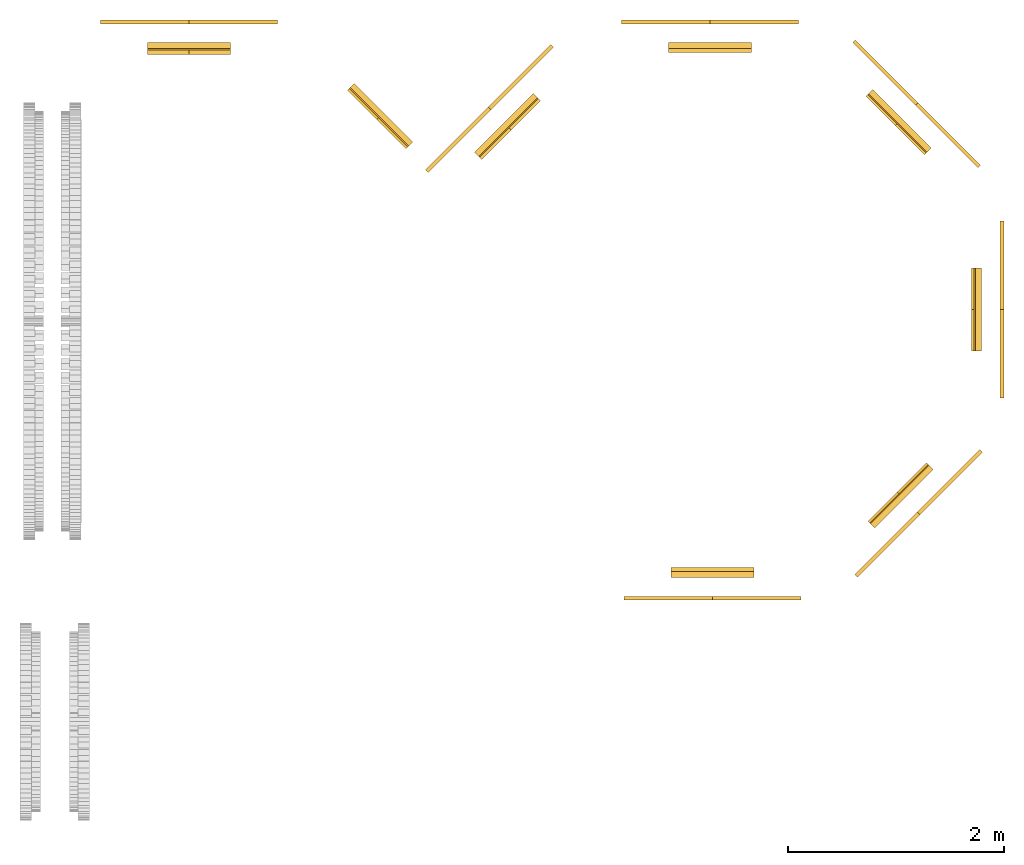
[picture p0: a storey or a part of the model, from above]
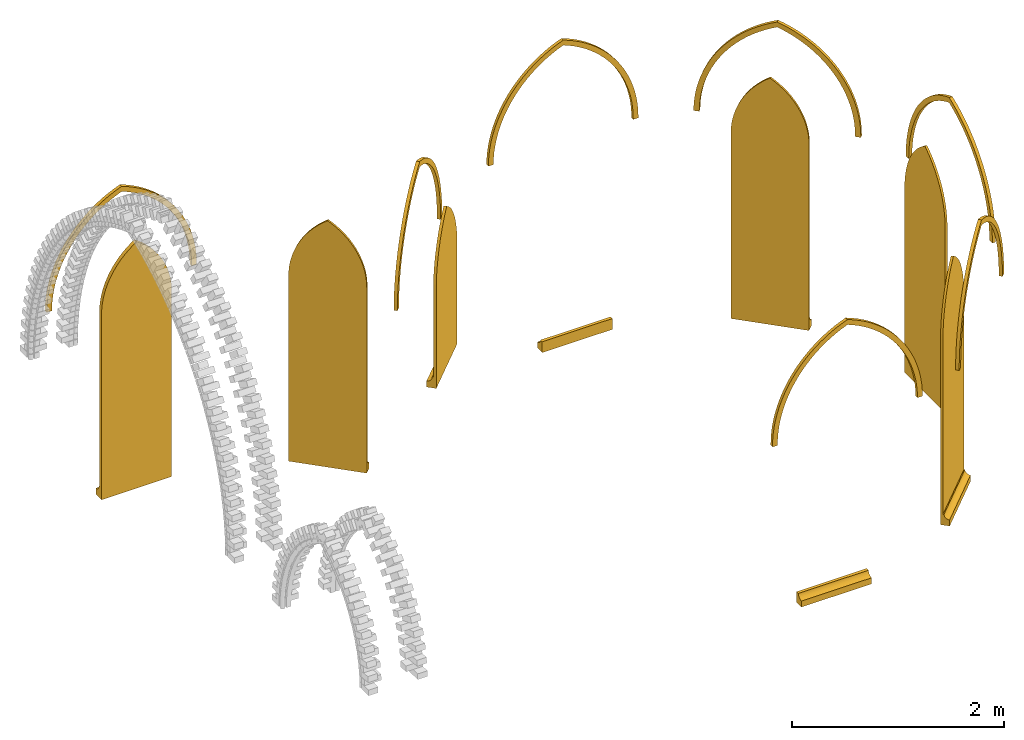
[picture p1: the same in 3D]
Properties of the parts of a building model (IFC2X3), part 1 of 7

# File
Description: ViewDefinition [CoordinationView_V2.0], ExchangeRequirement [Architecture]
File name: Church15_test3_reduced.ifc
Time: 2025-03-05T11:51:33+01:00
Written by: IfcOpenShell 0.8.0
Made in: Bonsai 0.8.0

# IfcProject, 2023_01
LongName: Church 14; Phase: Projekt Status; Document: EBENE 0 NAVE FFL PHASE 1 1864 PLAN; NORTH ELEVATION; PERSPECTIVE; EBENE -1 BASEMENT PHASE 6 PLAN; EBENE 2 GALLERY STAGE 1 PLAN; REFLECTED_PLAN_VIEW; NORTH SECTION; SOUTH SECTION; EAST SECTION; WEST SECTION; PLAN_VIEW

# IfcSite, Default
RefLatitude: 50, 4, 48, 569641; RefLongitude: 8, 14, 45, 631942; RefElevation: 0 m
ID-Daten - Gebäudebezeichnung: Englische Kirche
Sonstige - Auftraggeber: Church of St. Augustine, Wiesbaden; Kategorie: Projektinformationen; Projektadresse: Projektadresse; Projektausgabedatum: Projekt Datum; Projektname: Church 14; Projektnummer: 2023_01; Projektstatus: Projekt Status
Text - Bauherr: Church of St. Augustine; Baustellenort: Wiesbaden; Baustellenstraße: Frankfurter Straße 3; Kundenadresse: Frankfurter Straße 3; Kundenort: Wiesbaden

# IfcSite: Person_Man02_3D:Person_Man02_3D (3)
Material: <Unnamed>; Group: Modellgruppe:BasementChimney:6973904; Built Phase 1 1864
Abhängigkeiten - Ebene: Ebene 0 Nave FFL Phase 1 1864; Verschieben mit umliegenden Elementen: no; Basisbauteil: Ebene : Ebene 0 Nave FFL Phase 1 1864
Phasen - Phase erstellt: Phase 1 1864
Sonstige - Familie: Person_Man02_3D; Familie und Typ: Person_Man02_3D: Person_Man02_3D; Kategorie: Grundstück; Typ: Person_Man02_3D; Typ-ID: 7418376
Daten(Type) - Änderungsdatum: 20131219; Version: 1
ID-Daten(Type) - Typname: Person_Man02_3D
Sonstige(Type) - Kategorie: Grundstück; Familienname: Person_Man02_3D
Name (Person_Man02_3D:Person_Man02_3D:...) | Versatz von Host (m)
7418448 | 0
7684817 | 0
7684845 | 0.6

# IfcBuilding, Englische Kirche
LongName: Englische Kirche
Pset_BuildingCommon - NumberOfStoreys: 7; IsLandmarked: no
ID-Daten - Gebäudebezeichnung: Englische Kirche
Sonstige - Kategorie: Projektinformationen; Auftraggeber: Church of St. Augustine, Wiesbaden; Projektadresse: Projektadresse; Projektausgabedatum: Projekt Datum; Projektname: Church 14; Projektnummer: 2023_01; Projektstatus: Projekt Status
Text - Bauherr: Church of St. Augustine; Baustellenort: Wiesbaden; Baustellenstraße: Frankfurter Straße 3; Kundenadresse: Frankfurter Straße 3; Kundenort: Wiesbaden

# IfcBuildingStorey: Ebene:Ebene (6)
In: Englische Kirche
Pset_AirSideSystemInformation - sets with these values: 2
Pset_BuildingStoreyCommon - AboveGround: no
Sonstige - Familie: Ebene; Familie und Typ: Ebene: Ebene; Kategorie: Ebenen; Typ: Ebene; Typ-ID: 1266143
Abhängigkeiten(Type) - Basishöhe: Projekt-Basispunkt
Grafiken(Type) - Farbe: 16728128; Linienmuster: (Ebene); Linienstärke: 1; Symbol: Beschriftung Ebene Oberkante : Allgemein; Symbol bei Ende 1 Standard: no; Symbol bei Ende 2 Standard: yes
ID-Daten(Type) - Typname: Ebene
Sonstige(Type) - Kategorie: Ebenen; Familienname: Ebene
Name | LongName | Elevation (m) | Pset_AirSideSystemInformation, Name = ID-Daten, Name | Ansicht (m) | Höhe für Berechnung (m) | Tragwerk | Gebäudegeschoss
Ebene -1 Basement Phase 6 | Ebene -1 Basement Phase 6 | -3.075 | Ebene -2 Assumed Foundation | -4 | 0 | no | no
Ebene 0 Nave FFL Phase 1 1864 | Ebene 0 Nave FFL Phase 1 1864 | 0 | Ebene 0 Nave FFL Phase 1 1864 | 0 | 1 | no | yes | Daten - FM Geschoss: EG
Ebene 1 FFL Sacristy | Ebene 1 FFL Sacristy | 0.15 | Ebene 1 FFL Sacristy | 0.15 | 0 | no | yes
Ebene New Gallery Stage 6 | Ebene New Gallery Stage 6 | 3.61 | Ebene New Gallery Stage 6 | 3.61 | 0 | no | yes
Ebene 3 Belfry FFL Stage 2 1888 | Ebene 3 Belfry FFL Stage 2 1888 | 5.11 | Ebene 3 Belfry FFL Stage 2 1888 | 5.11 | 0 | no | yes
Ebene 2 Gallery Stage 1 | Ebene 2 Gallery Stage 1 | 6.75 | Ebene 2 Gallery Stage 1 | 6.75 | 1 | yes | yes | Daten - FM Geschoss: OG 2

# IfcAnnotation: DRAWING (11)
EPset_Drawing - Scale: 1/100; HumanScale: 1:100; HasLinework: yes; HasAnnotation: yes; GlobalReferencing: yes; Stylesheet: drawings/assets/default.css; Markers: drawings/assets/markers.svg; Symbols: drawings/assets/symbols.svg; Patterns: drawings/assets/patterns.svg; ShadingStyles: drawings/assets/shading_styles.json; CurrentShadingStyle: Blender Default
Name | Document | TargetView | HasUnderlay | Group
EBENE 0 NAVE FFL PHASE 1 1864 PLAN | X drawings/EBENE 0 NAVE FFL PHASE 1 1864 PLAN.svg | PLAN_VIEW | yes | EBENE 0 NAVE FFL PHASE 1 1864 PLAN
WEST ELEVATION.001 | X drawings/NORTH ELEVATION.svg | ELEVATION_VIEW | no | NORTH ELEVATION
PERSPECTIVE | X drawings/PERSPECTIVE.svg | MODEL_VIEW | no | PERSPECTIVE
EBENE -1 BASEMENT PHASE 6 PLAN | X drawings/EBENE -1 BASEMENT PHASE 6 PLAN.svg | PLAN_VIEW | yes | EBENE -1 BASEMENT PHASE 6 PLAN
EBENE 2 GALLERY STAGE 1 PLAN | X drawings/EBENE 2 GALLERY STAGE 1 PLAN.svg | PLAN_VIEW | no | EBENE 2 GALLERY STAGE 1 PLAN
REFLECTED_PLAN_VIEW | X drawings/REFLECTED_PLAN_VIEW.svg | REFLECTED_PLAN_VIEW | no | REFLECTED_PLAN_VIEW
NORTH SECTION | X drawings/NORTH SECTION.svg | SECTION_VIEW | no | NORTH SECTION
SOUTH SECTION | X drawings/SOUTH SECTION.svg | SECTION_VIEW | no | SOUTH SECTION
EAST SECTION | X drawings/EAST SECTION.svg | SECTION_VIEW | no | EAST SECTION
WEST SECTION | X drawings/WEST SECTION.svg | SECTION_VIEW | no | WEST SECTION
PLAN_VIEW | X drawings/PLAN_VIEW.svg | PLAN_VIEW | no | PLAN_VIEW

# IfcBuildingElementProxy: BasementLightwell:BasementLightwell (3)
In: Ebene -1 Basement Phase 6
Type - Material: <Unnamed>, Ortbeton - bewehrt (4)
Type - Abhängigkeiten - Vorgabe-Ansicht: 0 m
Type - Bemaßungen - CoverThickness: 0.05 m; SlabThickness: 0.15 m; WallThickness: 0.155 m; WellDepth: 0.85 m; WellLength: 1.89 m
Type - ID-Daten - Typname: BasementLightwell
Type - Materialien und Oberflächen - WellMaterial: Ortbeton - bewehrt
Type - Sonstige - Kategorie: Allgemeines Modell; Familienname: BasementLightwell
Pset_BuildingElementProxyCommon - Reference: BasementLightwell; sets with these values: 2
Pset_ProvisionForVoid - Width: 2.2 m; Height: 0.955 m; Depth: 0.15 m
Abhängigkeiten - Ebene: Foundation Wall Cap; Verschieben mit umliegenden Elementen: no
Bemaßungen - Breite: 1 m; Fläche: 8.435 m2; Länge: 2.08 m; Volumen: 0.8914 m3
Phasen - Phase erstellt: Phase 6 1966
Sonstige - Familie: BasementLightwell; Familie und Typ: BasementLightwell: BasementLightwell; Host-ID: 2621152; Typ: BasementLightwell; Typ-ID: 7719407
Name (BasementLightwell:BasementLightwell:...) | Material
7719432
7725785 | <Unnamed>, Ortbeton - bewehrt
7726030 | <Unnamed>, Ortbeton - bewehrt

# IfcBuildingElementProxy: LinedSquareOpening:945x1980, LinedSquareOpening:945x1980:5573793
In: Ebene -1 Basement Phase 6
Type - Material: <Unnamed> (3)
Type - Abhängigkeiten(Type) - Vorgabe-Ansicht: 0 m
Type - Bemaßungen(Type) - FrontEdgeSetback: 0.03 m; OpeningWidth: 0.945 m; RearEdgeSetback: 0.03 m; SideLiningThickness: 0.06 m; SpringingHeight: 1.98 m; TopLiningThickness: 0.08 m
Type - ID-Daten(Type) - Typname: 945x1980
Type - Sonstige(Type) - Kategorie: Allgemeines Modell; Familienname: LinedSquareOpening
Pset_BuildingElementProxyCommon - Reference: 945x1980; sets with these values: 2
Pset_ProvisionForVoid - Shape: Rectangle; Width: 1.98 m; Height: 1.065 m; Depth: 1.9 m
Abhängigkeiten - Ebene: Ebene -1 Basement Phase 6; Höhe von Ebene: 0 m
Bemaßungen - Fläche: 0.5158 m2; Volumen: 0.012528 m3
Phasen - Phase erstellt: Phase 7 2019
Sonstige - Kategorie: Allgemeines Modell; Familie: LinedSquareOpening; Familie und Typ: LinedSquareOpening: 945x1980; Host-ID: 2555536; Typ: 945x1980; Typ-ID: 5573766

# IfcBuildingElementProxy: PierCorbel:PierCorbel 780 (5)
In: Ebene New Gallery Stage 6
Type - Material: Mauerwerk - Sandstein Rot
Type - Abhängigkeiten - Vorgabe-Ansicht: 0 m
Type - Bemaßungen - CorbelBreite: 0.78 m
Type - ID-Daten - Typname: PierCorbel 780
Type - Materialien und Oberflächen - CorbelMaterial: Mauerwerk - Sandstein Rot
Type - Sonstige - Kategorie: Allgemeines Modell; Familienname: PierCorbel
Pset_BuildingElementProxyCommon - Reference: PierCorbel 780; sets with these values: 2
Pset_ProvisionForVoid - Depth: 0.78 m
Abhängigkeiten - Höhe von Ebene: 0 m; Verschieben mit umliegenden Elementen: no; Versatz von Host: 0 m; Basisbauteil: Ebene : East Buttress Pier Cap Underside; Ebene: East Buttress Pier Cap Underside
Bemaßungen - Fläche: 0.657237 m2; Volumen: 0.0666393 m3
Sonstige - Familie: PierCorbel; Familie und Typ: PierCorbel: PierCorbel 780; Typ: PierCorbel 780; Typ-ID: 5213824
Name (PierCorbel:PierCorbel 780:...) | Phase erstellt | Group
5410019 | Phase 2 1888 | Built Phase 2 1888
6971017 | Phase 7 2019
6971034 | Phase 7 2019
7248189 | Phase 2 1888 | Built Phase 2 1888
7606754 | Phase 2 1888 | Built Phase 2 1888

# IfcBuildingElementProxy: Profilierte Wand:moulding1-Dado (13)
In: Ebene -1 Basement Phase 6
Type - Abhängigkeiten - Entlang eingefügter Elemente schneiden: no; Schneidet Wand: yes; Standardrücksprung: 0 m
Type - ID-Daten - Typname: moulding1-Dado
Type - Konstruktion - Profil: Mouldings : Moulding1
Type - Materialien und Oberflächen - Material: Mauerwerk - Sandstein Rot
Type - Sonstige - Kategorie: Wände: Profilierte Wände; Familienname: Profilierte Wand
Pset_BuildingElementProxyCommon - Reference: moulding1-Dado; sets with these values: 2
Sonstige - Familie: Profilierte Wand; Familie und Typ: Profilierte Wand: moulding1-Dado; Typ: moulding1-Dado; Typ-ID: 2478616
Name (Profilierte Wand:moulding1-Dado:...) | Shape | Depth (m) | Ebene | Versatz von Wand (m) | Versatz von Ebene (m) | Länge (m) | Phase erstellt | Group
3293627 | Undefined | 0.679767 | Foundation Wall Cap | 0 | 1.85 | 0.679767 | Phase 1 1864 | Modellgruppe:BasementChimney:6973904; Built Phase 1 1864
3350023 | Undefined | 0.820746 | Foundation Wall Cap | 0 | 1.85 | 0.820746 | Phase 2 1888 | Built Phase 2 1888
3350297 |  |  | Foundation Wall Cap | 0 | 1.85 | 0.802678 | Phase 2 1888 | Built Phase 2 1888
3842606 | Undefined | 2.4785 | Ebene -2 Assumed Foundation | 0.329921 | 12.7142 | 2.4785 | Phase 2 1888 | Built Phase 2 1888
3843715 | Undefined | 3.285 | Ebene -2 Assumed Foundation | 0 | 12.714 | 3.285 | Phase 2 1888 | Built Phase 2 1888
5171951 | Undefined | 0.652471 | Foundation Wall Cap | 0 | 1.85 | 0.652471 | Phase 1 1864 | Modellgruppe:BasementChimney:6973904; Built Phase 1 1864
5440317 | Undefined | 0.683273 | Foundation Wall Cap | 0 | 1.85 | 0.683273 | Phase 2 1888 | Built Phase 2 1888
5468029 |  |  | Foundation Wall Cap | 0 | 1.85 | 0.37 | Phase 2 1888 | Built Phase 2 1888
5469648 | Undefined | 0.78 | Foundation Wall Cap | 0 | 1.83126 | 0.78 | Phase 2 1888 | Built Phase 2 1888
6261976 | Rectangle | 0.78 | Foundation Wall Cap | 0 | 1.85 | 0.78 | Phase 2 1888 | Built Phase 2 1888
6326100 | Rectangle | 0.964989 | Foundation Wall Cap | 0 | 1.85 | 0.964989 | Phase 2 1888 | Built Phase 2 1888
6379899 | Rectangle | 0.522744 | Foundation Wall Cap | 0 | 9.314 | 0.522744 | Phase 2 1888 | Built Phase 2 1888
6441138 | Rectangle | 0.522744 | Foundation Wall Cap | 0 | 9.314 | 0.522744 | Phase 6 1966

# IfcBuildingElementProxy: Profilierte Wand:moulding1-Dado 2, Profilierte Wand:moulding1-Dado 2:5211551
In: Ebene -1 Basement Phase 6
Type - Abhängigkeiten - Entlang eingefügter Elemente schneiden: no; Schneidet Wand: yes; Standardrücksprung: 0 m
Type - ID-Daten - Typname: moulding1-Dado 2
Type - Konstruktion - Profil: Testmouldingdeep : Testmouldingdeep
Type - Materialien und Oberflächen - Material: Mauerwerk - Sandstein Rot
Type - Sonstige - Kategorie: Wände: Profilierte Wände; Familienname: Profilierte Wand
Pset_BuildingElementProxyCommon - Reference: moulding1-Dado 2; sets with these values: 2
Pset_ProvisionForVoid - Shape: Undefined; Depth: 0.5185 m
Abhängigkeiten - Ebene: Foundation Wall Cap; Versatz von Wand: 0 m; Versatz von Ebene: 9.40503 m
Bemaßungen - Länge: 0.5185 m
Phasen - Phase erstellt: Phase 1 1864
Sonstige - Familie: Profilierte Wand; Familie und Typ: Profilierte Wand: moulding1-Dado 2; Typ: moulding1-Dado 2; Typ-ID: 3154429
Group: Modellgruppe:BasementChimney:6973904; Built Phase 1 1864

# IfcBuildingElementProxy: Profilierte Wand:moulding1-Dado brick Stage 2 (3)
In: Ebene -1 Basement Phase 6
Type - Abhängigkeiten - Entlang eingefügter Elemente schneiden: no; Schneidet Wand: yes; Standardrücksprung: 0 m
Type - ID-Daten - Typname: moulding1-Dado brick Stage 2
Type - Konstruktion - Profil: Mouldings : Moulding1
Type - Materialien und Oberflächen - Material: Mauerwerk - Sichtmauerwerk_72x265 header Stage2
Type - Sonstige - Kategorie: Wände: Profilierte Wände; Familienname: Profilierte Wand
Pset_BuildingElementProxyCommon - Reference: moulding1-Dado brick Stage 2; sets with these values: 2
Abhängigkeiten - Ebene: Foundation Wall Cap; Versatz von Wand: 0 m; Versatz von Ebene: 1.85 m
Phasen - Phase erstellt: Phase 2 1888
Sonstige - Familie: Profilierte Wand; Familie und Typ: Profilierte Wand: moulding1-Dado brick Stage 2; Typ: moulding1-Dado brick Stage 2; Typ-ID: 3503855
Group: Built Phase 2 1888
Name (Profilierte Wand:moulding1-Dado brick Stage 2:...) | Länge (m)
3491269 | 2.18352
3504058 | 1.68025 | Pset_ProvisionForVoid - Shape: Undefined; Depth: 1.68025 m
6983100 | 2.44361

# IfcBuildingElementProxy: Profilierte Wand:plinth (39)
In: Ebene -1 Basement Phase 6
Type - Abhängigkeiten - Entlang eingefügter Elemente schneiden: no; Schneidet Wand: yes; Standardrücksprung: 0 m
Type - ID-Daten - Typname: plinth
Type - Konstruktion - Profil: Plinth profile : plinth
Type - Materialien und Oberflächen - Material: Mauerwerk - Sandstein Rot
Type - Sonstige - Kategorie: Wände: Profilierte Wände; Familienname: Profilierte Wand
Pset_BuildingElementProxyCommon - Reference: plinth; sets with these values: 2
Abhängigkeiten - Versatz von Wand: 0 m
Sonstige - Familie: Profilierte Wand; Familie und Typ: Profilierte Wand: plinth; Typ: plinth; Typ-ID: 2475856
Name (Profilierte Wand:plinth:...) | Ebene | Versatz von Ebene (m) | Länge (m) | Phase erstellt | Group
2477548 | Foundation Wall Cap | 0.505 | 3.38424 | Phase 1 1864 | Modellgruppe:BasementChimney:6973904; Built Phase 1 1864
2720928 | Plinth moulding Underside | 0 | 0.445057 | Phase 2 1888 | Built Phase 2 1888
2890806 | Foundation Wall Cap | 0.505 | 1.82 | Phase 2 1888 | Built Phase 2 1888
3022505 | Foundation Wall Cap | 0.505 | 1.81 | Phase 1 1864 | Modellgruppe:BasementChimney:6973904; Built Phase 1 1864
3022587 | Foundation Wall Cap | 0.505 | 0.78 | Phase 1 1864 | Modellgruppe:BasementChimney:6973904; Built Phase 1 1864
3038055 | Foundation Wall Cap | 0.505 | 0.456454 | Phase 1 1864 | Modellgruppe:BasementChimney:6973904; Built Phase 1 1864
3154773 | Foundation Wall Cap | 0.505 | 0.693949 | Phase 1 1864 | Modellgruppe:BasementChimney:6973904; Built Phase 1 1864
3256990 | Foundation Wall Cap | 0.505 | 1.03 | Phase 1 1864 | Modellgruppe:BasementChimney:6973904; Built Phase 1 1864
3257177 | Foundation Wall Cap | 0.505 | 0.78 | Phase 1 1864 | Modellgruppe:BasementChimney:6973904; Built Phase 1 1864
3257415 | Foundation Wall Cap | 0.505 | 1.42 | Phase 1 1864 | Modellgruppe:BasementChimney:6973904; Built Phase 1 1864
3257546 | Foundation Wall Cap | 0.505 | 0.425 | Phase 1 1864 | Modellgruppe:BasementChimney:6973904; Built Phase 1 1864
3257552 | Foundation Wall Cap | 0.505 | 0.424 | Phase 1 1864 | Modellgruppe:BasementChimney:6973904; Built Phase 1 1864
3257558 | Foundation Wall Cap | 0.505 | 0.36 | Phase 1 1864 | Modellgruppe:BasementChimney:6973904; Built Phase 1 1864
3261107 | Foundation Wall Cap | 0.505 | 1.00087 | Phase 1 1864 | Modellgruppe:BasementChimney:6973904; Built Phase 1 1864
3265432 | Foundation Wall Cap | 0.505 | 1.69682 | Phase 1 1864 | Modellgruppe:BasementChimney:6973904; Built Phase 1 1864
3266623 | Foundation Wall Cap | 0.505 | 0.699648 | Phase 1 1864 | Modellgruppe:BasementChimney:6973904; Built Phase 1 1864
3266629 | Foundation Wall Cap | 0.505 | 0.76 | Phase 1 1864 | Modellgruppe:BasementChimney:6973904; Built Phase 1 1864
3288775 | Foundation Wall Cap | 0.505 | 0.707719 | Phase 1 1864 | Modellgruppe:BasementChimney:6973904; Built Phase 1 1864
3288781 | Foundation Wall Cap | 0.505 | 1.68262 | Phase 1 1864 | Modellgruppe:BasementChimney:6973904; Built Phase 1 1864
3289366 | Foundation Wall Cap | 0.505 | 0.76 | Phase 1 1864 | Modellgruppe:BasementChimney:6973904; Built Phase 1 1864
3292115 | Foundation Wall Cap | 0.505 | 0.687711 | Phase 1 1864 | Modellgruppe:BasementChimney:6973904; Built Phase 1 1864
3292251 | Plinth moulding Underside | 0 | 1.68739 | Phase 1 1864 | Modellgruppe:BasementChimney:6973904; Built Phase 1 1864
3292386 | Plinth moulding Underside | 0 | 0.708381 | Phase 1 1864 | Modellgruppe:BasementChimney:6973904; Built Phase 1 1864
3292464 | Plinth moulding Underside | 0 | 0.76 | Phase 1 1864 | Modellgruppe:BasementChimney:6973904; Built Phase 1 1864
3292675 | Plinth moulding Underside | 0 | 0.670403 | Phase 1 1864 | Modellgruppe:BasementChimney:6973904; Built Phase 1 1864
3292976 | Plinth moulding Underside | 0 | 1.4298 | Phase 1 1864 | Modellgruppe:BasementChimney:6973904; Built Phase 1 1864
3293215 | Foundation Wall Cap | 0.505 | 0.780178 | Phase 1 1864 | Modellgruppe:BasementChimney:6973904; Built Phase 1 1864
3293221 | Plinth moulding Underside | 0 | 1.03 | Phase 1 1864 | Modellgruppe:BasementChimney:6973904; Built Phase 1 1864
3293227 | Plinth moulding Underside | 0 | 0.97983 | Phase 1 1864 | Modellgruppe:BasementChimney:6973904; Built Phase 1 1864
3493945 | Foundation Wall Cap | 0.505 | 3.935 | Phase 2 1888 | Built Phase 2 1888
3493989 | Foundation Wall Cap | 0.505 | 0.78 | Phase 2 1888 | Built Phase 2 1888
3493995 | Foundation Wall Cap | 0.505 | 1.03 | Phase 2 1888 | Built Phase 2 1888
4251157 | Foundation Wall Cap | 0.505 | 0.755 | Phase 1 1864 | Modellgruppe:BasementChimney:6973904; Built Phase 1 1864
4251164 | Foundation Wall Cap | 0.505 | 0.456454 | Phase 1 1864 | Modellgruppe:BasementChimney:6973904; Built Phase 1 1864
5144821 | Foundation Wall Cap | 0.505 | 1.43 | Phase 1 1864 | Modellgruppe:BasementChimney:6973904; Built Phase 1 1864
5416097 | Foundation Wall Cap | 0.505 | 1.02731 | Phase 2 1888 | Built Phase 2 1888
5416720 | Foundation Wall Cap | 0.505 | 0.817988 | Phase 2 1888 | Built Phase 2 1888
5437947 | Foundation Wall Cap | 0.505 | 0.726012 | Phase 2 1888 | Built Phase 2 1888
7228845 | Plinth moulding Underside | 0 | 1.00925 | Phase 1 1864 | Modellgruppe:BasementChimney:6973904; Built Phase 1 1864

# IfcBuildingElementProxy: Profilierte Wand:plinth brick header (29)
In: Ebene -1 Basement Phase 6
Type - Abhängigkeiten - Entlang eingefügter Elemente schneiden: no; Schneidet Wand: yes; Standardrücksprung: 0 m
Type - ID-Daten - Typname: plinth brick header
Type - Konstruktion - Profil: Plinth profile : plinth
Type - Materialien und Oberflächen - Material: Mauerwerk - Sichtmauerwerk_72x265 header Stage2
Type - Sonstige - Kategorie: Wände: Profilierte Wände; Familienname: Profilierte Wand
Pset_BuildingElementProxyCommon - Reference: plinth brick header; sets with these values: 2
Phasen - Phase erstellt: Phase 2 1888
Sonstige - Familie: Profilierte Wand; Familie und Typ: Profilierte Wand: plinth brick header; Typ: plinth brick header; Typ-ID: 5467336
Group: Built Phase 2 1888
Name (Profilierte Wand:plinth brick header:...) | Versatz von Wand (m) | Ebene | Versatz von Ebene (m) | Länge (m)
2580270 | 0 | Plinth moulding Underside | 0 | 0.713
2580488 | 0 | Foundation Wall Cap | 0.505 | 0.651
2609190 | 0 | Plinth moulding Underside | 0 | 0.6065
2717564 | 0 | Plinth moulding Underside | 0 | 1.5659
3470122 | 0 | Plinth moulding Underside | 0 | 1.53925
3489360 | 0 | Plinth moulding Underside | 0 | 1.63956
3489601 | 0.0025 | Foundation Wall Cap | 0.505 | 0.668766
3489795 | 0.00249463 | Plinth moulding Underside | 0 | 0.668766
3489802 | 0 | Foundation Wall Cap | 0.505 | 0.651
3489808 | 0.00250457 | Foundation Wall Cap | 0.505 | 0.677564
3489814 | 0 | Foundation Wall Cap | 0.505 | 1.54413
3490135 | -0.00161688 | Foundation Wall Cap | 0.505 | 0.667564
3490291 | 0 | Foundation Wall Cap | 0.505 | 0.662564
3490297 | 0 | Foundation Wall Cap | 0.505 | 1.60782
3490319 | 0 | Foundation Wall Cap | 0.505 | 0.715817
3490465 | 0 | Foundation Wall Cap | 0.505 | 0.651
3490515 | 0.0025 | Foundation Wall Cap | 0.505 | 0.755603
4197462 | 0.00249183 | Foundation Wall Cap | 0.505 | 0.677564
5486545 | 0 | Foundation Wall Cap | 0.505 | 0.650966
7054224 | 0 | Plinth moulding Underside | 0 | 0.438
7055686 | 0 | Plinth moulding Underside | 0 | 0.642
7055712 | 0 | Plinth moulding Underside | 0 | 0.651
7055718 | 0 | Plinth moulding Underside | 0 | 0.714488
7061094 | 0 | Plinth moulding Underside | 0 | 0.651
7061100 | 0 | Plinth moulding Underside | 0 | 0.708
7061186 | 0 | Plinth moulding Underside | 0 | 0.64
7074078 | 0 | Foundation Wall Cap | 0.505 | 1.61191
7074116 | 0 | Plinth moulding Underside | 0 | 1.55821
7229687 | 0 | Plinth moulding Underside | 0 | 0.651

# IfcBuildingElementProxy: SimpleVault:SimpleVault Tower, SimpleVault:SimpleVault Tower:5528813
In: Ebene -1 Basement Phase 6
Type - Material: Mauerwerk - Sichtmauerwerk_72x265 english bond Stage2
Type - Abhängigkeiten - Vorgabe-Ansicht: 0 m
Type - Bemaßungen - OverallHeight: 0.5 m; SideWidth: 1.68 m; SideWidth2: 1.68 m; VaultLength: 2.35 m; VaultRadius: 2.39 m; VaultWidth: 2.365 m
Type - ID-Daten - Typname: SimpleVault Tower
Type - Materialien und Oberflächen - VaultMaterial: Mauerwerk - Sichtmauerwerk_72x265 english bond Stage2
Type - Sonstige - Kategorie: Allgemeines Modell; Familienname: SimpleVault
Pset_BuildingElementProxyCommon - Reference: SimpleVault Tower; sets with these values: 2
Abhängigkeiten - Ebene: Ebene -1 Basement Phase 6; Verschieben mit umliegenden Elementen: no; Basisbauteil: Geschossdecke : STB 200 Basement Kitchen Floor; Höhe von Ebene: 2.42823 m; Versatz von Host: 2.42823 m
Bemaßungen - Fläche: 7.0779 m2; Volumen: 1.50176 m3
Phasen - Phase erstellt: Phase 2 1888
Sonstige - Familie: SimpleVault; Familie und Typ: SimpleVault: SimpleVault Tower; Typ: SimpleVault Tower; Typ-ID: 5528982
Group: Built Phase 2 1888

# IfcBuildingElementProxy: SpiralSteps:SpiralSteps, SpiralSteps:SpiralSteps:4031563
In: Ebene 0 Nave FFL Phase 1 1864
Type - Material: <Unnamed> (108)
Type - Abhängigkeiten - Vorgabe-Ansicht: 0 m
Type - Bemaßungen - RiserHeight: 0.25 m
Type - ID-Daten - Typname: SpiralSteps
Type - Sonstige - Kategorie: Allgemeines Modell; Familienname: SpiralSteps
Pset_BuildingElementProxyCommon - Reference: SpiralSteps; sets with these values: 2
Pset_ProvisionForVoid - Depth: 0.25 m
Abhängigkeiten - Ebene: Ebene 0 Nave FFL Phase 1 1864; Höhe von Ebene: 0 m; Verschieben mit umliegenden Elementen: no; Versatz von Host: 0 m; Basisbauteil: Ebene : Ebene 0 Nave FFL Phase 1 1864
Bemaßungen - Fläche: 20.1719 m2; Volumen: 0.501697 m3
Phasen - Phase erstellt: Phase 1 1864; Phase abgebrochen: Phase 6 1966
Sonstige - Familie: SpiralSteps; Familie und Typ: SpiralSteps: SpiralSteps; Typ: SpiralSteps; Typ-ID: 4031511
Group: Modellgruppe:BasementChimney:6973904; Built Phase 1 1864

# IfcBuildingElementProxy: Tower_finial:Tower_finial (4)
In: Ebene 0 Nave FFL Phase 1 1864
Type - Material: Mauerwerk - Sandstein Rot, Mauerwerk - Sichtmauerwerk_72x265 english bond Stage2
Type - Abhängigkeiten - Vorgabe-Ansicht: 0 m
Type - Bemaßungen - Depth: 0.5 m; HeightBrickwork: 1.295 m; Width: 0.5 m
Type - ID-Daten - Typname: Tower_finial
Type - Materialien und Oberflächen - BrickworkMaterial: Mauerwerk - Sichtmauerwerk_72x265 english bond Stage2; StoneworkMaterial: Mauerwerk - Sandstein Rot
Type - Sonstige - Kategorie: Allgemeines Modell; Familienname: Tower_finial
Type - Pset_ProvisionForVoid - Width: 0.5 m; Depth: 0.5 m
Pset_BuildingElementProxyCommon - Reference: Tower_finial; sets with these values: 2
Pset_ProvisionForVoid - Width: 0.1524 m; Height: 0.5 m
Abhängigkeiten - Ebene: Ebene 0 Nave FFL Phase 1 1864; Verschieben mit umliegenden Elementen: no; Basisbauteil: Ebene : Ebene 0 Nave FFL Phase 1 1864; Höhe von Ebene: 15.594 m; Versatz von Host: 15.594 m
Bemaßungen - Fläche: 2.76293 m2; Volumen: 0.565732 m3
Phasen - Phase erstellt: Phase 2 1888
Sonstige - Familie: Tower_finial; Familie und Typ: Tower_finial: Tower_finial; Typ: Tower_finial; Typ-ID: 7803290
Group: Built Phase 2 1888
Name (Tower_finial:Tower_finial:...)
7804210
7804757
7804760
7804762

# IfcBuildingElementProxy: Vault_1:Vault_1, Vault_1:Vault_1:7986884
In: Ebene 0 Nave FFL Phase 1 1864
Type - Material: <Unnamed> (14)
Type - Abhängigkeiten - Vorgabe-Ansicht: 0 m
Type - ID-Daten - Typname: Vault_1
Type - Sonstige - Kategorie: Allgemeines Modell; Familienname: Vault_1
Pset_BuildingElementProxyCommon - Reference: Vault_1; sets with these values: 2
Abhängigkeiten - Ebene: Ebene 0 Nave FFL Phase 1 1864; Verschieben mit umliegenden Elementen: no; Basisbauteil: Ebene : Ebene 0 Nave FFL Phase 1 1864; Höhe von Ebene: 2.56 m; Versatz von Host: 2.56 m
Bemaßungen - Fläche: 25.9017 m2; SpringingHeight: 2.7 m; VaultWidth: 2.5 m; Volumen: 2.04915 m3
Phasen - Phase erstellt: Phase 1 1864
Sonstige - Familie: Vault_1; Familie und Typ: Vault_1: Vault_1; Typ: Vault_1; Typ-ID: 7986406
Group: Modellgruppe:BasementChimney:6973904; Built Phase 1 1864

# IfcBuildingElementProxy: VergeCopingEnd:VergeCopingEnd (3)
In: Ebene 2 Gallery Stage 1
Type - Material: Mauerwerk - Sandstein Rot
Type - Abhängigkeiten - Vorgabe-Ansicht: 0 m
Type - Bemaßungen - CopingHeight: 0.3 m; CopingWidth: 1.36 m
Type - ID-Daten - Typname: VergeCopingEnd
Type - Materialien und Oberflächen - VergeCoping: Mauerwerk - Sandstein Rot
Type - Sonstige - Kategorie: Allgemeines Modell; Familienname: VergeCopingEnd
Pset_BuildingElementProxyCommon - Reference: VergeCopingEnd; sets with these values: 2
Abhängigkeiten - Verschieben mit umliegenden Elementen: no; Ebene: Eaves corner pier top; Basisbauteil: Ebene : Eaves corner pier top
Bemaßungen - Fläche: 1.77369 m2; Volumen: 0.277278 m3
Phasen - Phase erstellt: Phase 1 1864
Sonstige - Familie: VergeCopingEnd; Familie und Typ: VergeCopingEnd: VergeCopingEnd; Typ: VergeCopingEnd; Typ-ID: 5252002
Group: Modellgruppe:BasementChimney:6973904; Built Phase 1 1864
Name (VergeCopingEnd:VergeCopingEnd:...) | Höhe von Ebene (m) = Versatz von Host (m)
6982375 | -0.00160627
6983242 | 0
6983282 | 0

# IfcBuildingElementProxy: WallCorbelStage2:WallCorbelStage2 (3)
In: Ebene 0 Nave FFL Phase 1 1864
Type - Material: Quoin Brick (9)
Type - Abhängigkeiten - Vorgabe-Ansicht: 0 m
Type - Bemaßungen - BreitePilaster: 0.52 m; HoeheUKCorbel: 3.534 m
Type - ID-Daten - Typname: WallCorbelStage2
Type - Materialien und Oberflächen - CorbelMaterial: Quoin Brick
Type - Sonstige - Kategorie: Allgemeines Modell; Familienname: WallCorbelStage2
Pset_BuildingElementProxyCommon - Reference: WallCorbelStage2; sets with these values: 2
Pset_ProvisionForVoid - Width: 0.56 m; Height: 0.08 m; Depth: 0.072 m
Abhängigkeiten - Ebene: Ebene 0 Nave FFL Phase 1 1864; Verschieben mit umliegenden Elementen: no; Höhe von Ebene: 0.228 m; Versatz von Host: 0.228 m
Bemaßungen - Fläche: 1.60413 m2; Volumen: 0.0672083 m3
Phasen - Phase erstellt: Phase 2 1888
Sonstige - Familie: WallCorbelStage2; Familie und Typ: WallCorbelStage2: WallCorbelStage2; Typ: WallCorbelStage2; Typ-ID: 4388655
Group: Built Phase 2 1888
Name (WallCorbelStage2:WallCorbelStage2:...) | Basisbauteil | Material
4389294 | Ebene : Ebene 0 Nave FFL Phase 1 1864
4389487 | Geschossdecke : Tiled Marble onto screed 203x203 black and white diagonal | Quoin Brick
5518495 | Ebene : Ebene 0 Nave FFL Phase 1 1864 | Quoin Brick

# IfcBuildingElementProxy: basementWindow1:1810x1200, basementWindow1:1810x1200:5571185
In: Ebene -1 Basement Phase 6
Type - Material: <Unnamed> (3)
Type - Abhängigkeiten(Type) - Vorgabe-Ansicht: 0 m
Type - Bemaßungen(Type) - ArchitraveWidth: 0.02 m; CillHeight: 1 m; LintelHeight: 2 m; OpeningWidth: 1.81 m; RenderCoat: 0.005 m; RevealOffset: 0.03 m
Type - ID-Daten(Type) - Typname: 1810x1200
Type - Sonstige(Type) - Kategorie: Allgemeines Modell; Familienname: basementWindow1
Pset_BuildingElementProxyCommon - Reference: 1810x1200; sets with these values: 2
Pset_ProvisionForVoid - Shape: Rectangle; Width: 1 m; Height: 1.81 m
Abhängigkeiten - Ebene: Ebene -1 Basement Phase 6; Höhe von Ebene: 1.54 m
Bemaßungen - ClearWidth: 1.8 m; Fläche: 2.7723 m2; Volumen: 0.031932 m3
Phasen - Phase erstellt: Phase 6 1966
Sonstige - Kategorie: Allgemeines Modell; Familie: basementWindow1; Familie und Typ: basementWindow1: 1810x1200; Host-ID: 6989205; Typ: 1810x1200; Typ-ID: 5618222

# IfcBuildingElementProxy: basementWindow1:1810x1310, basementWindow1:1810x1310:5571416
In: Ebene -1 Basement Phase 6
Type - Material: <Unnamed> (3)
Type - Abhängigkeiten(Type) - Vorgabe-Ansicht: 0 m
Type - Bemaßungen(Type) - ArchitraveWidth: 0.02 m; CillHeight: 1 m; LintelHeight: 2.22 m; OpeningWidth: 1.81 m; RenderCoat: 0.002 m; RevealOffset: 0.03 m
Type - ID-Daten(Type) - Typname: 1810x1310
Type - Sonstige(Type) - Kategorie: Allgemeines Modell; Familienname: basementWindow1
Pset_BuildingElementProxyCommon - Reference: 1810x1310; sets with these values: 2
Pset_ProvisionForVoid - Shape: Rectangle; Width: 1.22 m; Height: 1.814 m
Abhängigkeiten - Ebene: Ebene -1 Basement Phase 6; Höhe von Ebene: 1.5 m
Bemaßungen - ClearWidth: 1.81 m; Fläche: 3.25956 m2; Volumen: 0.0286552 m3
Phasen - Phase erstellt: Phase 6 1966
Sonstige - Kategorie: Allgemeines Modell; Familie: basementWindow1; Host-ID: 6989205; Familie und Typ: basementWindow1: 1810x1310; Typ: 1810x1310; Typ-ID: 5571433

# IfcBuildingElementProxy: basementWindow1:1930x1310, basementWindow1:1930x1310:5575437
In: Ebene -1 Basement Phase 6
Type - Material: <Unnamed> (3)
Type - Abhängigkeiten(Type) - Vorgabe-Ansicht: 0 m
Type - Bemaßungen(Type) - ArchitraveWidth: 0.02 m; CillHeight: 1 m; LintelHeight: 2.218 m; OpeningWidth: 1.95 m; RenderCoat: 0.005 m; RevealOffset: 0.03 m
Type - ID-Daten(Type) - Typname: 1930x1310
Type - Sonstige(Type) - Kategorie: Allgemeines Modell; Familienname: basementWindow1
Pset_BuildingElementProxyCommon - Reference: 1930x1310; sets with these values: 2
Pset_ProvisionForVoid - Shape: Rectangle; Width: 1.218 m; Height: 1.81 m
Abhängigkeiten - Ebene: Ebene -1 Basement Phase 6; Höhe von Ebene: 1.525 m
Bemaßungen - ClearWidth: 1.8 m; Fläche: 3.26716 m2; Volumen: 0.0358342 m3
Phasen - Phase erstellt: Phase 6 1966
Sonstige - Kategorie: Allgemeines Modell; Familie: basementWindow1; Host-ID: 6989205; Familie und Typ: basementWindow1: 1930x1310; Typ: 1930x1310; Typ-ID: 5580078

# IfcColumn: AisleColumn:AisleColumn, AisleColumn:AisleColumn:4320104
In: Ebene 0 Nave FFL Phase 1 1864
Type - PredefinedType: COLUMN; Material: Mauerwerk - Sandstein Rot (5), Quoin Brick
Type - Bemaßungen - Breite: 0.65 m; HoeheCapital: 0.625 m; HoeheLowerBase: 0.22 m; HoeheUKCapital: 3.64 m; HoeheUpperBase: 0.16 m; RadiusColumn: 0.26 m; Tiefe: 0.65 m
Type - Grafiken - Farbfüllung für groben Maßstab: 0
Type - ID-Daten - OmniClass-Nummer: 23.25.30.11.14.11; OmniClass-Titel: Columns; Typname: AisleColumn
Type - Materialien und Oberflächen - ColumnCapMaterial: Quoin Brick; ColumnMaterial: Mauerwerk - Sandstein Rot
Type - Sonstige - Kategorie: Stützen; Familienname: AisleColumn
Type - Pset_ColumnCommon - IsExternal: no
Pset_ColumnCommon - Reference: AisleColumn
Pset_QuantityTakeOff - Reference: AisleColumn; sets with these values: 2
Abhängigkeiten - Versatz unten: 0 m; Raumbegrenzung: no; Versatz oben: 0 m; Ebene: Ebene 0 Nave FFL Phase 1 1864; Basisebene: Ebene 0 Nave FFL Phase 1 1864; Oberste Ebene: Ebene 0 Nave FFL Phase 1 1864; Verschieben mit Raster: yes
Bemaßungen - OverallHeight: 4.265 m; Volumen: 0.135745 m3
Phasen - Phase erstellt: Phase 2 1888
Sonstige - Familie: AisleColumn; Familie und Typ: AisleColumn: AisleColumn; Typ: AisleColumn; Typ-ID: 4318990
Group: Built Phase 2 1888

# IfcColumn: AisleColumn:AisleColumn, AisleColumn:AisleColumn:4320242
In: Ebene 0 Nave FFL Phase 1 1864
Type - PredefinedType: COLUMN; Material: Mauerwerk - Sandstein Rot (6), Quoin Brick
Type - Bemaßungen - Breite: 0.65 m; HoeheCapital: 0.625 m; HoeheLowerBase: 0.22 m; HoeheUKCapital: 3.64 m; HoeheUpperBase: 0.16 m; RadiusColumn: 0.26 m; Tiefe: 0.65 m
Type - Grafiken - Farbfüllung für groben Maßstab: 0
Type - ID-Daten - OmniClass-Nummer: 23.25.30.11.14.11; OmniClass-Titel: Columns; Typname: AisleColumn
Type - Materialien und Oberflächen - ColumnCapMaterial: Quoin Brick; ColumnMaterial: Mauerwerk - Sandstein Rot
Type - Sonstige - Kategorie: Stützen; Familienname: AisleColumn
Type - Pset_ColumnCommon - IsExternal: no
Pset_ColumnCommon - Reference: AisleColumn
Pset_QuantityTakeOff - Reference: AisleColumn; sets with these values: 2
Abhängigkeiten - Raumbegrenzung: yes; Versatz unten: 0 m; Versatz oben: 0 m; Ebene: Ebene 0 Nave FFL Phase 1 1864; Basisebene: Ebene 0 Nave FFL Phase 1 1864; Oberste Ebene: Ebene 0 Nave FFL Phase 1 1864; Verschieben mit Raster: yes
Bemaßungen - OverallHeight: 4.265 m; Volumen: 0.143336 m3
Phasen - Phase erstellt: Phase 2 1888
Sonstige - Familie: AisleColumn; Familie und Typ: AisleColumn: AisleColumn; Typ: AisleColumn; Typ-ID: 4318990
Group: Built Phase 2 1888

# IfcColumn: STB Stütze - rund:STB ø200 (2)
In: Ebene 0 Nave FFL Phase 1 1864
Type - PredefinedType: COLUMN; Material: Ortbeton - bewehrt Verputzt
Type - Bemaßungen - D: 0.2 m
Type - Geometrie von Tragwerksschnitt - Durchmesser: 0.2 m
Type - ID-Daten - Typenkommentare: D=20cm; Typname: STB ø200
Type - Materialien und Oberflächen - Tragendes Material: Ortbeton - bewehrt Verputzt
Type - Sonstige - Kategorie: Tragwerksstützen; Familienname: STB Stütze - rund; R: 0.1 m
Type - Statische Berechnung - Querschnittsfläche: 0.0314159 m2; Trägheitsmoment schwache Achse: 0.0000785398 m4; Trägheitsmoment starke Achse: 0.0000785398 m4; Umfang: 0.628319 m
Type - Tragwerk - Querschnittsform: 35
Type - Pset_ColumnCommon - LoadBearing: yes; IsExternal: no
Pset_ColumnCommon - Slope: 0 deg; Reference: STB ø200
Pset_QuantityTakeOff - Reference: STB ø200; sets with these values: 2
Abhängigkeiten - Raumbegrenzung: yes; Versatz oben: 0 m; Ebene: Ebene 0 Nave FFL Phase 1 1864; Basisebene: Ebene 0 Nave FFL Phase 1 1864; Oberste Ebene: Ebene New Gallery Underside Stage 6; Versatz unten: -0.5 m
Bemaßungen - Länge: 3.925 m; Volumen: 0.123302 m3
ID-Daten - Hat Verknüpfung: no
Phasen - Phase erstellt: Phase 6 1966
Sonstige - Familie: STB Stütze - rund; Familie und Typ: STB Stütze - rund: STB ø200; Typ: STB ø200; Typ-ID: 2077966
Tragwerk - Betonüberdeckung - Andere Flächen: c=2.0cm <2,0 cm>; Betonüberdeckung - Untere Fläche: c=2.0cm <2,0 cm>
Name (STB Stütze - rund:STB ø200:...) | Stützenpositionsmarkierung | Verschieben mit Raster
6440328 | 2-2E | no
6440534 | 2-2F | yes

# IfcCovering: Basisdecke:GK 10, Basisdecke:GK 10:5623671
In: Ebene -1 Basement Phase 6
Type - PredefinedType: CEILING
Type - Analytische Eigenschaften - Rauigkeit: 1; Absorptionsgrad: 0.1
Type - ID-Daten - Typname: GK 10
Type - Materialien und Oberflächen - Material: Trockenbau - Gipsplatte
Type - Sonstige - Kategorie: Decken; Familienname: Basisdecke
Type - Pset_CoveringCommon - Material: Trockenbau - Gipsplatte
Pset_CoveringCommon - Reference: GK 10; sets with these values: 2
Abhängigkeiten - Raumbegrenzung: yes; Ebene: Basement Ceiling Underside Stage 6; Höhenversatz von Ebene: 0.305 m
Bemaßungen - Fläche: 36.12 m2; Umfang: 31.4 m
Phasen - Phase erstellt: Phase 6 1966
Sonstige - Familie: Basisdecke; Familie und Typ: Basisdecke: GK 10; Typ: GK 10; Typ-ID: 5623740

# IfcCovering: Basisdecke:Standard, Basisdecke:Standard:2808059
In: Ebene -1 Basement Phase 6
Type - PredefinedType: CEILING
Type - Analytische Eigenschaften - Rauigkeit: 1; Absorptionsgrad: 0.1
Type - ID-Daten - Typname: Standard
Type - Materialien und Oberflächen - Material: Trockenbau - Gipsplatte
Type - Sonstige - Kategorie: Decken; Familienname: Basisdecke
Type - Pset_CoveringCommon - Material: Trockenbau - Gipsplatte
Pset_CoveringCommon - Reference: Standard; sets with these values: 2
Abhängigkeiten - Raumbegrenzung: no; Ebene: Ebene -1 Basement Phase 6; Höhenversatz von Ebene: 2.6 m
Bemaßungen - Fläche: 12.7454 m2; Umfang: 15.4741 m
Phasen - Phase erstellt: Phase 7 2019
Sonstige - Familie: Basisdecke; Familie und Typ: Basisdecke: Standard; Typ: Standard; Typ-ID: 3142

# IfcCurtainWall: Basiswand:Glass15 Clear (9)
In: Ebene 0 Nave FFL Phase 1 1864
Type - Material: Glass 0.015 m
Type - Analytische Eigenschaften - Rauigkeit: 1; Absorptionsgrad: 0.1
Type - Grafiken - Füllmuster für groben Maßstab: <Flächenfüllung>; Farbfüllung für groben Maßstab: 255
Type - ID-Daten - Beschreibung: Kalksandstein_115; Typname: Glass15 Clear
Type - Konstruktion - Abschluss an Wänden: Keine; Abschluss an Öffnungen: Keine; Funktion: Innen; Breite: 0.015 m
Type - Sonstige - Kategorie: Wände; Familienname: Basiswand
Type - Tragwerk - Filter Tragend / Nichttragend: no
Type - Pset_CurtainWallCommon - IsExternal: no
Abhängigkeiten - Abhängigkeit unten: Ebene 0 Nave FFL Phase 1 1864; Basislinie: Wandachse; Für Körper: no; Verlängerungsabstand oben: 0 m; Verlängerungsabstand unten: 0 m; Positionslinienversatz: 0 m
ID-Daten - Kategorisieren als:: Element
Phasen - Phase erstellt: Phase 7 2019
Querschnittsdefinition - Querschnitt: Vertikal
Sonstige - Familie: Basiswand; Familie und Typ: Basiswand: Glass15 Clear; Kategorie: Fassadenelemente; Typ: Glass15 Clear; Typ-ID: 6445724
Tragwerk - Tragwerk: no; Tragwerksverwendung: Nichttragend
Pset_CurtainWallCommon - Reference: Glass15 Clear
Pset_QuantityTakeOff - Reference: Glass15 Clear
Name (Basiswand:Glass15 Clear:...) | Versatz unten (m) | Nicht verknüpfte Höhe (m) = Höhe (m) | Breite (m) = Länge (m) | Fläche (m2) | Volumen (m3)
4311168 | 0 | 3.425 | 1.1305 | 3.87196 | 0.0580794
6442389 | 0 | 3.425 | 1.145 | 3.92163 | 0.0588244
4311167 | 0 | 3.425 | 1.45 | 4.96625 | 0.0744937
6442835 | 0 | 2.625 | 0.9645 | 2.53181 | 0.0379772
6446359 | 0 | 2.625 | 1.0055 | 2.63944 | 0.0395916
6443153 | 0 | 3.425 | 1.375 | 4.70937 | 0.0706406
4311166 | 0 | 3.425 | 1.16 | 3.973 | 0.059595
6442070 | 0 | 3.425 | 1.1595 | 3.97129 | 0.0595693
6446277 | 2.625 | 0.8 | 1.97 | 1.576 | 0.02364

# IfcCurtainWall: Fassade:LobbyScreen, Fassade:LobbyScreen:4308659
In: Ebene 0 Nave FFL Phase 1 1864
Type - Horizontales Raster - Anpassen auf Pfostengröße: no; Layout: Keine
Type - ID-Daten - Typname: LobbyScreen
Type - Konstruktion - Funktion: Außen; Automatisch umschließen: yes; Fassadenelemente: Basiswand : Glass15 Clear; Verbindungsbedingung: Nicht definiert
Type - Sonstige - Kategorie: Wände; Familienname: Fassade
Type - Tragwerk - Filter Tragend / Nichttragend: no
Type - Vertikales Raster - Anpassen auf Pfostengröße: no; Layout: Keine
Type - Pset_CurtainWallCommon - IsExternal: yes
Pset_CurtainWallCommon - Reference: LobbyScreen
Pset_QuantityTakeOff - Reference: LobbyScreen
Abhängigkeiten - Abhängigkeit unten: Ebene 0 Nave FFL Phase 1 1864; Für Körper: no; Oberkante ist fixiert.: no; Raumbegrenzung: yes; Unterkante ist fixiert: no; Versatz unten: 0 m; Versatz oben: 0 m; Abhängigkeit oben: Bis Ebene: Ebene New Gallery Underside Stage 6; Nicht verknüpfte Höhe: 3.425 m
Bemaßungen - Fläche: 33.1198 m2; Länge: 9.67 m
Horizontales Raster - Winkel: 0 deg; Versatz: 0 m; Anzahl: 4; Ausrichtung: Anfang; sets with these values: 2
Phasen - Phase erstellt: Phase 7 2019
Querschnittsdefinition - Querschnitt: Vertikal
Sonstige - Familie: Fassade; Familie und Typ: Fassade: LobbyScreen; Typ: LobbyScreen; Typ-ID: 4311134
Tragwerk - Tragwerk: no; Tragwerksverwendung: Nichttragend

# IfcDistributionPort (2)
Description: Flow; FlowDirection: SOURCEANDSINK; Group: Heizung Vorlauf 1

# IfcDoor: Arched_Doorway:Arched_Door_Store, Arched_Doorway:Arched_Door_Store:7676724
In: Ebene 0 Nave FFL Phase 1 1864
Type - ParameterTakesPrecedence: no; Sizeable: no; Material: Holz - generisch 140-100-70 (3)
Type - Analytische Eigenschaften - Thermische Eigenschaften definieren durch: Schemaplantypen; Analytische Konstruktion: <Keine Auswahl>
Type - Bemaßungen - Breite: 1 m; Dicke: 0.0454 m; Höhe: 2 m; Moulding springing height: 3.8 m; Moulding width: 2.555 m; Radius L: 2.14725 m; Radius R: 2.14725 m; Rohbaubreite: 0 m; Rohbauhöhe: 0 m; SpringingHoehe: 2 m; Threshold: 0.06 m
Type - ID-Daten - Hersteller: Jeffrey P. Fazzone; Typenmarkierung: 243; Typname: Arched_Door_Store; URL: www.DPlusP.com
Type - Konstruktion - Wandabschluss: Nach Basisbauteil
Type - Materialien und Oberflächen - Door: Holz - generisch 140-100-70; FrameMaterial: Holz - generisch 140-100-70; Treshold: Holz - generisch 140-100-70
Type - Sonstige - Kategorie: Türen; Default Sill Height: 0.9144 m; Familienname: Arched_Doorway; HalfGlassThickness: 0.009525 m
Type - Pset_DoorCommon - IsExternal: no
Type - Pset_ManufacturerTypeInformation - Manufacturer: Jeffrey P. Fazzone
OverallHeight: 2.96821 m; OverallWidth: 1 m
Pset_DoorCommon - IsExternal: yes; Reference: Arched_Door_Store
Pset_QuantityTakeOff - Reference: Arched_Door_Store
Abhängigkeiten - Ebene: Ebene 0 Nave FFL Phase 1 1864; Schwelle/Brüstung: 0 m
Bemaßungen - Fläche: 3.97294 m2; Half width: 2.555 m; Volumen: 0.166746 m3
ID-Daten - Kennzeichen: TU 65; Kommentare: Assumed date of opening
Phasen - Phase erstellt: Phase 6 1966
Sonstige - Familie: Arched_Doorway; Familie und Typ: Arched_Doorway: Arched_Door_Store; Host-ID: 3044337; Sturzhöhe: 2 m; Typ: Arched_Door_Store; Typ-ID: 3215779

# IfcDoor: Main_entrance_portal_door:Main_entrance_portal_door, Main_entrance_portal_door:Main_entrance_portal_door:4269682
In: Ebene 0 Nave FFL Phase 1 1864
Type - ParameterTakesPrecedence: no; Sizeable: no; Material: Holz - Eiche (4), <Unnamed> (14)
Type - Analytische Eigenschaften - Thermische Eigenschaften definieren durch: Schemaplantypen; Analytische Konstruktion: <Keine Auswahl>
Type - Bemaßungen - Breite: 2.34 m; BreiteInnen: 2.41 m; Höhe: 5.46 m; InnenRecess: 0.11 m; SpringingHeight: 3.53 m
Type - ID-Daten - OmniClass-Nummer: 23.30.10.00; OmniClass-Titel: Doors; Typenmarkierung: 247; Typname: Main_entrance_portal_door
Type - Konstruktion - Funktion: Innen; Wandabschluss: Nach Basisbauteil
Type - Materialien und Oberflächen - FrameMaterial: Holz - Eiche
Type - Sonstige - Kategorie: Türen; Familienname: Main_entrance_portal_door; Rahmenbreite: 0.075 m; Rahmenprojektion außen: 0.025 m; Rahmenprojektion innen: 0.025 m
Type - Pset_DoorCommon - IsExternal: no
OverallHeight: 5.46 m; OverallWidth: 2.41 m; Group: Modellgruppe:BasementChimney:6973904; Built Phase 1 1864
Pset_DoorCommon - Reference: Main_entrance_portal_door
Pset_QuantityTakeOff - Reference: Main_entrance_portal_door
Abhängigkeiten - Ebene: Ebene 0 Nave FFL Phase 1 1864; Schwelle/Brüstung: 0 m
Bemaßungen - Fläche: 16.3895 m2; Volumen: 1.12705 m3
ID-Daten - Kennzeichen: TU 23
Phasen - Phase erstellt: Phase 1 1864
Sonstige - Familie: Main_entrance_portal_door; Familie und Typ: Main_entrance_portal_door: Main_entrance_portal_door; Host-ID: 4262984; Sturzhöhe: 5.46 m; Typ: Main_entrance_portal_door; Typ-ID: 4269663

# IfcDoor: TU DF 1 - Pfostenstock flächenbündig:Belfry Door, TU DF 1 - Pfostenstock flächenbündig:Belfry Door:7426829
In: Ebene 3 Belfry FFL Stage 2 1888
Type - OperationType: SINGLE_SWING_RIGHT; ParameterTakesPrecedence: no; Sizeable: no; Material: Holz - generisch 140-100-70, Metall - Edelstahl gebürstet (8), Lack - grau 80-80-80
Type - TU DF 1 - Pfostenstock flächenbündig:Belfry Door:7426829:1 - PanelOperation: SWINGING
Type - Analytische Eigenschaften - Thermische Eigenschaften definieren durch: Schemaplantypen; Analytische Konstruktion: <Keine Auswahl>
Type - Bemaßungen - Größenberechnung über Lichten Durchgang: yes; Größenberechnung über Maueröffnungsmaß: no; Höhe ab FBOK berechnen: yes; Randabstand Öffnungssymbol: 0 m; Angabe Lichter Durchgang Breite: 0.87 m; Angabe Lichter Durchgang Höhe: 2 m; Angabe Maueröffnungsmaß Breite: 0.885 m; Angabe Maueröffnungsmaß Höhe: 2.135 m; Breite: 0.98 m; Dicke: 0.045 m; Durchgangsbreite: 0.87 m; Durchgangshöhe: 2 m; Höhe ab FBOK: 2.055 m; Rohbaubreite: 0.98 m
Type - Daten - Anschlag- / Bewegungsart Tür: Drehflügeltür; Anzahl Flügel: einflügelig; Anzahl Oberlichter: 0; Anzahl Seitenteile: 0; Ausführung Zarge: Blockzarge; Form Tür: rechteckig
Type - ID-Daten - Beschreibung: 1-teilig; OmniClass-Nummer: 23.30.10.00; OmniClass-Titel: Doors; Typenkommentare: Pfostenstock flächenbündig; Typenmarkierung: 264; Typname: Belfry Door; URL: http://www.autodesk.de/BIM
Type - Konstruktion - Funktion: Innen; Wandabschluss: Nach Basisbauteil; Drückerhöhe: 1.05 m; Rahmendicke: 0.055 m; Rahmentiefe: 0.075 m
Type - Sonstige - Kategorie: Türen; Familienname: TU DF 1 - Pfostenstock flächenbündig
Type - Pset_DoorCommon - IsExternal: no
OverallHeight: 2.235 m; OverallWidth: 0.98 m; Group: Built Phase 2 1888
Pset_DoorCommon - Reference: Belfry Door
Pset_QuantityTakeOff - Reference: Belfry Door
Abhängigkeiten - Wandaufbau Gegenbandseite: 0 m; Winkel Öffnungsbogen: 90 deg; Pfostenstock Wandmittig eingebaut: no; Schwelle/Brüstung: 0 m; Einbautiefe: 0 m; Ebene: Ebene 3 Belfry FFL Stage 2 1888; Fußbodenaufbau: 0.18 m; Wandaufbau Bandseite: 0.04 m
Bemaßungen - Fläche: 5.03771 m2; Höhe: 2.055 m; Rohbauhöhe: 2.235 m; Volumen: 0.000185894 m3
Grafiken - Kollisionskörper einschalten: no; Tür mit Anschlag: no; Grundrissdarstellung Türsturz: yes
ID-Daten - Kennzeichen: TU 64
Phasen - Phase erstellt: Phase 2 1888
Schichten - Drücker Bandseite: yes; Drücker Gegenbandseite: yes; Zylinderrosette: yes
Sonstige - Familie: TU DF 1 - Pfostenstock flächenbündig; Familie und Typ: TU DF 1 - Pfostenstock flächenbündig: Belfry Door; Host-ID: 7426531; Sturzhöhe: 2.055 m; Typ: Belfry Door; Typ-ID: 7752259
Vollständige Legende - Knauf Außenseite: no; Knauf Innenseite: no; B_Einbautiefe: 0 m; Wandstärke: 0.16 m; Wandstärke Gesamt: 0.2 m

# IfcDoor: TU DF 1 - Pfostenstock flächenbündig:ML - 920 x 2051, TU DF 1 - Pfostenstock flächenbündig:ML - 920 x 2051:5562621
In: Ebene -1 Basement Phase 6
Type - OperationType: SINGLE_SWING_RIGHT; ParameterTakesPrecedence: no; Sizeable: no; Material: Holz - generisch 140-100-70, Metall - Edelstahl gebürstet (8), Lack - grau 80-80-80
Type - TU DF 1 - Pfostenstock flächenbündig:ML - 920 x 2051:5562621:1 - PanelOperation: SWINGING
Type - Analytische Eigenschaften - Thermische Eigenschaften definieren durch: Schemaplantypen; Analytische Konstruktion: <Keine Auswahl>
Type - Bemaßungen - Höhe ab FBOK berechnen: yes; Randabstand Öffnungssymbol: 0 m; Größenberechnung über Lichten Durchgang: no; Größenberechnung über Maueröffnungsmaß: yes; Angabe Lichter Durchgang Breite: 0.8 m; Angabe Lichter Durchgang Höhe: 2 m; Angabe Maueröffnungsmaß Breite: 0.92 m; Angabe Maueröffnungsmaß Höhe: 2.05 m; Breite: 0.92 m; Dicke: 0.045 m; Durchgangsbreite: 0.81 m; Durchgangshöhe: 1.995 m; Höhe ab FBOK: 2.05 m; Rohbaubreite: 0.92 m
Type - Daten - Anschlag- / Bewegungsart Tür: Drehflügeltür; Anzahl Flügel: einflügelig; Anzahl Oberlichter: 0; Anzahl Seitenteile: 0; Ausführung Zarge: Blockzarge; Form Tür: rechteckig
Type - ID-Daten - Beschreibung: 1-teilig; OmniClass-Nummer: 23.30.10.00; OmniClass-Titel: Doors; Typenkommentare: Pfostenstock flächenbündig; Typenmarkierung: 259; Typname: ML - 920 x 2051; URL: http://www.autodesk.de/BIM
Type - Konstruktion - Funktion: Innen; Wandabschluss: Beide; Drückerhöhe: 1.05 m; Rahmendicke: 0.055 m; Rahmentiefe: 0.075 m
Type - Sonstige - Kategorie: Türen; Familienname: TU DF 1 - Pfostenstock flächenbündig
Type - Pset_DoorCommon - IsExternal: no
OverallHeight: 2.23 m; OverallWidth: 0.92 m
Pset_DoorCommon - Reference: ML - 920 x 2051
Pset_QuantityTakeOff - Reference: ML - 920 x 2051
Abhängigkeiten - Ebene: Ebene -1 Basement Phase 6; Wandaufbau Bandseite: 0 m; Wandaufbau Gegenbandseite: 0 m; Winkel Öffnungsbogen: 90 deg; Pfostenstock Wandmittig eingebaut: no; Schwelle/Brüstung: 0 m; Einbautiefe: 0.08 m; Fußbodenaufbau: 0.18 m
Bemaßungen - Fläche: 4.65769 m2; Höhe: 2.05 m; Rohbauhöhe: 2.23 m; Volumen: 0.000170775 m3
Grafiken - Grundrissdarstellung Türsturz: no; Kollisionskörper einschalten: no; Tür mit Anschlag: no
ID-Daten - Kennzeichen: TU 55
Phasen - Phase erstellt: Phase 7 2019
Schichten - Drücker Bandseite: yes; Drücker Gegenbandseite: yes; Zylinderrosette: yes
Sonstige - Familie: TU DF 1 - Pfostenstock flächenbündig; Familie und Typ: TU DF 1 - Pfostenstock flächenbündig: ML - 920 x 2051; Host-ID: 5561810; Sturzhöhe: 2.05 m; Typ: ML - 920 x 2051; Typ-ID: 5562616
Vollständige Legende - Knauf Außenseite: no; Knauf Innenseite: no; B_Einbautiefe: 0.08 m; Wandstärke: 0.28 m; Wandstärke Gesamt: 0.28 m

# IfcDoor: TU DF 1 - Pfostenstock flächenbündig:ML - 935 x 2051, TU DF 1 - Pfostenstock flächenbündig:ML - 935 x 2051:6248665
In: Ebene 0 Nave FFL Phase 1 1864
Type - OperationType: SINGLE_SWING_RIGHT; ParameterTakesPrecedence: no; Sizeable: no; Material: Holz - generisch 140-100-70, Metall - Edelstahl gebürstet (8), Lack - grau 80-80-80
Type - Analytische Eigenschaften(Type) - Thermische Eigenschaften definieren durch: Schemaplantypen; Analytische Konstruktion: <Keine Auswahl>
Type - Bemaßungen(Type) - Höhe ab FBOK berechnen: yes; Randabstand Öffnungssymbol: 0 m; Angabe Lichter Durchgang Breite: 0.8 m; Angabe Lichter Durchgang Höhe: 2 m; Angabe Maueröffnungsmaß Breite: 0.935 m; Angabe Maueröffnungsmaß Höhe: 2.05 m; Breite: 0.935 m; Dicke: 0.045 m; Durchgangsbreite: 0.825 m; Durchgangshöhe: 1.995 m; Größenberechnung über Lichten Durchgang: no; Größenberechnung über Maueröffnungsmaß: yes; Höhe ab FBOK: 2.05 m; Rohbaubreite: 0.935 m
Type - Daten(Type) - Anschlag- / Bewegungsart Tür: Drehflügeltür; Anzahl Flügel: einflügelig; Anzahl Oberlichter: 0; Anzahl Seitenteile: 0; Ausführung Zarge: Blockzarge; Form Tür: rechteckig
Type - ID-Daten(Type) - Beschreibung: 1-teilig; OmniClass-Nummer: 23.30.10.00; OmniClass-Titel: Doors; Typenkommentare: Pfostenstock flächenbündig; Typenmarkierung: 262; Typname: ML - 935 x 2051; URL: http://www.autodesk.de/BIM
Type - Konstruktion(Type) - Funktion: Innen; Drückerhöhe: 1.05 m; Rahmendicke: 0.055 m; Rahmentiefe: 0.075 m; Wandabschluss: Beide
Type - Sonstige(Type) - Kategorie: Türen; Familienname: TU DF 1 - Pfostenstock flächenbündig
Type - TU DF 1 - Pfostenstock flächenbündig:ML - 935 x 2051:6248665:1 - PanelOperation: SWINGING
Type - Pset_DoorCommon - IsExternal: no
OverallHeight: 2.05 m; OverallWidth: 0.935 m; Group: Built Phase 2 1888
Pset_DoorCommon - Reference: ML - 935 x 2051
Pset_QuantityTakeOff - Reference: ML - 935 x 2051
Abhängigkeiten - Ebene: Ebene 0 Nave FFL Phase 1 1864; Wandaufbau Bandseite: 0 m; Wandaufbau Gegenbandseite: 0 m; Winkel Öffnungsbogen: 90 deg; Fußbodenaufbau: 0 m; Pfostenstock Wandmittig eingebaut: no; Schwelle/Brüstung: 0 m; Einbautiefe: 0.18 m
Bemaßungen - Fläche: 4.74948 m2; Höhe: 2.05 m; Rohbauhöhe: 2.05 m; Volumen: 0.000174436 m3
Grafiken - Kollisionskörper einschalten: no; Tür mit Anschlag: no; Grundrissdarstellung Türsturz: yes
ID-Daten - Kennzeichen: TU 58
Phasen - Phase erstellt: Phase 2 1888
Schichten - Drücker Bandseite: yes; Drücker Gegenbandseite: yes; Zylinderrosette: yes
Sonstige - Kategorie: Türen; Familie: TU DF 1 - Pfostenstock flächenbündig; Familie und Typ: TU DF 1 - Pfostenstock flächenbündig: ML - 935 x 2051; Host-ID: 6243229; Typ: ML - 935 x 2051; Typ-ID: 6248924; Sturzhöhe: 2.05 m
Vollständige Legende - Knauf Außenseite: no; Knauf Innenseite: no; B_Einbautiefe: 0.18 m; Wandstärke: 0.266 m; Wandstärke Gesamt: 0.266 m

# IfcDoor: TU DF 1 - Pfostenstock flächenbündig:ML - 940 x 2050, TU DF 1 - Pfostenstock flächenbündig:ML - 940 x 2050:5664437
In: Ebene 0 Nave FFL Phase 1 1864
Type - OperationType: SINGLE_SWING_LEFT; ParameterTakesPrecedence: no; Sizeable: no; Material: Holz - generisch 140-100-70, Metall - Edelstahl gebürstet (8), Lack - grau 80-80-80
Type - Analytische Eigenschaften - Thermische Eigenschaften definieren durch: Schemaplantypen; Analytische Konstruktion: <Keine Auswahl>
Type - Bemaßungen - Höhe ab FBOK berechnen: yes; Randabstand Öffnungssymbol: 0 m; Größenberechnung über Lichten Durchgang: no; Größenberechnung über Maueröffnungsmaß: yes; Angabe Lichter Durchgang Breite: 0.8 m; Angabe Lichter Durchgang Höhe: 2 m; Angabe Maueröffnungsmaß Breite: 0.94 m; Angabe Maueröffnungsmaß Höhe: 2.05 m; Breite: 0.94 m; Dicke: 0.045 m; Durchgangsbreite: 0.83 m; Durchgangshöhe: 1.995 m; Höhe ab FBOK: 2.05 m; Rohbaubreite: 0.94 m
Type - Daten - Anschlag- / Bewegungsart Tür: Drehflügeltür; Anzahl Flügel: einflügelig; Anzahl Oberlichter: 0; Anzahl Seitenteile: 0; Ausführung Zarge: Blockzarge; Form Tür: rechteckig
Type - ID-Daten - Beschreibung: 1-teilig; OmniClass-Nummer: 23.30.10.00; OmniClass-Titel: Doors; Typenkommentare: Pfostenstock flächenbündig; Typenmarkierung: 254; Typname: ML - 940 x 2050; URL: http://www.autodesk.de/BIM
Type - Konstruktion - Funktion: Innen; Wandabschluss: Beide; Drückerhöhe: 1.05 m; Rahmendicke: 0.055 m; Rahmentiefe: 0.075 m
Type - Sonstige - Kategorie: Türen; Familienname: TU DF 1 - Pfostenstock flächenbündig
Type - TU DF 1 - Pfostenstock flächenbündig:ML - 940 x 2050:5664437:1 - PanelOperation: SWINGING
Type - Pset_DoorCommon - IsExternal: no
OverallHeight: 2.2 m; OverallWidth: 0.94 m
Pset_DoorCommon - Reference: ML - 940 x 2050
Pset_QuantityTakeOff - Reference: ML - 940 x 2050
Abhängigkeiten - Ebene: Ebene 0 Nave FFL Phase 1 1864; Wandaufbau Bandseite: 0 m; Wandaufbau Gegenbandseite: 0 m; Winkel Öffnungsbogen: 90 deg; Pfostenstock Wandmittig eingebaut: no; Einbautiefe: 0 m; Fußbodenaufbau: 0.15 m; Schwelle/Brüstung: 0.3 m
Bemaßungen - Fläche: 4.78019 m2; Höhe: 2.05 m; Rohbauhöhe: 2.2 m; Volumen: 0.000175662 m3
Grafiken - Kollisionskörper einschalten: no; Tür mit Anschlag: no; Grundrissdarstellung Türsturz: yes
ID-Daten - Kennzeichen: TU 57
Phasen - Phase erstellt: Phase 6 1966
Schichten - Drücker Bandseite: yes; Drücker Gegenbandseite: yes; Zylinderrosette: yes
Sonstige - Familie: TU DF 1 - Pfostenstock flächenbündig; Familie und Typ: TU DF 1 - Pfostenstock flächenbündig: ML - 940 x 2050; Typ: ML - 940 x 2050; Typ-ID: 5331526; Host-ID: 5664150; Sturzhöhe: 2.35 m
Vollständige Legende - Knauf Außenseite: no; Knauf Innenseite: no; B_Einbautiefe: 0 m; Wandstärke: 0.16 m; Wandstärke Gesamt: 0.16 m

# IfcDoor: TU DF 1 - Pfostenstock flächenbündig:ML - 940 x 2050, TU DF 1 - Pfostenstock flächenbündig:ML - 940 x 2050:5331551
In: Ebene 0 Nave FFL Phase 1 1864
Type - OperationType: SINGLE_SWING_RIGHT; ParameterTakesPrecedence: no; Sizeable: no; Material: Holz - generisch 140-100-70, Metall - Edelstahl gebürstet (8), Lack - grau 80-80-80
Type - TU DF 1 - Pfostenstock flächenbündig:ML - 940 x 2050:5331551:1 - PanelOperation: SWINGING
Type - Analytische Eigenschaften - Thermische Eigenschaften definieren durch: Schemaplantypen; Analytische Konstruktion: <Keine Auswahl>
Type - Bemaßungen - Höhe ab FBOK berechnen: yes; Randabstand Öffnungssymbol: 0 m; Größenberechnung über Lichten Durchgang: no; Größenberechnung über Maueröffnungsmaß: yes; Angabe Lichter Durchgang Breite: 0.8 m; Angabe Lichter Durchgang Höhe: 2 m; Angabe Maueröffnungsmaß Breite: 0.94 m; Angabe Maueröffnungsmaß Höhe: 2.05 m; Breite: 0.94 m; Dicke: 0.045 m; Durchgangsbreite: 0.83 m; Durchgangshöhe: 1.995 m; Höhe ab FBOK: 2.05 m; Rohbaubreite: 0.94 m
Type - Daten - Anschlag- / Bewegungsart Tür: Drehflügeltür; Anzahl Flügel: einflügelig; Anzahl Oberlichter: 0; Anzahl Seitenteile: 0; Ausführung Zarge: Blockzarge; Form Tür: rechteckig
Type - ID-Daten - Beschreibung: 1-teilig; OmniClass-Nummer: 23.30.10.00; OmniClass-Titel: Doors; Typenkommentare: Pfostenstock flächenbündig; Typenmarkierung: 254; Typname: ML - 940 x 2050; URL: http://www.autodesk.de/BIM
Type - Konstruktion - Funktion: Innen; Wandabschluss: Beide; Drückerhöhe: 1.05 m; Rahmendicke: 0.055 m; Rahmentiefe: 0.075 m
Type - Sonstige - Kategorie: Türen; Familienname: TU DF 1 - Pfostenstock flächenbündig
Type - Pset_DoorCommon - IsExternal: no
OverallHeight: 2.2 m; OverallWidth: 0.94 m; Group: Modellgruppe:BasementChimney:6973904; Built Phase 1 1864
Pset_DoorCommon - Reference: ML - 940 x 2050
Pset_QuantityTakeOff - Reference: ML - 940 x 2050
Abhängigkeiten - Ebene: Ebene 0 Nave FFL Phase 1 1864; Wandaufbau Bandseite: 0 m; Wandaufbau Gegenbandseite: 0 m; Winkel Öffnungsbogen: 90 deg; Pfostenstock Wandmittig eingebaut: no; Einbautiefe: 0 m; Fußbodenaufbau: 0.15 m; Schwelle/Brüstung: 0.45 m
Bemaßungen - Fläche: 4.78019 m2; Höhe: 2.05 m; Rohbauhöhe: 2.2 m; Volumen: 0.000175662 m3
Grafiken - Kollisionskörper einschalten: no; Tür mit Anschlag: no; Grundrissdarstellung Türsturz: yes
ID-Daten - Kennzeichen: TU 50
Phasen - Phase erstellt: Phase 1 1864
Schichten - Drücker Bandseite: yes; Drücker Gegenbandseite: yes; Zylinderrosette: yes
Sonstige - Familie: TU DF 1 - Pfostenstock flächenbündig; Host-ID: 5302643; Familie und Typ: TU DF 1 - Pfostenstock flächenbündig: ML - 940 x 2050; Sturzhöhe: 2.5 m; Typ: ML - 940 x 2050; Typ-ID: 5331526
Vollständige Legende - Knauf Außenseite: no; Knauf Innenseite: no; B_Einbautiefe: 0 m; Wandstärke: 0.44 m; Wandstärke Gesamt: 0.44 m

# IfcDoor: TU DF 1 - Pfostenstock flächenbündig:Tower basement fire door - 800 x 2001, TU DF 1 - Pfostenstock flächenbündig:Tower basement fire door - 800 x 2001:2720463
In: Ebene -1 Basement Phase 6
Type - OperationType: SINGLE_SWING_RIGHT; ParameterTakesPrecedence: no; Sizeable: no; Material: Holz - generisch 140-100-70, Metall - Edelstahl gebürstet (8), Lack - grau 80-80-80
Type - TU DF 1 - Pfostenstock flächenbündig:Tower basement fire door - 800 x 2001:2720463:1 - PanelOperation: SWINGING
Type - Analytische Eigenschaften - Thermische Eigenschaften definieren durch: Schemaplantypen; Analytische Konstruktion: <Keine Auswahl>
Type - Bemaßungen - Größenberechnung über Lichten Durchgang: yes; Größenberechnung über Maueröffnungsmaß: no; Höhe ab FBOK berechnen: yes; Randabstand Öffnungssymbol: 0 m; Angabe Lichter Durchgang Breite: 0.6 m; Angabe Lichter Durchgang Höhe: 2 m; Angabe Maueröffnungsmaß Breite: 0.885 m; Angabe Maueröffnungsmaß Höhe: 2.135 m; Breite: 0.69 m; Dicke: 0.045 m; Durchgangsbreite: 0.6 m; Durchgangshöhe: 2 m; Höhe ab FBOK: 2.045 m; Rohbaubreite: 0.69 m
Type - Daten - Anschlag- / Bewegungsart Tür: Drehflügeltür; Anzahl Flügel: einflügelig; Anzahl Oberlichter: 0; Anzahl Seitenteile: 0; Ausführung Zarge: Blockzarge; Form Tür: rechteckig
Type - ID-Daten - Beschreibung: 1-teilig; OmniClass-Nummer: 23.30.10.00; OmniClass-Titel: Doors; Typenkommentare: Pfostenstock flächenbündig; Typenmarkierung: 261; Typname: Tower basement fire door - 800 x 2001; URL: http://www.autodesk.de/BIM
Type - Konstruktion - Funktion: Innen; Wandabschluss: Beide; Drückerhöhe: 1.05 m; Rahmendicke: 0.045 m; Rahmentiefe: 0.075 m
Type - Sonstige - Kategorie: Türen; Familienname: TU DF 1 - Pfostenstock flächenbündig
Type - Pset_DoorCommon - IsExternal: no
OverallHeight: 2.245 m; OverallWidth: 0.69 m; Group: Built Phase 2 1888
Pset_DoorCommon - Reference: Tower basement fire door - 800 x 2001
Pset_QuantityTakeOff - Reference: Tower basement fire door - 800 x 2001
Abhängigkeiten - Ebene: Ebene -1 Basement Phase 6; Wandaufbau Bandseite: 0 m; Wandaufbau Gegenbandseite: 0 m; Winkel Öffnungsbogen: 90 deg; Pfostenstock Wandmittig eingebaut: no; Schwelle/Brüstung: 0 m; Einbautiefe: 0.21 m; Fußbodenaufbau: 0.2 m
Bemaßungen - Fläche: 3.4251 m2; Höhe: 2.045 m; Rohbauhöhe: 2.245 m; Volumen: 0.000117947 m3
Grafiken - Kollisionskörper einschalten: no; Tür mit Anschlag: no; Grundrissdarstellung Türsturz: yes
ID-Daten - Kennzeichen: TU 7
Phasen - Phase erstellt: Phase 2 1888
Schichten - Drücker Bandseite: yes; Drücker Gegenbandseite: yes; Zylinderrosette: yes
Sonstige - Familie: TU DF 1 - Pfostenstock flächenbündig; Familie und Typ: TU DF 1 - Pfostenstock flächenbündig: Tower basement fire door - 800 x 2001; Host-ID: 2720276; Sturzhöhe: 2.045 m; Typ: Tower basement fire door - 800 x 2001; Typ-ID: 5647701
Vollständige Legende - Knauf Außenseite: no; Knauf Innenseite: no; B_Einbautiefe: 0.21 m; Wandstärke: 0.33 m; Wandstärke Gesamt: 0.33 m

# IfcDoor: TU DF 1 - Rahmenstock flächenbündig:DL - 800 x 2000 blue, TU DF 1 - Rahmenstock flächenbündig:DL - 800 x 2000 blue:2677961
In: Ebene 0 Nave FFL Phase 1 1864
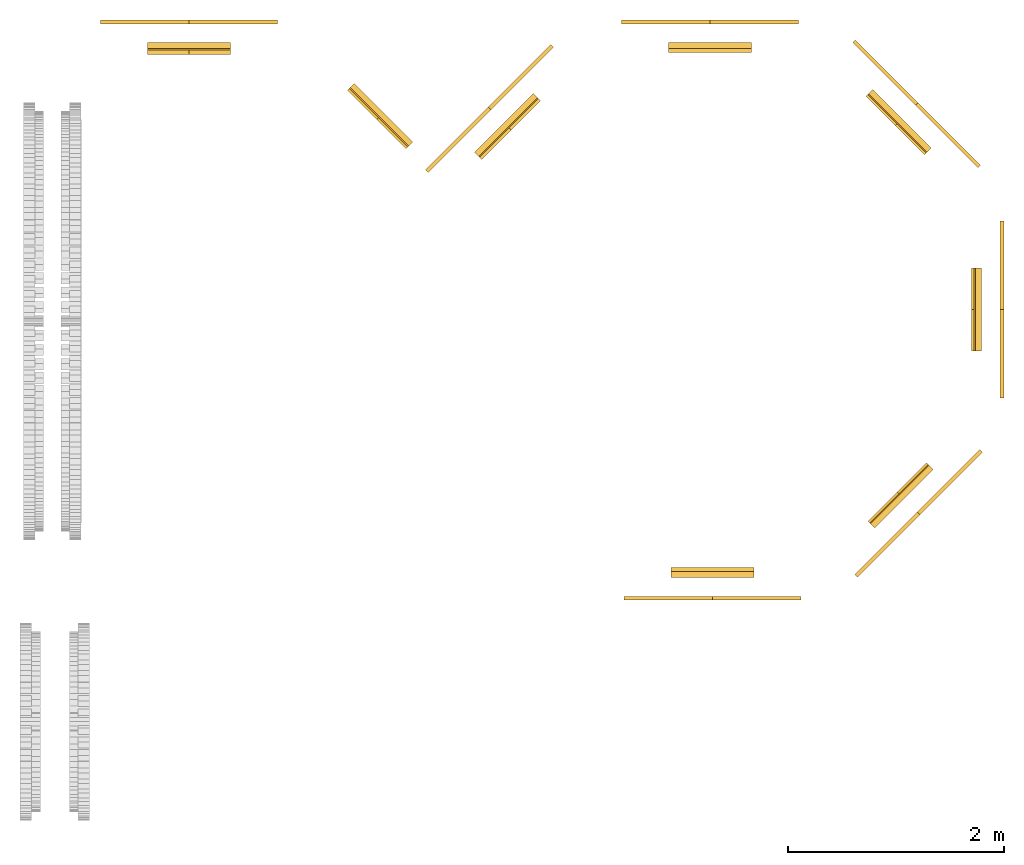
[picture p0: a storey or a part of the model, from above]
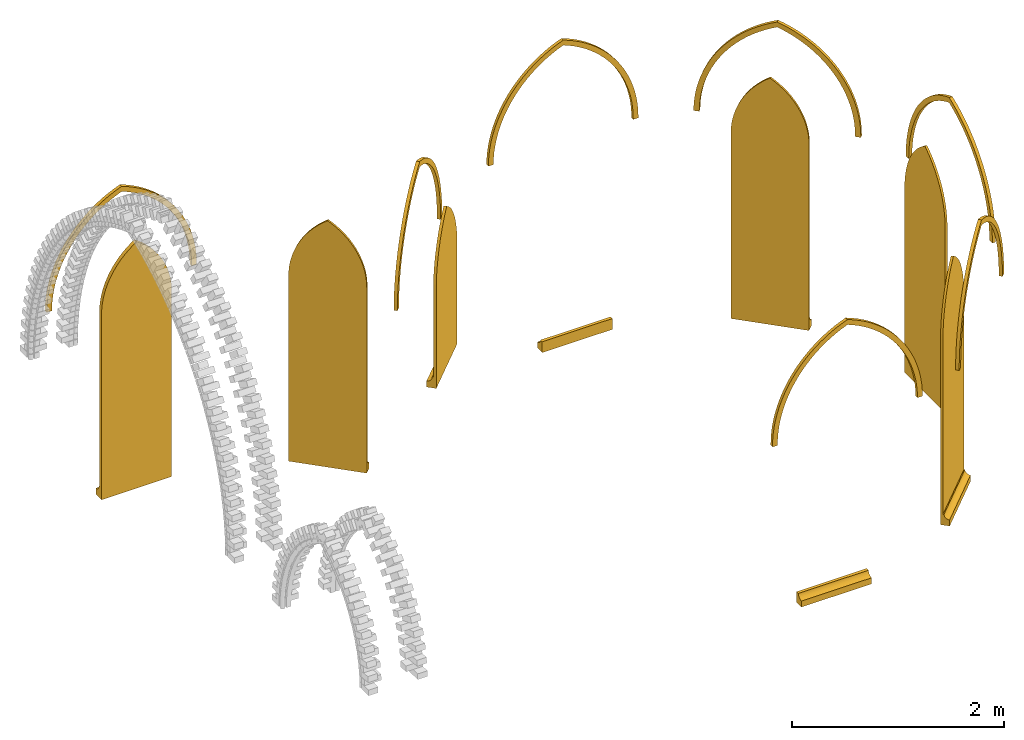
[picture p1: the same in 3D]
Properties of the parts of a building model (IFC2X3), part 2 of 7

# IfcDoor: TU DF 1 - Rahmenstock flächenbündig:DL - 800 x 2000 blue, TU DF 1 - Rahmenstock flächenbündig:DL - 800 x 2000 blue:2677961
Type - OperationType: SINGLE_SWING_LEFT; ParameterTakesPrecedence: no; Sizeable: no; Material: Holz - generisch 140-100-70, Metall - Edelstahl gebürstet (8), Lack - grau 80-80-80
Type - TU DF 1 - Rahmenstock flächenbündig:DL - 800 x 2000 blue:2677961:1 - PanelOperation: SWINGING
Type - Analytische Eigenschaften - Thermische Eigenschaften definieren durch: Schemaplantypen; Analytische Konstruktion: <Keine Auswahl>
Type - Bemaßungen - Angabe Lichter Durchgang Breite: 0.8 m; Angabe Lichter Durchgang Höhe: 2 m; Angabe Maueröffnungsmaß Breite: 0.76 m; Angabe Maueröffnungsmaß Höhe: 2.005 m; Breite: 0.89 m; Dicke: 0.045 m; Durchgangsbreite: 0.8 m; Durchgangshöhe: 2 m; Größenberechnung über Lichten Durchgang: yes; Größenberechnung über Maueröffnungsmaß: no; Höhe ab FBOK: 2.045 m; Höhe ab FBOK berechnen: yes; Randabstand Öffnungssymbol: 0 m; Rohbaubreite: 0.89 m
Type - Daten - Anschlag- / Bewegungsart Tür: Drehflügeltür; Anzahl Flügel: einflügelig; Anzahl Oberlichter: 0; Anzahl Seitenteile: 0; Ausführung Zarge: Umfassungszarge; Form Tür: rechteckig
Type - ID-Daten - Beschreibung: 1-teilig; OmniClass-Nummer: 23.30.10.00; OmniClass-Titel: Doors; Typenkommentare: Rahmenstock flächenbündig; Typenmarkierung: 231; Typname: DL - 800 x 2000 blue; URL: http://www.autodesk.de/BIM
Type - Konstruktion - Funktion: Innen; Wandabschluss: Nach Basisbauteil; Drückerhöhe: 1.05 m; Rahmendicke: 0.045 m
Type - Sonstige - Kategorie: Türen; Familienname: TU DF 1 - Rahmenstock flächenbündig
Type - Pset_DoorCommon - IsExternal: no
OverallHeight: 2.225 m; OverallWidth: 0.89 m; Group: Built Phase 2 1888
Pset_DoorCommon - Reference: DL - 800 x 2000 blue
Pset_QuantityTakeOff - Reference: DL - 800 x 2000 blue
Abhängigkeiten - Ebene: Ebene 0 Nave FFL Phase 1 1864; Fußbodenaufbau: 0.18 m; Schwelle/Brüstung: 0.15 m; Wandaufbau Bandseite: 0 m; Wandaufbau Gegenbandseite: 0 m; Winkel Öffnungsbogen: 90 deg
Bemaßungen - Fläche: 4.60059 m2; Höhe: 2.045 m; Rohbauhöhe: 2.225 m; Volumen: 0.000163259 m3
Grafiken - Grundrissdarstellung Türsturz: no; Kollisionskörper einschalten: no; Tür mit Anschlag: no
ID-Daten - Kennzeichen: TU 5
Phasen - Phase erstellt: Phase 2 1888
Schichten - Drücker Bandseite: yes; Drücker Gegenbandseite: yes; Zylinderrosette: yes
Sonstige - Familie: TU DF 1 - Rahmenstock flächenbündig; Familie und Typ: TU DF 1 - Rahmenstock flächenbündig: DL - 800 x 2000 blue; Host-ID: 2572272; Sturzhöhe: 2.195 m; Typ: DL - 800 x 2000 blue; Typ-ID: 2678292
Vollständige Legende - Knauf Außenseite: no; Knauf Innenseite: no; Wandstärke: 0.528 m; Wandstärke Gesamt: 0.528 m

# IfcDoor: TU DF 1 - Rahmenstock mit Glasseitenteil:DL - 1460 x 2080, TU DF 1 - Rahmenstock mit Glasseitenteil:DL - 1460 x 2080:2807700
In: Ebene -1 Basement Phase 6
Type - OperationType: SINGLE_SWING_RIGHT; ParameterTakesPrecedence: no; Sizeable: no; Material: Holz - generisch 140-100-70, Metall - Edelstahl gebürstet (8), Lack - grau 80-80-80 (2), Glas - Isolierverglasung Bronze
Type - TU DF 1 - Rahmenstock mit Glasseitenteil:DL - 1460 x 2080:2807700:1 - PanelOperation: SWINGING
Type - Analytische Eigenschaften - Thermische Eigenschaften definieren durch: Schemaplantypen; Analytische Konstruktion: <Keine Auswahl>
Type - Bemaßungen - Größenberechnung über Lichten Durchgang: yes; Größenberechnung über Maueröffnungsmaß: no; Höhe ab FBOK berechnen: yes; Randabstand Öffnungssymbol: 0 m; Angabe Lichter Durchgang Breite: 0.8 m; Angabe Lichter Durchgang Höhe: 2 m; Angabe Maueröffnungsmaß Breite: 1.55 m; Angabe Maueröffnungsmaß Höhe: 2.285 m; Breite: 1.55 m; Dicke: 0.045 m; Durchgangsbreite: 0.8 m; Durchgangshöhe: 2 m; Glasbreite Seitenteil: 0.61 m; Höhe ab FBOK: 2.045 m; Rohbaubreite: 1.55 m
Type - Daten - Anschlag- / Bewegungsart Tür: Drehflügeltür; Anzahl Flügel: einflügelig; Anzahl Oberlichter: 0; Anzahl Seitenteile: 1; Ausführung Zarge: Umfassungszarge; Form Tür: rechteckig
Type - ID-Daten - Beschreibung: Türen mit Seitenteilen; OmniClass-Nummer: 23.30.10.00; OmniClass-Titel: Doors; Typenkommentare: Rahmenstock mit Seitenteil; Typenmarkierung: 260; Typname: DL - 1460 x 2080; URL: http://www.autodesk.de/BIM
Type - Konstruktion - Funktion: Innen; Wandabschluss: Nach Basisbauteil; Drückerhöhe: 1.05 m; Glasdicke: 0.024 m; Glasflaeche: 1.20475 m2; Kämpferbreite: 0.05 m; Kämpfertiefe: 0.06 m; Rahmendicke: 0.045 m; Rahmendicke Unten: 0.025 m
Type - Sonstige - Kategorie: Türen; Familienname: TU DF 1 - Rahmenstock mit Glasseitenteil
Type - Vollständige Legende - GH: 1.975 m
Type - Pset_DoorCommon - IsExternal: no
OverallHeight: 2.045 m; OverallWidth: 1.55 m
Pset_DoorCommon - Reference: DL - 1460 x 2080
Pset_QuantityTakeOff - Reference: DL - 1460 x 2080
Abhängigkeiten - Ebene: Ebene -1 Basement Phase 6; Wandaufbau Bandseite: 0 m; Wandaufbau Gegenbandseite: 0 m; Winkel Öffnungsbogen: 90 deg; Fußbodenaufbau: 0 m; Schwelle/Brüstung: 0 m; Anschlagseite gespiegelt: no
Bemaßungen - Fläche: 9.22246 m2; Höhe: 2.045 m; Rohbauhöhe: 2.045 m; Volumen: 0.000224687 m3
Grafiken - Grundrissdarstellung Türsturz: no; Kollisionskörper einschalten: no; Tür mit Anschlag: no
ID-Daten - Kennzeichen: TU 8
Phasen - Phase erstellt: Phase 7 2019
Schichten - Drücker Bandseite: yes; Drücker Gegenbandseite: yes; Zylinderrosette: yes
Sonstige - Anschlagseite nicht gespiegelt: yes; Familie: TU DF 1 - Rahmenstock mit Glasseitenteil; Familie und Typ: TU DF 1 - Rahmenstock mit Glasseitenteil: DL - 1460 x 2080; Host-ID: 2806128; Sturzhöhe: 2.045 m; Typ: DL - 1460 x 2080; Typ-ID: 5626066
Vollständige Legende - Knauf Außenseite: no; Knauf Innenseite: no; Wandstärke: 0.28 m; Wandstärke Gesamt: 0.28 m

# IfcDoor: Tower_entrance_door:Tower_entrance_door, Tower_entrance_door:Tower_entrance_door:6252203
In: Ebene 0 Nave FFL Phase 1 1864
Type - ParameterTakesPrecedence: no; Sizeable: no; Material: Holz - Eiche (2), Quoin Brick
Type - Analytische Eigenschaften - Thermische Eigenschaften definieren durch: Schemaplantypen; Analytische Konstruktion: <Keine Auswahl>
Type - Bemaßungen - Breite: 2.015 m; BreiteInnen: 1.995 m; DoorFaceOffset: 0.32 m; DoorThickness: 0.065 m; FrameFaceOffset: 0.32 m; FrameThickness: 0.0578455 m; FrameWidth: 0.01 m; Höhe: 5 m; InnenRecess: 0.11 m; PanelDepth: 0.00919439 m; SpringingHeight: 2.222 m
Type - ID-Daten - OmniClass-Nummer: 23.30.10.00; OmniClass-Titel: Doors; Typenmarkierung: 263; Typname: Tower_entrance_door
Type - Konstruktion - Funktion: Innen; Wandabschluss: Nach Basisbauteil
Type - Materialien und Oberflächen - FrameMaterial: Holz - Eiche; LintelMaterial: Quoin Brick
Type - Sonstige - Kategorie: Türen; Familienname: Tower_entrance_door; Rahmenbreite: 0.075 m; Rahmenprojektion außen: 0.025 m; Rahmenprojektion innen: 0.025 m
Type - Pset_DoorCommon - IsExternal: no
Type - IfcDoorPanelProperties - PanelDepth: 0.00919439 m
Type - IfcPermeableCoveringProperties - FrameThickness: 0.0578455 m
OverallHeight: 3.93 m; OverallWidth: 2.015 m; Group: Built Phase 2 1888
Pset_DoorCommon - Reference: Tower_entrance_door
Pset_QuantityTakeOff - Reference: Tower_entrance_door
Abhängigkeiten - Ebene: Ebene 0 Nave FFL Phase 1 1864; Schwelle/Brüstung: 0 m
Bemaßungen - Fläche: 7.13197 m2; Volumen: 0.547877 m3
ID-Daten - Kennzeichen: TU 59
Phasen - Phase erstellt: Phase 2 1888
Sonstige - Familie: Tower_entrance_door; Familie und Typ: Tower_entrance_door: Tower_entrance_door; Host-ID: 6249498; Sturzhöhe: 5 m; Typ: Tower_entrance_door; Typ-ID: 6252184

# IfcFlowSegment: Rinne:Dachrinne 150 x 100:4041 (3)
In: Ebene 2 Gallery Stage 1
Type - ElementType: Rinne:Dachrinne 150 x 100:4041; PredefinedType: GUTTER
Pset_DistributionFlowElementCommon - Reference: Dachrinne 150 x 100; sets with these values: 2
Pset_PipeSegmentTypeGutter - Slope: 0 deg
Phasen - Phase erstellt: Phase 1 1864
Profil - Winkel: 0 deg
Sonstige - Familie: Rinne; Familie und Typ: Rinne: Dachrinne 150 x 100; Kategorie: Dächer: Rinnen; Typ: Dachrinne 150 x 100; Typ-ID: 4041
ID-Daten(Type) - Typname: Dachrinne 150 x 100
Konstruktion(Type) - Profil: Dachrinne - rechteckig : 150 x 100
Materialien und Oberflächen(Type) - Material: Kunststoff - grau 70-70-70
Sonstige(Type) - Kategorie: Dächer: Rinnen; Familienname: Rinne
Group: Modellgruppe:BasementChimney:6973904; Built Phase 1 1864
Name (Rinne:Dachrinne 150 x 100:...) | Length (m) | sets with these values | Horizontaler Profilversatz (m) | Vertikaler Profilversatz (m) | Länge (m)
2543941 | 19.2062 | 2 | -0.05 | 0.1 | 19.2062
5244943 |  |  | 0 | 0 | 10.448
7682850 | 4.63757 | 2 | -0.05 | 0.1 | 4.63757

# IfcFlowSegment: Rohrtypen:Standard, Rohrtypen:Standard:6955627
In: Ebene -1 Basement Phase 6
Type - ID-Daten - Typname: Standard
Type - Sonstige - Kategorie: Rohre; Familienname: Rohrtypen
Pset_DistributionFlowElementCommon - Reference: Standard; sets with these values: 2
Pset_FlowSegmentDuctSegment - Length: 0.38 m; sets with these values: 2
Abhängigkeiten - Horizontale Ausrichtung: Mitte; Mittlere Endhöhe: 2.7432 m; Mittlere Höhe: 2.7432 m; Mittlere Starthöhe: 2.7432 m; Neigung: 0; Oberes Ende - Höhe Rohrinnenseite: 2.66522 m; Oberes Ende - Mittellinienhöhe: 2.7432 m; Oberes Ende - Oberkante: 2.83083 m; Oberes Ende - Scheitelhöhe: 2.82118 m; Oberes Ende - Unterkante: 2.65557 m; Referenzebene: Ebene -1 Basement Phase 6; Unteres Ende - Höhe Rohrinnenseite: 2.66522 m; Unteres Ende - Mittellinienhöhe: 2.7432 m; Unteres Ende - Oberkante: 2.83083 m; Unteres Ende - Scheitelhöhe: 2.82118 m; Unteres Ende - Unterkante: 2.65557 m; Vertikale Ausrichtung: Mitte
Bemaßungen - Außendurchmesser: 0.17526 m; Größe: 150 mmø; Innendurchmesser: 0.155956 m; Länge: 0.38 m
HLS - Bauteilliste/Typ: 22; Durchmesser: 0.15 m; Fläche: 0.179071 m2; Höhe Rohrinnenseite: -0.409778 m; Rauigkeit: 0.00025908 m; Rohrsegment: Duktiles Gusseisen - 22; Schnitt: 1; Systemklassifizierung: Vorlauf; Systemname: Heizung Vorlauf 1; Systemtyp: Heizung Vorlauf; Verbindungstyp: Generisch
HLS - Volumenstrom - Druckverlust: 0 Pa; Geschwindigkeit: 0 m/s; Reibung: 0; Reibungsfaktor: 0; Relative Rauigkeit: 0.00166124; Reynoldszahl: 0; Volumenstrom: 0 m3/s; Volumenstromzustand: Laminar; Zusätzlicher Volumenstrom: 0 m3/s
Isolierung - Dämmungsstärke außen: 0 m; Gesamtmaß: 150 mmø; Oberes Ende - Oberkante der Dämmungshöhe: 2.83083 m; Oberes Ende - Unterkante der Dämmungshöhe: 2.65557 m; Unteres Ende - Oberkante der Dämmungshöhe: 2.83083 m; Unteres Ende - Unterkante der Dämmungshöhe: 2.65557 m
Phasen - Phase erstellt: Phase 6 1966
Sonstige - Typ: Standard; Familie: Rohrtypen; Familie und Typ: Rohrtypen: Standard; Typ-ID: 824904
Group: Heizung Vorlauf 1

# IfcGroup (6)
Name | Description
Built Phase 1 1864 | {"type": "BBIM_Search", "query": "IfcTypeProduct, IfcProduct, \"Phasen\".\"Phase erstellt\" = \"Phase 1 1864\""}
Built Phase 2 1888 | {"type": "BBIM_Search", "query": "IfcTypeProduct, IfcProduct, \"Phasen\".\"Phase erstellt\" = \"Phase 2 1888\""}
Built Phase 4 1950 | {"type": "BBIM_Search", "query": "IfcTypeProduct, IfcProduct, \"Phasen\".\"Phase erstellt\" = \"Phase 4 1950\""}
Demolished Phase 2 1888 | {"type": "BBIM_Search", "query": "IfcTypeProduct, IfcProduct, \"Phasen\".\"Phase abgebrochen\" = \"Phase 2 1888\""}
Completion Phase 2 1888 | {"type": "BBIM_Search", "query": "IfcTypeProduct, IfcProduct, \"Phasen\".\"Phase erstellt\" = \"Phase 1 1864\", \"Phasen\".\"Phase erstellt\" = \"Phase 2 1888\", \"Phasen\".\"Phase abgebrochen\" != \"Phase 2 1888\""}
Foundation

# IfcGroup: Modellgruppe:BasementChimney, Modellgruppe:BasementChimney:6973904
Abhängigkeiten - Versatz der Ursprungsebene: 0 m; Referenzebene: Ebene -1 Basement Phase 6
Sonstige - Familie: Modellgruppe; Kategorie: Modellgruppen; Familie und Typ: Modellgruppe: BasementChimney; Typ: BasementChimney; Typ-ID: 6973905
ID-Daten(Type) - Typname: BasementChimney
Sonstige(Type) - Kategorie: Modellgruppen; Familienname: Modellgruppe

# IfcGroup: Modellgruppe:BasementSteps 3, Modellgruppe:BasementSteps 3 (Mitglieder ausgeschlossen):5636261
Abhängigkeiten - Versatz der Ursprungsebene: 0 m; Referenzebene: Ebene -1 Basement Phase 6
Sonstige - Familie: Modellgruppe; Kategorie: Modellgruppen; Familie und Typ: Modellgruppe: BasementSteps 3; Typ: BasementSteps 3; Typ-ID: 7046939
ID-Daten(Type) - Typname: BasementSteps 3
Sonstige(Type) - Kategorie: Modellgruppen; Familienname: Modellgruppe

# IfcGroup: Modellgruppe:TowerFloor, Modellgruppe:TowerFloor (Mitglieder ausgeschlossen):6235494
Abhängigkeiten - Versatz der Ursprungsebene: 0 m; Referenzebene: Ebene 0 Nave FFL Phase 1 1864
Sonstige - Familie: Modellgruppe; Kategorie: Modellgruppen; Familie und Typ: Modellgruppe: TowerFloor; Typ: TowerFloor; Typ-ID: 6235495
ID-Daten(Type) - Typname: TowerFloor
Sonstige(Type) - Kategorie: Modellgruppen; Familienname: Modellgruppe

# IfcGroup: Modellgruppe:Tracery Centre West Stage1 (2)
Abhängigkeiten - Referenzebene: Ebene Windows; Versatz der Ursprungsebene: 0 m
Sonstige - Familie: Modellgruppe; Familie und Typ: Modellgruppe: Tracery Centre West Stage1; Kategorie: Modellgruppen; Typ: Tracery Centre West Stage1; Typ-ID: 2967060
ID-Daten(Type) - Typname: Tracery Centre West Stage1
Sonstige(Type) - Kategorie: Modellgruppen; Familienname: Modellgruppe
Name (Modellgruppe:Tracery Centre West Stage1:...)
2490062
5400091

# IfcGroup: Modellgruppe:Window1a-Stage2, Modellgruppe:Window1a-Stage2:2490749
Abhängigkeiten - Referenzebene: Ebene Windows; Versatz der Ursprungsebene: 0 m
Sonstige - Familie: Modellgruppe; Kategorie: Modellgruppen; Familie und Typ: Modellgruppe: Window1a-Stage2; Typ: Window1a-Stage2; Typ-ID: 2885270
ID-Daten(Type) - Typname: Window1a-Stage2
Sonstige(Type) - Kategorie: Modellgruppen; Familienname: Modellgruppe

# IfcGroup: Modellgruppe:Window1b-Stage1 (3)
Abhängigkeiten - Referenzebene: Ebene Windows; Versatz der Ursprungsebene: 0 m
Sonstige - Familie: Modellgruppe; Kategorie: Modellgruppen; Familie und Typ: Modellgruppe: Window1b-Stage1; Typ: Window1b-Stage1; Typ-ID: 2885625
ID-Daten(Type) - Typname: Window1b-Stage1
Sonstige(Type) - Kategorie: Modellgruppen; Familienname: Modellgruppe
Name (Modellgruppe:Window1b-Stage1:...)
2490593
2490817
3020746

# IfcOpeningElement: Opening (13)
Name | In | Classification | Pset_QuantityTakeOff, Reference | Pset_QuantityTakeOff, sets with these values | Länge (m) | Kategorie
TU DF 1 - Pfostenstock flächenbündig:Belfry Door:7426829:1 | Ebene 3 Belfry FFL Stage 2 1888
5 x Basiswand:Ziegel 780 72x265 English bond Stage 1 Main pier test:5054610 | Ebene 0 Nave FFL Phase 1 1864 | B2010150 Ext. Wall - Brick (Single Wythe) (Uniformat) | Ziegel 780 72x265 English bond Stage 1 Main pier test | 2 | 0.121 | Linien: <Skizze>
4 x Basiswand:Ziegel 780 72x265 English bond Stage 1 Main pier test:5054610 | Ebene 0 Nave FFL Phase 1 1864 | B2010150 Ext. Wall - Brick (Single Wythe) (Uniformat) |  |  | 0.129512 | Linien: <Skizze> | Pset_OpeningElementCommon - Reference: Ziegel 780 72x265 English bond Stage 1 Main pier test; sets with these values: 2
Basiswand:Ziegel 780 72x265 English bond Stage 1 Main pier test:5054610 | Ebene 0 Nave FFL Phase 1 1864 | B2010150 Ext. Wall - Brick (Single Wythe) (Uniformat) |  |  | 0.121 | Linien: <Skizze> | Pset_OpeningElementCommon - Reference: Ziegel 780 72x265 English bond Stage 1 Main pier test; sets with these values: 2
2 x Basiswand:Ziegel 780 72x265 English bond Stage 1 Main pier test:5054610 | Ebene 0 Nave FFL Phase 1 1864 | B2010150 Ext. Wall - Brick (Single Wythe) (Uniformat) | Ziegel 780 72x265 English bond Stage 1 Main pier test | 2 | 0.129512 | Linien: <Skizze>

# IfcRoof: Basisdach:Schieferdach 250, Basisdach:Schieferdach 250:2586895
Material: Dachdeckung - Ziegeldach 0.04 m, Dachdeckung - Holz 0.02 m, Dämmung - weich 0.15 m, Luftschicht 0.02 m, Dachdeckung - Holz 0.02 m; Group: Built Phase 2 1888
Pset_QuantityTakeOff - Reference: Schieferdach 250
Pset_RoofCommon - IsExternal: yes; Reference: Schieferdach 250; ProjectedArea: 56.9703 m2; TotalArea: 97.9802 m2
Abhängigkeiten - Für Körper: no; Raumbegrenzung: no; Zuschnittsversatz oben: 0 m; Basisebene: Office roof eaves Stage 2; Basisversatz von Ebene: -0.302833 m
Bemaßungen - Dicke: 0.25 m; Fläche: 97.9802 m2; Neigung: 54.5; Volumen: 23.465 m3
Konstruktion - Dachabschluss Traufe: Lotrecht zur Dachhaut mit Zuschnitt unten; Firsthöhe von Ebene: 10.1128 m; Zuschnittsversatz unten: 0.15 m
Phasen - Phase erstellt: Phase 2 1888
Sonstige - Familie: Basisdach; Kategorie: Dächer; Familie und Typ: Basisdach: Schieferdach 250; Typ: Schieferdach 250; Typ-ID: 7666320
Analytische Eigenschaften(Type) - Rauigkeit: 1; Absorptionsgrad: 0.1; Thermischer Widerstand (R): 5.25938; Thermisch wirksame Masse: 82.1241; Wärmedurchgangskoeffizient (U): 0.190136 kg/K/s3
Grafiken(Type) - Farbfüllung für groben Maßstab: 12632256
ID-Daten(Type) - Typenkommentare: Ziegeldach; Typname: Schieferdach 250
Konstruktion(Type) - Standarddicke: 0.25 m
Sonstige(Type) - Kategorie: Dächer; Familienname: Basisdach

# IfcSlab: Geschossdecke:STB 185, Geschossdecke:STB 185:3863575
In: Ebene New Gallery Stage 6
Type - PredefinedType: FLOOR; Material: Ortbeton - bewehrt 0.185 m
Type - Analytische Eigenschaften - Rauigkeit: 1; Absorptionsgrad: 0.1; Thermischer Widerstand (R): 0.176864; Thermisch wirksame Masse: 279.553; Wärmedurchgangskoeffizient (U): 5.65405 kg/K/s3
Type - Grafiken - Füllmuster für groben Maßstab: <Flächenfüllung>; Farbfüllung für groben Maßstab: 32768
Type - ID-Daten - Beschreibung: STB_250; Typname: STB 185
Type - Konstruktion - Funktion: Innen; Standarddicke: 0.185 m
Type - Materialien und Oberflächen - Tragendes Material: Ortbeton - bewehrt
Type - Sonstige - Kategorie: Geschossdecken; Familienname: Geschossdecke
Type - Tragwerk - Filter Tragend / Nichttragend: yes
Type - Pset_SlabCommon - IsExternal: no; ThermalTransmittance: 5.65405 kg/K/s3
Pset_QuantityTakeOff - Reference: STB 185; sets with these values: 2
Pset_SlabCommon - LoadBearing: yes; PitchAngle: 0 deg; Reference: STB 185
Abhängigkeiten - Für Körper: no; Raumbegrenzung: no; Höhenversatz von Ebene: 0 m; Ebene: Ebene New Gallery Stage 6
Bemaßungen - Dicke: 0.185 m; Fläche: 31.0873 m2; Höhe oben: 3.61 m; Höhe oben Kern: 3.61 m; Höhe unten: 3.425 m; Höhe unten Kern: 3.425 m; Höhe Vermessung oben: 3.61 m; Höhe Vermessung unten: 3.425 m; Kernstärke: 0.185 m; Umfang: 26.788 m; Volumen: 5.75115 m3
ID-Daten - Hat Verknüpfung: no
Phasen - Phase erstellt: Phase 6 1966
Sonstige - Familie: Geschossdecke; Familie und Typ: Geschossdecke: STB 185; Typ: STB 185; Typ-ID: 7043832
Tragwerk - Betonüberdeckung - Andere Flächen: c=2.0cm <2,0 cm>; Tragwerk: yes; Betonüberdeckung - Obere Fläche: c=2.0cm <2,0 cm>; Betonüberdeckung - Untere Fläche: c=2.0cm <2,0 cm>

# IfcSlab: Geschossdecke:STB 250, Geschossdecke:STB 250:6433906
In: Ebene 3 Belfry FFL Stage 2 1888
Type - PredefinedType: FLOOR; Material: Ortbeton - bewehrt 0.25 m
Type - Analytische Eigenschaften - Rauigkeit: 1; Absorptionsgrad: 0.1; Thermischer Widerstand (R): 0.239006; Thermisch wirksame Masse: 377.775; Wärmedurchgangskoeffizient (U): 4.184 kg/K/s3
Type - Grafiken - Füllmuster für groben Maßstab: <Flächenfüllung>; Farbfüllung für groben Maßstab: 32768
Type - ID-Daten - Beschreibung: STB_250; Typname: STB 250
Type - Konstruktion - Funktion: Innen; Standarddicke: 0.25 m
Type - Materialien und Oberflächen - Tragendes Material: Ortbeton - bewehrt
Type - Sonstige - Kategorie: Geschossdecken; Familienname: Geschossdecke
Type - Tragwerk - Filter Tragend / Nichttragend: yes
Type - Pset_SlabCommon - IsExternal: no; ThermalTransmittance: 4.184 kg/K/s3
Pset_QuantityTakeOff - Reference: STB 250; sets with these values: 2
Pset_SlabCommon - LoadBearing: yes; PitchAngle: 0 deg; Reference: STB 250
Abhängigkeiten - Für Körper: no; Raumbegrenzung: yes; Höhenversatz von Ebene: 0 m; Ebene: Ebene 3 Belfry FFL Stage 2 1888
Bemaßungen - Dicke: 0.25 m; Fläche: 7.28869 m2; Höhe oben: 5.11 m; Höhe oben Kern: 5.11 m; Höhe unten: 4.86 m; Höhe unten Kern: 4.86 m; Höhe Vermessung oben: 5.11 m; Höhe Vermessung unten: 4.86 m; Kernstärke: 0.25 m; Umfang: 11.019 m; Volumen: 1.82217 m3
ID-Daten - Hat Verknüpfung: no
Phasen - Phase erstellt: Phase 2 1888
Sonstige - Familie: Geschossdecke; Familie und Typ: Geschossdecke: STB 250; Typ: STB 250; Typ-ID: 712246
Tragwerk - Betonüberdeckung - Andere Flächen: c=2.0cm <2,0 cm>; Tragwerk: yes; Betonüberdeckung - Obere Fläche: c=2.0cm <2,0 cm>; Betonüberdeckung - Untere Fläche: c=2.0cm <2,0 cm>
Group: Built Phase 2 1888

# IfcSystem: Heizung Vorlauf, Heizung Vorlauf 1
HLS - Anzahl von Elementen: 0; Systemname: Heizung Vorlauf 1; Volumen: 0.00725901 m3
Sonstige - Familie: Rohrsystem; Familie und Typ: Rohrsystem: Heizung Vorlauf; Kategorie: Rohr Systeme; Typ: Heizung Vorlauf; Typ-ID: 768274

# IfcWall: Basiswand:Ziegel 595 farbig rohbau 72 English bond 2 (2)
Type - PredefinedType: STANDARD; Material: Mauerwerk - Sichtmauerwerk_72x265 english bond 0.25 m, Mauerwerk - Naturstein Weiß 0.345 m
Type - Analytische Eigenschaften - Absorptionsgrad: 0.1; Rauigkeit: 1; Thermischer Widerstand (R): 0.462963; Thermisch wirksame Masse: 325.5; Wärmedurchgangskoeffizient (U): 2.16 kg/K/s3
Type - Grafiken - Farbfüllung für groben Maßstab: 4210816; Füllmuster für groben Maßstab: <Flächenfüllung>
Type - ID-Daten - Beschreibung: Ziegel 620 farbig verputzt 1s 72 English bond; Typname: Ziegel 595 farbig rohbau 72 English bond 2
Type - Konstruktion - Abschluss an Öffnungen: Beide; Abschluss an Wänden: Keine; Breite: 0.595 m; Funktion: Außen
Type - Sonstige - Kategorie: Wände; Familienname: Basiswand
Type - Tragwerk - Filter Tragend / Nichttragend: yes
Type - Pset_WallCommon - ThermalTransmittance: 2.16 kg/K/s3; IsExternal: yes
EPset_Parametric - Engine: BlenderBIM.DumbLayer2
Phasen - Phase erstellt: Phase 1 1864; Phase abgebrochen: Phase 4 1950
Name
Window Infil north west
Window Infil north east

# IfcWallStandardCase: Basiswand:Ziegel 100, Basiswand:Ziegel 100:7752681
In: Ebene 3 Belfry FFL Stage 2 1888
Type - PredefinedType: STANDARD; Material: Mauerwerk - Ziegel 0.1 m
Type - Analytische Eigenschaften - Rauigkeit: 1; Absorptionsgrad: 0.1; Thermischer Widerstand (R): 0.185185; Thermisch wirksame Masse: 130.2; Wärmedurchgangskoeffizient (U): 5.4 kg/K/s3
Type - Grafiken - Füllmuster für groben Maßstab: <Flächenfüllung>; Farbfüllung für groben Maßstab: 255
Type - ID-Daten - Beschreibung: Ziegel_100; Typname: Ziegel 100
Type - Konstruktion - Abschluss an Wänden: Keine; Abschluss an Öffnungen: Keine; Funktion: Innen; Breite: 0.1 m
Type - Materialien und Oberflächen - Tragendes Material: Mauerwerk - Ziegel
Type - Sonstige - Kategorie: Wände; Familienname: Basiswand
Type - Tragwerk - Filter Tragend / Nichttragend: no
Type - Pset_WallCommon - IsExternal: no; ThermalTransmittance: 5.4 kg/K/s3
Abhängigkeiten - Für Körper: no; Oberkante ist fixiert.: no; Raumbegrenzung: yes; Unterkante ist fixiert: no; Verlängerungsabstand oben: 0 m; Verlängerungsabstand unten: 0 m; Versatz unten: 0 m; Basislinie: Tragende Schicht: Außenkante; Abhängigkeit oben: Bis Ebene: Ebene 3 Belfry FFL Stage 2 1888; Abhängigkeit unten: Ebene 3 Belfry FFL Stage 2 1888; Nicht verknüpfte Höhe: 3 m; Versatz oben: 3 m
Bemaßungen - Fläche: 8.022 m2; Länge: 3.023 m; Volumen: 0.8022 m3
ID-Daten - Hat Verknüpfung: yes
Phasen - Phase erstellt: Phase 2 1888
Querschnittsdefinition - Querschnitt: Vertikal
Sonstige - Familie: Basiswand; Familie und Typ: Basiswand: Ziegel 100; Typ: Ziegel 100; Typ-ID: 712209
Tragwerk - Betonüberdeckung - Andere Flächen: c=2.0cm <2,0 cm>; Betonüberdeckung - Außenfläche: c=2.0cm <2,0 cm>; Betonüberdeckung - Innenfläche: c=2.0cm <2,0 cm>; Tragwerk: yes; Tragwerksverwendung: Tragend
Pset_QuantityTakeOff - Reference: Ziegel 100; sets with these values: 2
Pset_WallCommon - ExtendToStructure: no; LoadBearing: yes; Reference: Ziegel 100
Group: Built Phase 2 1888

# IfcWallStandardCase: Basiswand:Ziegel 135, Basiswand:Ziegel 135:7753620
In: Ebene 3 Belfry FFL Stage 2 1888
Type - PredefinedType: STANDARD; Material: Mauerwerk - Kalkputz-white 0.015 m, Mauerwerk - Ziegel 0.12 m
Type - Analytische Eigenschaften - Rauigkeit: 1; Absorptionsgrad: 0.1; Thermischer Widerstand (R): 0.227395; Thermisch wirksame Masse: 190.89; Wärmedurchgangskoeffizient (U): 4.39764 kg/K/s3
Type - Grafiken - Füllmuster für groben Maßstab: <Flächenfüllung>; Farbfüllung für groben Maßstab: 255
Type - ID-Daten - Beschreibung: Ziegel_100; Typname: Ziegel 135
Type - Konstruktion - Abschluss an Wänden: Keine; Abschluss an Öffnungen: Keine; Funktion: Innen; Breite: 0.135 m
Type - Materialien und Oberflächen - Tragendes Material: Mauerwerk - Ziegel
Type - Sonstige - Kategorie: Wände; Familienname: Basiswand
Type - Tragwerk - Filter Tragend / Nichttragend: no
Type - Pset_WallCommon - IsExternal: no; ThermalTransmittance: 4.39764 kg/K/s3
Abhängigkeiten - Basislinie: Wandachse; Für Körper: no; Oberkante ist fixiert.: no; Raumbegrenzung: yes; Unterkante ist fixiert: no; Verlängerungsabstand oben: 0 m; Verlängerungsabstand unten: 0 m; Versatz unten: 0 m; Abhängigkeit oben: Bis Ebene: Ebene 3 Belfry FFL Stage 2 1888; Abhängigkeit unten: Ebene 3 Belfry FFL Stage 2 1888; Nicht verknüpfte Höhe: 3 m; Versatz oben: 3 m
Bemaßungen - Fläche: 1.61084 m2; Länge: 0.616946 m; Volumen: 0.217463 m3
ID-Daten - Hat Verknüpfung: yes
Phasen - Phase erstellt: Phase 2 1888
Querschnittsdefinition - Querschnitt: Vertikal
Sonstige - Familie: Basiswand; Familie und Typ: Basiswand: Ziegel 135; Typ: Ziegel 135; Typ-ID: 7753936
Tragwerk - Betonüberdeckung - Andere Flächen: c=2.0cm <2,0 cm>; Betonüberdeckung - Außenfläche: c=2.0cm <2,0 cm>; Betonüberdeckung - Innenfläche: c=2.0cm <2,0 cm>; Tragwerk: yes; Tragwerksverwendung: Tragend
Pset_QuantityTakeOff - Reference: Ziegel 135; sets with these values: 2
Pset_WallCommon - ExtendToStructure: no; LoadBearing: yes; Reference: Ziegel 135
Group: Built Phase 2 1888

# IfcWallStandardCase: Basiswand:Ziegel 160 farbig putz 2s Tower lobby Phase 2, Basiswand:Ziegel 160 farbig putz 2s Tower lobby Phase 2:7426531
In: Ebene 3 Belfry FFL Stage 2 1888
Type - PredefinedType: STANDARD; Material: Mauerwerk - Kalkputz-white 0.02 m, Mauerwerk - Sichtmauerwerk_72x265 english bond Stage 3 0.12 m, Mauerwerk - Kalkputz-white 0.02 m
Type - Analytische Eigenschaften - Rauigkeit: 1; Absorptionsgrad: 0.1; Thermischer Widerstand (R): 0.236015; Thermisch wirksame Masse: 248.64; Wärmedurchgangskoeffizient (U): 4.23701 kg/K/s3
Type - Grafiken - Füllmuster für groben Maßstab: <Flächenfüllung>; Farbfüllung für groben Maßstab: 255
Type - ID-Daten - Beschreibung: Ziegel_250; Typname: Ziegel 160 farbig putz 2s Tower lobby Phase 2
Type - Konstruktion - Abschluss an Wänden: Keine; Abschluss an Öffnungen: Keine; Funktion: Innen; Breite: 0.16 m
Type - Sonstige - Kategorie: Wände; Familienname: Basiswand
Type - Tragwerk - Filter Tragend / Nichttragend: yes
Type - Pset_WallCommon - IsExternal: no; ThermalTransmittance: 4.23701 kg/K/s3
Abhängigkeiten - Basislinie: Wandachse; Für Körper: no; Oberkante ist fixiert.: no; Unterkante ist fixiert: no; Verlängerungsabstand oben: 0 m; Verlängerungsabstand unten: 0 m; Versatz unten: 0 m; Raumbegrenzung: no; Abhängigkeit oben: Bis Ebene: Ebene 3 Belfry FFL Stage 2 1888; Abhängigkeit unten: Ebene 3 Belfry FFL Stage 2 1888; Nicht verknüpfte Höhe: 3.17 m; Versatz oben: 3.17 m
Bemaßungen - Fläche: 6.5451 m2; Länge: 2.7 m; Volumen: 1.04722 m3
ID-Daten - Hat Verknüpfung: no
Phasen - Phase erstellt: Phase 2 1888
Querschnittsdefinition - Querschnitt: Vertikal
Sonstige - Familie: Basiswand; Familie und Typ: Basiswand: Ziegel 160 farbig putz 2s Tower lobby Phase 2; Typ: Ziegel 160 farbig putz 2s Tower lobby Phase 2; Typ-ID: 7732924
Tragwerk - Betonüberdeckung - Andere Flächen: c=2.0cm <2,0 cm>; Betonüberdeckung - Außenfläche: c=2.0cm <2,0 cm>; Betonüberdeckung - Innenfläche: c=2.0cm <2,0 cm>; Tragwerk: yes; Tragwerksverwendung: Tragend
Pset_QuantityTakeOff - Reference: Ziegel 160 farbig putz 2s Tower lobby Phase 2; sets with these values: 2
Pset_WallCommon - ExtendToStructure: no; LoadBearing: yes; Reference: Ziegel 160 farbig putz 2s Tower lobby Phase 2
Group: Built Phase 2 1888

# IfcWallStandardCase: Basiswand:Ziegel 698-farbig 1sp 72x265 English bond quoins Tower Phase 2, Basiswand:Ziegel 698-farbig 1sp 72x265 English bond quoins Tower Phase 2:7734229
In: Ebene 3 Belfry FFL Stage 2 1888
Type - PredefinedType: STANDARD; Material: Mauerwerk - Quoin Brickwerk 0.448 m, Mauerwerk - Sichtmauerwerk_72x265 english bond Stage2 0.25 m
Type - Analytische Eigenschaften - Rauigkeit: 1; Absorptionsgrad: 0.1; Thermischer Widerstand (R): 0.891261; Thermisch wirksame Masse: 1002.47; Wärmedurchgangskoeffizient (U): 1.12201 kg/K/s3
Type - Grafiken - Füllmuster für groben Maßstab: <Flächenfüllung>; Farbfüllung für groben Maßstab: 255
Type - ID-Daten - Beschreibung: Ziegel_500; Typname: Ziegel 698-farbig 1sp 72x265 English bond quoins Tower Phase 2
Type - Konstruktion - Abschluss an Öffnungen: Beide; Abschluss an Wänden: Außen; Funktion: Innen; Breite: 0.698 m
Type - Sonstige - Kategorie: Wände; Familienname: Basiswand
Type - Tragwerk - Filter Tragend / Nichttragend: yes
Type - Pset_WallCommon - IsExternal: no; ThermalTransmittance: 1.12201 kg/K/s3
Abhängigkeiten - Basislinie: Wandachse; Für Körper: no; Oberkante ist fixiert.: no; Raumbegrenzung: yes; Unterkante ist fixiert: no; Verlängerungsabstand oben: 0 m; Verlängerungsabstand unten: 0 m; Versatz unten: 0 m; Abhängigkeit oben: Bis Ebene: Ebene 3 Belfry FFL Stage 2 1888; Abhängigkeit unten: Ebene 3 Belfry FFL Stage 2 1888; Nicht verknüpfte Höhe: 3.17 m; Versatz oben: 3.17 m
Bemaßungen - Fläche: 8.21664 m2; Länge: 2.592 m; Volumen: 5.73521 m3
Phasen - Phase erstellt: Phase 2 1888
Querschnittsdefinition - Querschnitt: Vertikal
Sonstige - Familie: Basiswand; Familie und Typ: Basiswand: Ziegel 698-farbig 1sp 72x265 English bond quoins Tower Phase 2; Typ: Ziegel 698-farbig 1sp 72x265 English bond quoins Tower Phase 2; Typ-ID: 7730381
Tragwerk - Tragwerk: no; Tragwerksverwendung: Nichttragend
Pset_QuantityTakeOff - Reference: Ziegel 698-farbig 1sp 72x265 English bond quoins Tower Phase 2; sets with these values: 2
Pset_WallCommon - ExtendToStructure: no; LoadBearing: no; Reference: Ziegel 698-farbig 1sp 72x265 English bond quoins Tower Phase 2
Group: Built Phase 2 1888

# IfcWallStandardCase: Basiswand:Ziegel 780 72x265 English bond Stage 1 Main pier test (6)
In: Ebene 0 Nave FFL Phase 1 1864
Type - PredefinedType: STANDARD; Material: Mauerwerk - Sichtmauerwerk_72x265 english bond 0.78 m
Type - Analytische Eigenschaften - Rauigkeit: 1; Absorptionsgrad: 0.1; Thermischer Widerstand (R): 1.44444; Thermisch wirksame Masse: 1015.56; Wärmedurchgangskoeffizient (U): 0.692308 kg/K/s3
Type - Grafiken - Füllmuster für groben Maßstab: <Flächenfüllung>; Farbfüllung für groben Maßstab: 255
Type - ID-Daten - Baugruppenbeschreibung: Ext. Wall - Brick (Single Wythe); Baugruppenkennzeichen: B2010150; Beschreibung: Ziegel_780; Typname: Ziegel 780 72x265 English bond Stage 1 Main pier test
Type - Konstruktion - Abschluss an Öffnungen: Beide; Funktion: Außen; Abschluss an Wänden: Außen; Breite: 0.78 m
Type - Materialien und Oberflächen - Tragendes Material: Mauerwerk - Sichtmauerwerk_72x265 english bond
Type - Sonstige - Kategorie: Wände; Familienname: Basiswand
Type - Tragwerk - Filter Tragend / Nichttragend: yes
Type - Pset_WallCommon - IsExternal: yes; ThermalTransmittance: 0.692308 kg/K/s3
Classification: B2010150 Ext. Wall - Brick (Single Wythe) (Uniformat); Group: Modellgruppe:BasementChimney:6973904; Built Phase 1 1864; Demolished Phase 2 1888
Sonstige - Familie: Basiswand; Familie und Typ: Basiswand: Ziegel 780 72x265 English bond Stage 1 Main pier test; Typ: Ziegel 780 72x265 English bond Stage 1 Main pier test; Typ-ID: 5054610
Bemaßungen - Fläche: 5.18883 m2; Länge: 0.78 m; Volumen: 4.04729 m3
ID-Daten - Hat Verknüpfung: no
Querschnittsdefinition - Querschnitt: Vertikal
Phasen - Phase erstellt: Phase 1 1864; Phase abgebrochen: Phase 2 1888
Pset_WallCommon - ExtendToStructure: no; LoadBearing: yes; Reference: Ziegel 780 72x265 English bond Stage 1 Main pier test
Tragwerk - Betonüberdeckung - Andere Flächen: c=2.0cm <2,0 cm>; Betonüberdeckung - Außenfläche: c=2.0cm <2,0 cm>; Betonüberdeckung - Innenfläche: c=2.0cm <2,0 cm>; Tragwerk: yes; Tragwerksverwendung: Tragend
Abhängigkeiten - Abhängigkeit oben: Bis Ebene: Ebene 0 Nave FFL Phase 1 1864; Abhängigkeit unten: Ebene 0 Nave FFL Phase 1 1864; Für Körper: no; Oberkante ist fixiert.: no; Raumbegrenzung: yes; Unterkante ist fixiert: no; Verlängerungsabstand oben: 0 m; Verlängerungsabstand unten: 0 m; Versatz unten: 0 m; Basislinie: Tragende Schicht: Innenkante; Nicht verknüpfte Höhe: 8.714 m; Versatz oben: 8.714 m
Name (Basiswand:Ziegel 780 72x265 English bond Stage 1 Main pier test:...) | Pset_QuantityTakeOff, Reference | Pset_QuantityTakeOff, sets with these values
4 x 7216053 | Ziegel 780 72x265 English bond Stage 1 Main pier test | 2
2 x 7216053 | Pset_ReinforcementBarPitchOfWall - Reference: Ziegel 780 72x265 English bond Stage 1 Main pier test; sets with these values: 2

# IfcWindow: ArchedOpening with quoins1:ArchedOpening with quoins 3, ArchedOpening with quoins1:ArchedOpening with quoins 3:7400515
In: Ebene 0 Nave FFL Phase 1 1864
Type - ParameterTakesPrecedence: no; Sizeable: no; Material: Quoin Brick (212)
Type - Analytische Eigenschaften(Type) - Thermische Eigenschaften definieren durch: Schemaplantypen; Analytische Konstruktion: <Keine Auswahl>
Type - Bemaßungen(Type) - Breite: 1.48 m; Höhe: 5.182 m; SpringingHeight: 3.881 m
Type - ID-Daten(Type) - OmniClass-Nummer: 23.30.20.00; OmniClass-Titel: Windows; Typenmarkierung: 318; Typname: ArchedOpening with quoins 3
Type - Konstruktion(Type) - Wandabschluss: Nach Basisbauteil
Type - Sonstige(Type) - Kategorie: Fenster; Familienname: ArchedOpening with quoins1; Vorgabewert für Einbauhöhe: 0.85 m
Type - Pset_WindowCommon - IsExternal: no
OverallHeight: 5.47982 m; OverallWidth: 1.48 m; Group: Built Phase 2 1888
Pset_QuantityTakeOff - Reference: ArchedOpening with quoins 3
Pset_WindowCommon - IsExternal: yes; Reference: ArchedOpening with quoins 3
Abhängigkeiten - Ebene: Ebene 0 Nave FFL Phase 1 1864; Schwelle/Brüstung: 0.3 m
Bemaßungen - ArchHeight: 1 m; Fläche: 9.44162 m2; Volumen: 0.312862 m3
ID-Daten - Kennzeichen: East W56
Phasen - Phase erstellt: Phase 2 1888
Sonstige - Kategorie: Fenster; Host-ID: 3229566; Familie: ArchedOpening with quoins1; Familie und Typ: ArchedOpening with quoins1: ArchedOpening with quoins 3; QuoinPairs: BrickQuoin Stack_neu : Corner Quion Stack; Typ: ArchedOpening with quoins 3; Typ-ID: 7400680; Sturzhöhe: 5.482 m

# IfcWindow: Arched_Window_Chancel:Arched_Window_chancel (3)
In: Ebene 0 Nave FFL Phase 1 1864
Type - ParameterTakesPrecedence: no; Sizeable: no; Material: Mauerwerk - Sandstein Rot (2), Mauerwerk - Sichtmauerwerk_72x265, Glas - Baustein (3)
Type - Analytische Eigenschaften - Thermische Eigenschaften definieren durch: Schemaplantypen; Analytische Konstruktion: <Keine Auswahl>
Type - Bemaßungen - AussenMouldingBreite: 0.15 m; AussenMouldingTiefe: 0.15 m; BogenHoehe: 1.15 m; BogenRadius: 1.35 m; Breite: 1.3 m; CillHoehe: 0.15 m; CillTiefe: 0.15 m; FilletRadius: 0.03 m; GlasDicke: 0.01 m; Höhe: 2.45 m; MullionBreite: 0.1 m; MullionOffset: 0.15 m; SeitenMullion: 0.25 m; TraceryCillHoehe: 0.25 m; TraceryRadius: 0.290722 m
Type - ID-Daten - OmniClass-Nummer: 23.30.20.00; OmniClass-Titel: Windows; Typenmarkierung: 223; Typname: Arched_Window_chancel
Type - Konstruktion - Wandabschluss: Nach Basisbauteil
Type - Materialien und Oberflächen - Glas: Glas - Baustein; MaterialAussenProfile: Mauerwerk - Sichtmauerwerk_72x265; MaterialCill: Mauerwerk - Sandstein Rot; MaterialTracery: Mauerwerk - Sandstein Rot
Type - Sonstige - Kategorie: Fenster; Familienname: Arched_Window_Chancel; Vorgabewert für Einbauhöhe: 0.85 m
Type - Pset_WindowCommon - IsExternal: no
OverallHeight: 3.60434 m; Group: Modellgruppe:BasementChimney:6973904; Built Phase 1 1864
Pset_QuantityTakeOff - Reference: Arched_Window_chancel
Pset_WindowCommon - Reference: Arched_Window_chancel
Abhängigkeiten - Ebene: Ebene 0 Nave FFL Phase 1 1864; Schwelle/Brüstung: 2.81 m
Bemaßungen - Fläche: 7.94682 m2; Volumen: 0.433078 m3
Phasen - Phase erstellt: Phase 1 1864
Sonstige - Familie: Arched_Window_Chancel; Familie und Typ: Arched_Window_Chancel: Arched_Window_chancel; Sturzhöhe: 5.26 m; Typ: Arched_Window_chancel; Typ-ID: 3139516
Name (Arched_Window_Chancel:Arched_Window_chancel:...) | OverallWidth (m) | Kennzeichen | Host-ID | Material
2736390 | 1.3 | Chancel W1 | 2406002 | Pset_WindowCommon - IsExternal: yes; ID-Daten - Bild: IMG_20190115_1039350.jpg; Photodocumentation: D:\church_model\
3117996 | 1.45344 | Chancel W2 | 2409984 | Mauerwerk - Sandstein Rot, Mauerwerk - Sichtmauerwerk_72x265, Glas - Baustein
3146273 | 1.3 | Chancel W3 | 2406535 | Mauerwerk - Sandstein Rot, Mauerwerk - Sichtmauerwerk_72x265, Glas - Baustein

# IfcWindow: Arched_Window_North_Facade_2:Arched_Window_North_Facade_2 (2)
In: Ebene 0 Nave FFL Phase 1 1864
Type - ParameterTakesPrecedence: no; Sizeable: no; Material: <Unnamed>, Glas
Type - Analytische Eigenschaften - Thermische Eigenschaften definieren durch: Schemaplantypen; Analytische Konstruktion: <Keine Auswahl>
Type - Bemaßungen - BogenInnen: 0.14 m; Breite: 0.72 m; BreiteInnen: 0.965 m; FensterbankAussen: 0.14 m; FensterbankInnen: 0.765 m; GlasDicke: 0.015 m; Höhe: 1.515 m; InnenBreite: 0.965 m; Springing: 1.01 m; VersatzGlasAussen: 0.14 m
Type - ID-Daten - OmniClass-Nummer: 23.30.20.00; OmniClass-Titel: Windows; Typenmarkierung: 280; Typname: Arched_Window_North_Facade_2
Type - Konstruktion - Wandabschluss: Nach Basisbauteil
Type - Materialien und Oberflächen - FensterbankInnenlMaterial: Mauerwerk - Kalkputz-white; FrameMaterial: Lack - grau 80-80-80; Glass: Glas
Type - Sonstige - Kategorie: Fenster; Familienname: Arched_Window_North_Facade_2; Vorgabewert für Einbauhöhe: 0.85 m
Type - Pset_WindowCommon - IsExternal: no
OverallHeight: 1.74 m; OverallWidth: 0.965 m; Group: Built Phase 4 1950
Pset_QuantityTakeOff - Reference: Arched_Window_North_Facade_2
Pset_WindowCommon - Reference: Arched_Window_North_Facade_2
Abhängigkeiten - Ebene: Ebene 0 Nave FFL Phase 1 1864; Schwelle/Brüstung: 1.37 m
Bemaßungen - Fläche: 1.14379 m2; VersatzGlasInnen: 0.445 m; Volumen: 0.0276568 m3
ID-Daten - Bild: IMG_20190117_1137014_window.jpg (2)
Phasen - Phase erstellt: Phase 4 1950
Sonstige - Host-ID: 2397262; Familie: Arched_Window_North_Facade_2; Familie und Typ: Arched_Window_North_Facade_2: Arched_Window_North_Facade_2; Sturzhöhe: 2.885 m; Typ: Arched_Window_North_Facade_2; Typ-ID: 4213856
Name (Arched_Window_North_Facade_2:Arched_Window_North_Facade_2:...) | Beweisstand | Kennzeichen
3197421 | Assumed date of opening formed | North W1 | Pset_WindowCommon - IsExternal: yes; ID-Daten - Kommentare: Not shown in historical photos; Photodocumentation: D:\church_model\survey_photos\; Text - StainedGlass: Jost assumed 1966
3202386 | Assumed date of opening | North W2

# IfcWindow: Arched_Window_window_family_pulpit:Arched_Window_stained_pulpit, Arched_Window_window_family_pulpit:Arched_Window_stained_pulpit:3138304
In: Ebene 0 Nave FFL Phase 1 1864
Type - ParameterTakesPrecedence: no; Sizeable: no; Material: Glas - Stained - Pulpit, Default
Type - Analytische Eigenschaften - Thermische Eigenschaften definieren durch: Schemaplantypen; Analytische Konstruktion: <Keine Auswahl>
Type - Bemaßungen - ArchOffset: 0.6 m; Breite: 0.695 m; GlassThickness: 0.01905 m; Höhe: 0.7 m; MullionDepth: 0.2032 m; MullionHeight: 0.0508 m; OffsetToExteriorEdge: 0.3 m
Type - ID-Daten - Typenmarkierung: 221; Typname: Arched_Window_stained_pulpit
Type - Konstruktion - Wandabschluss: Nach Basisbauteil
Type - Materialien und Oberflächen - MullionMaterial: Default; PanelMaterial: Glas - Stained - Pulpit
Type - Sonstige - Kategorie: Fenster; Default Sill Height: 1 m; Familienname: Arched_Window_window_family_pulpit; HalfGlassThickness: 0.009525 m
Type - Pset_WindowCommon - IsExternal: no
OverallHeight: 1.43332 m; OverallWidth: 0.695 m; Group: Built Phase 2 1888
Pset_QuantityTakeOff - Reference: Arched_Window_stained_pulpit
Pset_WindowCommon - IsExternal: yes; Reference: Arched_Window_stained_pulpit
Abhängigkeiten - Ebene: Ebene 0 Nave FFL Phase 1 1864; Schwelle/Brüstung: 1 m
Bemaßungen - Fläche: 2.23979 m2; Volumen: 0.109862 m3
ID-Daten - Kennzeichen: FE 141
Phasen - Phase erstellt: Phase 2 1888
Sonstige - Familie: Arched_Window_window_family_pulpit; Familie und Typ: Arched_Window_window_family_pulpit: Arched_Window_stained_pulpit; Host-ID: 2393765; Sturzhöhe: 1.7 m; Typ: Arched_Window_stained_pulpit; Typ-ID: 3137094

# IfcWindow: Office Window:Office Window (4)
In: Ebene 1 FFL Sacristy
Type - ParameterTakesPrecedence: no; Sizeable: no; Material: Mauerwerk - Sichtmauerwerk_72x265 header Stage2 (2), Glas - Baustein Stained Glass Office
Type - Analytische Eigenschaften - Thermische Eigenschaften definieren durch: Schemaplantypen; Analytische Konstruktion: <Keine Auswahl>
Type - Bemaßungen - Breite: 1 m; GlassArchHeight: 0.7 m; GlassCameSetback: 0.175 m; GlassCameThickness: 0.01 m; GlassCameWidth: 0.765 m; GlassSpringingHeight: 1.5 m; Höhe: 2.016 m; InnerCilleEdgeHeight: 0.67 m; OuterCillEdgeHeight: 0.341 m; SideMouldingDrop: 0.125 m; WidthInside: 1.445 m; WidthOverallOutside: 1.635 m
Type - ID-Daten - OmniClass-Nummer: 23.30.20.00; OmniClass-Titel: Windows; Typenmarkierung: 312; Typname: Office Window
Type - Konstruktion - Wandabschluss: Nach Basisbauteil
Type - Materialien und Oberflächen - GlassMaterial: Glas - Baustein Stained Glass Office; LowerCillMaterial: Mauerwerk - Sichtmauerwerk_72x265 header Stage2
Type - Sonstige - Kategorie: Fenster; Familienname: Office Window; Vorgabewert für Einbauhöhe: 0.85 m
Type - Pset_WindowCommon - IsExternal: no
OverallHeight: 3.52505 m; OverallWidth: 1.635 m; Group: Built Phase 2 1888
Pset_QuantityTakeOff - Reference: Office Window
Pset_WindowCommon - Reference: Office Window
Abhängigkeiten - Ebene: Ebene 1 FFL Sacristy; Schwelle/Brüstung: 1.709 m
Phasen - Phase erstellt: Phase 2 1888
Sonstige - Familie: Office Window; Familie und Typ: Office Window: Office Window; Sturzhöhe: 3.725 m; Typ: Office Window; Typ-ID: 7252430
Name (Office Window:Office Window:...) | Fläche (m2) | Volumen (m3) | Kennzeichen | Host-ID
2757986 | 2.42938 | 0.058472 | FE 91 | 2571935 | Pset_WindowCommon - IsExternal: yes
7252463 | 2.42938 | 0.058472 | East W103 | 2571838 | Material: Mauerwerk - Sichtmauerwerk_72x265 header Stage2, Glas - Baustein Stained Glass Office
7252728 | 2.42938 | 0.058472 | East W104 | 2571709 | Material: Mauerwerk - Sichtmauerwerk_72x265 header Stage2, Glas - Baustein Stained Glass Office
7252860 | 2.50355 | 0.0947483 | East W105 | 3503771

# IfcWindow: Office Window:Office Window 2, Office Window:Office Window 2:7253269
In: Ebene 1 FFL Sacristy
Type - ParameterTakesPrecedence: no; Sizeable: no; Material: <Unnamed> (3)
Type - Analytische Eigenschaften - Thermische Eigenschaften definieren durch: Schemaplantypen; Analytische Konstruktion: <Keine Auswahl>
Type - Bemaßungen - Breite: 1 m; GlassArchHeight: 0.7 m; GlassCameSetback: 0.175 m; GlassCameThickness: 0.015 m; GlassCameWidth: 0.765 m; GlassSpringingHeight: 1.5 m; Höhe: 1.016 m; InnerCilleEdgeHeight: 0.67 m; OuterCillEdgeHeight: 0.341 m; SideMouldingDrop: 0.125 m; WidthInside: 1.445 m; WidthOverallOutside: 1.635 m
Type - ID-Daten - OmniClass-Nummer: 23.30.20.00; OmniClass-Titel: Windows; Typenmarkierung: 314; Typname: Office Window 2
Type - Konstruktion - Wandabschluss: Nach Basisbauteil
Type - Sonstige - Kategorie: Fenster; Familienname: Office Window; Vorgabewert für Einbauhöhe: 0.85 m
Type - Pset_WindowCommon - IsExternal: no
OverallHeight: 2.52505 m; OverallWidth: 1.635 m; Group: Built Phase 2 1888
Pset_QuantityTakeOff - Reference: Office Window 2
Pset_WindowCommon - IsExternal: yes; Reference: Office Window 2
Abhängigkeiten - Ebene: Ebene 1 FFL Sacristy; Schwelle/Brüstung: 2.5 m
Bemaßungen - Fläche: 1.65598 m2; Volumen: 0.0463637 m3
ID-Daten - Kennzeichen: East W108
Phasen - Phase erstellt: Phase 2 1888
Sonstige - Host-ID: 2572272; Familie: Office Window; Familie und Typ: Office Window: Office Window 2; Sturzhöhe: 3.516 m; Typ: Office Window 2; Typ-ID: 7253368

# IfcWindow: Office Window_Chapel:Office Window, Office Window_Chapel:Office Window:5656419
In: Ebene 1 FFL Sacristy
Type - ParameterTakesPrecedence: no; Sizeable: no; Material: Mauerwerk - Sichtmauerwerk_72x265 header Stage2, Glas - Baustein Stained Glass Office
Type - Analytische Eigenschaften(Type) - Thermische Eigenschaften definieren durch: Schemaplantypen; Analytische Konstruktion: <Keine Auswahl>
Type - Bemaßungen(Type) - Breite: 1 m; GlassArchHeight: 0.7 m; GlassCameSetback: 0.175 m; GlassCameThickness: 0.01 m; GlassCameWidth: 0.765 m; GlassSpringingHeight: 1.5 m; Höhe: 2.016 m; InnerCilleEdgeHeight: 0.67 m; OuterCillEdgeHeight: 0.341 m; SideMouldingDrop: 0.125 m; WidthInside: 1.445 m; WidthOverallOutside: 1.635 m
Type - ID-Daten(Type) - OmniClass-Nummer: 23.30.20.00; OmniClass-Titel: Windows; Typenmarkierung: 323; Typname: Office Window
Type - Konstruktion(Type) - Wandabschluss: Nach Basisbauteil
Type - Materialien und Oberflächen(Type) - GlassMaterial: Glas - Baustein Stained Glass Office; LowerCillMaterial: Mauerwerk - Sichtmauerwerk_72x265 header Stage2
Type - Sonstige(Type) - Kategorie: Fenster; Familienname: Office Window_Chapel; Vorgabewert für Einbauhöhe: 0.85 m
Type - Pset_WindowCommon - IsExternal: no
OverallHeight: 3.30247 m; OverallWidth: 1.635 m; Group: Built Phase 2 1888
Pset_QuantityTakeOff - Reference: Office Window
Pset_WindowCommon - IsExternal: yes; Reference: Office Window
Abhängigkeiten - Ebene: Ebene 1 FFL Sacristy; Schwelle/Brüstung: 1.709 m
Bemaßungen - Fläche: 2.16068 m2; Volumen: 0.0527659 m3
ID-Daten - Kennzeichen: East W65
Phasen - Phase erstellt: Phase 2 1888
Sonstige - Kategorie: Fenster; Typ: Office Window; Familie: Office Window_Chapel; Familie und Typ: Office Window_Chapel: Office Window; Host-ID: 2413182; Typ-ID: 7641111; Sturzhöhe: 3.725 m

# IfcWindow: Office Window_blind:Office Window (2)
In: Ebene 1 FFL Sacristy
Type - ParameterTakesPrecedence: no; Sizeable: no; Material: Mauerwerk - Sichtmauerwerk_72x265 header Stage2 (2)
Type - Analytische Eigenschaften - Thermische Eigenschaften definieren durch: Schemaplantypen; Analytische Konstruktion: <Keine Auswahl>
Type - Bemaßungen - Breite: 1 m; GlassArchHeight: 0.7 m; GlassCameSetback: 0.175 m; GlassCameThickness: 0.01 m; GlassCameWidth: 0.765 m; GlassSpringingHeight: 1.5 m; Höhe: 2.016 m; InnerCilleEdgeHeight: 0.67 m; OuterCillEdgeHeight: 0.341 m; SideMouldingDrop: 0.125 m; WidthInside: 1.445 m; WidthOverallOutside: 1.635 m
Type - ID-Daten - OmniClass-Nummer: 23.30.20.00; OmniClass-Titel: Windows; Typenmarkierung: 315; Typname: Office Window
Type - Konstruktion - Wandabschluss: Nach Basisbauteil
Type - Materialien und Oberflächen - LowerCillMaterial: Mauerwerk - Sichtmauerwerk_72x265 header Stage2
Type - Sonstige - Kategorie: Fenster; Familienname: Office Window_blind; Vorgabewert für Einbauhöhe: 0.85 m
Type - Pset_WindowCommon - IsExternal: no
OverallHeight: 3.52505 m; OverallWidth: 1.635 m; Group: Built Phase 2 1888
Pset_QuantityTakeOff - Reference: Office Window
Pset_WindowCommon - Reference: Office Window
Abhängigkeiten - Ebene: Ebene 1 FFL Sacristy; Schwelle/Brüstung: 1.709 m
Bemaßungen - Fläche: 0.432127 m2; Volumen: 0.0123985 m3
Phasen - Phase erstellt: Phase 2 1888
Sonstige - Typ: Office Window; Familie: Office Window_blind; Familie und Typ: Office Window_blind: Office Window; Sturzhöhe: 3.725 m; Typ-ID: 7272068
Name (Office Window_blind:Office Window:...) | Kennzeichen | Host-ID
7252449 | East W102 | 3472869 | Pset_WindowCommon - IsExternal: yes
7253177 | East W106 | 2571558

# IfcWindow: QuoinArchAisle:QuoinArch 4200 x 3137 (6)
In: Ebene 0 Nave FFL Phase 1 1864
Type - ParameterTakesPrecedence: no; Sizeable: no; Material: Quoin Brick (216)
Type - Analytische Eigenschaften(Type) - Analytische Konstruktion: <Keine Auswahl>; Thermische Eigenschaften definieren durch: Schemaplantypen
Type - Bemaßungen(Type) - Breite: 4.2 m; GroupAngle: 1.61244 deg; Höhe: 3.137 m
Type - ID-Daten(Type) - OmniClass-Nummer: 23.30.20.00; OmniClass-Titel: Windows; Typenmarkierung: 319; Typname: QuoinArch 4200 x 3137
Type - Konstruktion(Type) - Wandabschluss: Nach Basisbauteil
Type - Materialien und Oberflächen(Type) - QuoinMaterial: Quoin Brick
Type - Sonstige(Type) - Kategorie: Fenster; Familienname: QuoinArchAisle; Vorgabewert für Einbauhöhe: 0.85 m
Type - Pset_WindowCommon - IsExternal: no
OverallHeight: 3.137 m; OverallWidth: 4.2 m; Group: Built Phase 2 1888
Pset_QuantityTakeOff - Reference: QuoinArch 4200 x 3137
Pset_WindowCommon - Reference: QuoinArch 4200 x 3137
Abhängigkeiten - Ebene: Ebene 0 Nave FFL Phase 1 1864; Schwelle/Brüstung: 4.338 m
Bemaßungen - ArchRadius: 4.64363 m; Fläche: 8.68067 m2; RadiusOffset: 2.54363 m; Volumen: 0.268501 m3
Phasen - Phase erstellt: Phase 2 1888
Sonstige - Familie: QuoinArchAisle; Familie und Typ: QuoinArchAisle: QuoinArch 4200 x 3137; Kategorie: Fenster; Typ: QuoinArch 4200 x 3137; Typ-ID: 7445751; NumberPairsLeft: 32; Sturzhöhe: 7.475 m
Name (QuoinArchAisle:QuoinArch 4200 x 3137:...) | Kennzeichen | Host-ID | NumberPairsRight | Material
4717944 | East W45 | 3637241 | 28
4907994 | East W52 | 3637241 | 28 | Quoin Brick
4908133 | East W53 | 3637241 | 28 | Quoin Brick
6130482 | East W86 | 6130382 | 30
6142826 | East W88 | 6142824 | 30 | Quoin Brick
7316829 | East W111 | 7316827 | 30 | Quoin Brick

# IfcWindow: QuoinArchOrgan2:QuoinArchPulpit, QuoinArchOrgan2:QuoinArchPulpit:7636035
In: Ebene 1 FFL Sacristy
Type - ParameterTakesPrecedence: no; Sizeable: no; Material: Quoin Brick (192)
Type - Analytische Eigenschaften - Thermische Eigenschaften definieren durch: Schemaplantypen; Analytische Konstruktion: <Keine Auswahl>
Type - Bemaßungen - Breite: 4.2 m; GroupAngle: 1.61244 deg; Höhe: 3.137 m
Type - ID-Daten - OmniClass-Nummer: 23.30.20.00; OmniClass-Titel: Windows; Typenmarkierung: 320; Typname: QuoinArchPulpit
Type - Konstruktion - Wandabschluss: Nach Basisbauteil
Type - Materialien und Oberflächen - QuoinMaterial: Quoin Brick
Type - Sonstige - Kategorie: Fenster; Familienname: QuoinArchOrgan2; Vorgabewert für Einbauhöhe: 0.85 m
Type - Pset_WindowCommon - IsExternal: no
OverallHeight: 2.6 m; OverallWidth: 3.7 m; Group: Built Phase 2 1888
Pset_QuantityTakeOff - Reference: QuoinArchPulpit
Pset_WindowCommon - Reference: QuoinArchPulpit
Abhängigkeiten - Ebene: Office buttress pier lower capping Top; Schwelle/Brüstung: 2.509 m
Bemaßungen - ArchRadius: 4.64363 m; Fläche: 7.71615 m2; RadiusOffset: 2.54363 m; Volumen: 0.238668 m3
ID-Daten - Kennzeichen: East W122
Phasen - Phase erstellt: Phase 2 1888
Sonstige - Host-ID: 6821057; Familie: QuoinArchOrgan2; Familie und Typ: QuoinArchOrgan2: QuoinArchPulpit; NumberPairsLeft: 32; NumberPairsRight: 30; Sturzhöhe: 5.646 m; Typ: QuoinArchPulpit; Typ-ID: 7621721

# IfcWindow: QuoinArchPulipt:QuoinArchPulipt, QuoinArchPulipt:QuoinArchPulipt:7368511
In: Ebene 1 FFL Sacristy
Type - ParameterTakesPrecedence: no; Sizeable: no; Material: Quoin Brick (96)
Type - Analytische Eigenschaften(Type) - Thermische Eigenschaften definieren durch: Schemaplantypen; Analytische Konstruktion: <Keine Auswahl>
Type - Bemaßungen(Type) - Breite: 1.48 m; GroupAngle: 3 deg; Höhe: 1.2 m; QuoinRadiusLeft: 3.4273 m; Radiusoffset: 0.343625 m
Type - ID-Daten(Type) - OmniClass-Nummer: 23.30.20.00; OmniClass-Titel: Windows; Typenmarkierung: 305; Typname: QuoinArchPulipt
Type - Konstruktion(Type) - Wandabschluss: Nach Basisbauteil
Type - Materialien und Oberflächen(Type) - QuoinMaterial: Quoin Brick
Type - Sonstige(Type) - Kategorie: Fenster; Familienname: QuoinArchPulipt; Vorgabewert für Einbauhöhe: 0.85 m
Type - Pset_WindowCommon - IsExternal: no
OverallHeight: 1.2 m; OverallWidth: 1.48 m; Group: Built Phase 2 1888
Pset_QuantityTakeOff - Reference: QuoinArchPulipt
Pset_WindowCommon - IsExternal: yes; Reference: QuoinArchPulipt
Abhängigkeiten - Ebene: Ebene New Gallery Underside Stage 6; Schwelle/Brüstung: 0.756431 m
Bemaßungen - ArchRadiusLeft: 1.34297 m; ArchRadiusRight: 1.34297 m; Fläche: 3.85808 m2; RadiusOffset: 2.54363 m; Volumen: 0.119334 m3
ID-Daten - Kennzeichen: East W116
Phasen - Phase erstellt: Phase 2 1888
Sonstige - Kategorie: Fenster; Host-ID: 3229566; Familie: QuoinArchPulipt; Familie und Typ: QuoinArchPulipt: QuoinArchPulipt; Typ: QuoinArchPulipt; Typ-ID: 6028164; NumberPairs: 12; Sturzhöhe: 1.95643 m

# IfcWindow: TwinTowerOpening:TwinTowerOpening (2)
Type - ParameterTakesPrecedence: no; Sizeable: no; Material: Glas (2), Mauerwerk - Sandstein Rot (5), Mauerwerk - Sichtmauerwerk_72x265 english bond Stage2 (3)
Type - Analytische Eigenschaften - Thermische Eigenschaften definieren durch: Schemaplantypen; Analytische Konstruktion: <Keine Auswahl>
Type - Bemaßungen - ArchHeight: 0.504 m; ArchRevealWidth: 0.1 m; ArchWidth: 0.664 m; Breite: 1.7 m; BrickArchDepth: 0.13 m; CentrePier: 0.33 m; CillHeight: 0.36 m; CillNoseHeight: 0.0645785 m; CillOverall: 1.75 m; GlassThickness: 0.012 m; Höhe: 1.695 m; MullionWidth: 0.0948571 m; OpeningWidth: 0.71 m; OuterArchHeight: 2.5 m; PostWidth: 0.08 m; SetBack: 0.4 m; TraceryDepth: 0.27 m; TraceryStoenworkDepth: 0.17 m; TraceryThickness: 0.25 m
Type - ID-Daten - OmniClass-Nummer: 23.30.20.00; OmniClass-Titel: Windows; Typenmarkierung: 307; Typname: TwinTowerOpening
Type - Konstruktion - Wandabschluss: Nach Basisbauteil
Type - Materialien und Oberflächen - GlassMaterial: Glas; RevealMaterial: Mauerwerk - Sichtmauerwerk_72x265 english bond Stage2; TraceryMaterial: Mauerwerk - Sandstein Rot
Type - Sonstige - Kategorie: Fenster; Vorgabewert für Einbauhöhe: 0 m; Familienname: TwinTowerOpening; NoBlades: 30
Type - Pset_WindowCommon - IsExternal: no
OverallHeight: 2.199 m; OverallWidth: 1.7 m; Group: Built Phase 2 1888
Pset_QuantityTakeOff - Reference: TwinTowerOpening
Pset_WindowCommon - Reference: TwinTowerOpening
Bemaßungen - Fläche: 6.77652 m2; Volumen: 0.442732 m3
Phasen - Phase erstellt: Phase 2 1888
Sonstige - Familie: TwinTowerOpening; Familie und Typ: TwinTowerOpening: TwinTowerOpening; Typ: TwinTowerOpening; Typ-ID: 6432495
Name (TwinTowerOpening:TwinTowerOpening:...) | In | Schwelle/Brüstung (m) | Ebene | Kennzeichen | Host-ID | Sturzhöhe (m)
6431038 |  | 0 | Main buttress pier lower capping Underside | East W90 | 2830368 | 1.695
6432516 | Ebene New Gallery Stage 6 | 0.860906 | East Buttress Pier Cap Underside | East W91 | 3452861 | 2.55591 | Material: Glas, Mauerwerk - Sandstein Rot, Mauerwerk - Sichtmauerwerk_72x265 english bond Stage2

# IfcBeamType, no part of this type: STB Träger - rechteckig:STB 250 x 250 rechteckig
Bemaßungen - B: 0.25 m; H: 0.25 m
Geometrie von Tragwerksschnitt - Breite: 0.25 m; Höhe: 0.25 m
ID-Daten - Typenkommentare: B/H=25/50cm; Typname: STB 250 x 250 rechteckig
Materialien und Oberflächen - Tragendes Material: Ortbeton - bewehrt Verputzt
Sonstige - Kategorie: Skelettbau; Familienname: STB Träger - rechteckig
Statische Berechnung - Querschnittsfläche: 0.0625 m2; Trägheitsmoment schwache Achse: 0.000325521 m4; Trägheitsmoment starke Achse: 0.000325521 m4; Umfang: 1 m
Tragwerk - Querschnittsform: 31
Pset_BeamCommon - LoadBearing: yes; IsExternal: no

# IfcBeamType, no part of this type: STB Träger - rechteckig:STB 250 x 500
Bemaßungen - B: 0.25 m; H: 0.5 m
Geometrie von Tragwerksschnitt - Breite: 0.25 m; Höhe: 0.5 m
ID-Daten - Typenkommentare: B/H=25/50cm; Typname: STB 250 x 500
Materialien und Oberflächen - Tragendes Material: Ortbeton - bewehrt Verputzt
Sonstige - Kategorie: Skelettbau; Familienname: STB Träger - rechteckig
Statische Berechnung - Querschnittsfläche: 0.125 m2; Trägheitsmoment schwache Achse: 0.000651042 m4; Trägheitsmoment starke Achse: 0.00260417 m4; Umfang: 1.5 m
Tragwerk - Querschnittsform: 31
Pset_BeamCommon - LoadBearing: yes; IsExternal: no

# IfcBuildingElementProxyType, no part of this type: Allgemeines Modell 10:Allgemeines Modell 6
Material: Mauerwerk - Sandstein Rot
ID-Daten - Typname: Allgemeines Modell 6
Sonstige - Kategorie: Allgemeines Modell; Familienname: Allgemeines Modell 10

# IfcBuildingElementProxyType, no part of this type: Allgemeines Modell 11:Allgemeines Modell 3
Material: Mauerwerk - Sichtmauerwerk_72x265 header Stage2
ID-Daten - Typname: Allgemeines Modell 3
Sonstige - Kategorie: Allgemeines Modell; Familienname: Allgemeines Modell 11

# IfcBuildingElementProxyType, no part of this type: Allgemeines Modell 12:Allgemeines Modell 3
Material: Mauerwerk - Sichtmauerwerk_72x265 header Stage2
ID-Daten - Typname: Allgemeines Modell 3
Sonstige - Kategorie: Allgemeines Modell; Familienname: Allgemeines Modell 12

# IfcBuildingElementProxyType, no part of this type: Allgemeines Modell 13:Allgemeines Modell 6
Material: Mauerwerk - Sandstein Rot
ID-Daten - Typname: Allgemeines Modell 6
Sonstige - Kategorie: Allgemeines Modell; Familienname: Allgemeines Modell 13

# IfcBuildingElementProxyType, no part of this type: Allgemeines Modell 14:Allgemeines Modell 14
Material: Mauerwerk - Sandstein Rot
ID-Daten - Typname: Allgemeines Modell 14
Sonstige - Kategorie: Allgemeines Modell; Familienname: Allgemeines Modell 14

# IfcBuildingElementProxyType, no part of this type: Allgemeines Modell 2:Allgemeines Modell 2
Material: Mauerwerk - Sandstein Rot
ID-Daten - Typname: Allgemeines Modell 2
Materialien und Oberflächen - CopingMaterial: Mauerwerk - Sandstein Rot
Sonstige - Kategorie: Allgemeines Modell; Familienname: Allgemeines Modell 2

# IfcBuildingElementProxyType, no part of this type: Allgemeines Modell 3:Allgemeines Modell 3
Material: Mauerwerk - Sichtmauerwerk_72x265 header Stage2
ID-Daten - Typname: Allgemeines Modell 3
Sonstige - Kategorie: Allgemeines Modell; Familienname: Allgemeines Modell 3

# IfcBuildingElementProxyType, no part of this type: Allgemeines Modell 7:Allgemeines Modell 3
Material: Mauerwerk - Sichtmauerwerk_72x265 header Stage2
ID-Daten - Typname: Allgemeines Modell 3
Sonstige - Kategorie: Allgemeines Modell; Familienname: Allgemeines Modell 7

# IfcBuildingElementProxyType, no part of this type: Allgemeines Modell 8:Allgemeines Modell 6
Material: Mauerwerk - Sandstein Rot
ID-Daten - Typname: Allgemeines Modell 6
Sonstige - Kategorie: Allgemeines Modell; Familienname: Allgemeines Modell 8

# IfcBuildingElementProxyType, no part of this type: Allgemeines Modell 9:Allgemeines Modell 6
Material: Mauerwerk - Sandstein Rot
ID-Daten - Typname: Allgemeines Modell 6
Sonstige - Kategorie: Allgemeines Modell; Familienname: Allgemeines Modell 9

# IfcBuildingElementProxyType, no part of this type: ApsePierCAp:ApsePierCAp
Material: Mauerwerk - Sandstein Rot
Abhängigkeiten - Vorgabe-Ansicht: 0 m
Bemaßungen - Breite: 0.51 m; Depth: 0.247156 m; Hoehe: 0.12 m; Tiefe: 0.45 m
ID-Daten - Typname: ApsePierCAp
Materialien und Oberflächen - CapMaterial: Mauerwerk - Sandstein Rot
Sonstige - Kategorie: Allgemeines Modell; Familienname: ApsePierCAp
Pset_ProvisionForVoid - Depth: 0.247156 m

# IfcBuildingElementProxyType, no part of this type: ApsePierCAp:ApsePierCAp
Material: Mauerwerk - Sandstein Rot
Abhängigkeiten - Vorgabe-Ansicht: 0 m
Bemaßungen - Breite: 0.51 m; Depth: 0.247156 m; Hoehe: 0.12 m; Tiefe: 0.45 m
ID-Daten - Typname: ApsePierCAp
Materialien und Oberflächen - CapMaterial: Mauerwerk - Sandstein Rot
Sonstige - Kategorie: Allgemeines Modell; Familienname: ApsePierCAp
Pset_ProvisionForVoid - Depth: 0.247156 m

# IfcBuildingElementProxyType, no part of this type: ApsePierCapEdge:ApsePierCapEdge
Material: Mauerwerk - Sandstein Rot
Abhängigkeiten - Vorgabe-Ansicht: 0 m
Bemaßungen - Breite: 0.51 m; Depth: 0.247156 m; Hoehe: 0.12 m; Tiefe: 0.45 m
ID-Daten - Typname: ApsePierCapEdge
Materialien und Oberflächen - CapMaterial: Mauerwerk - Sandstein Rot
Sonstige - Kategorie: Allgemeines Modell; Familienname: ApsePierCapEdge
Pset_ProvisionForVoid - Depth: 0.247156 m

# IfcBuildingElementProxyType, no part of this type: ApsePierCorbel:PierCorbel
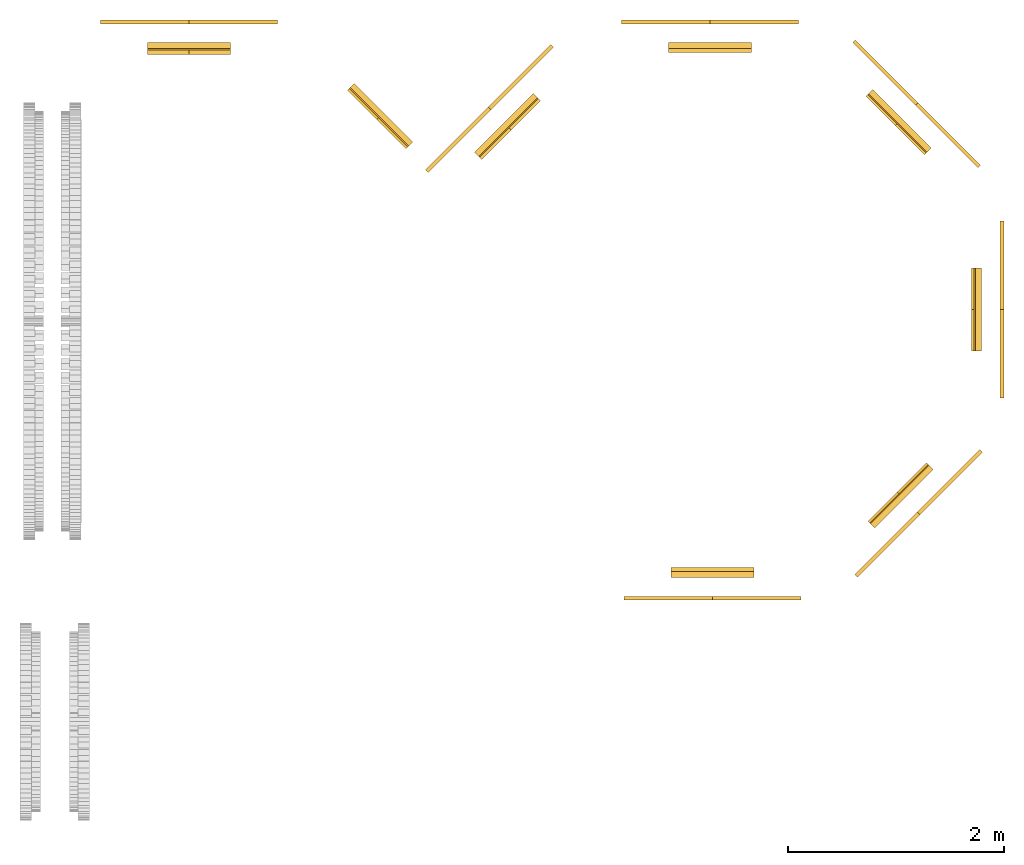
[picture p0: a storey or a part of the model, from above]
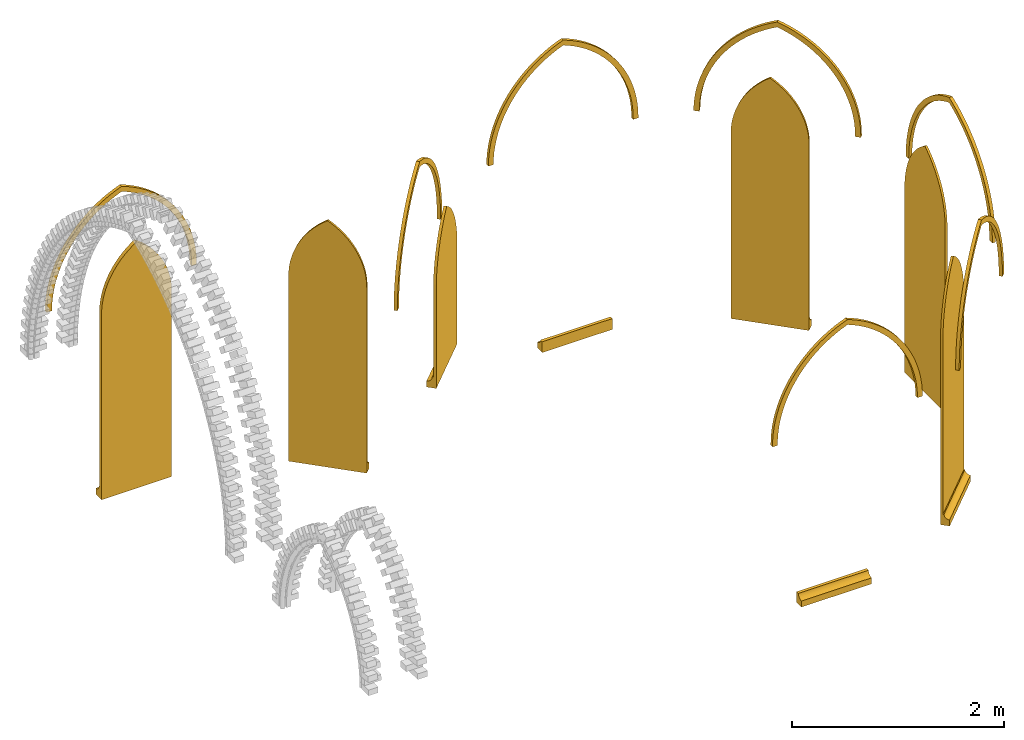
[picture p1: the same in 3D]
Properties of the parts of a building model (IFC2X3), part 3 of 7

# IfcBuildingElementProxyType, no part of this type: ApsePierCorbel:PierCorbel
Material: Mauerwerk - Sandstein Rot
Abhängigkeiten - Vorgabe-Ansicht: 0 m
Bemaßungen - CorbelBreite: 0.51 m
ID-Daten - Typname: PierCorbel
Materialien und Oberflächen - CorbelMaterial: Mauerwerk - Sandstein Rot
Sonstige - Kategorie: Allgemeines Modell; Familienname: ApsePierCorbel

# IfcBuildingElementProxyType, no part of this type: ApsePierCorbel:PierCorbel
Material: Mauerwerk - Sandstein Rot
Abhängigkeiten - Vorgabe-Ansicht: 0 m
Bemaßungen - CorbelBreite: 0.51 m
ID-Daten - Typname: PierCorbel
Materialien und Oberflächen - CorbelMaterial: Mauerwerk - Sandstein Rot
Sonstige - Kategorie: Allgemeines Modell; Familienname: ApsePierCorbel

# IfcBuildingElementProxyType, no part of this type: ArchedWindowFrameMain:Typ 1
Material: Mauerwerk - Sandstein Rot (2), Mauerwerk - Sandstein Rot bemalt, Naturstein - Granit grau
Abhängigkeiten(Type) - Vorgabe-Ansicht: 0 m
Bemaßungen(Type) - ArchHeight: 2.23 m; CillHeight: 0.188655 m; CillThickness: 0.08 m; ClearWidthInside: 1.995 m; DepthInside: 0.26 m; DepthOutside: 0.375 m; FramwWidthOutside: 0.25 m; OaWidthOutside: 2.59 m; OAWithInside: 2.355 m; SpringingHeight: 3.745 m
ID-Daten(Type) - Typname: Typ 1
Materialien und Oberflächen(Type) - OutsideCillMaterial: Mauerwerk - Sandstein Rot; OutsideFrameMaterial: Mauerwerk - Sandstein Rot
Sonstige(Type) - Kategorie: Allgemeines Modell; Familienname: ArchedWindowFrameMain

# IfcBuildingElementProxyType, no part of this type: ArchedWindowFrameMain_External:Red
Material: Mauerwerk - Sandstein Rot (4)
Abhängigkeiten(Type) - Vorgabe-Ansicht: 0 m
Bemaßungen(Type) - ArchHeight: 2.23 m; BrickSkin: 0.25 m; CillHeight: 0.188655 m; CillThickness: 0.08 m; ClearWidthInside: 1.995 m; DepthInside: 0.235 m; DepthOutside: 0.36 m; FramwWidthOutside: 0.25 m; OaWidthOutside: 2.59 m; OAWithInside: 2.236 m; SpringingHeight: 3.595 m
ID-Daten(Type) - Typname: Red
Materialien und Oberflächen(Type) - OutsideCillMaterial: Mauerwerk - Sandstein Rot; OutsideFrameMaterial: Mauerwerk - Sandstein Rot
Sonstige(Type) - Kategorie: Allgemeines Modell; Familienname: ArchedWindowFrameMain_External

# IfcBuildingElementProxyType, no part of this type: ArchedWindowFrameMain_External:Red
Material: Mauerwerk - Sandstein Rot (4)
Abhängigkeiten(Type) - Vorgabe-Ansicht: 0 m
Bemaßungen(Type) - ArchHeight: 2.23 m; BrickSkin: 0.25 m; CillHeight: 0.188655 m; CillThickness: 0.08 m; ClearWidthInside: 1.995 m; DepthInside: 0.235 m; DepthOutside: 0.36 m; FramwWidthOutside: 0.25 m; OaWidthOutside: 2.59 m; OAWithInside: 2.236 m; SpringingHeight: 3.595 m
ID-Daten(Type) - Typname: Red
Materialien und Oberflächen(Type) - OutsideCillMaterial: Mauerwerk - Sandstein Rot; OutsideFrameMaterial: Mauerwerk - Sandstein Rot
Sonstige(Type) - Kategorie: Allgemeines Modell; Familienname: ArchedWindowFrameMain_External

# IfcBuildingElementProxyType, no part of this type: ArchedWindowFrameMain_Internal:1864
Material: <Unnamed> (2)
Abhängigkeiten - Vorgabe-Ansicht: 0 m
Bemaßungen - InternalWidth: 2.179 m; RevealDepth: 0.26 m; SillOverhang: 0.025 m; SillThickness: 0.04 m; Springing: 3.3 m
ID-Daten - Typname: 1864
Sonstige - Kategorie: Allgemeines Modell; Familienname: ArchedWindowFrameMain_Internal

# IfcBuildingElementProxyType, no part of this type: ArchedWindowFrameMain_Internal:1864
Material: <Unnamed> (2)
Abhängigkeiten - Vorgabe-Ansicht: 0 m
Bemaßungen - InternalWidth: 2.179 m; RevealDepth: 0.26 m; SillOverhang: 0.025 m; SillThickness: 0.04 m; Springing: 3.3 m
ID-Daten - Typname: 1864
Sonstige - Kategorie: Allgemeines Modell; Familienname: ArchedWindowFrameMain_Internal

# IfcBuildingElementProxyType, no part of this type: BrickQuoin Stack_neu:Corner Quion Stack
Material: Quoin Brick (50)
Abhängigkeiten - Vorgabe-Ansicht: 0 m
Bemaßungen - No of Quions 1st course: 7; No of Quoins 2nd course: 6; Height of Edge: 2.57 m; Length Long: 0.185 m; Length Short: 0.105 m; QuoinCourse: 0.073 m; Quoin Offset: 0.005 m
ID-Daten - Bauelement: F; Typname: Corner Quion Stack
Materialien und Oberflächen - QuoinMaterial: Quoin Brick
Sonstige - Kategorie: Allgemeines Modell; Familienname: BrickQuoin Stack_neu

# IfcBuildingElementProxyType, no part of this type: BrickQuoin Stack_neu:Corner Quion Stack
Material: Quoin Brick (50)
Abhängigkeiten - Vorgabe-Ansicht: 0 m
Bemaßungen - No of Quions 1st course: 7; No of Quoins 2nd course: 6; Height of Edge: 2.57 m; Length Long: 0.185 m; Length Short: 0.105 m; QuoinCourse: 0.073 m; Quoin Offset: 0.005 m
ID-Daten - Bauelement: F; Typname: Corner Quion Stack
Materialien und Oberflächen - QuoinMaterial: Quoin Brick
Sonstige - Kategorie: Allgemeines Modell; Familienname: BrickQuoin Stack_neu

# IfcBuildingElementProxyType, no part of this type: BrickQuoin Stack_neu:Corner Quion Stack
Material: Quoin Brick (34)
Abhängigkeiten - Vorgabe-Ansicht: 0 m
Bemaßungen - No of Quions 1st course: 7; No of Quoins 2nd course: 6; Height of Edge: 2.57 m; Length Long: 0.185 m; Length Short: 0.105 m; QuoinCourse: 0.073 m; Quoin Offset: 0.005 m
ID-Daten - Bauelement: F; Typname: Corner Quion Stack
Materialien und Oberflächen - QuoinMaterial: Quoin Brick
Sonstige - Kategorie: Allgemeines Modell; Familienname: BrickQuoin Stack_neu

# IfcBuildingElementProxyType, no part of this type: BrickQuoin Stack_neu:Corner Quion Stack
Material: Quoin Brick (34)
Abhängigkeiten - Vorgabe-Ansicht: 0 m
Bemaßungen - No of Quions 1st course: 7; No of Quoins 2nd course: 6; Height of Edge: 2.57 m; Length Long: 0.185 m; Length Short: 0.105 m; QuoinCourse: 0.073 m; Quoin Offset: 0.005 m
ID-Daten - Bauelement: F; Typname: Corner Quion Stack
Materialien und Oberflächen - QuoinMaterial: Quoin Brick
Sonstige - Kategorie: Allgemeines Modell; Familienname: BrickQuoin Stack_neu

# IfcBuildingElementProxyType, no part of this type: BrickQuoin Stack_neu:Corner Quion Stack
Material: Quoin Brick (50)
Abhängigkeiten - Vorgabe-Ansicht: 0 m
Bemaßungen - No of Quions 1st course: 7; No of Quoins 2nd course: 6; Height of Edge: 2.57 m; Length Long: 0.185 m; Length Short: 0.105 m; QuoinCourse: 0.073 m; Quoin Offset: 0.005 m
ID-Daten - Bauelement: F; Typname: Corner Quion Stack
Materialien und Oberflächen - QuoinMaterial: Quoin Brick
Sonstige - Kategorie: Allgemeines Modell; Familienname: BrickQuoin Stack_neu

# IfcBuildingElementProxyType, no part of this type: BrickQuoin Stack_neu:Corner Quion Stack 2881
Material: Quoin Brick (50)
Abhängigkeiten - Vorgabe-Ansicht: 0 m
Bemaßungen - No of Quions 1st course: 7; No of Quoins 2nd course: 6; Height of Edge: 2.881 m; Length Long: 0.185 m; Length Short: 0.105 m; QuoinCourse: 0.072 m; Quoin Offset: 0.005 m
ID-Daten - Bauelement: F; Typname: Corner Quion Stack 2881
Materialien und Oberflächen - QuoinMaterial: Quoin Brick
Sonstige - Kategorie: Allgemeines Modell; Familienname: BrickQuoin Stack_neu

# IfcBuildingElementProxyType, no part of this type: BrickQuoin Stack_neu:Corner Quion Stack 2881
Material: Quoin Brick (40)
Abhängigkeiten - Vorgabe-Ansicht: 0 m
Bemaßungen - No of Quions 1st course: 7; No of Quoins 2nd course: 6; Height of Edge: 2.881 m; Length Long: 0.185 m; Length Short: 0.105 m; QuoinCourse: 0.072 m; Quoin Offset: 0.005 m
ID-Daten - Bauelement: F; Typname: Corner Quion Stack 2881
Materialien und Oberflächen - QuoinMaterial: Quoin Brick
Sonstige - Kategorie: Allgemeines Modell; Familienname: BrickQuoin Stack_neu

# IfcBuildingElementProxyType, no part of this type: BrickQuoin Stack_neu:Corner Quion Stack 2881
Material: Quoin Brick (44)
Abhängigkeiten - Vorgabe-Ansicht: 0 m
Bemaßungen - No of Quions 1st course: 7; No of Quoins 2nd course: 6; Height of Edge: 2.881 m; Length Long: 0.185 m; Length Short: 0.105 m; QuoinCourse: 0.072 m; Quoin Offset: 0.005 m
ID-Daten - Bauelement: F; Typname: Corner Quion Stack 2881
Materialien und Oberflächen - QuoinMaterial: Quoin Brick
Sonstige - Kategorie: Allgemeines Modell; Familienname: BrickQuoin Stack_neu

# IfcBuildingElementProxyType, no part of this type: BrickQuoin Stack_neu:Corner Quion Stack 2881
Material: Quoin Brick (44)
Abhängigkeiten - Vorgabe-Ansicht: 0 m
Bemaßungen - No of Quions 1st course: 7; No of Quoins 2nd course: 6; Height of Edge: 2.881 m; Length Long: 0.185 m; Length Short: 0.105 m; QuoinCourse: 0.072 m; Quoin Offset: 0.005 m
ID-Daten - Bauelement: F; Typname: Corner Quion Stack 2881
Materialien und Oberflächen - QuoinMaterial: Quoin Brick
Sonstige - Kategorie: Allgemeines Modell; Familienname: BrickQuoin Stack_neu

# IfcBuildingElementProxyType, no part of this type: BrickQuoin Stack_neu:Corner Quion Stack 2881
Material: Quoin Brick (50)
Abhängigkeiten - Vorgabe-Ansicht: 0 m
Bemaßungen - No of Quions 1st course: 7; No of Quoins 2nd course: 6; Height of Edge: 2.881 m; Length Long: 0.185 m; Length Short: 0.105 m; QuoinCourse: 0.072 m; Quoin Offset: 0.005 m
ID-Daten - Bauelement: F; Typname: Corner Quion Stack 2881
Materialien und Oberflächen - QuoinMaterial: Quoin Brick
Sonstige - Kategorie: Allgemeines Modell; Familienname: BrickQuoin Stack_neu

# IfcBuildingElementProxyType, no part of this type: BrickQuoin Stack_neu:Corner Quion Stack 2881
Material: Quoin Brick (50)
Abhängigkeiten - Vorgabe-Ansicht: 0 m
Bemaßungen - No of Quions 1st course: 7; No of Quoins 2nd course: 6; Height of Edge: 2.881 m; Length Long: 0.185 m; Length Short: 0.105 m; QuoinCourse: 0.072 m; Quoin Offset: 0.005 m
ID-Daten - Bauelement: F; Typname: Corner Quion Stack 2881
Materialien und Oberflächen - QuoinMaterial: Quoin Brick
Sonstige - Kategorie: Allgemeines Modell; Familienname: BrickQuoin Stack_neu

# IfcBuildingElementProxyType, no part of this type: BrickQuoin Stack_neu:Corner Quion Stack 3384
Material: Quoin Brick (50)
Abhängigkeiten - Vorgabe-Ansicht: 0 m
Bemaßungen - Height of Edge: 3.384 m; Length Long: 0.185 m; Length Short: 0.105 m; No of Quions 1st course: 7; No of Quoins 2nd course: 6; QuoinCourse: 0.072 m; Quoin Offset: 0.005 m
ID-Daten - Bauelement: F; Typname: Corner Quion Stack 3384
Materialien und Oberflächen - QuoinMaterial: Quoin Brick
Sonstige - Kategorie: Allgemeines Modell; Familienname: BrickQuoin Stack_neu

# IfcBuildingElementProxyType, no part of this type: BrickQuoin Stack_neu:Corner Quion Stack 3384
Material: Quoin Brick (46)
Abhängigkeiten - Vorgabe-Ansicht: 0 m
Bemaßungen - Height of Edge: 3.384 m; Length Long: 0.185 m; Length Short: 0.105 m; No of Quions 1st course: 7; No of Quoins 2nd course: 6; QuoinCourse: 0.072 m; Quoin Offset: 0.005 m
ID-Daten - Bauelement: F; Typname: Corner Quion Stack 3384
Materialien und Oberflächen - QuoinMaterial: Quoin Brick
Sonstige - Kategorie: Allgemeines Modell; Familienname: BrickQuoin Stack_neu

# IfcBuildingElementProxyType, no part of this type: BrickQuoin Stack_neu:Corner Quion Stack 3384
Material: Quoin Brick (50)
Abhängigkeiten - Vorgabe-Ansicht: 0 m
Bemaßungen - Height of Edge: 3.384 m; Length Long: 0.185 m; Length Short: 0.105 m; No of Quions 1st course: 7; No of Quoins 2nd course: 6; QuoinCourse: 0.072 m; Quoin Offset: 0.005 m
ID-Daten - Bauelement: F; Typname: Corner Quion Stack 3384
Materialien und Oberflächen - QuoinMaterial: Quoin Brick
Sonstige - Kategorie: Allgemeines Modell; Familienname: BrickQuoin Stack_neu

# IfcBuildingElementProxyType, no part of this type: BrickQuoin Stack_neu:Corner Quion Stack ChancelEast
Material: Quoin Brick (50)
Abhängigkeiten - Vorgabe-Ansicht: 0 m
Bemaßungen - No of Quions 1st course: 7; No of Quoins 2nd course: 6; Height of Edge: 3.312 m; Length Long: 0.185 m; Length Short: 0.105 m; QuoinCourse: 0.072 m; Quoin Offset: 0.005 m
ID-Daten - Bauelement: F; Typname: Corner Quion Stack ChancelEast
Materialien und Oberflächen - QuoinMaterial: Quoin Brick
Sonstige - Kategorie: Allgemeines Modell; Familienname: BrickQuoin Stack_neu

# IfcBuildingElementProxyType, no part of this type: BrickQuoin Stack_neu:Corner Quion Stack ChancelEast
Material: Quoin Brick (50)
Abhängigkeiten - Vorgabe-Ansicht: 0 m
Bemaßungen - No of Quions 1st course: 7; No of Quoins 2nd course: 6; Height of Edge: 3.312 m; Length Long: 0.185 m; Length Short: 0.105 m; QuoinCourse: 0.072 m; Quoin Offset: 0.005 m
ID-Daten - Bauelement: F; Typname: Corner Quion Stack ChancelEast
Materialien und Oberflächen - QuoinMaterial: Quoin Brick
Sonstige - Kategorie: Allgemeines Modell; Familienname: BrickQuoin Stack_neu

# IfcBuildingElementProxyType, no part of this type: BrickQuoin Stack_neu:Corner Quion Stack Porch
Material: Quoin Brick (50)
Abhängigkeiten - Vorgabe-Ansicht: 0 m
Bemaßungen - No of Quions 1st course: 7; No of Quoins 2nd course: 6; Height of Edge: 2.86 m; Length Long: 0.185 m; Length Short: 0.105 m; QuoinCourse: 0.072 m; Quoin Offset: 0.005 m
ID-Daten - Bauelement: F; Typname: Corner Quion Stack Porch
Materialien und Oberflächen - QuoinMaterial: Quoin Brick
Sonstige - Kategorie: Allgemeines Modell; Familienname: BrickQuoin Stack_neu

# IfcBuildingElementProxyType, no part of this type: BrickQuoin Stack_neu:Corner Quion Stack Porch
Material: Quoin Brick (50)
Abhängigkeiten - Vorgabe-Ansicht: 0 m
Bemaßungen - No of Quions 1st course: 7; No of Quoins 2nd course: 6; Height of Edge: 2.86 m; Length Long: 0.185 m; Length Short: 0.105 m; QuoinCourse: 0.072 m; Quoin Offset: 0.005 m
ID-Daten - Bauelement: F; Typname: Corner Quion Stack Porch
Materialien und Oberflächen - QuoinMaterial: Quoin Brick
Sonstige - Kategorie: Allgemeines Modell; Familienname: BrickQuoin Stack_neu

# IfcBuildingElementProxyType, no part of this type: Complex pointed arch opening:Portal Opening North Facade
Material: Mauerwerk - Sandstein Rot (2)
Abhängigkeiten - Vorgabe-Ansicht: 0 m
Bemaßungen - offset: 0.1 m; VersatzInnen: 0.62 m; Wall offset: 0.2 m
ID-Daten - Typname: Portal Opening North Facade
Materialien und Oberflächen - Arch: Mauerwerk - Sandstein Rot; TympanenMaterial: Mauerwerk - Sandstein Rot
Sonstige - Kategorie: Allgemeines Modell; Familienname: Complex pointed arch opening

# IfcBuildingElementProxyType, no part of this type: Complex pointed arch opening_tower:Tower Portal
Material: Holz - Eiche (2), Mauerwerk - Sandstein Rot
Abhängigkeiten(Type) - Vorgabe-Ansicht: 0 m
Bemaßungen(Type) - ApexHeight: 4.8 m; FloorDepth: 0.1 m; InnerArchDepth: 0.663 m; InnerArchWidth: 2.24 m; InnerClearWidth: 1.85 m; InnerDepth: 0.13 m; InsideWidth: 1.85 m; MouldingDepth: 0.291 m; offset: 0.1 m; Springing height: 2.86 m; StoneworkDepth: 0.38 m; Wall offset: 0.2 m; Width: 2.51 m
ID-Daten(Type) - Typname: Tower Portal
Materialien und Oberflächen(Type) - Arch: Mauerwerk - Sandstein Rot; DoorFrameMaterial: Holz - Eiche; TympanenMaterial: Mauerwerk - Sandstein Rot
Sonstige(Type) - Kategorie: Allgemeines Modell; Familienname: Complex pointed arch opening_tower
Pset_ProvisionForVoid - Width: 2.51 m

# IfcBuildingElementProxyType, no part of this type: EastGableVerge:EastGableVerge 4162x3600
Material: Mauerwerk - Sandstein Rot, Mauerwerk - Sichtmauerwerk_72x265 header Stage2
Abhängigkeiten - Vorgabe-Ansicht: 0 m
Bemaßungen - GableWallHeight: 3.587 m; GableWidth: 4.18 m
ID-Daten - Typname: EastGableVerge 4162x3600
Materialien und Oberflächen - BrickMaterial: Mauerwerk - Sichtmauerwerk_72x265 header Stage2; Stone Material: Mauerwerk - Sandstein Rot
Sonstige - Kategorie: Allgemeines Modell; Familienname: EastGableVerge

# IfcBuildingElementProxyType, no part of this type: EastGableVerge:EastGableVerge 4180x3587
Material: Mauerwerk - Sandstein Rot, Mauerwerk - Sichtmauerwerk_72x265 header Stage2
Abhängigkeiten - Vorgabe-Ansicht: 0 m
Bemaßungen - GableWallHeight: 3.587 m; GableWidth: 4.18 m
ID-Daten - Typname: EastGableVerge 4180x3587
Materialien und Oberflächen - BrickMaterial: Mauerwerk - Sichtmauerwerk_72x265 header Stage2; Stone Material: Mauerwerk - Sandstein Rot
Sonstige - Kategorie: Allgemeines Modell; Familienname: EastGableVerge

# IfcBuildingElementProxyType, no part of this type: EastGableVerge:EastGableVerge 4190x3587 2
Material: Mauerwerk - Sandstein Rot, Mauerwerk - Sichtmauerwerk_72x265 header Stage2
Abhängigkeiten - Vorgabe-Ansicht: 0 m
Bemaßungen - GableWallHeight: 3.587 m; GableWidth: 4.19 m
ID-Daten - Typname: EastGableVerge 4190x3587 2
Materialien und Oberflächen - BrickMaterial: Mauerwerk - Sichtmauerwerk_72x265 header Stage2; Stone Material: Mauerwerk - Sandstein Rot
Sonstige - Kategorie: Allgemeines Modell; Familienname: EastGableVerge

# IfcBuildingElementProxyType, no part of this type: FiniaCross:ApexCross
Material: Mauerwerk - Sandstein Rot
Abhängigkeiten - Vorgabe-Ansicht: 0 m
Bemaßungen - BaseDepth: 0.3 m; BaseHeight: 2 m; BaseWidth: 1 m
ID-Daten - Typname: ApexCross
Materialien und Oberflächen - BaseMaterial: Mauerwerk - Sandstein Rot; CrossMaterial: Mauerwerk - Sandstein Rot
Sonstige - Kategorie: Allgemeines Modell; Familienname: FiniaCross

# IfcBuildingElementProxyType, no part of this type: FinialBase:FinialBase 505x505x2000
Material: Mauerwerk - Sandstein Rot
Abhängigkeiten - Vorgabe-Ansicht: 0 m
Bemaßungen - BaseDepth: 0.505 m; BaseHeight: 2 m; BaseWidth: 0.505 m
ID-Daten - Typname: FinialBase 505x505x2000
Materialien und Oberflächen - BaseMaterial: Mauerwerk - Sandstein Rot
Sonstige - Kategorie: Allgemeines Modell; Familienname: FinialBase

# IfcBuildingElementProxyType, no part of this type: FinialBase:FinialBase 505x505x2000
Material: Mauerwerk - Sandstein Rot
Abhängigkeiten - Vorgabe-Ansicht: 0 m
Bemaßungen - BaseDepth: 0.505 m; BaseHeight: 2 m; BaseWidth: 0.505 m
ID-Daten - Typname: FinialBase 505x505x2000
Materialien und Oberflächen - BaseMaterial: Mauerwerk - Sandstein Rot
Sonstige - Kategorie: Allgemeines Modell; Familienname: FinialBase

# IfcBuildingElementProxyType, no part of this type: FinialBase:FinialBase 600x600x4000
Material: Mauerwerk - Sandstein Rot
Abhängigkeiten - Vorgabe-Ansicht: 0 m
Bemaßungen - BaseDepth: 0.6 m; BaseHeight: 4 m; BaseWidth: 0.6 m
ID-Daten - Typname: FinialBase 600x600x4000
Materialien und Oberflächen - BaseMaterial: Mauerwerk - Sandstein Rot
Sonstige - Kategorie: Allgemeines Modell; Familienname: FinialBase

# IfcBuildingElementProxyType, no part of this type: Finial_East_Facade:Finial_East_Facade
Material: Mauerwerk - Sandstein Rot (2), Mauerwerk - Sichtmauerwerk_72x265 english bond Stage2
Abhängigkeiten - Vorgabe-Ansicht: 0 m
Bemaßungen - ApexSetback: 0.22 m; FinialDepth: 0.78 m; FinialWidth: 0.78 m
ID-Daten - Typname: Finial_East_Facade
Materialien und Oberflächen - BrickMaterial: Mauerwerk - Sichtmauerwerk_72x265 english bond Stage2; StoneMaterial: Mauerwerk - Sandstein Rot
Sonstige - Kategorie: Allgemeines Modell; Familienname: Finial_East_Facade

# IfcBuildingElementProxyType, no part of this type: Font:Font
Material: Holz - Eiche, Naturstein - Marble (2)
Abhängigkeiten - Vorgabe-Ansicht: 0 m
Bemaßungen - BaseHeight: 0.563889 m; BaseWidth: 0.6 m; CapHeight: 0.8 m; FontHeight: 0.64 m; FontOverhang: 0.12 m; FontWidth: 0.84 m
ID-Daten - Typname: Font
Materialien und Oberflächen - BaseMaterial: Naturstein - Marble; CapMaterial: Holz - Eiche
Sonstige - Kategorie: Allgemeines Modell; Familienname: Font

# IfcBuildingElementProxyType, no part of this type: Heizofen:Heizofen
Material: <Unnamed> (3)
Abhängigkeiten - Vorgabe-Ansicht: 0 m
Bemaßungen - BaseHeight: 2 m; BodyHeight: 2 m; OverallWidth: 1 m; TopHeight: 2 m
ID-Daten - Typname: Heizofen
Materialien und Oberflächen - Material: Naturstein - Marble
Sonstige - Kategorie: Allgemeines Modell; Familienname: Heizofen

# IfcBuildingElementProxyType, no part of this type: HoleVertical:Excavation 1x1x2
Material: <Unnamed>
Abhängigkeiten - Vorgabe-Ansicht: 1.2192 m
ID-Daten - Typname: Excavation 1x1x2
Sonstige - Kategorie: Allgemeines Modell; Familienname: HoleVertical

# IfcBuildingElementProxyType, no part of this type: InternalOpening:1864
Material: Naturstein - Marble(1), Mauerwerk - Kalkputz-white
Abhängigkeiten - Vorgabe-Ansicht: 0 m
Bemaßungen - SillThickness: 0.04 m; Springing: 3.32 m
ID-Daten - Typname: 1864
Sonstige - Kategorie: Allgemeines Modell; Familienname: InternalOpening

# IfcBuildingElementProxyType, no part of this type: InternalOpening:1966
Material: Naturstein - Granit grau, Mauerwerk - Sandstein Rot bemalt
Abhängigkeiten(Type) - Vorgabe-Ansicht: 0 m
Bemaßungen(Type) - SillThickness: 0.04 m; Springing: 3.32 m
ID-Daten(Type) - Typname: 1966
Sonstige(Type) - Kategorie: Allgemeines Modell; Familienname: InternalOpening

# IfcBuildingElementProxyType, no part of this type: OfficePierCap:OfficePierCap 365
Material: Mauerwerk - Sichtmauerwerk_72x265 english bond Stage2
Abhängigkeiten - Vorgabe-Ansicht: 0 m
Bemaßungen - pierWidth: 0.365 m
ID-Daten - Typname: OfficePierCap 365
Materialien und Oberflächen - PierMaterial: Mauerwerk - Sichtmauerwerk_72x265 english bond Stage2
Sonstige - Kategorie: Allgemeines Modell; Familienname: OfficePierCap

# IfcBuildingElementProxyType, no part of this type: OfficePierCap:OfficePierCap 515
Material: Mauerwerk - Sichtmauerwerk_72x265 english bond Stage2
Abhängigkeiten - Vorgabe-Ansicht: 0 m
Bemaßungen - pierWidth: 0.515 m
ID-Daten - Typname: OfficePierCap 515
Materialien und Oberflächen - PierMaterial: Mauerwerk - Sichtmauerwerk_72x265 english bond Stage2
Sonstige - Kategorie: Allgemeines Modell; Familienname: OfficePierCap

# IfcBuildingElementProxyType, no part of this type: OfficePierCorbel:OfficePierCorbel 365
Material: Mauerwerk - Sichtmauerwerk_72x265 english bond Stage2
Abhängigkeiten - Vorgabe-Ansicht: 0 m
Bemaßungen - pierWidth: 0.365 m
ID-Daten - Typname: OfficePierCorbel 365
Materialien und Oberflächen - PierMaterial: Mauerwerk - Sichtmauerwerk_72x265 english bond Stage2
Sonstige - Kategorie: Allgemeines Modell; Familienname: OfficePierCorbel

# IfcBuildingElementProxyType, no part of this type: OfficePierCorbel:OfficePierCorbel 515
Material: Mauerwerk - Sichtmauerwerk_72x265 english bond Stage2
Abhängigkeiten - Vorgabe-Ansicht: 0 m
Bemaßungen - pierWidth: 0.515 m
ID-Daten - Typname: OfficePierCorbel 515
Materialien und Oberflächen - PierMaterial: Mauerwerk - Sichtmauerwerk_72x265 english bond Stage2
Sonstige - Kategorie: Allgemeines Modell; Familienname: OfficePierCorbel

# IfcBuildingElementProxyType, no part of this type: PierCorbel:PierCorbel 780
Material: Mauerwerk - Sandstein Rot
Abhängigkeiten - Vorgabe-Ansicht: 0 m
Bemaßungen - CorbelBreite: 0.78 m
ID-Daten - Typname: PierCorbel 780
Materialien und Oberflächen - CorbelMaterial: Mauerwerk - Sandstein Rot
Sonstige - Kategorie: Allgemeines Modell; Familienname: PierCorbel

# IfcBuildingElementProxyType, no part of this type: PilasterCorbelStage2:PilasterCorbelStage2
Material: <Unnamed>, Quoin Brick (10)
Abhängigkeiten - Vorgabe-Ansicht: 0 m
Bemaßungen - BreitePilaster: 0.52 m; HoeheUKCorbel: 3.534 m; TiefePilaster: 0.185 m
ID-Daten - Typname: PilasterCorbelStage2
Materialien und Oberflächen - CorbelMaterial: Quoin Brick
Sonstige - Kategorie: Allgemeines Modell; Familienname: PilasterCorbelStage2

# IfcBuildingElementProxyType, no part of this type: PilasterCorbelStage2:PilasterCorbelStage2
Material: <Unnamed>, Quoin Brick (10)
Abhängigkeiten - Vorgabe-Ansicht: 0 m
Bemaßungen - BreitePilaster: 0.52 m; HoeheUKCorbel: 3.534 m; TiefePilaster: 0.185 m
ID-Daten - Typname: PilasterCorbelStage2
Materialien und Oberflächen - CorbelMaterial: Quoin Brick
Sonstige - Kategorie: Allgemeines Modell; Familienname: PilasterCorbelStage2

# IfcBuildingElementProxyType, no part of this type: PointedArchOpening:ChancelSideArch 940x3000
Material: <Unnamed>
Abhängigkeiten(Type) - Vorgabe-Ansicht: 0 m
Bemaßungen(Type) - ArchHeight: 0.75 m; ArchWidth: 0.94 m; LintelSetback: 0 m; SpringingHeight: 2.05 m
ID-Daten(Type) - Typname: ChancelSideArch 940x3000
Sonstige(Type) - Kategorie: Allgemeines Modell; Familienname: PointedArchOpening

# IfcBuildingElementProxyType, no part of this type: PointedArchOpening:ChancelSideArch East
Material: <Unnamed>
Abhängigkeiten(Type) - Vorgabe-Ansicht: 0 m
Bemaßungen(Type) - ArchHeight: 1.5 m; ArchWidth: 1.455 m; LintelSetback: 0.0322478 m; SpringingHeight: 3.762 m
ID-Daten(Type) - Typname: ChancelSideArch East
Sonstige(Type) - Kategorie: Allgemeines Modell; Familienname: PointedArchOpening

# IfcBuildingElementProxyType, no part of this type: Profilierte Wand:Office eaves corbel
Abhängigkeiten - Entlang eingefügter Elemente schneiden: no; Schneidet Wand: yes; Standardrücksprung: 0 m
ID-Daten - Typname: Office eaves corbel
Konstruktion - Profil: Familie3 : eaves corbel
Materialien und Oberflächen - Material: Mauerwerk - Sichtmauerwerk_72x265 header Stage2
Sonstige - Kategorie: Wände: Profilierte Wände; Familienname: Profilierte Wand

# IfcBuildingElementProxyType, no part of this type: Profilierte Wand:Office eaves corbel
Abhängigkeiten - Entlang eingefügter Elemente schneiden: no; Schneidet Wand: yes; Standardrücksprung: 0 m
ID-Daten - Typname: Office eaves corbel
Konstruktion - Profil: Familie3 : eaves corbel
Materialien und Oberflächen - Material: Mauerwerk - Sichtmauerwerk_72x265 header Stage2
Sonstige - Kategorie: Wände: Profilierte Wände; Familienname: Profilierte Wand

# IfcBuildingElementProxyType, no part of this type: Profilierte Wand:String course moulding Stage1
Abhängigkeiten - Schneidet Wand: yes; Standardrücksprung: 0 m; Entlang eingefügter Elemente schneiden: yes
ID-Daten - Typname: String course moulding Stage1
Konstruktion - Profil: Mouldings : Moulding1
Materialien und Oberflächen - Material: Mauerwerk - Sandstein Rot
Sonstige - Kategorie: Wände: Profilierte Wände; Familienname: Profilierte Wand

# IfcBuildingElementProxyType, no part of this type: Profilierte Wand:String course moulding Stage1
Abhängigkeiten - Schneidet Wand: yes; Standardrücksprung: 0 m; Entlang eingefügter Elemente schneiden: yes
ID-Daten - Typname: String course moulding Stage1
Konstruktion - Profil: Mouldings : Moulding1
Materialien und Oberflächen - Material: Mauerwerk - Sandstein Rot
Sonstige - Kategorie: Wände: Profilierte Wände; Familienname: Profilierte Wand

# IfcBuildingElementProxyType, no part of this type: Profilierte Wand:String course moulding Stage1
Abhängigkeiten - Schneidet Wand: yes; Standardrücksprung: 0 m; Entlang eingefügter Elemente schneiden: yes
ID-Daten - Typname: String course moulding Stage1
Konstruktion - Profil: Mouldings : Moulding1
Materialien und Oberflächen - Material: Mauerwerk - Sandstein Rot
Sonstige - Kategorie: Wände: Profilierte Wände; Familienname: Profilierte Wand

# IfcBuildingElementProxyType, no part of this type: Profilierte Wand:String course moulding Stage1
Abhängigkeiten - Schneidet Wand: yes; Standardrücksprung: 0 m; Entlang eingefügter Elemente schneiden: yes
ID-Daten - Typname: String course moulding Stage1
Konstruktion - Profil: Mouldings : Moulding1
Materialien und Oberflächen - Material: Mauerwerk - Sandstein Rot
Sonstige - Kategorie: Wände: Profilierte Wände; Familienname: Profilierte Wand

# IfcBuildingElementProxyType, no part of this type: Profilierte Wand:String course moulding Stage1
Abhängigkeiten - Schneidet Wand: yes; Standardrücksprung: 0 m; Entlang eingefügter Elemente schneiden: yes
ID-Daten - Typname: String course moulding Stage1
Konstruktion - Profil: Mouldings : Moulding1
Materialien und Oberflächen - Material: Mauerwerk - Sandstein Rot
Sonstige - Kategorie: Wände: Profilierte Wände; Familienname: Profilierte Wand

# IfcBuildingElementProxyType, no part of this type: Profilierte Wand:String course moulding Stage1
Abhängigkeiten - Schneidet Wand: yes; Standardrücksprung: 0 m; Entlang eingefügter Elemente schneiden: yes
ID-Daten - Typname: String course moulding Stage1
Konstruktion - Profil: Mouldings : Moulding1
Materialien und Oberflächen - Material: Mauerwerk - Sandstein Rot
Sonstige - Kategorie: Wände: Profilierte Wände; Familienname: Profilierte Wand

# IfcBuildingElementProxyType, no part of this type: Profilierte Wand:String course moulding Stage1
Abhängigkeiten - Schneidet Wand: yes; Standardrücksprung: 0 m; Entlang eingefügter Elemente schneiden: yes
ID-Daten - Typname: String course moulding Stage1
Konstruktion - Profil: Mouldings : Moulding1
Materialien und Oberflächen - Material: Mauerwerk - Sandstein Rot
Sonstige - Kategorie: Wände: Profilierte Wände; Familienname: Profilierte Wand

# IfcBuildingElementProxyType, no part of this type: Profilierte Wand:String course moulding Stage1
Abhängigkeiten - Schneidet Wand: yes; Standardrücksprung: 0 m; Entlang eingefügter Elemente schneiden: yes
ID-Daten - Typname: String course moulding Stage1
Konstruktion - Profil: Mouldings : Moulding1
Materialien und Oberflächen - Material: Mauerwerk - Sandstein Rot
Sonstige - Kategorie: Wände: Profilierte Wände; Familienname: Profilierte Wand

# IfcBuildingElementProxyType, no part of this type: Profilierte Wand:String course moulding Stage1
Abhängigkeiten - Schneidet Wand: yes; Standardrücksprung: 0 m; Entlang eingefügter Elemente schneiden: yes
ID-Daten - Typname: String course moulding Stage1
Konstruktion - Profil: Mouldings : Moulding1
Materialien und Oberflächen - Material: Mauerwerk - Sandstein Rot
Sonstige - Kategorie: Wände: Profilierte Wände; Familienname: Profilierte Wand

# IfcBuildingElementProxyType, no part of this type: Profilierte Wand:String course moulding Stage1
Abhängigkeiten - Schneidet Wand: yes; Standardrücksprung: 0 m; Entlang eingefügter Elemente schneiden: yes
ID-Daten - Typname: String course moulding Stage1
Konstruktion - Profil: Mouldings : Moulding1
Materialien und Oberflächen - Material: Mauerwerk - Sandstein Rot
Sonstige - Kategorie: Wände: Profilierte Wände; Familienname: Profilierte Wand

# IfcBuildingElementProxyType, no part of this type: Profilierte Wand:String course moulding Stage1
Abhängigkeiten - Schneidet Wand: yes; Standardrücksprung: 0 m; Entlang eingefügter Elemente schneiden: yes
ID-Daten - Typname: String course moulding Stage1
Konstruktion - Profil: Mouldings : Moulding1
Materialien und Oberflächen - Material: Mauerwerk - Sandstein Rot
Sonstige - Kategorie: Wände: Profilierte Wände; Familienname: Profilierte Wand

# IfcBuildingElementProxyType, no part of this type: Profilierte Wand:String course moulding Stage1
Abhängigkeiten - Schneidet Wand: yes; Standardrücksprung: 0 m; Entlang eingefügter Elemente schneiden: yes
ID-Daten - Typname: String course moulding Stage1
Konstruktion - Profil: Mouldings : Moulding1
Materialien und Oberflächen - Material: Mauerwerk - Sandstein Rot
Sonstige - Kategorie: Wände: Profilierte Wände; Familienname: Profilierte Wand

# IfcBuildingElementProxyType, no part of this type: Profilierte Wand:String course moulding Stage1
Abhängigkeiten - Schneidet Wand: yes; Standardrücksprung: 0 m; Entlang eingefügter Elemente schneiden: yes
ID-Daten - Typname: String course moulding Stage1
Konstruktion - Profil: Mouldings : Moulding1
Materialien und Oberflächen - Material: Mauerwerk - Sandstein Rot
Sonstige - Kategorie: Wände: Profilierte Wände; Familienname: Profilierte Wand

# IfcBuildingElementProxyType, no part of this type: Profilierte Wand:String course moulding Stage1
Abhängigkeiten - Schneidet Wand: yes; Standardrücksprung: 0 m; Entlang eingefügter Elemente schneiden: yes
ID-Daten - Typname: String course moulding Stage1
Konstruktion - Profil: Mouldings : Moulding1
Materialien und Oberflächen - Material: Mauerwerk - Sandstein Rot
Sonstige - Kategorie: Wände: Profilierte Wände; Familienname: Profilierte Wand

# IfcBuildingElementProxyType, no part of this type: Profilierte Wand:String course moulding Stage1
Abhängigkeiten - Schneidet Wand: yes; Standardrücksprung: 0 m; Entlang eingefügter Elemente schneiden: yes
ID-Daten - Typname: String course moulding Stage1
Konstruktion - Profil: Mouldings : Moulding1
Materialien und Oberflächen - Material: Mauerwerk - Sandstein Rot
Sonstige - Kategorie: Wände: Profilierte Wände; Familienname: Profilierte Wand

# IfcBuildingElementProxyType, no part of this type: Profilierte Wand:String course moulding Stage1
Abhängigkeiten - Schneidet Wand: yes; Standardrücksprung: 0 m; Entlang eingefügter Elemente schneiden: yes
ID-Daten - Typname: String course moulding Stage1
Konstruktion - Profil: Mouldings : Moulding1
Materialien und Oberflächen - Material: Mauerwerk - Sandstein Rot
Sonstige - Kategorie: Wände: Profilierte Wände; Familienname: Profilierte Wand

# IfcBuildingElementProxyType, no part of this type: Profilierte Wand:String course moulding Stage1
Abhängigkeiten - Schneidet Wand: yes; Standardrücksprung: 0 m; Entlang eingefügter Elemente schneiden: yes
ID-Daten - Typname: String course moulding Stage1
Konstruktion - Profil: Mouldings : Moulding1
Materialien und Oberflächen - Material: Mauerwerk - Sandstein Rot
Sonstige - Kategorie: Wände: Profilierte Wände; Familienname: Profilierte Wand

# IfcBuildingElementProxyType, no part of this type: Profilierte Wand:String course moulding Stage1
Abhängigkeiten - Schneidet Wand: yes; Standardrücksprung: 0 m; Entlang eingefügter Elemente schneiden: yes
ID-Daten - Typname: String course moulding Stage1
Konstruktion - Profil: Mouldings : Moulding1
Materialien und Oberflächen - Material: Mauerwerk - Sandstein Rot
Sonstige - Kategorie: Wände: Profilierte Wände; Familienname: Profilierte Wand

# IfcBuildingElementProxyType, no part of this type: Profilierte Wand:String course moulding Stage1
Abhängigkeiten - Schneidet Wand: yes; Standardrücksprung: 0 m; Entlang eingefügter Elemente schneiden: yes
ID-Daten - Typname: String course moulding Stage1
Konstruktion - Profil: Mouldings : Moulding1
Materialien und Oberflächen - Material: Mauerwerk - Sandstein Rot
Sonstige - Kategorie: Wände: Profilierte Wände; Familienname: Profilierte Wand

# IfcBuildingElementProxyType, no part of this type: Profilierte Wand:String course moulding Stage1
Abhängigkeiten - Schneidet Wand: yes; Standardrücksprung: 0 m; Entlang eingefügter Elemente schneiden: yes
ID-Daten - Typname: String course moulding Stage1
Konstruktion - Profil: Mouldings : Moulding1
Materialien und Oberflächen - Material: Mauerwerk - Sandstein Rot
Sonstige - Kategorie: Wände: Profilierte Wände; Familienname: Profilierte Wand

# IfcBuildingElementProxyType, no part of this type: Profilierte Wand:String course moulding Stage1
Abhängigkeiten - Schneidet Wand: yes; Standardrücksprung: 0 m; Entlang eingefügter Elemente schneiden: yes
ID-Daten - Typname: String course moulding Stage1
Konstruktion - Profil: Mouldings : Moulding1
Materialien und Oberflächen - Material: Mauerwerk - Sandstein Rot
Sonstige - Kategorie: Wände: Profilierte Wände; Familienname: Profilierte Wand

# IfcBuildingElementProxyType, no part of this type: Profilierte Wand:String course moulding Stage1
Abhängigkeiten - Schneidet Wand: yes; Standardrücksprung: 0 m; Entlang eingefügter Elemente schneiden: yes
ID-Daten - Typname: String course moulding Stage1
Konstruktion - Profil: Mouldings : Moulding1
Materialien und Oberflächen - Material: Mauerwerk - Sandstein Rot
Sonstige - Kategorie: Wände: Profilierte Wände; Familienname: Profilierte Wand

# IfcBuildingElementProxyType, no part of this type: Profilierte Wand:String course moulding Stage1
Abhängigkeiten - Schneidet Wand: yes; Standardrücksprung: 0 m; Entlang eingefügter Elemente schneiden: yes
ID-Daten - Typname: String course moulding Stage1
Konstruktion - Profil: Mouldings : Moulding1
Materialien und Oberflächen - Material: Mauerwerk - Sandstein Rot
Sonstige - Kategorie: Wände: Profilierte Wände; Familienname: Profilierte Wand

# IfcBuildingElementProxyType, no part of this type: Profilierte Wand:String course moulding Stage1
Abhängigkeiten - Schneidet Wand: yes; Standardrücksprung: 0 m; Entlang eingefügter Elemente schneiden: yes
ID-Daten - Typname: String course moulding Stage1
Konstruktion - Profil: Mouldings : Moulding1
Materialien und Oberflächen - Material: Mauerwerk - Sandstein Rot
Sonstige - Kategorie: Wände: Profilierte Wände; Familienname: Profilierte Wand

# IfcBuildingElementProxyType, no part of this type: Profilierte Wand:moulding1-Dado
Abhängigkeiten - Entlang eingefügter Elemente schneiden: no; Schneidet Wand: yes; Standardrücksprung: 0 m
ID-Daten - Typname: moulding1-Dado
Konstruktion - Profil: Mouldings : Moulding1
Materialien und Oberflächen - Material: Mauerwerk - Sandstein Rot
Sonstige - Kategorie: Wände: Profilierte Wände; Familienname: Profilierte Wand

# IfcBuildingElementProxyType, no part of this type: Profilierte Wand:moulding1-Dado
Abhängigkeiten - Entlang eingefügter Elemente schneiden: no; Schneidet Wand: yes; Standardrücksprung: 0 m
ID-Daten - Typname: moulding1-Dado
Konstruktion - Profil: Mouldings : Moulding1
Materialien und Oberflächen - Material: Mauerwerk - Sandstein Rot
Sonstige - Kategorie: Wände: Profilierte Wände; Familienname: Profilierte Wand

# IfcBuildingElementProxyType, no part of this type: Profilierte Wand:moulding1-Dado
Abhängigkeiten - Entlang eingefügter Elemente schneiden: no; Schneidet Wand: yes; Standardrücksprung: 0 m
ID-Daten - Typname: moulding1-Dado
Konstruktion - Profil: Mouldings : Moulding1
Materialien und Oberflächen - Material: Mauerwerk - Sandstein Rot
Sonstige - Kategorie: Wände: Profilierte Wände; Familienname: Profilierte Wand

# IfcBuildingElementProxyType, no part of this type: Profilierte Wand:moulding1-Dado
Abhängigkeiten - Entlang eingefügter Elemente schneiden: no; Schneidet Wand: yes; Standardrücksprung: 0 m
ID-Daten - Typname: moulding1-Dado
Konstruktion - Profil: Mouldings : Moulding1
Materialien und Oberflächen - Material: Mauerwerk - Sandstein Rot
Sonstige - Kategorie: Wände: Profilierte Wände; Familienname: Profilierte Wand

# IfcBuildingElementProxyType, no part of this type: Profilierte Wand:moulding1-Dado
Abhängigkeiten - Entlang eingefügter Elemente schneiden: no; Schneidet Wand: yes; Standardrücksprung: 0 m
ID-Daten - Typname: moulding1-Dado
Konstruktion - Profil: Mouldings : Moulding1
Materialien und Oberflächen - Material: Mauerwerk - Sandstein Rot
Sonstige - Kategorie: Wände: Profilierte Wände; Familienname: Profilierte Wand

# IfcBuildingElementProxyType, no part of this type: Profilierte Wand:moulding1-Dado
Abhängigkeiten - Entlang eingefügter Elemente schneiden: no; Schneidet Wand: yes; Standardrücksprung: 0 m
ID-Daten - Typname: moulding1-Dado
Konstruktion - Profil: Mouldings : Moulding1
Materialien und Oberflächen - Material: Mauerwerk - Sandstein Rot
Sonstige - Kategorie: Wände: Profilierte Wände; Familienname: Profilierte Wand

# IfcBuildingElementProxyType, no part of this type: Profilierte Wand:moulding1-Dado
Abhängigkeiten - Entlang eingefügter Elemente schneiden: no; Schneidet Wand: yes; Standardrücksprung: 0 m
ID-Daten - Typname: moulding1-Dado
Konstruktion - Profil: Mouldings : Moulding1
Materialien und Oberflächen - Material: Mauerwerk - Sandstein Rot
Sonstige - Kategorie: Wände: Profilierte Wände; Familienname: Profilierte Wand

# IfcBuildingElementProxyType, no part of this type: Profilierte Wand:moulding1-Dado
Abhängigkeiten - Entlang eingefügter Elemente schneiden: no; Schneidet Wand: yes; Standardrücksprung: 0 m
ID-Daten - Typname: moulding1-Dado
Konstruktion - Profil: Mouldings : Moulding1
Materialien und Oberflächen - Material: Mauerwerk - Sandstein Rot
Sonstige - Kategorie: Wände: Profilierte Wände; Familienname: Profilierte Wand

# IfcBuildingElementProxyType, no part of this type: Profilierte Wand:moulding1-Dado
Abhängigkeiten - Entlang eingefügter Elemente schneiden: no; Schneidet Wand: yes; Standardrücksprung: 0 m
ID-Daten - Typname: moulding1-Dado
Konstruktion - Profil: Mouldings : Moulding1
Materialien und Oberflächen - Material: Mauerwerk - Sandstein Rot
Sonstige - Kategorie: Wände: Profilierte Wände; Familienname: Profilierte Wand

# IfcBuildingElementProxyType, no part of this type: Profilierte Wand:moulding1-Dado
Abhängigkeiten - Entlang eingefügter Elemente schneiden: no; Schneidet Wand: yes; Standardrücksprung: 0 m
ID-Daten - Typname: moulding1-Dado
Konstruktion - Profil: Mouldings : Moulding1
Materialien und Oberflächen - Material: Mauerwerk - Sandstein Rot
Sonstige - Kategorie: Wände: Profilierte Wände; Familienname: Profilierte Wand

# IfcBuildingElementProxyType, no part of this type: Profilierte Wand:moulding1-Dado
Abhängigkeiten - Entlang eingefügter Elemente schneiden: no; Schneidet Wand: yes; Standardrücksprung: 0 m
ID-Daten - Typname: moulding1-Dado
Konstruktion - Profil: Mouldings : Moulding1
Materialien und Oberflächen - Material: Mauerwerk - Sandstein Rot
Sonstige - Kategorie: Wände: Profilierte Wände; Familienname: Profilierte Wand

# IfcBuildingElementProxyType, no part of this type: Profilierte Wand:moulding1-Dado
Abhängigkeiten - Entlang eingefügter Elemente schneiden: no; Schneidet Wand: yes; Standardrücksprung: 0 m
ID-Daten - Typname: moulding1-Dado
Konstruktion - Profil: Mouldings : Moulding1
Materialien und Oberflächen - Material: Mauerwerk - Sandstein Rot
Sonstige - Kategorie: Wände: Profilierte Wände; Familienname: Profilierte Wand

# IfcBuildingElementProxyType, no part of this type: Profilierte Wand:moulding1-Dado
Abhängigkeiten - Entlang eingefügter Elemente schneiden: no; Schneidet Wand: yes; Standardrücksprung: 0 m
ID-Daten - Typname: moulding1-Dado
Konstruktion - Profil: Mouldings : Moulding1
Materialien und Oberflächen - Material: Mauerwerk - Sandstein Rot
Sonstige - Kategorie: Wände: Profilierte Wände; Familienname: Profilierte Wand

# IfcBuildingElementProxyType, no part of this type: Profilierte Wand:moulding1-Dado
Abhängigkeiten - Entlang eingefügter Elemente schneiden: no; Schneidet Wand: yes; Standardrücksprung: 0 m
ID-Daten - Typname: moulding1-Dado
Konstruktion - Profil: Mouldings : Moulding1
Materialien und Oberflächen - Material: Mauerwerk - Sandstein Rot
Sonstige - Kategorie: Wände: Profilierte Wände; Familienname: Profilierte Wand

# IfcBuildingElementProxyType, no part of this type: Profilierte Wand:moulding1-Dado
Abhängigkeiten - Entlang eingefügter Elemente schneiden: no; Schneidet Wand: yes; Standardrücksprung: 0 m
ID-Daten - Typname: moulding1-Dado
Konstruktion - Profil: Mouldings : Moulding1
Materialien und Oberflächen - Material: Mauerwerk - Sandstein Rot
Sonstige - Kategorie: Wände: Profilierte Wände; Familienname: Profilierte Wand

# IfcBuildingElementProxyType, no part of this type: Profilierte Wand:moulding1-Dado
Abhängigkeiten - Entlang eingefügter Elemente schneiden: no; Schneidet Wand: yes; Standardrücksprung: 0 m
ID-Daten - Typname: moulding1-Dado
Konstruktion - Profil: Mouldings : Moulding1
Materialien und Oberflächen - Material: Mauerwerk - Sandstein Rot
Sonstige - Kategorie: Wände: Profilierte Wände; Familienname: Profilierte Wand

# IfcBuildingElementProxyType, no part of this type: Profilierte Wand:moulding1-Dado
Abhängigkeiten - Entlang eingefügter Elemente schneiden: no; Schneidet Wand: yes; Standardrücksprung: 0 m
ID-Daten - Typname: moulding1-Dado
Konstruktion - Profil: Mouldings : Moulding1
Materialien und Oberflächen - Material: Mauerwerk - Sandstein Rot
Sonstige - Kategorie: Wände: Profilierte Wände; Familienname: Profilierte Wand

# IfcBuildingElementProxyType, no part of this type: Profilierte Wand:moulding1-Dado
Abhängigkeiten - Entlang eingefügter Elemente schneiden: no; Schneidet Wand: yes; Standardrücksprung: 0 m
ID-Daten - Typname: moulding1-Dado
Konstruktion - Profil: Mouldings : Moulding1
Materialien und Oberflächen - Material: Mauerwerk - Sandstein Rot
Sonstige - Kategorie: Wände: Profilierte Wände; Familienname: Profilierte Wand

# IfcBuildingElementProxyType, no part of this type: Profilierte Wand:moulding1-Dado
Abhängigkeiten - Entlang eingefügter Elemente schneiden: no; Schneidet Wand: yes; Standardrücksprung: 0 m
ID-Daten - Typname: moulding1-Dado
Konstruktion - Profil: Mouldings : Moulding1
Materialien und Oberflächen - Material: Mauerwerk - Sandstein Rot
Sonstige - Kategorie: Wände: Profilierte Wände; Familienname: Profilierte Wand

# IfcBuildingElementProxyType, no part of this type: Profilierte Wand:moulding1-Dado
Abhängigkeiten - Entlang eingefügter Elemente schneiden: no; Schneidet Wand: yes; Standardrücksprung: 0 m
ID-Daten - Typname: moulding1-Dado
Konstruktion - Profil: Mouldings : Moulding1
Materialien und Oberflächen - Material: Mauerwerk - Sandstein Rot
Sonstige - Kategorie: Wände: Profilierte Wände; Familienname: Profilierte Wand

# IfcBuildingElementProxyType, no part of this type: Profilierte Wand:moulding1-Dado
Abhängigkeiten - Entlang eingefügter Elemente schneiden: no; Schneidet Wand: yes; Standardrücksprung: 0 m
ID-Daten - Typname: moulding1-Dado
Konstruktion - Profil: Mouldings : Moulding1
Materialien und Oberflächen - Material: Mauerwerk - Sandstein Rot
Sonstige - Kategorie: Wände: Profilierte Wände; Familienname: Profilierte Wand

# IfcBuildingElementProxyType, no part of this type: Profilierte Wand:moulding1-Dado 2
Abhängigkeiten - Entlang eingefügter Elemente schneiden: no; Schneidet Wand: yes; Standardrücksprung: 0 m
ID-Daten - Typname: moulding1-Dado 2
Konstruktion - Profil: Testmouldingdeep : Testmouldingdeep
Materialien und Oberflächen - Material: Mauerwerk - Sandstein Rot
Sonstige - Kategorie: Wände: Profilierte Wände; Familienname: Profilierte Wand

# IfcBuildingElementProxyType, no part of this type: Profilierte Wand:moulding1-Dado 2
Abhängigkeiten - Entlang eingefügter Elemente schneiden: no; Schneidet Wand: yes; Standardrücksprung: 0 m
ID-Daten - Typname: moulding1-Dado 2
Konstruktion - Profil: Testmouldingdeep : Testmouldingdeep
Materialien und Oberflächen - Material: Mauerwerk - Sandstein Rot
Sonstige - Kategorie: Wände: Profilierte Wände; Familienname: Profilierte Wand

# IfcBuildingElementProxyType, no part of this type: Profilierte Wand:moulding1-Dado 2
Abhängigkeiten - Entlang eingefügter Elemente schneiden: no; Schneidet Wand: yes; Standardrücksprung: 0 m
ID-Daten - Typname: moulding1-Dado 2
Konstruktion - Profil: Testmouldingdeep : Testmouldingdeep
Materialien und Oberflächen - Material: Mauerwerk - Sandstein Rot
Sonstige - Kategorie: Wände: Profilierte Wände; Familienname: Profilierte Wand

# IfcBuildingElementProxyType, no part of this type: Profilierte Wand:moulding1-Dado 2
Abhängigkeiten - Entlang eingefügter Elemente schneiden: no; Schneidet Wand: yes; Standardrücksprung: 0 m
ID-Daten - Typname: moulding1-Dado 2
Konstruktion - Profil: Testmouldingdeep : Testmouldingdeep
Materialien und Oberflächen - Material: Mauerwerk - Sandstein Rot
Sonstige - Kategorie: Wände: Profilierte Wände; Familienname: Profilierte Wand

# IfcBuildingElementProxyType, no part of this type: Profilierte Wand:moulding1-Dado 2
Abhängigkeiten - Entlang eingefügter Elemente schneiden: no; Schneidet Wand: yes; Standardrücksprung: 0 m
ID-Daten - Typname: moulding1-Dado 2
Konstruktion - Profil: Testmouldingdeep : Testmouldingdeep
Materialien und Oberflächen - Material: Mauerwerk - Sandstein Rot
Sonstige - Kategorie: Wände: Profilierte Wände; Familienname: Profilierte Wand

# IfcBuildingElementProxyType, no part of this type: Profilierte Wand:moulding1-Dado 2
Abhängigkeiten - Entlang eingefügter Elemente schneiden: no; Schneidet Wand: yes; Standardrücksprung: 0 m
ID-Daten - Typname: moulding1-Dado 2
Konstruktion - Profil: Testmouldingdeep : Testmouldingdeep
Materialien und Oberflächen - Material: Mauerwerk - Sandstein Rot
Sonstige - Kategorie: Wände: Profilierte Wände; Familienname: Profilierte Wand

# IfcBuildingElementProxyType, no part of this type: Profilierte Wand:moulding1-Dado 2
Abhängigkeiten - Entlang eingefügter Elemente schneiden: no; Schneidet Wand: yes; Standardrücksprung: 0 m
ID-Daten - Typname: moulding1-Dado 2
Konstruktion - Profil: Testmouldingdeep : Testmouldingdeep
Materialien und Oberflächen - Material: Mauerwerk - Sandstein Rot
Sonstige - Kategorie: Wände: Profilierte Wände; Familienname: Profilierte Wand

# IfcBuildingElementProxyType, no part of this type: Profilierte Wand:moulding1-Dado 2
Abhängigkeiten - Entlang eingefügter Elemente schneiden: no; Schneidet Wand: yes; Standardrücksprung: 0 m
ID-Daten - Typname: moulding1-Dado 2
Konstruktion - Profil: Testmouldingdeep : Testmouldingdeep
Materialien und Oberflächen - Material: Mauerwerk - Sandstein Rot
Sonstige - Kategorie: Wände: Profilierte Wände; Familienname: Profilierte Wand

# IfcBuildingElementProxyType, no part of this type: Profilierte Wand:moulding1-Dado 2
Abhängigkeiten - Entlang eingefügter Elemente schneiden: no; Schneidet Wand: yes; Standardrücksprung: 0 m
ID-Daten - Typname: moulding1-Dado 2
Konstruktion - Profil: Testmouldingdeep : Testmouldingdeep
Materialien und Oberflächen - Material: Mauerwerk - Sandstein Rot
Sonstige - Kategorie: Wände: Profilierte Wände; Familienname: Profilierte Wand

# IfcBuildingElementProxyType, no part of this type: Profilierte Wand:moulding1-Dado 2
Abhängigkeiten - Entlang eingefügter Elemente schneiden: no; Schneidet Wand: yes; Standardrücksprung: 0 m
ID-Daten - Typname: moulding1-Dado 2
Konstruktion - Profil: Testmouldingdeep : Testmouldingdeep
Materialien und Oberflächen - Material: Mauerwerk - Sandstein Rot
Sonstige - Kategorie: Wände: Profilierte Wände; Familienname: Profilierte Wand

# IfcBuildingElementProxyType, no part of this type: Profilierte Wand:moulding1-Dado 2
Abhängigkeiten - Entlang eingefügter Elemente schneiden: no; Schneidet Wand: yes; Standardrücksprung: 0 m
ID-Daten - Typname: moulding1-Dado 2
Konstruktion - Profil: Testmouldingdeep : Testmouldingdeep
Materialien und Oberflächen - Material: Mauerwerk - Sandstein Rot
Sonstige - Kategorie: Wände: Profilierte Wände; Familienname: Profilierte Wand

# IfcBuildingElementProxyType, no part of this type: Profilierte Wand:moulding1-Dado 2
Abhängigkeiten - Entlang eingefügter Elemente schneiden: no; Schneidet Wand: yes; Standardrücksprung: 0 m
ID-Daten - Typname: moulding1-Dado 2
Konstruktion - Profil: Testmouldingdeep : Testmouldingdeep
Materialien und Oberflächen - Material: Mauerwerk - Sandstein Rot
Sonstige - Kategorie: Wände: Profilierte Wände; Familienname: Profilierte Wand

# IfcBuildingElementProxyType, no part of this type: Profilierte Wand:moulding1-Dado 2
Abhängigkeiten - Entlang eingefügter Elemente schneiden: no; Schneidet Wand: yes; Standardrücksprung: 0 m
ID-Daten - Typname: moulding1-Dado 2
Konstruktion - Profil: Testmouldingdeep : Testmouldingdeep
Materialien und Oberflächen - Material: Mauerwerk - Sandstein Rot
Sonstige - Kategorie: Wände: Profilierte Wände; Familienname: Profilierte Wand

# IfcBuildingElementProxyType, no part of this type: Profilierte Wand:moulding1-Dado 2
Abhängigkeiten - Entlang eingefügter Elemente schneiden: no; Schneidet Wand: yes; Standardrücksprung: 0 m
ID-Daten - Typname: moulding1-Dado 2
Konstruktion - Profil: Testmouldingdeep : Testmouldingdeep
Materialien und Oberflächen - Material: Mauerwerk - Sandstein Rot
Sonstige - Kategorie: Wände: Profilierte Wände; Familienname: Profilierte Wand

# IfcBuildingElementProxyType, no part of this type: Profilierte Wand:moulding1-Dado 2
Abhängigkeiten - Entlang eingefügter Elemente schneiden: no; Schneidet Wand: yes; Standardrücksprung: 0 m
ID-Daten - Typname: moulding1-Dado 2
Konstruktion - Profil: Testmouldingdeep : Testmouldingdeep
Materialien und Oberflächen - Material: Mauerwerk - Sandstein Rot
Sonstige - Kategorie: Wände: Profilierte Wände; Familienname: Profilierte Wand

# IfcBuildingElementProxyType, no part of this type: Profilierte Wand:moulding1-Dado 2
Abhängigkeiten - Entlang eingefügter Elemente schneiden: no; Schneidet Wand: yes; Standardrücksprung: 0 m
ID-Daten - Typname: moulding1-Dado 2
Konstruktion - Profil: Testmouldingdeep : Testmouldingdeep
Materialien und Oberflächen - Material: Mauerwerk - Sandstein Rot
Sonstige - Kategorie: Wände: Profilierte Wände; Familienname: Profilierte Wand

# IfcBuildingElementProxyType, no part of this type: Profilierte Wand:moulding1-Dado 2
Abhängigkeiten - Entlang eingefügter Elemente schneiden: no; Schneidet Wand: yes; Standardrücksprung: 0 m
ID-Daten - Typname: moulding1-Dado 2
Konstruktion - Profil: Testmouldingdeep : Testmouldingdeep
Materialien und Oberflächen - Material: Mauerwerk - Sandstein Rot
Sonstige - Kategorie: Wände: Profilierte Wände; Familienname: Profilierte Wand

# IfcBuildingElementProxyType, no part of this type: Profilierte Wand:moulding1-Dado 2
Abhängigkeiten - Entlang eingefügter Elemente schneiden: no; Schneidet Wand: yes; Standardrücksprung: 0 m
ID-Daten - Typname: moulding1-Dado 2
Konstruktion - Profil: Testmouldingdeep : Testmouldingdeep
Materialien und Oberflächen - Material: Mauerwerk - Sandstein Rot
Sonstige - Kategorie: Wände: Profilierte Wände; Familienname: Profilierte Wand

# IfcBuildingElementProxyType, no part of this type: Profilierte Wand:moulding1-Dado 2
Abhängigkeiten - Entlang eingefügter Elemente schneiden: no; Schneidet Wand: yes; Standardrücksprung: 0 m
ID-Daten - Typname: moulding1-Dado 2
Konstruktion - Profil: Testmouldingdeep : Testmouldingdeep
Materialien und Oberflächen - Material: Mauerwerk - Sandstein Rot
Sonstige - Kategorie: Wände: Profilierte Wände; Familienname: Profilierte Wand

# IfcBuildingElementProxyType, no part of this type: Profilierte Wand:moulding1-Dado 2
Abhängigkeiten - Entlang eingefügter Elemente schneiden: no; Schneidet Wand: yes; Standardrücksprung: 0 m
ID-Daten - Typname: moulding1-Dado 2
Konstruktion - Profil: Testmouldingdeep : Testmouldingdeep
Materialien und Oberflächen - Material: Mauerwerk - Sandstein Rot
Sonstige - Kategorie: Wände: Profilierte Wände; Familienname: Profilierte Wand

# IfcBuildingElementProxyType, no part of this type: Profilierte Wand:moulding1-Dado 2
Abhängigkeiten - Entlang eingefügter Elemente schneiden: no; Schneidet Wand: yes; Standardrücksprung: 0 m
ID-Daten - Typname: moulding1-Dado 2
Konstruktion - Profil: Testmouldingdeep : Testmouldingdeep
Materialien und Oberflächen - Material: Mauerwerk - Sandstein Rot
Sonstige - Kategorie: Wände: Profilierte Wände; Familienname: Profilierte Wand

# IfcBuildingElementProxyType, no part of this type: Profilierte Wand:moulding1-Dado brick Stage 2
Abhängigkeiten - Entlang eingefügter Elemente schneiden: no; Schneidet Wand: yes; Standardrücksprung: 0 m
ID-Daten - Typname: moulding1-Dado brick Stage 2
Konstruktion - Profil: Mouldings : Moulding1
Materialien und Oberflächen - Material: Mauerwerk - Sichtmauerwerk_72x265 header Stage2
Sonstige - Kategorie: Wände: Profilierte Wände; Familienname: Profilierte Wand

# IfcBuildingElementProxyType, no part of this type: Profilierte Wand:moulding1-Dado brick Stage 2
Abhängigkeiten - Entlang eingefügter Elemente schneiden: no; Schneidet Wand: yes; Standardrücksprung: 0 m
ID-Daten - Typname: moulding1-Dado brick Stage 2
Konstruktion - Profil: Mouldings : Moulding1
Materialien und Oberflächen - Material: Mauerwerk - Sichtmauerwerk_72x265 header Stage2
Sonstige - Kategorie: Wände: Profilierte Wände; Familienname: Profilierte Wand

# IfcBuildingElementProxyType, no part of this type: Profilierte Wand:moulding1-Dado brick Stage 2
Abhängigkeiten - Entlang eingefügter Elemente schneiden: no; Schneidet Wand: yes; Standardrücksprung: 0 m
ID-Daten - Typname: moulding1-Dado brick Stage 2
Konstruktion - Profil: Mouldings : Moulding1
Materialien und Oberflächen - Material: Mauerwerk - Sichtmauerwerk_72x265 header Stage2
Sonstige - Kategorie: Wände: Profilierte Wände; Familienname: Profilierte Wand

# IfcBuildingElementProxyType, no part of this type: Profilierte Wand:plinth
Abhängigkeiten - Entlang eingefügter Elemente schneiden: no; Schneidet Wand: yes; Standardrücksprung: 0 m
ID-Daten - Typname: plinth
Konstruktion - Profil: Plinth profile : plinth
Materialien und Oberflächen - Material: Mauerwerk - Sandstein Rot
Sonstige - Kategorie: Wände: Profilierte Wände; Familienname: Profilierte Wand

# IfcBuildingElementProxyType, no part of this type: Profilierte Wand:plinth
Abhängigkeiten - Entlang eingefügter Elemente schneiden: no; Schneidet Wand: yes; Standardrücksprung: 0 m
ID-Daten - Typname: plinth
Konstruktion - Profil: Plinth profile : plinth
Materialien und Oberflächen - Material: Mauerwerk - Sandstein Rot
Sonstige - Kategorie: Wände: Profilierte Wände; Familienname: Profilierte Wand

# IfcBuildingElementProxyType, no part of this type: Profilierte Wand:plinth
Abhängigkeiten - Entlang eingefügter Elemente schneiden: no; Schneidet Wand: yes; Standardrücksprung: 0 m
ID-Daten - Typname: plinth
Konstruktion - Profil: Plinth profile : plinth
Materialien und Oberflächen - Material: Mauerwerk - Sandstein Rot
Sonstige - Kategorie: Wände: Profilierte Wände; Familienname: Profilierte Wand

# IfcBuildingElementProxyType, no part of this type: Profilierte Wand:plinth
Abhängigkeiten - Entlang eingefügter Elemente schneiden: no; Schneidet Wand: yes; Standardrücksprung: 0 m
ID-Daten - Typname: plinth
Konstruktion - Profil: Plinth profile : plinth
Materialien und Oberflächen - Material: Mauerwerk - Sandstein Rot
Sonstige - Kategorie: Wände: Profilierte Wände; Familienname: Profilierte Wand

# IfcBuildingElementProxyType, no part of this type: Profilierte Wand:plinth
Abhängigkeiten - Entlang eingefügter Elemente schneiden: no; Schneidet Wand: yes; Standardrücksprung: 0 m
ID-Daten - Typname: plinth
Konstruktion - Profil: Plinth profile : plinth
Materialien und Oberflächen - Material: Mauerwerk - Sandstein Rot
Sonstige - Kategorie: Wände: Profilierte Wände; Familienname: Profilierte Wand

# IfcBuildingElementProxyType, no part of this type: Profilierte Wand:plinth
Abhängigkeiten - Entlang eingefügter Elemente schneiden: no; Schneidet Wand: yes; Standardrücksprung: 0 m
ID-Daten - Typname: plinth
Konstruktion - Profil: Plinth profile : plinth
Materialien und Oberflächen - Material: Mauerwerk - Sandstein Rot
Sonstige - Kategorie: Wände: Profilierte Wände; Familienname: Profilierte Wand

# IfcBuildingElementProxyType, no part of this type: Profilierte Wand:plinth
Abhängigkeiten - Entlang eingefügter Elemente schneiden: no; Schneidet Wand: yes; Standardrücksprung: 0 m
ID-Daten - Typname: plinth
Konstruktion - Profil: Plinth profile : plinth
Materialien und Oberflächen - Material: Mauerwerk - Sandstein Rot
Sonstige - Kategorie: Wände: Profilierte Wände; Familienname: Profilierte Wand

# IfcBuildingElementProxyType, no part of this type: Profilierte Wand:plinth
Abhängigkeiten - Entlang eingefügter Elemente schneiden: no; Schneidet Wand: yes; Standardrücksprung: 0 m
ID-Daten - Typname: plinth
Konstruktion - Profil: Plinth profile : plinth
Materialien und Oberflächen - Material: Mauerwerk - Sandstein Rot
Sonstige - Kategorie: Wände: Profilierte Wände; Familienname: Profilierte Wand

# IfcBuildingElementProxyType, no part of this type: Profilierte Wand:plinth
Abhängigkeiten - Entlang eingefügter Elemente schneiden: no; Schneidet Wand: yes; Standardrücksprung: 0 m
ID-Daten - Typname: plinth
Konstruktion - Profil: Plinth profile : plinth
Materialien und Oberflächen - Material: Mauerwerk - Sandstein Rot
Sonstige - Kategorie: Wände: Profilierte Wände; Familienname: Profilierte Wand

# IfcBuildingElementProxyType, no part of this type: Profilierte Wand:plinth
Abhängigkeiten - Entlang eingefügter Elemente schneiden: no; Schneidet Wand: yes; Standardrücksprung: 0 m
ID-Daten - Typname: plinth
Konstruktion - Profil: Plinth profile : plinth
Materialien und Oberflächen - Material: Mauerwerk - Sandstein Rot
Sonstige - Kategorie: Wände: Profilierte Wände; Familienname: Profilierte Wand

# IfcBuildingElementProxyType, no part of this type: Profilierte Wand:plinth
Abhängigkeiten - Entlang eingefügter Elemente schneiden: no; Schneidet Wand: yes; Standardrücksprung: 0 m
ID-Daten - Typname: plinth
Konstruktion - Profil: Plinth profile : plinth
Materialien und Oberflächen - Material: Mauerwerk - Sandstein Rot
Sonstige - Kategorie: Wände: Profilierte Wände; Familienname: Profilierte Wand

# IfcBuildingElementProxyType, no part of this type: Profilierte Wand:plinth
Abhängigkeiten - Entlang eingefügter Elemente schneiden: no; Schneidet Wand: yes; Standardrücksprung: 0 m
ID-Daten - Typname: plinth
Konstruktion - Profil: Plinth profile : plinth
Materialien und Oberflächen - Material: Mauerwerk - Sandstein Rot
Sonstige - Kategorie: Wände: Profilierte Wände; Familienname: Profilierte Wand

# IfcBuildingElementProxyType, no part of this type: Profilierte Wand:plinth
Abhängigkeiten - Entlang eingefügter Elemente schneiden: no; Schneidet Wand: yes; Standardrücksprung: 0 m
ID-Daten - Typname: plinth
Konstruktion - Profil: Plinth profile : plinth
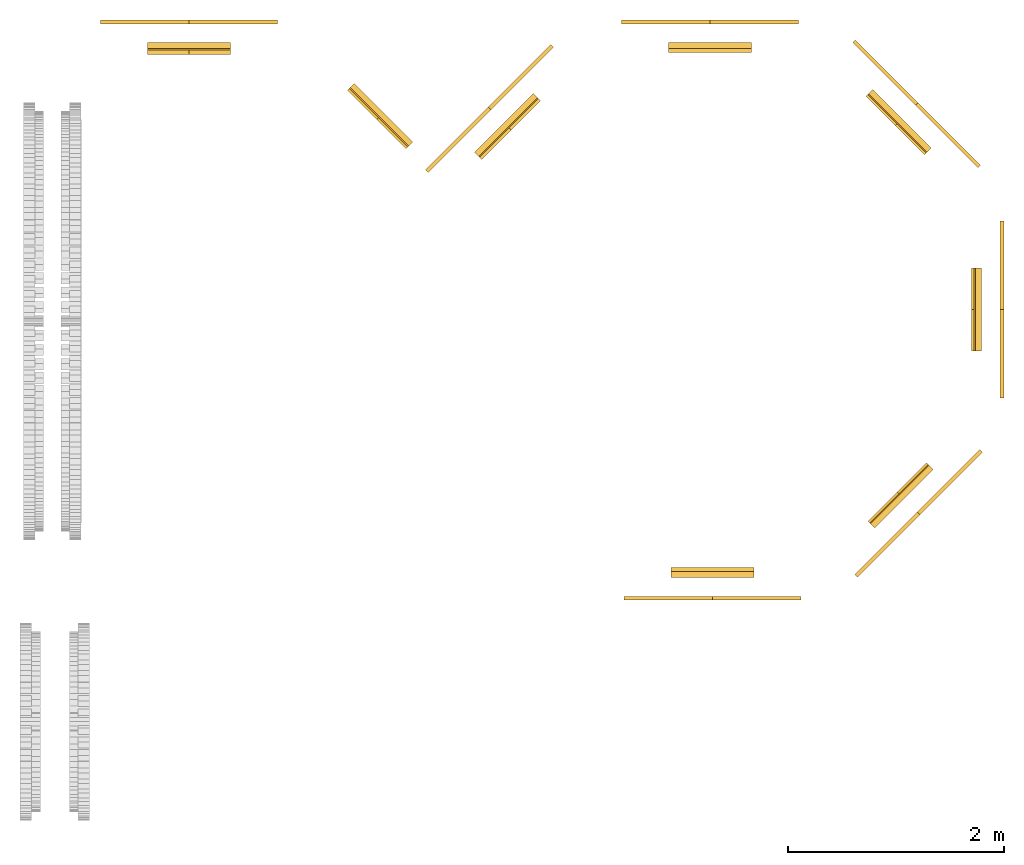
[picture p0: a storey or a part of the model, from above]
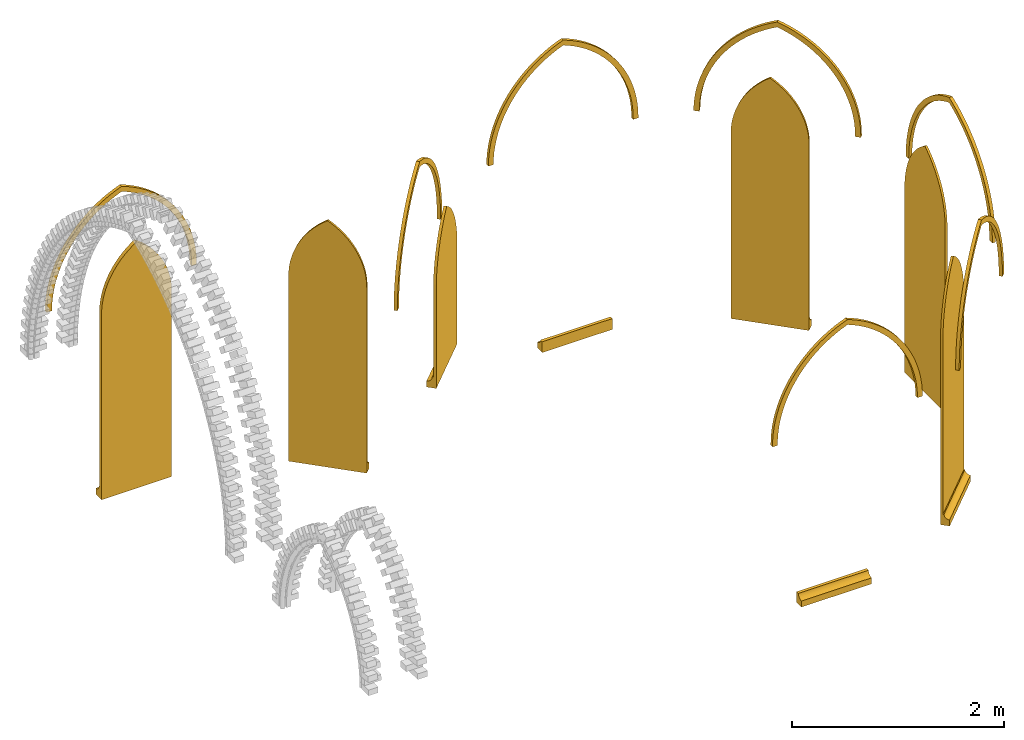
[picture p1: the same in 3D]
Properties of the parts of a building model (IFC2X3), part 4 of 7

# IfcBuildingElementProxyType, no part of this type: Profilierte Wand:plinth
Materialien und Oberflächen - Material: Mauerwerk - Sandstein Rot
Sonstige - Kategorie: Wände: Profilierte Wände; Familienname: Profilierte Wand

# IfcBuildingElementProxyType, no part of this type: Profilierte Wand:plinth
Abhängigkeiten - Entlang eingefügter Elemente schneiden: no; Schneidet Wand: yes; Standardrücksprung: 0 m
ID-Daten - Typname: plinth
Konstruktion - Profil: Plinth profile : plinth
Materialien und Oberflächen - Material: Mauerwerk - Sandstein Rot
Sonstige - Kategorie: Wände: Profilierte Wände; Familienname: Profilierte Wand

# IfcBuildingElementProxyType, no part of this type: Profilierte Wand:plinth
Abhängigkeiten - Entlang eingefügter Elemente schneiden: no; Schneidet Wand: yes; Standardrücksprung: 0 m
ID-Daten - Typname: plinth
Konstruktion - Profil: Plinth profile : plinth
Materialien und Oberflächen - Material: Mauerwerk - Sandstein Rot
Sonstige - Kategorie: Wände: Profilierte Wände; Familienname: Profilierte Wand

# IfcBuildingElementProxyType, no part of this type: Profilierte Wand:plinth
Abhängigkeiten - Entlang eingefügter Elemente schneiden: no; Schneidet Wand: yes; Standardrücksprung: 0 m
ID-Daten - Typname: plinth
Konstruktion - Profil: Plinth profile : plinth
Materialien und Oberflächen - Material: Mauerwerk - Sandstein Rot
Sonstige - Kategorie: Wände: Profilierte Wände; Familienname: Profilierte Wand

# IfcBuildingElementProxyType, no part of this type: Profilierte Wand:plinth
Abhängigkeiten - Entlang eingefügter Elemente schneiden: no; Schneidet Wand: yes; Standardrücksprung: 0 m
ID-Daten - Typname: plinth
Konstruktion - Profil: Plinth profile : plinth
Materialien und Oberflächen - Material: Mauerwerk - Sandstein Rot
Sonstige - Kategorie: Wände: Profilierte Wände; Familienname: Profilierte Wand

# IfcBuildingElementProxyType, no part of this type: Profilierte Wand:plinth
Abhängigkeiten - Entlang eingefügter Elemente schneiden: no; Schneidet Wand: yes; Standardrücksprung: 0 m
ID-Daten - Typname: plinth
Konstruktion - Profil: Plinth profile : plinth
Materialien und Oberflächen - Material: Mauerwerk - Sandstein Rot
Sonstige - Kategorie: Wände: Profilierte Wände; Familienname: Profilierte Wand

# IfcBuildingElementProxyType, no part of this type: Profilierte Wand:plinth
Abhängigkeiten - Entlang eingefügter Elemente schneiden: no; Schneidet Wand: yes; Standardrücksprung: 0 m
ID-Daten - Typname: plinth
Konstruktion - Profil: Plinth profile : plinth
Materialien und Oberflächen - Material: Mauerwerk - Sandstein Rot
Sonstige - Kategorie: Wände: Profilierte Wände; Familienname: Profilierte Wand

# IfcBuildingElementProxyType, no part of this type: Profilierte Wand:plinth
Abhängigkeiten - Entlang eingefügter Elemente schneiden: no; Schneidet Wand: yes; Standardrücksprung: 0 m
ID-Daten - Typname: plinth
Konstruktion - Profil: Plinth profile : plinth
Materialien und Oberflächen - Material: Mauerwerk - Sandstein Rot
Sonstige - Kategorie: Wände: Profilierte Wände; Familienname: Profilierte Wand

# IfcBuildingElementProxyType, no part of this type: Profilierte Wand:plinth
Abhängigkeiten - Entlang eingefügter Elemente schneiden: no; Schneidet Wand: yes; Standardrücksprung: 0 m
ID-Daten - Typname: plinth
Konstruktion - Profil: Plinth profile : plinth
Materialien und Oberflächen - Material: Mauerwerk - Sandstein Rot
Sonstige - Kategorie: Wände: Profilierte Wände; Familienname: Profilierte Wand

# IfcBuildingElementProxyType, no part of this type: Profilierte Wand:plinth
Abhängigkeiten - Entlang eingefügter Elemente schneiden: no; Schneidet Wand: yes; Standardrücksprung: 0 m
ID-Daten - Typname: plinth
Konstruktion - Profil: Plinth profile : plinth
Materialien und Oberflächen - Material: Mauerwerk - Sandstein Rot
Sonstige - Kategorie: Wände: Profilierte Wände; Familienname: Profilierte Wand

# IfcBuildingElementProxyType, no part of this type: Profilierte Wand:plinth
Abhängigkeiten - Entlang eingefügter Elemente schneiden: no; Schneidet Wand: yes; Standardrücksprung: 0 m
ID-Daten - Typname: plinth
Konstruktion - Profil: Plinth profile : plinth
Materialien und Oberflächen - Material: Mauerwerk - Sandstein Rot
Sonstige - Kategorie: Wände: Profilierte Wände; Familienname: Profilierte Wand

# IfcBuildingElementProxyType, no part of this type: Profilierte Wand:plinth
Abhängigkeiten - Entlang eingefügter Elemente schneiden: no; Schneidet Wand: yes; Standardrücksprung: 0 m
ID-Daten - Typname: plinth
Konstruktion - Profil: Plinth profile : plinth
Materialien und Oberflächen - Material: Mauerwerk - Sandstein Rot
Sonstige - Kategorie: Wände: Profilierte Wände; Familienname: Profilierte Wand

# IfcBuildingElementProxyType, no part of this type: Profilierte Wand:plinth
Abhängigkeiten - Entlang eingefügter Elemente schneiden: no; Schneidet Wand: yes; Standardrücksprung: 0 m
ID-Daten - Typname: plinth
Konstruktion - Profil: Plinth profile : plinth
Materialien und Oberflächen - Material: Mauerwerk - Sandstein Rot
Sonstige - Kategorie: Wände: Profilierte Wände; Familienname: Profilierte Wand

# IfcBuildingElementProxyType, no part of this type: Profilierte Wand:plinth
Abhängigkeiten - Entlang eingefügter Elemente schneiden: no; Schneidet Wand: yes; Standardrücksprung: 0 m
ID-Daten - Typname: plinth
Konstruktion - Profil: Plinth profile : plinth
Materialien und Oberflächen - Material: Mauerwerk - Sandstein Rot
Sonstige - Kategorie: Wände: Profilierte Wände; Familienname: Profilierte Wand

# IfcBuildingElementProxyType, no part of this type: Profilierte Wand:plinth
Abhängigkeiten - Entlang eingefügter Elemente schneiden: no; Schneidet Wand: yes; Standardrücksprung: 0 m
ID-Daten - Typname: plinth
Konstruktion - Profil: Plinth profile : plinth
Materialien und Oberflächen - Material: Mauerwerk - Sandstein Rot
Sonstige - Kategorie: Wände: Profilierte Wände; Familienname: Profilierte Wand

# IfcBuildingElementProxyType, no part of this type: Profilierte Wand:plinth
Abhängigkeiten - Entlang eingefügter Elemente schneiden: no; Schneidet Wand: yes; Standardrücksprung: 0 m
ID-Daten - Typname: plinth
Konstruktion - Profil: Plinth profile : plinth
Materialien und Oberflächen - Material: Mauerwerk - Sandstein Rot
Sonstige - Kategorie: Wände: Profilierte Wände; Familienname: Profilierte Wand

# IfcBuildingElementProxyType, no part of this type: Profilierte Wand:plinth
Abhängigkeiten - Entlang eingefügter Elemente schneiden: no; Schneidet Wand: yes; Standardrücksprung: 0 m
ID-Daten - Typname: plinth
Konstruktion - Profil: Plinth profile : plinth
Materialien und Oberflächen - Material: Mauerwerk - Sandstein Rot
Sonstige - Kategorie: Wände: Profilierte Wände; Familienname: Profilierte Wand

# IfcBuildingElementProxyType, no part of this type: Profilierte Wand:plinth
Abhängigkeiten - Entlang eingefügter Elemente schneiden: no; Schneidet Wand: yes; Standardrücksprung: 0 m
ID-Daten - Typname: plinth
Konstruktion - Profil: Plinth profile : plinth
Materialien und Oberflächen - Material: Mauerwerk - Sandstein Rot
Sonstige - Kategorie: Wände: Profilierte Wände; Familienname: Profilierte Wand

# IfcBuildingElementProxyType, no part of this type: Profilierte Wand:plinth
Abhängigkeiten - Entlang eingefügter Elemente schneiden: no; Schneidet Wand: yes; Standardrücksprung: 0 m
ID-Daten - Typname: plinth
Konstruktion - Profil: Plinth profile : plinth
Materialien und Oberflächen - Material: Mauerwerk - Sandstein Rot
Sonstige - Kategorie: Wände: Profilierte Wände; Familienname: Profilierte Wand

# IfcBuildingElementProxyType, no part of this type: Profilierte Wand:plinth
Abhängigkeiten - Entlang eingefügter Elemente schneiden: no; Schneidet Wand: yes; Standardrücksprung: 0 m
ID-Daten - Typname: plinth
Konstruktion - Profil: Plinth profile : plinth
Materialien und Oberflächen - Material: Mauerwerk - Sandstein Rot
Sonstige - Kategorie: Wände: Profilierte Wände; Familienname: Profilierte Wand

# IfcBuildingElementProxyType, no part of this type: Profilierte Wand:plinth
Abhängigkeiten - Entlang eingefügter Elemente schneiden: no; Schneidet Wand: yes; Standardrücksprung: 0 m
ID-Daten - Typname: plinth
Konstruktion - Profil: Plinth profile : plinth
Materialien und Oberflächen - Material: Mauerwerk - Sandstein Rot
Sonstige - Kategorie: Wände: Profilierte Wände; Familienname: Profilierte Wand

# IfcBuildingElementProxyType, no part of this type: Profilierte Wand:plinth
Abhängigkeiten - Entlang eingefügter Elemente schneiden: no; Schneidet Wand: yes; Standardrücksprung: 0 m
ID-Daten - Typname: plinth
Konstruktion - Profil: Plinth profile : plinth
Materialien und Oberflächen - Material: Mauerwerk - Sandstein Rot
Sonstige - Kategorie: Wände: Profilierte Wände; Familienname: Profilierte Wand

# IfcBuildingElementProxyType, no part of this type: Profilierte Wand:plinth
Abhängigkeiten - Entlang eingefügter Elemente schneiden: no; Schneidet Wand: yes; Standardrücksprung: 0 m
ID-Daten - Typname: plinth
Konstruktion - Profil: Plinth profile : plinth
Materialien und Oberflächen - Material: Mauerwerk - Sandstein Rot
Sonstige - Kategorie: Wände: Profilierte Wände; Familienname: Profilierte Wand

# IfcBuildingElementProxyType, no part of this type: Profilierte Wand:plinth
Abhängigkeiten - Entlang eingefügter Elemente schneiden: no; Schneidet Wand: yes; Standardrücksprung: 0 m
ID-Daten - Typname: plinth
Konstruktion - Profil: Plinth profile : plinth
Materialien und Oberflächen - Material: Mauerwerk - Sandstein Rot
Sonstige - Kategorie: Wände: Profilierte Wände; Familienname: Profilierte Wand

# IfcBuildingElementProxyType, no part of this type: Profilierte Wand:plinth
Abhängigkeiten - Entlang eingefügter Elemente schneiden: no; Schneidet Wand: yes; Standardrücksprung: 0 m
ID-Daten - Typname: plinth
Konstruktion - Profil: Plinth profile : plinth
Materialien und Oberflächen - Material: Mauerwerk - Sandstein Rot
Sonstige - Kategorie: Wände: Profilierte Wände; Familienname: Profilierte Wand

# IfcBuildingElementProxyType, no part of this type: Profilierte Wand:plinth
Abhängigkeiten - Entlang eingefügter Elemente schneiden: no; Schneidet Wand: yes; Standardrücksprung: 0 m
ID-Daten - Typname: plinth
Konstruktion - Profil: Plinth profile : plinth
Materialien und Oberflächen - Material: Mauerwerk - Sandstein Rot
Sonstige - Kategorie: Wände: Profilierte Wände; Familienname: Profilierte Wand

# IfcBuildingElementProxyType, no part of this type: ProfilierteGiebel_1:ProfilierteGiebel Stage 1 Lower
Material: Mauerwerk - Sandstein Rot, Mauerwerk - Sichtmauerwerk_72x265 english bond
Abhängigkeiten - Vorgabe-Ansicht: 0 m
ID-Daten - Typname: ProfilierteGiebel Stage 1 Lower
Materialien und Oberflächen - MaterialGiebel: Mauerwerk - Sichtmauerwerk_72x265 english bond; MaterialMoulding: Mauerwerk - Sandstein Rot
Sonstige - Kategorie: Allgemeines Modell; Familienname: ProfilierteGiebel_1

# IfcBuildingElementProxyType, no part of this type: ProfilierteGiebel_1:ProfilierteGiebel Stage 1 Lower
Material: Mauerwerk - Sandstein Rot, Mauerwerk - Sichtmauerwerk_72x265 english bond
Abhängigkeiten - Vorgabe-Ansicht: 0 m
ID-Daten - Typname: ProfilierteGiebel Stage 1 Lower
Materialien und Oberflächen - MaterialGiebel: Mauerwerk - Sichtmauerwerk_72x265 english bond; MaterialMoulding: Mauerwerk - Sandstein Rot
Sonstige - Kategorie: Allgemeines Modell; Familienname: ProfilierteGiebel_1

# IfcBuildingElementProxyType, no part of this type: ProfilierteGiebel_1:ProfilierteGiebel Stage 1 Lower
Material: Mauerwerk - Sandstein Rot, Mauerwerk - Sichtmauerwerk_72x265 english bond
Abhängigkeiten - Vorgabe-Ansicht: 0 m
ID-Daten - Typname: ProfilierteGiebel Stage 1 Lower
Materialien und Oberflächen - MaterialGiebel: Mauerwerk - Sichtmauerwerk_72x265 english bond; MaterialMoulding: Mauerwerk - Sandstein Rot
Sonstige - Kategorie: Allgemeines Modell; Familienname: ProfilierteGiebel_1

# IfcBuildingElementProxyType, no part of this type: ProfilierteGiebel_1:ProfilierteGiebel Stage 1 Lower
Material: Mauerwerk - Sandstein Rot, Mauerwerk - Sichtmauerwerk_72x265 english bond
Abhängigkeiten - Vorgabe-Ansicht: 0 m
ID-Daten - Typname: ProfilierteGiebel Stage 1 Lower
Materialien und Oberflächen - MaterialGiebel: Mauerwerk - Sichtmauerwerk_72x265 english bond; MaterialMoulding: Mauerwerk - Sandstein Rot
Sonstige - Kategorie: Allgemeines Modell; Familienname: ProfilierteGiebel_1

# IfcBuildingElementProxyType, no part of this type: ProfilierteGiebel_1:ProfilierteGiebel Stage 1 Upper
Material: Mauerwerk - Sandstein Rot, Mauerwerk - Sichtmauerwerk_72x265 english bond
Abhängigkeiten - Vorgabe-Ansicht: 0 m
ID-Daten - Typname: ProfilierteGiebel Stage 1 Upper
Materialien und Oberflächen - MaterialGiebel: Mauerwerk - Sichtmauerwerk_72x265 english bond; MaterialMoulding: Mauerwerk - Sandstein Rot
Sonstige - Kategorie: Allgemeines Modell; Familienname: ProfilierteGiebel_1

# IfcBuildingElementProxyType, no part of this type: ProfilierteGiebel_1:ProfilierteGiebel Stage 1 Upper
Material: Mauerwerk - Sandstein Rot, Mauerwerk - Sichtmauerwerk_72x265 english bond
Abhängigkeiten - Vorgabe-Ansicht: 0 m
ID-Daten - Typname: ProfilierteGiebel Stage 1 Upper
Materialien und Oberflächen - MaterialGiebel: Mauerwerk - Sichtmauerwerk_72x265 english bond; MaterialMoulding: Mauerwerk - Sandstein Rot
Sonstige - Kategorie: Allgemeines Modell; Familienname: ProfilierteGiebel_1

# IfcBuildingElementProxyType, no part of this type: ProfilierteGiebel_1:ProfilierteGiebel Stage 1 Upper
Material: Mauerwerk - Sandstein Rot, Mauerwerk - Sichtmauerwerk_72x265 english bond
Abhängigkeiten - Vorgabe-Ansicht: 0 m
ID-Daten - Typname: ProfilierteGiebel Stage 1 Upper
Materialien und Oberflächen - MaterialGiebel: Mauerwerk - Sichtmauerwerk_72x265 english bond; MaterialMoulding: Mauerwerk - Sandstein Rot
Sonstige - Kategorie: Allgemeines Modell; Familienname: ProfilierteGiebel_1

# IfcBuildingElementProxyType, no part of this type: ProfilierteGiebel_1:ProfilierteGiebel Stage 1 Upper
Material: Mauerwerk - Sichtmauerwerk_72x265 english bond, Mauerwerk - Sandstein Rot
Abhängigkeiten - Vorgabe-Ansicht: 0 m
ID-Daten - Typname: ProfilierteGiebel Stage 1 Upper
Materialien und Oberflächen - MaterialGiebel: Mauerwerk - Sichtmauerwerk_72x265 english bond; MaterialMoulding: Mauerwerk - Sandstein Rot
Sonstige - Kategorie: Allgemeines Modell; Familienname: ProfilierteGiebel_1

# IfcBuildingElementProxyType, no part of this type: ProfilierteGiebel_1:ProfilierteGiebel Stage 1 Upper
Material: Mauerwerk - Sandstein Rot, Mauerwerk - Sichtmauerwerk_72x265 english bond
Abhängigkeiten - Vorgabe-Ansicht: 0 m
ID-Daten - Typname: ProfilierteGiebel Stage 1 Upper
Materialien und Oberflächen - MaterialGiebel: Mauerwerk - Sichtmauerwerk_72x265 english bond; MaterialMoulding: Mauerwerk - Sandstein Rot
Sonstige - Kategorie: Allgemeines Modell; Familienname: ProfilierteGiebel_1

# IfcBuildingElementProxyType, no part of this type: ProfilierteGiebel_1:ProfilierteGiebel Stage 2
Material: Mauerwerk - Sandstein Rot, Mauerwerk - Sichtmauerwerk_72x265 english bond Stage2
Abhängigkeiten - Vorgabe-Ansicht: 0 m
ID-Daten - Typname: ProfilierteGiebel Stage 2
Materialien und Oberflächen - MaterialMoulding: Mauerwerk - Sandstein Rot; MaterialGiebel: Mauerwerk - Sichtmauerwerk_72x265 english bond Stage2
Sonstige - Kategorie: Allgemeines Modell; Familienname: ProfilierteGiebel_1

# IfcBuildingElementProxyType, no part of this type: ProfilierteGiebel_1:ProfilierteGiebel Stage 2
Material: Mauerwerk - Sandstein Rot, Mauerwerk - Sichtmauerwerk_72x265 english bond Stage2
Abhängigkeiten - Vorgabe-Ansicht: 0 m
ID-Daten - Typname: ProfilierteGiebel Stage 2
Materialien und Oberflächen - MaterialMoulding: Mauerwerk - Sandstein Rot; MaterialGiebel: Mauerwerk - Sichtmauerwerk_72x265 english bond Stage2
Sonstige - Kategorie: Allgemeines Modell; Familienname: ProfilierteGiebel_1

# IfcBuildingElementProxyType, no part of this type: ProfilierteGiebel_1:ProfilierteGiebel Stage 2
Material: Mauerwerk - Sandstein Rot, Mauerwerk - Sichtmauerwerk_72x265 english bond Stage2
Abhängigkeiten - Vorgabe-Ansicht: 0 m
ID-Daten - Typname: ProfilierteGiebel Stage 2
Materialien und Oberflächen - MaterialMoulding: Mauerwerk - Sandstein Rot; MaterialGiebel: Mauerwerk - Sichtmauerwerk_72x265 english bond Stage2
Sonstige - Kategorie: Allgemeines Modell; Familienname: ProfilierteGiebel_1

# IfcBuildingElementProxyType, no part of this type: ProfilierteGiebel_1:ProfilierteGiebel Stage 2
Material: Mauerwerk - Sichtmauerwerk_72x265 english bond Stage2, Mauerwerk - Sandstein Rot
Abhängigkeiten - Vorgabe-Ansicht: 0 m
ID-Daten - Typname: ProfilierteGiebel Stage 2
Materialien und Oberflächen - MaterialMoulding: Mauerwerk - Sandstein Rot; MaterialGiebel: Mauerwerk - Sichtmauerwerk_72x265 english bond Stage2
Sonstige - Kategorie: Allgemeines Modell; Familienname: ProfilierteGiebel_1

# IfcBuildingElementProxyType, no part of this type: ProfilierteGiebel_1:ProfilierteGiebel Stage 2
Material: Mauerwerk - Sandstein Rot, Mauerwerk - Sichtmauerwerk_72x265 english bond Stage2
Abhängigkeiten - Vorgabe-Ansicht: 0 m
ID-Daten - Typname: ProfilierteGiebel Stage 2
Materialien und Oberflächen - MaterialMoulding: Mauerwerk - Sandstein Rot; MaterialGiebel: Mauerwerk - Sichtmauerwerk_72x265 english bond Stage2
Sonstige - Kategorie: Allgemeines Modell; Familienname: ProfilierteGiebel_1

# IfcBuildingElementProxyType, no part of this type: ProfilierteGiebel_1:ProfilierteGiebel Stage 2
Material: Mauerwerk - Sandstein Rot, Mauerwerk - Sichtmauerwerk_72x265 english bond Stage2
Abhängigkeiten - Vorgabe-Ansicht: 0 m
ID-Daten - Typname: ProfilierteGiebel Stage 2
Materialien und Oberflächen - MaterialMoulding: Mauerwerk - Sandstein Rot; MaterialGiebel: Mauerwerk - Sichtmauerwerk_72x265 english bond Stage2
Sonstige - Kategorie: Allgemeines Modell; Familienname: ProfilierteGiebel_1

# IfcBuildingElementProxyType, no part of this type: ProfilierteGiebel_1:ProfilierteGiebel Stage 2
Material: Mauerwerk - Sandstein Rot, Mauerwerk - Sichtmauerwerk_72x265 english bond Stage2
Abhängigkeiten - Vorgabe-Ansicht: 0 m
ID-Daten - Typname: ProfilierteGiebel Stage 2
Materialien und Oberflächen - MaterialMoulding: Mauerwerk - Sandstein Rot; MaterialGiebel: Mauerwerk - Sichtmauerwerk_72x265 english bond Stage2
Sonstige - Kategorie: Allgemeines Modell; Familienname: ProfilierteGiebel_1

# IfcBuildingElementProxyType, no part of this type: ProfilierteGiebel_1:ProfilierteGiebel Stage 2
Material: Mauerwerk - Sandstein Rot, Mauerwerk - Sichtmauerwerk_72x265 english bond Stage2
Abhängigkeiten - Vorgabe-Ansicht: 0 m
ID-Daten - Typname: ProfilierteGiebel Stage 2
Materialien und Oberflächen - MaterialMoulding: Mauerwerk - Sandstein Rot; MaterialGiebel: Mauerwerk - Sichtmauerwerk_72x265 english bond Stage2
Sonstige - Kategorie: Allgemeines Modell; Familienname: ProfilierteGiebel_1

# IfcBuildingElementProxyType, no part of this type: ProfilierteGiebel_1:ProfilierteGiebel Stage 2
Material: Mauerwerk - Sandstein Rot, Mauerwerk - Sichtmauerwerk_72x265 english bond Stage2
Abhängigkeiten - Vorgabe-Ansicht: 0 m
ID-Daten - Typname: ProfilierteGiebel Stage 2
Materialien und Oberflächen - MaterialMoulding: Mauerwerk - Sandstein Rot; MaterialGiebel: Mauerwerk - Sichtmauerwerk_72x265 english bond Stage2
Sonstige - Kategorie: Allgemeines Modell; Familienname: ProfilierteGiebel_1

# IfcBuildingElementProxyType, no part of this type: ProfilierteGiebel_1:ProfilierteGiebel Stage 2
Material: Mauerwerk - Sichtmauerwerk_72x265 english bond Stage2, Mauerwerk - Sandstein Rot
Abhängigkeiten - Vorgabe-Ansicht: 0 m
ID-Daten - Typname: ProfilierteGiebel Stage 2
Materialien und Oberflächen - MaterialMoulding: Mauerwerk - Sandstein Rot; MaterialGiebel: Mauerwerk - Sichtmauerwerk_72x265 english bond Stage2
Sonstige - Kategorie: Allgemeines Modell; Familienname: ProfilierteGiebel_1

# IfcBuildingElementProxyType, no part of this type: Pulpit:Pulpit
Material: Holz - Eiche Dark, Stonework - Marble
Abhängigkeiten - Vorgabe-Ansicht: 0 m
Bemaßungen - BaseWidth: 1 m; PlinthDepth: 0.72 m; PulpitDepth: 1.16627 m; PulpitWidth: 1.4 m
ID-Daten - Typname: Pulpit
Materialien und Oberflächen - PlinthMaterial: Stonework - Marble; PulpitMaterial: Holz - Eiche Dark
Sonstige - Kategorie: Allgemeines Modell; Familienname: Pulpit

# IfcBuildingElementProxyType, no part of this type: StoreWindow:Typ 1
Material: <Unnamed> (2)
Abhängigkeiten(Type) - Vorgabe-Ansicht: 0 m
Bemaßungen(Type) - CillDropInside: 0.08 m; DepthOutside: 0.1475 m; FrameWidth: 0.02 m; GlassThickness: 0.01 m; HeightInside: 0.86 m; HeightOutside: 0.72 m; WidthInside: 0.865 m; WidthOutside: 0.3 m
ID-Daten(Type) - Typname: Typ 1
Sonstige(Type) - Kategorie: Allgemeines Modell; Familienname: StoreWindow

# IfcBuildingElementProxyType, no part of this type: TowerPierCap:TowerPierCap
Material: Mauerwerk - Sandstein Rot
Abhängigkeiten - Vorgabe-Ansicht: 0 m
Bemaßungen - CapWidth: 0.78 m; NoseHeight: 0.060119 m; NoseOverhang: 0.05 m; ProfileHeight: 0.432 m; WallDepthAbove: 0.13 m; WallDepthBelow: 0.39 m
ID-Daten - Typname: TowerPierCap
Materialien und Oberflächen - CapMaterial: Mauerwerk - Sandstein Rot
Sonstige - Kategorie: Allgemeines Modell; Familienname: TowerPierCap

# IfcBuildingElementProxyType, no part of this type: TowerPierCap:TowerPierCap
Material: Mauerwerk - Sandstein Rot
Abhängigkeiten - Vorgabe-Ansicht: 0 m
Bemaßungen - CapWidth: 0.78 m; NoseHeight: 0.060119 m; NoseOverhang: 0.05 m; ProfileHeight: 0.432 m; WallDepthAbove: 0.13 m; WallDepthBelow: 0.39 m
ID-Daten - Typname: TowerPierCap
Materialien und Oberflächen - CapMaterial: Mauerwerk - Sandstein Rot
Sonstige - Kategorie: Allgemeines Modell; Familienname: TowerPierCap

# IfcBuildingElementProxyType, no part of this type: WallCorbelStageCorner:WallCorbelStageCorner
Material: Quoin Brick (9)
Abhängigkeiten - Vorgabe-Ansicht: 0 m
Bemaßungen - BreitePilaster: 0.52 m; HoeheUKCorbel: 3.534 m
ID-Daten - Typname: WallCorbelStageCorner
Materialien und Oberflächen - CorbelMaterial: Quoin Brick
Sonstige - Kategorie: Allgemeines Modell; Familienname: WallCorbelStageCorner

# IfcBuildingElementProxyType, no part of this type: buttressMain:buttressMain
Material: Mauerwerk - Sichtmauerwerk_72x265 english bond
Abhängigkeiten - Vorgabe-Ansicht: 1.2192 m
Bemaßungen - Width: 0.78 m
ID-Daten - Typname: buttressMain
Materialien und Oberflächen - ButtressMaterial: Mauerwerk - Sichtmauerwerk_72x265 english bond
Sonstige - Kategorie: Allgemeines Modell; Familienname: buttressMain
Pset_ProvisionForVoid - Width: 0.78 m

# IfcColumnType, no part of this type: capital_mesh_3
PredefinedType: COLUMN
Phasen - Phase erstellt: Phase 2 1888

# IfcMemberType, no part of this type: Rechteckiger Pfosten:30 x195
PredefinedType: MULLION; Material: <Unnamed>, Kunststoff - grau 70-70-70
Abhängigkeiten - Winkel: 0 deg; Versatz: 0 m
Bemaßungen - Breite auf Seite 1: 0.0175 m; Breite auf Seite 2: 0.0175 m
ID-Daten - Typname: 30 x195
Konstruktion - Dicke: 0.195 m; Eckpfosten: no; Position: Lotrecht zur Fläche; Profil: Systempfostenprofil: Rechteck
Sonstige - Kategorie: Fassadenpfosten; Familienname: Rechteckiger Pfosten
Pset_MemberCommon - IsExternal: no

# IfcMemberType, no part of this type: Rechteckiger Pfosten:30 x195
PredefinedType: MULLION; Material: <Unnamed>, Kunststoff - grau 70-70-70
Abhängigkeiten - Winkel: 0 deg; Versatz: 0 m
Bemaßungen - Breite auf Seite 1: 0.0175 m; Breite auf Seite 2: 0.0175 m
ID-Daten - Typname: 30 x195
Konstruktion - Dicke: 0.195 m; Eckpfosten: no; Position: Lotrecht zur Fläche; Profil: Systempfostenprofil: Rechteck
Sonstige - Kategorie: Fassadenpfosten; Familienname: Rechteckiger Pfosten
Pset_MemberCommon - IsExternal: no

# IfcMemberType, no part of this type: Rechteckiger Pfosten:30 x195
PredefinedType: MULLION; Material: <Unnamed>, Kunststoff - grau 70-70-70
Abhängigkeiten - Winkel: 0 deg; Versatz: 0 m
Bemaßungen - Breite auf Seite 1: 0.0175 m; Breite auf Seite 2: 0.0175 m
ID-Daten - Typname: 30 x195
Konstruktion - Dicke: 0.195 m; Eckpfosten: no; Position: Lotrecht zur Fläche; Profil: Systempfostenprofil: Rechteck
Sonstige - Kategorie: Fassadenpfosten; Familienname: Rechteckiger Pfosten
Pset_MemberCommon - IsExternal: no

# IfcMemberType, no part of this type: Rechteckiger Pfosten:30 x195
PredefinedType: MULLION; Material: <Unnamed>, Kunststoff - grau 70-70-70
Abhängigkeiten - Winkel: 0 deg; Versatz: 0 m
Bemaßungen - Breite auf Seite 1: 0.0175 m; Breite auf Seite 2: 0.0175 m
ID-Daten - Typname: 30 x195
Konstruktion - Dicke: 0.195 m; Eckpfosten: no; Position: Lotrecht zur Fläche; Profil: Systempfostenprofil: Rechteck
Sonstige - Kategorie: Fassadenpfosten; Familienname: Rechteckiger Pfosten
Pset_MemberCommon - IsExternal: no

# IfcMemberType, no part of this type: Rechteckiger Pfosten:30 x195
PredefinedType: MULLION; Material: <Unnamed>, Kunststoff - grau 70-70-70
Abhängigkeiten - Winkel: 0 deg; Versatz: 0 m
Bemaßungen - Breite auf Seite 1: 0.0175 m; Breite auf Seite 2: 0.0175 m
ID-Daten - Typname: 30 x195
Konstruktion - Dicke: 0.195 m; Eckpfosten: no; Position: Lotrecht zur Fläche; Profil: Systempfostenprofil: Rechteck
Sonstige - Kategorie: Fassadenpfosten; Familienname: Rechteckiger Pfosten
Pset_MemberCommon - IsExternal: no

# IfcMemberType, no part of this type: Rechteckiger Pfosten:30 x195
PredefinedType: MULLION; Material: <Unnamed>, Kunststoff - grau 70-70-70
Abhängigkeiten - Winkel: 0 deg; Versatz: 0 m
Bemaßungen - Breite auf Seite 1: 0.0175 m; Breite auf Seite 2: 0.0175 m
ID-Daten - Typname: 30 x195
Konstruktion - Dicke: 0.195 m; Eckpfosten: no; Position: Lotrecht zur Fläche; Profil: Systempfostenprofil: Rechteck
Sonstige - Kategorie: Fassadenpfosten; Familienname: Rechteckiger Pfosten
Pset_MemberCommon - IsExternal: no

# IfcPipeSegmentType, no part of this type: Rinne:Dachrinne 150 x 100:4041
ElementType: Rinne:Dachrinne 150 x 100:4041; PredefinedType: GUTTER

# IfcSlabType, no part of this type: Basisdach:Blechdach 250 Blei
PredefinedType: ROOF
Analytische Eigenschaften - Rauigkeit: 1; Absorptionsgrad: 0.1; Thermischer Widerstand (R): 6.14122; Thermisch wirksame Masse: 38.5153; Wärmedurchgangskoeffizient (U): 0.162834 kg/K/s3
Grafiken - Füllmuster für groben Maßstab: <Flächenfüllung>; Farbfüllung für groben Maßstab: 0
ID-Daten - Typenkommentare: Blechdach; Typname: Blechdach 250 Blei
Konstruktion - Standarddicke: 0.25 m
Sonstige - Kategorie: Dächer; Familienname: Basisdach
Pset_SlabCommon - IsExternal: yes; ThermalTransmittance: 0.162834 kg/K/s3

# IfcSlabType, no part of this type: Einzelfundament:STB 1800 x 1800 x 700
PredefinedType: BASESLAB
Bemaßungen - Breite: 1.8 m; bx: 1.8 m; by: 1.8 m; Fundamentstärke: 0.7 m; h: 0.7 m; Höhe: 0.7 m; Länge: 1.8 m
ID-Daten - Beschreibung: StB-Einzelfundament; Typenkommentare: L/B/H=180/180/70cm; Typname: STB 1800 x 1800 x 700
Sonstige - Kategorie: Fundamente; Familienname: Einzelfundament
Pset_SlabCommon - IsExternal: no

# IfcSlabType, no part of this type: Einzelfundament:STB 1800 x 1800 x 700
PredefinedType: BASESLAB
Bemaßungen - Breite: 1.8 m; bx: 1.8 m; by: 1.8 m; Fundamentstärke: 0.7 m; h: 0.7 m; Höhe: 0.7 m; Länge: 1.8 m
ID-Daten - Beschreibung: StB-Einzelfundament; Typenkommentare: L/B/H=180/180/70cm; Typname: STB 1800 x 1800 x 700
Sonstige - Kategorie: Fundamente; Familienname: Einzelfundament
Pset_SlabCommon - IsExternal: no

# IfcSlabType, no part of this type: Geschossdecke:150 Marble black
PredefinedType: FLOOR; Material: Fußboden - Granit black 300x600 0.15 m, Fußboden - Estrich 0.1 m
Analytische Eigenschaften - Rauigkeit: 1; Absorptionsgrad: 0.1
Grafiken - Füllmuster für groben Maßstab: <Flächenfüllung>; Farbfüllung für groben Maßstab: 32768
ID-Daten - Bauelement: 50.A9; Beschreibung: 150 Marble Screed; Typname: 150 Marble black
Konstruktion - Funktion: Innen; Standarddicke: 0.25 m
Sonstige - Kategorie: Geschossdecken; Familienname: Geschossdecke
Tragwerk - Filter Tragend / Nichttragend: yes
Pset_SlabCommon - IsExternal: no

# IfcSlabType, no part of this type: Geschossdecke:150 Marble black square
PredefinedType: FLOOR; Material: Fußboden - Granit black 300x300 0.15 m, Fußboden - Estrich 0.1 m
Analytische Eigenschaften - Rauigkeit: 1; Absorptionsgrad: 0.1
Grafiken - Füllmuster für groben Maßstab: <Flächenfüllung>; Farbfüllung für groben Maßstab: 32768
ID-Daten - Bauelement: 50.A9; Beschreibung: 150 Marble Screed; Typname: 150 Marble black square
Konstruktion - Funktion: Innen; Standarddicke: 0.25 m
Sonstige - Kategorie: Geschossdecken; Familienname: Geschossdecke
Tragwerk - Filter Tragend / Nichttragend: yes
Pset_SlabCommon - IsExternal: no

# IfcSlabType, no part of this type: Geschossdecke:150 Marble white
PredefinedType: FLOOR; Material: Fußboden - Granit white 300x600 0.15 m, Fußboden - Estrich 0.1 m
Analytische Eigenschaften - Rauigkeit: 1; Absorptionsgrad: 0.1
Grafiken - Füllmuster für groben Maßstab: <Flächenfüllung>; Farbfüllung für groben Maßstab: 32768
ID-Daten - Bauelement: 50.A9; Beschreibung: 150 Marble Screed; Typname: 150 Marble white
Konstruktion - Funktion: Innen; Standarddicke: 0.25 m
Sonstige - Kategorie: Geschossdecken; Familienname: Geschossdecke
Tragwerk - Filter Tragend / Nichttragend: yes
Pset_SlabCommon - IsExternal: no

# IfcSlabType, no part of this type: Geschossdecke:150 Marble white
PredefinedType: FLOOR; Material: Fußboden - Granit white 300x600 0.15 m, Fußboden - Estrich 0.1 m
Analytische Eigenschaften - Rauigkeit: 1; Absorptionsgrad: 0.1
Grafiken - Füllmuster für groben Maßstab: <Flächenfüllung>; Farbfüllung für groben Maßstab: 32768
ID-Daten - Bauelement: 50.A9; Beschreibung: 150 Marble Screed; Typname: 150 Marble white
Konstruktion - Funktion: Innen; Standarddicke: 0.25 m
Sonstige - Kategorie: Geschossdecken; Familienname: Geschossdecke
Tragwerk - Filter Tragend / Nichttragend: yes
Pset_SlabCommon - IsExternal: no

# IfcSlabType, no part of this type: Geschossdecke:150 Marble white
PredefinedType: FLOOR; Material: Fußboden - Granit white 300x600 0.15 m, Fußboden - Estrich 0.1 m
Analytische Eigenschaften - Rauigkeit: 1; Absorptionsgrad: 0.1
Grafiken - Füllmuster für groben Maßstab: <Flächenfüllung>; Farbfüllung für groben Maßstab: 32768
ID-Daten - Bauelement: 50.A9; Beschreibung: 150 Marble Screed; Typname: 150 Marble white
Konstruktion - Funktion: Innen; Standarddicke: 0.25 m
Sonstige - Kategorie: Geschossdecken; Familienname: Geschossdecke
Tragwerk - Filter Tragend / Nichttragend: yes
Pset_SlabCommon - IsExternal: no

# IfcSlabType, no part of this type: Geschossdecke:150 Marble white
PredefinedType: FLOOR; Material: Fußboden - Granit white 300x600 0.15 m, Fußboden - Estrich 0.1 m
Analytische Eigenschaften - Rauigkeit: 1; Absorptionsgrad: 0.1
Grafiken - Füllmuster für groben Maßstab: <Flächenfüllung>; Farbfüllung für groben Maßstab: 32768
ID-Daten - Bauelement: 50.A9; Beschreibung: 150 Marble Screed; Typname: 150 Marble white
Konstruktion - Funktion: Innen; Standarddicke: 0.25 m
Sonstige - Kategorie: Geschossdecken; Familienname: Geschossdecke
Tragwerk - Filter Tragend / Nichttragend: yes
Pset_SlabCommon - IsExternal: no

# IfcSlabType, no part of this type: Geschossdecke:150 Marble white
PredefinedType: FLOOR; Material: Fußboden - Granit white 300x600 0.15 m, Fußboden - Estrich 0.1 m
Analytische Eigenschaften - Rauigkeit: 1; Absorptionsgrad: 0.1
Grafiken - Füllmuster für groben Maßstab: <Flächenfüllung>; Farbfüllung für groben Maßstab: 32768
ID-Daten - Bauelement: 50.A9; Beschreibung: 150 Marble Screed; Typname: 150 Marble white
Konstruktion - Funktion: Innen; Standarddicke: 0.25 m
Sonstige - Kategorie: Geschossdecken; Familienname: Geschossdecke
Tragwerk - Filter Tragend / Nichttragend: yes
Pset_SlabCommon - IsExternal: no

# IfcSlabType, no part of this type: Geschossdecke:150 Marble white
PredefinedType: FLOOR; Material: Fußboden - Granit white 300x600 0.15 m, Fußboden - Estrich 0.1 m
Analytische Eigenschaften - Rauigkeit: 1; Absorptionsgrad: 0.1
Grafiken - Füllmuster für groben Maßstab: <Flächenfüllung>; Farbfüllung für groben Maßstab: 32768
ID-Daten - Bauelement: 50.A9; Beschreibung: 150 Marble Screed; Typname: 150 Marble white
Konstruktion - Funktion: Innen; Standarddicke: 0.25 m
Sonstige - Kategorie: Geschossdecken; Familienname: Geschossdecke
Tragwerk - Filter Tragend / Nichttragend: yes
Pset_SlabCommon - IsExternal: no

# IfcSlabType, no part of this type: Geschossdecke:150 Marble white
PredefinedType: FLOOR; Material: Fußboden - Granit white 300x600 0.15 m, Fußboden - Estrich 0.1 m
Analytische Eigenschaften - Rauigkeit: 1; Absorptionsgrad: 0.1
Grafiken - Füllmuster für groben Maßstab: <Flächenfüllung>; Farbfüllung für groben Maßstab: 32768
ID-Daten - Bauelement: 50.A9; Beschreibung: 150 Marble Screed; Typname: 150 Marble white
Konstruktion - Funktion: Innen; Standarddicke: 0.25 m
Sonstige - Kategorie: Geschossdecken; Familienname: Geschossdecke
Tragwerk - Filter Tragend / Nichttragend: yes
Pset_SlabCommon - IsExternal: no

# IfcSlabType, no part of this type: Geschossdecke:150 Marble white
PredefinedType: FLOOR; Material: Fußboden - Granit white 300x600 0.15 m, Fußboden - Estrich 0.1 m
Analytische Eigenschaften - Rauigkeit: 1; Absorptionsgrad: 0.1
Grafiken - Füllmuster für groben Maßstab: <Flächenfüllung>; Farbfüllung für groben Maßstab: 32768
ID-Daten - Bauelement: 50.A9; Beschreibung: 150 Marble Screed; Typname: 150 Marble white
Konstruktion - Funktion: Innen; Standarddicke: 0.25 m
Sonstige - Kategorie: Geschossdecken; Familienname: Geschossdecke
Tragwerk - Filter Tragend / Nichttragend: yes
Pset_SlabCommon - IsExternal: no

# IfcSlabType, no part of this type: Geschossdecke:150 Marble white
PredefinedType: FLOOR; Material: Fußboden - Granit white 300x600 0.15 m, Fußboden - Estrich 0.1 m
Analytische Eigenschaften - Rauigkeit: 1; Absorptionsgrad: 0.1
Grafiken - Füllmuster für groben Maßstab: <Flächenfüllung>; Farbfüllung für groben Maßstab: 32768
ID-Daten - Bauelement: 50.A9; Beschreibung: 150 Marble Screed; Typname: 150 Marble white
Konstruktion - Funktion: Innen; Standarddicke: 0.25 m
Sonstige - Kategorie: Geschossdecken; Familienname: Geschossdecke
Tragwerk - Filter Tragend / Nichttragend: yes
Pset_SlabCommon - IsExternal: no

# IfcSlabType, no part of this type: Geschossdecke:150 Marble white
PredefinedType: FLOOR; Material: Fußboden - Granit white 300x600 0.15 m, Fußboden - Estrich 0.1 m
Analytische Eigenschaften - Rauigkeit: 1; Absorptionsgrad: 0.1
Grafiken - Füllmuster für groben Maßstab: <Flächenfüllung>; Farbfüllung für groben Maßstab: 32768
ID-Daten - Bauelement: 50.A9; Beschreibung: 150 Marble Screed; Typname: 150 Marble white
Konstruktion - Funktion: Innen; Standarddicke: 0.25 m
Sonstige - Kategorie: Geschossdecken; Familienname: Geschossdecke
Tragwerk - Filter Tragend / Nichttragend: yes
Pset_SlabCommon - IsExternal: no

# IfcSlabType, no part of this type: Geschossdecke:Beton 200 on Fill
PredefinedType: FLOOR; Material: Ortbeton - bewehrt 0.2 m, Fußboden - Schüttung 0.725 m
Analytische Eigenschaften - Rauigkeit: 1; Absorptionsgrad: 0.1; Thermischer Widerstand (R): 2.20509; Thermisch wirksame Masse: 1422.78; Wärmedurchgangskoeffizient (U): 0.453496 kg/K/s3
Grafiken - Füllmuster für groben Maßstab: <Flächenfüllung>; Farbfüllung für groben Maßstab: 32768
ID-Daten - Bauelement: 50.A9; Typname: Beton 200 on Fill
Konstruktion - Funktion: Innen; Standarddicke: 0.925 m
Sonstige - Kategorie: Geschossdecken; Familienname: Geschossdecke
Tragwerk - Filter Tragend / Nichttragend: yes
Pset_SlabCommon - IsExternal: no; ThermalTransmittance: 0.453496 kg/K/s3

# IfcSlabType, no part of this type: Geschossdecke:Beton 200 on Fill
PredefinedType: FLOOR; Material: Ortbeton - bewehrt 0.2 m, Fußboden - Schüttung 0.725 m
Analytische Eigenschaften - Rauigkeit: 1; Absorptionsgrad: 0.1; Thermischer Widerstand (R): 2.20509; Thermisch wirksame Masse: 1422.78; Wärmedurchgangskoeffizient (U): 0.453496 kg/K/s3
Grafiken - Füllmuster für groben Maßstab: <Flächenfüllung>; Farbfüllung für groben Maßstab: 32768
ID-Daten - Bauelement: 50.A9; Typname: Beton 200 on Fill
Konstruktion - Funktion: Innen; Standarddicke: 0.925 m
Sonstige - Kategorie: Geschossdecken; Familienname: Geschossdecke
Tragwerk - Filter Tragend / Nichttragend: yes
Pset_SlabCommon - IsExternal: no; ThermalTransmittance: 0.453496 kg/K/s3

# IfcSlabType, no part of this type: Geschossdecke:Beton 200 on Fill Octagon
PredefinedType: FLOOR; Material: Ortbeton - bewehrt 0.2 m, Fußboden - Schüttung 0.685 m
Analytische Eigenschaften - Rauigkeit: 1; Absorptionsgrad: 0.1; Thermischer Widerstand (R): 2.09398; Thermisch wirksame Masse: 1360.96; Wärmedurchgangskoeffizient (U): 0.477559 kg/K/s3
Grafiken - Füllmuster für groben Maßstab: <Flächenfüllung>; Farbfüllung für groben Maßstab: 32768
ID-Daten - Bauelement: 50.A9; Typname: Beton 200 on Fill Octagon
Konstruktion - Funktion: Innen; Standarddicke: 0.885 m
Sonstige - Kategorie: Geschossdecken; Familienname: Geschossdecke
Tragwerk - Filter Tragend / Nichttragend: yes
Pset_SlabCommon - IsExternal: no; ThermalTransmittance: 0.477559 kg/K/s3

# IfcSlabType, no part of this type: Geschossdecke:Boden 3370 Soil Stage 0
PredefinedType: FLOOR; Material: Fußboden - Schüttung 0.37 m, Fußboden - Schüttung Subsoil 3 m
Analytische Eigenschaften - Rauigkeit: 1; Absorptionsgrad: 0.1; Thermischer Widerstand (R): 9.36111; Thermisch wirksame Masse: 5208.67; Wärmedurchgangskoeffizient (U): 0.106825 kg/K/s3
Grafiken - Füllmuster für groben Maßstab: <Flächenfüllung>; Farbfüllung für groben Maßstab: 32768
ID-Daten - Beschreibung: STB_350; Typname: Boden 3370 Soil Stage 0
Konstruktion - Funktion: Außen; Standarddicke: 3.37 m
Materialien und Oberflächen - Tragendes Material: Fußboden - Schüttung
Sonstige - Kategorie: Geschossdecken; Familienname: Geschossdecke
Tragwerk - Filter Tragend / Nichttragend: yes
Pset_SlabCommon - IsExternal: yes; ThermalTransmittance: 0.106825 kg/K/s3

# IfcSlabType, no part of this type: Geschossdecke:Boden 3370 Soil Stage 0
PredefinedType: FLOOR; Material: Fußboden - Schüttung 0.37 m, Fußboden - Schüttung Subsoil 3 m
Analytische Eigenschaften - Rauigkeit: 1; Absorptionsgrad: 0.1; Thermischer Widerstand (R): 9.36111; Thermisch wirksame Masse: 5208.67; Wärmedurchgangskoeffizient (U): 0.106825 kg/K/s3
Grafiken - Füllmuster für groben Maßstab: <Flächenfüllung>; Farbfüllung für groben Maßstab: 32768
ID-Daten - Beschreibung: STB_350; Typname: Boden 3370 Soil Stage 0
Konstruktion - Funktion: Außen; Standarddicke: 3.37 m
Materialien und Oberflächen - Tragendes Material: Fußboden - Schüttung
Sonstige - Kategorie: Geschossdecken; Familienname: Geschossdecke
Tragwerk - Filter Tragend / Nichttragend: yes
Pset_SlabCommon - IsExternal: yes; ThermalTransmittance: 0.106825 kg/K/s3

# IfcSlabType, no part of this type: Geschossdecke:Boden 3370 Soil Stage 0
PredefinedType: FLOOR; Material: Fußboden - Schüttung 0.37 m, Fußboden - Schüttung Subsoil 3 m
Analytische Eigenschaften - Rauigkeit: 1; Absorptionsgrad: 0.1; Thermischer Widerstand (R): 9.36111; Thermisch wirksame Masse: 5208.67; Wärmedurchgangskoeffizient (U): 0.106825 kg/K/s3
Grafiken - Füllmuster für groben Maßstab: <Flächenfüllung>; Farbfüllung für groben Maßstab: 32768
ID-Daten - Beschreibung: STB_350; Typname: Boden 3370 Soil Stage 0
Konstruktion - Funktion: Außen; Standarddicke: 3.37 m
Materialien und Oberflächen - Tragendes Material: Fußboden - Schüttung
Sonstige - Kategorie: Geschossdecken; Familienname: Geschossdecke
Tragwerk - Filter Tragend / Nichttragend: yes
Pset_SlabCommon - IsExternal: yes; ThermalTransmittance: 0.106825 kg/K/s3

# IfcSlabType, no part of this type: Geschossdecke:Boden 3370 Soil Stage 0
PredefinedType: FLOOR; Material: Fußboden - Schüttung 0.37 m, Fußboden - Schüttung Subsoil 3 m
Analytische Eigenschaften - Rauigkeit: 1; Absorptionsgrad: 0.1; Thermischer Widerstand (R): 9.36111; Thermisch wirksame Masse: 5208.67; Wärmedurchgangskoeffizient (U): 0.106825 kg/K/s3
Grafiken - Füllmuster für groben Maßstab: <Flächenfüllung>; Farbfüllung für groben Maßstab: 32768
ID-Daten - Beschreibung: STB_350; Typname: Boden 3370 Soil Stage 0
Konstruktion - Funktion: Außen; Standarddicke: 3.37 m
Materialien und Oberflächen - Tragendes Material: Fußboden - Schüttung
Sonstige - Kategorie: Geschossdecken; Familienname: Geschossdecke
Tragwerk - Filter Tragend / Nichttragend: yes
Pset_SlabCommon - IsExternal: yes; ThermalTransmittance: 0.106825 kg/K/s3

# IfcSlabType, no part of this type: Geschossdecke:Fill 3400 Subfill
PredefinedType: FLOOR; Material: Fußboden - Schüttung Subsoil 3.4 m
Analytische Eigenschaften - Rauigkeit: 1; Absorptionsgrad: 0.1; Thermischer Widerstand (R): 9.44444; Thermisch wirksame Masse: 5255.04; Wärmedurchgangskoeffizient (U): 0.105882 kg/K/s3
Grafiken - Füllmuster für groben Maßstab: <Flächenfüllung>; Farbfüllung für groben Maßstab: 32768
ID-Daten - Beschreibung: STB_350; Typname: Fill 3400 Subfill
Konstruktion - Funktion: Außen; Standarddicke: 3.4 m
Sonstige - Kategorie: Geschossdecken; Familienname: Geschossdecke
Tragwerk - Filter Tragend / Nichttragend: yes
Pset_SlabCommon - IsExternal: yes; ThermalTransmittance: 0.105882 kg/K/s3

# IfcSlabType, no part of this type: Geschossdecke:Fill 3400 Subfill
PredefinedType: FLOOR; Material: Fußboden - Schüttung Subsoil 3.4 m
Analytische Eigenschaften - Rauigkeit: 1; Absorptionsgrad: 0.1; Thermischer Widerstand (R): 9.44444; Thermisch wirksame Masse: 5255.04; Wärmedurchgangskoeffizient (U): 0.105882 kg/K/s3
Grafiken - Füllmuster für groben Maßstab: <Flächenfüllung>; Farbfüllung für groben Maßstab: 32768
ID-Daten - Beschreibung: STB_350; Typname: Fill 3400 Subfill
Konstruktion - Funktion: Außen; Standarddicke: 3.4 m
Sonstige - Kategorie: Geschossdecken; Familienname: Geschossdecke
Tragwerk - Filter Tragend / Nichttragend: yes
Pset_SlabCommon - IsExternal: yes; ThermalTransmittance: 0.105882 kg/K/s3

# IfcSlabType, no part of this type: Geschossdecke:Fill 3400 Subfill
PredefinedType: FLOOR; Material: Fußboden - Schüttung Subsoil 3.4 m
Analytische Eigenschaften - Rauigkeit: 1; Absorptionsgrad: 0.1; Thermischer Widerstand (R): 9.44444; Thermisch wirksame Masse: 5255.04; Wärmedurchgangskoeffizient (U): 0.105882 kg/K/s3
Grafiken - Füllmuster für groben Maßstab: <Flächenfüllung>; Farbfüllung für groben Maßstab: 32768
ID-Daten - Beschreibung: STB_350; Typname: Fill 3400 Subfill
Konstruktion - Funktion: Außen; Standarddicke: 3.4 m
Sonstige - Kategorie: Geschossdecken; Familienname: Geschossdecke
Tragwerk - Filter Tragend / Nichttragend: yes
Pset_SlabCommon - IsExternal: yes; ThermalTransmittance: 0.105882 kg/K/s3

# IfcSlabType, no part of this type: Geschossdecke:Fill 400 Fill
PredefinedType: FLOOR; Material: Fußboden - Schüttung Subfill 0.4 m
Analytische Eigenschaften - Rauigkeit: 1; Absorptionsgrad: 0.1; Thermischer Widerstand (R): 1.11111; Thermisch wirksame Masse: 618.24; Wärmedurchgangskoeffizient (U): 0.9 kg/K/s3
Grafiken - Füllmuster für groben Maßstab: <Flächenfüllung>; Farbfüllung für groben Maßstab: 32768
ID-Daten - Beschreibung: STB_350; Typname: Fill 400 Fill
Konstruktion - Funktion: Außen; Standarddicke: 0.4 m
Sonstige - Kategorie: Geschossdecken; Familienname: Geschossdecke
Tragwerk - Filter Tragend / Nichttragend: yes
Pset_SlabCommon - IsExternal: yes; ThermalTransmittance: 0.9 kg/K/s3

# IfcSlabType, no part of this type: Geschossdecke:Fill 400 Fill
PredefinedType: FLOOR; Material: Fußboden - Schüttung Subfill 0.4 m
Analytische Eigenschaften - Rauigkeit: 1; Absorptionsgrad: 0.1; Thermischer Widerstand (R): 1.11111; Thermisch wirksame Masse: 618.24; Wärmedurchgangskoeffizient (U): 0.9 kg/K/s3
Grafiken - Füllmuster für groben Maßstab: <Flächenfüllung>; Farbfüllung für groben Maßstab: 32768
ID-Daten - Beschreibung: STB_350; Typname: Fill 400 Fill
Konstruktion - Funktion: Außen; Standarddicke: 0.4 m
Sonstige - Kategorie: Geschossdecken; Familienname: Geschossdecke
Tragwerk - Filter Tragend / Nichttragend: yes
Pset_SlabCommon - IsExternal: yes; ThermalTransmittance: 0.9 kg/K/s3

# IfcSlabType, no part of this type: Geschossdecke:Fill 450
PredefinedType: FLOOR; Material: Fußboden - Schüttung 0.45 m
Analytische Eigenschaften - Rauigkeit: 1; Absorptionsgrad: 0.1; Thermischer Widerstand (R): 1.25; Thermisch wirksame Masse: 695.52; Wärmedurchgangskoeffizient (U): 0.8 kg/K/s3
Grafiken - Füllmuster für groben Maßstab: <Flächenfüllung>; Farbfüllung für groben Maßstab: 32768
ID-Daten - Beschreibung: STB_350; Typname: Fill 450
Konstruktion - Funktion: Außen; Standarddicke: 0.45 m
Sonstige - Kategorie: Geschossdecken; Familienname: Geschossdecke
Tragwerk - Filter Tragend / Nichttragend: yes
Pset_SlabCommon - IsExternal: yes; ThermalTransmittance: 0.8 kg/K/s3

# IfcSlabType, no part of this type: Geschossdecke:Floor fill 500
PredefinedType: FLOOR; Material: Fußboden - Schüttung 0.5 m
Analytische Eigenschaften - Rauigkeit: 1; Absorptionsgrad: 0.1; Thermischer Widerstand (R): 1.38889; Thermisch wirksame Masse: 772.8; Wärmedurchgangskoeffizient (U): 0.72 kg/K/s3
Grafiken - Füllmuster für groben Maßstab: <Flächenfüllung>; Farbfüllung für groben Maßstab: 32768
ID-Daten - Bauelement: 50.A9; Typname: Floor fill 500
Konstruktion - Funktion: Innen; Standarddicke: 0.5 m
Sonstige - Kategorie: Geschossdecken; Familienname: Geschossdecke
Tragwerk - Filter Tragend / Nichttragend: yes
Pset_SlabCommon - IsExternal: no; ThermalTransmittance: 0.72 kg/K/s3

# IfcSlabType, no part of this type: Geschossdecke:Marble Altar
PredefinedType: FLOOR; Material: Fußboden - Estrich 0.8 m
Analytische Eigenschaften - Rauigkeit: 1; Absorptionsgrad: 0.1
Grafiken - Füllmuster für groben Maßstab: <Flächenfüllung>; Farbfüllung für groben Maßstab: 32768
ID-Daten - Bauelement: 50.A9; Beschreibung: STB_200; Typname: Marble Altar
Konstruktion - Funktion: Innen; Standarddicke: 0.8 m
Sonstige - Kategorie: Geschossdecken; Familienname: Geschossdecke
Tragwerk - Filter Tragend / Nichttragend: yes
Pset_SlabCommon - IsExternal: no

# IfcSlabType, no part of this type: Geschossdecke:NS 100
PredefinedType: FLOOR; Material: Ortbeton - bewehrt 0.1 m
Analytische Eigenschaften - Rauigkeit: 1; Absorptionsgrad: 0.1; Thermischer Widerstand (R): 0.0956023; Thermisch wirksame Masse: 151.11; Wärmedurchgangskoeffizient (U): 10.46 kg/K/s3
Grafiken - Füllmuster für groben Maßstab: <Flächenfüllung>; Farbfüllung für groben Maßstab: 32768
ID-Daten - Bauelement: 50.A9; Beschreibung: STB_200; Typname: NS 100
Konstruktion - Funktion: Außen; Standarddicke: 0.1 m
Materialien und Oberflächen - Tragendes Material: Ortbeton - bewehrt
Sonstige - Kategorie: Geschossdecken; Familienname: Geschossdecke
Tragwerk - Filter Tragend / Nichttragend: yes
Pset_SlabCommon - IsExternal: yes; ThermalTransmittance: 10.46 kg/K/s3

# IfcSlabType, no part of this type: Geschossdecke:NS 100
PredefinedType: FLOOR; Material: Ortbeton - bewehrt 0.1 m
Analytische Eigenschaften - Rauigkeit: 1; Absorptionsgrad: 0.1; Thermischer Widerstand (R): 0.0956023; Thermisch wirksame Masse: 151.11; Wärmedurchgangskoeffizient (U): 10.46 kg/K/s3
Grafiken - Füllmuster für groben Maßstab: <Flächenfüllung>; Farbfüllung für groben Maßstab: 32768
ID-Daten - Bauelement: 50.A9; Beschreibung: STB_200; Typname: NS 100
Konstruktion - Funktion: Außen; Standarddicke: 0.1 m
Materialien und Oberflächen - Tragendes Material: Ortbeton - bewehrt
Sonstige - Kategorie: Geschossdecken; Familienname: Geschossdecke
Tragwerk - Filter Tragend / Nichttragend: yes
Pset_SlabCommon - IsExternal: yes; ThermalTransmittance: 10.46 kg/K/s3

# IfcSlabType, no part of this type: Geschossdecke:NS 100
PredefinedType: FLOOR; Material: Ortbeton - bewehrt 0.1 m
Analytische Eigenschaften - Rauigkeit: 1; Absorptionsgrad: 0.1; Thermischer Widerstand (R): 0.0956023; Thermisch wirksame Masse: 151.11; Wärmedurchgangskoeffizient (U): 10.46 kg/K/s3
Grafiken - Füllmuster für groben Maßstab: <Flächenfüllung>; Farbfüllung für groben Maßstab: 32768
ID-Daten - Bauelement: 50.A9; Beschreibung: STB_200; Typname: NS 100
Konstruktion - Funktion: Außen; Standarddicke: 0.1 m
Materialien und Oberflächen - Tragendes Material: Ortbeton - bewehrt
Sonstige - Kategorie: Geschossdecken; Familienname: Geschossdecke
Tragwerk - Filter Tragend / Nichttragend: yes
Pset_SlabCommon - IsExternal: yes; ThermalTransmittance: 10.46 kg/K/s3

# IfcSlabType, no part of this type: Geschossdecke:NS 100
PredefinedType: FLOOR; Material: Ortbeton - bewehrt 0.1 m
Analytische Eigenschaften - Rauigkeit: 1; Absorptionsgrad: 0.1; Thermischer Widerstand (R): 0.0956023; Thermisch wirksame Masse: 151.11; Wärmedurchgangskoeffizient (U): 10.46 kg/K/s3
Grafiken - Füllmuster für groben Maßstab: <Flächenfüllung>; Farbfüllung für groben Maßstab: 32768
ID-Daten - Bauelement: 50.A9; Beschreibung: STB_200; Typname: NS 100
Konstruktion - Funktion: Außen; Standarddicke: 0.1 m
Materialien und Oberflächen - Tragendes Material: Ortbeton - bewehrt
Sonstige - Kategorie: Geschossdecken; Familienname: Geschossdecke
Tragwerk - Filter Tragend / Nichttragend: yes
Pset_SlabCommon - IsExternal: yes; ThermalTransmittance: 10.46 kg/K/s3

# IfcSlabType, no part of this type: Geschossdecke:NS 100
PredefinedType: FLOOR; Material: Ortbeton - bewehrt 0.1 m
Analytische Eigenschaften - Rauigkeit: 1; Absorptionsgrad: 0.1; Thermischer Widerstand (R): 0.0956023; Thermisch wirksame Masse: 151.11; Wärmedurchgangskoeffizient (U): 10.46 kg/K/s3
Grafiken - Füllmuster für groben Maßstab: <Flächenfüllung>; Farbfüllung für groben Maßstab: 32768
ID-Daten - Bauelement: 50.A9; Beschreibung: STB_200; Typname: NS 100
Konstruktion - Funktion: Außen; Standarddicke: 0.1 m
Materialien und Oberflächen - Tragendes Material: Ortbeton - bewehrt
Sonstige - Kategorie: Geschossdecken; Familienname: Geschossdecke
Tragwerk - Filter Tragend / Nichttragend: yes
Pset_SlabCommon - IsExternal: yes; ThermalTransmittance: 10.46 kg/K/s3

# IfcSlabType, no part of this type: Geschossdecke:NS 140
PredefinedType: FLOOR; Material: Ortbeton - bewehrt 0.14 m
Analytische Eigenschaften - Rauigkeit: 1; Absorptionsgrad: 0.1; Thermischer Widerstand (R): 0.133843; Thermisch wirksame Masse: 211.554; Wärmedurchgangskoeffizient (U): 7.47143 kg/K/s3
Grafiken - Füllmuster für groben Maßstab: <Flächenfüllung>; Farbfüllung für groben Maßstab: 32768
ID-Daten - Bauelement: 50.A9; Beschreibung: STB_200; Typname: NS 140
Konstruktion - Funktion: Außen; Standarddicke: 0.14 m
Materialien und Oberflächen - Tragendes Material: Ortbeton - bewehrt
Sonstige - Kategorie: Geschossdecken; Familienname: Geschossdecke
Tragwerk - Filter Tragend / Nichttragend: yes
Pset_SlabCommon - IsExternal: yes; ThermalTransmittance: 7.47143 kg/K/s3

# IfcSlabType, no part of this type: Geschossdecke:NS 140
PredefinedType: FLOOR; Material: Ortbeton - bewehrt 0.14 m
Analytische Eigenschaften - Rauigkeit: 1; Absorptionsgrad: 0.1; Thermischer Widerstand (R): 0.133843; Thermisch wirksame Masse: 211.554; Wärmedurchgangskoeffizient (U): 7.47143 kg/K/s3
Grafiken - Füllmuster für groben Maßstab: <Flächenfüllung>; Farbfüllung für groben Maßstab: 32768
ID-Daten - Bauelement: 50.A9; Beschreibung: STB_200; Typname: NS 140
Konstruktion - Funktion: Außen; Standarddicke: 0.14 m
Materialien und Oberflächen - Tragendes Material: Ortbeton - bewehrt
Sonstige - Kategorie: Geschossdecken; Familienname: Geschossdecke
Tragwerk - Filter Tragend / Nichttragend: yes
Pset_SlabCommon - IsExternal: yes; ThermalTransmittance: 7.47143 kg/K/s3

# IfcSlabType, no part of this type: Geschossdecke:NS 140
PredefinedType: FLOOR; Material: Ortbeton - bewehrt 0.14 m
Analytische Eigenschaften - Rauigkeit: 1; Absorptionsgrad: 0.1; Thermischer Widerstand (R): 0.133843; Thermisch wirksame Masse: 211.554; Wärmedurchgangskoeffizient (U): 7.47143 kg/K/s3
Grafiken - Füllmuster für groben Maßstab: <Flächenfüllung>; Farbfüllung für groben Maßstab: 32768
ID-Daten - Bauelement: 50.A9; Beschreibung: STB_200; Typname: NS 140
Konstruktion - Funktion: Außen; Standarddicke: 0.14 m
Materialien und Oberflächen - Tragendes Material: Ortbeton - bewehrt
Sonstige - Kategorie: Geschossdecken; Familienname: Geschossdecke
Tragwerk - Filter Tragend / Nichttragend: yes
Pset_SlabCommon - IsExternal: yes; ThermalTransmittance: 7.47143 kg/K/s3

# IfcSlabType, no part of this type: Geschossdecke:NS 140
PredefinedType: FLOOR; Material: Ortbeton - bewehrt 0.14 m
Analytische Eigenschaften - Rauigkeit: 1; Absorptionsgrad: 0.1; Thermischer Widerstand (R): 0.133843; Thermisch wirksame Masse: 211.554; Wärmedurchgangskoeffizient (U): 7.47143 kg/K/s3
Grafiken - Füllmuster für groben Maßstab: <Flächenfüllung>; Farbfüllung für groben Maßstab: 32768
ID-Daten - Bauelement: 50.A9; Beschreibung: STB_200; Typname: NS 140
Konstruktion - Funktion: Außen; Standarddicke: 0.14 m
Materialien und Oberflächen - Tragendes Material: Ortbeton - bewehrt
Sonstige - Kategorie: Geschossdecken; Familienname: Geschossdecke
Tragwerk - Filter Tragend / Nichttragend: yes
Pset_SlabCommon - IsExternal: yes; ThermalTransmittance: 7.47143 kg/K/s3

# IfcSlabType, no part of this type: Geschossdecke:NS 150
PredefinedType: FLOOR; Material: Ortbeton - bewehrt 0.15 m
Analytische Eigenschaften - Rauigkeit: 1; Absorptionsgrad: 0.1; Thermischer Widerstand (R): 0.143403; Thermisch wirksame Masse: 226.665; Wärmedurchgangskoeffizient (U): 6.97333 kg/K/s3
Grafiken - Füllmuster für groben Maßstab: <Flächenfüllung>; Farbfüllung für groben Maßstab: 32768
ID-Daten - Bauelement: 50.A9; Beschreibung: STB_200; Typname: NS 150
Konstruktion - Funktion: Außen; Standarddicke: 0.15 m
Materialien und Oberflächen - Tragendes Material: Ortbeton - bewehrt
Sonstige - Kategorie: Geschossdecken; Familienname: Geschossdecke
Tragwerk - Filter Tragend / Nichttragend: yes
Pset_SlabCommon - IsExternal: yes; ThermalTransmittance: 6.97333 kg/K/s3

# IfcSlabType, no part of this type: Geschossdecke:NS 150
PredefinedType: FLOOR; Material: Ortbeton - bewehrt 0.15 m
Analytische Eigenschaften - Rauigkeit: 1; Absorptionsgrad: 0.1; Thermischer Widerstand (R): 0.143403; Thermisch wirksame Masse: 226.665; Wärmedurchgangskoeffizient (U): 6.97333 kg/K/s3
Grafiken - Füllmuster für groben Maßstab: <Flächenfüllung>; Farbfüllung für groben Maßstab: 32768
ID-Daten - Bauelement: 50.A9; Beschreibung: STB_200; Typname: NS 150
Konstruktion - Funktion: Außen; Standarddicke: 0.15 m
Materialien und Oberflächen - Tragendes Material: Ortbeton - bewehrt
Sonstige - Kategorie: Geschossdecken; Familienname: Geschossdecke
Tragwerk - Filter Tragend / Nichttragend: yes
Pset_SlabCommon - IsExternal: yes; ThermalTransmittance: 6.97333 kg/K/s3

# IfcSlabType, no part of this type: Geschossdecke:NS 150
PredefinedType: FLOOR; Material: Ortbeton - bewehrt 0.15 m
Analytische Eigenschaften - Rauigkeit: 1; Absorptionsgrad: 0.1; Thermischer Widerstand (R): 0.143403; Thermisch wirksame Masse: 226.665; Wärmedurchgangskoeffizient (U): 6.97333 kg/K/s3
Grafiken - Füllmuster für groben Maßstab: <Flächenfüllung>; Farbfüllung für groben Maßstab: 32768
ID-Daten - Bauelement: 50.A9; Beschreibung: STB_200; Typname: NS 150
Konstruktion - Funktion: Außen; Standarddicke: 0.15 m
Materialien und Oberflächen - Tragendes Material: Ortbeton - bewehrt
Sonstige - Kategorie: Geschossdecken; Familienname: Geschossdecke
Tragwerk - Filter Tragend / Nichttragend: yes
Pset_SlabCommon - IsExternal: yes; ThermalTransmittance: 6.97333 kg/K/s3

# IfcSlabType, no part of this type: Geschossdecke:NS 250
PredefinedType: FLOOR; Material: Ortbeton - bewehrt 0.25 m
Analytische Eigenschaften - Rauigkeit: 1; Absorptionsgrad: 0.1; Thermischer Widerstand (R): 0.239006; Thermisch wirksame Masse: 377.775; Wärmedurchgangskoeffizient (U): 4.184 kg/K/s3
Grafiken - Füllmuster für groben Maßstab: <Flächenfüllung>; Farbfüllung für groben Maßstab: 32768
ID-Daten - Bauelement: 50.A9; Beschreibung: STB_200; Typname: NS 250
Konstruktion - Funktion: Außen; Standarddicke: 0.25 m
Materialien und Oberflächen - Tragendes Material: Ortbeton - bewehrt
Sonstige - Kategorie: Geschossdecken; Familienname: Geschossdecke
Tragwerk - Filter Tragend / Nichttragend: yes
Pset_SlabCommon - IsExternal: yes; ThermalTransmittance: 4.184 kg/K/s3

# IfcSlabType, no part of this type: Geschossdecke:NS 50
PredefinedType: FLOOR; Material: Ortbeton - bewehrt 0.05 m
Analytische Eigenschaften - Rauigkeit: 1; Absorptionsgrad: 0.1; Thermischer Widerstand (R): 0.0478011; Thermisch wirksame Masse: 75.555; Wärmedurchgangskoeffizient (U): 20.92 kg/K/s3
Grafiken - Füllmuster für groben Maßstab: <Flächenfüllung>; Farbfüllung für groben Maßstab: 32768
ID-Daten - Bauelement: 50.A9; Beschreibung: STB_200; Typname: NS 50
Konstruktion - Funktion: Außen; Standarddicke: 0.05 m
Materialien und Oberflächen - Tragendes Material: Ortbeton - bewehrt
Sonstige - Kategorie: Geschossdecken; Familienname: Geschossdecke
Tragwerk - Filter Tragend / Nichttragend: yes
Pset_SlabCommon - IsExternal: yes; ThermalTransmittance: 20.92 kg/K/s3

# IfcSlabType, no part of this type: Geschossdecke:NS 50
PredefinedType: FLOOR; Material: Ortbeton - bewehrt 0.05 m
Analytische Eigenschaften - Rauigkeit: 1; Absorptionsgrad: 0.1; Thermischer Widerstand (R): 0.0478011; Thermisch wirksame Masse: 75.555; Wärmedurchgangskoeffizient (U): 20.92 kg/K/s3
Grafiken - Füllmuster für groben Maßstab: <Flächenfüllung>; Farbfüllung für groben Maßstab: 32768
ID-Daten - Bauelement: 50.A9; Beschreibung: STB_200; Typname: NS 50
Konstruktion - Funktion: Außen; Standarddicke: 0.05 m
Materialien und Oberflächen - Tragendes Material: Ortbeton - bewehrt
Sonstige - Kategorie: Geschossdecken; Familienname: Geschossdecke
Tragwerk - Filter Tragend / Nichttragend: yes
Pset_SlabCommon - IsExternal: yes; ThermalTransmittance: 20.92 kg/K/s3

# IfcSlabType, no part of this type: Geschossdecke:NS 50
PredefinedType: FLOOR; Material: Ortbeton - bewehrt 0.05 m
Analytische Eigenschaften - Rauigkeit: 1; Absorptionsgrad: 0.1; Thermischer Widerstand (R): 0.0478011; Thermisch wirksame Masse: 75.555; Wärmedurchgangskoeffizient (U): 20.92 kg/K/s3
Grafiken - Füllmuster für groben Maßstab: <Flächenfüllung>; Farbfüllung für groben Maßstab: 32768
ID-Daten - Bauelement: 50.A9; Beschreibung: STB_200; Typname: NS 50
Konstruktion - Funktion: Außen; Standarddicke: 0.05 m
Materialien und Oberflächen - Tragendes Material: Ortbeton - bewehrt
Sonstige - Kategorie: Geschossdecken; Familienname: Geschossdecke
Tragwerk - Filter Tragend / Nichttragend: yes
Pset_SlabCommon - IsExternal: yes; ThermalTransmittance: 20.92 kg/K/s3

# IfcSlabType, no part of this type: Geschossdecke:NS 50
PredefinedType: FLOOR; Material: Ortbeton - bewehrt 0.05 m
Analytische Eigenschaften - Rauigkeit: 1; Absorptionsgrad: 0.1; Thermischer Widerstand (R): 0.0478011; Thermisch wirksame Masse: 75.555; Wärmedurchgangskoeffizient (U): 20.92 kg/K/s3
Grafiken - Füllmuster für groben Maßstab: <Flächenfüllung>; Farbfüllung für groben Maßstab: 32768
ID-Daten - Bauelement: 50.A9; Beschreibung: STB_200; Typname: NS 50
Konstruktion - Funktion: Außen; Standarddicke: 0.05 m
Materialien und Oberflächen - Tragendes Material: Ortbeton - bewehrt
Sonstige - Kategorie: Geschossdecken; Familienname: Geschossdecke
Tragwerk - Filter Tragend / Nichttragend: yes
Pset_SlabCommon - IsExternal: yes; ThermalTransmittance: 20.92 kg/K/s3

# IfcSlabType, no part of this type: Geschossdecke:NS 50
PredefinedType: FLOOR; Material: Ortbeton - bewehrt 0.05 m
Analytische Eigenschaften - Rauigkeit: 1; Absorptionsgrad: 0.1; Thermischer Widerstand (R): 0.0478011; Thermisch wirksame Masse: 75.555; Wärmedurchgangskoeffizient (U): 20.92 kg/K/s3
Grafiken - Füllmuster für groben Maßstab: <Flächenfüllung>; Farbfüllung für groben Maßstab: 32768
ID-Daten - Bauelement: 50.A9; Beschreibung: STB_200; Typname: NS 50
Konstruktion - Funktion: Außen; Standarddicke: 0.05 m
Materialien und Oberflächen - Tragendes Material: Ortbeton - bewehrt
Sonstige - Kategorie: Geschossdecken; Familienname: Geschossdecke
Tragwerk - Filter Tragend / Nichttragend: yes
Pset_SlabCommon - IsExternal: yes; ThermalTransmittance: 20.92 kg/K/s3

# IfcSlabType, no part of this type: Geschossdecke:NS 50
PredefinedType: FLOOR; Material: Ortbeton - bewehrt 0.05 m
Analytische Eigenschaften - Rauigkeit: 1; Absorptionsgrad: 0.1; Thermischer Widerstand (R): 0.0478011; Thermisch wirksame Masse: 75.555; Wärmedurchgangskoeffizient (U): 20.92 kg/K/s3
Grafiken - Füllmuster für groben Maßstab: <Flächenfüllung>; Farbfüllung für groben Maßstab: 32768
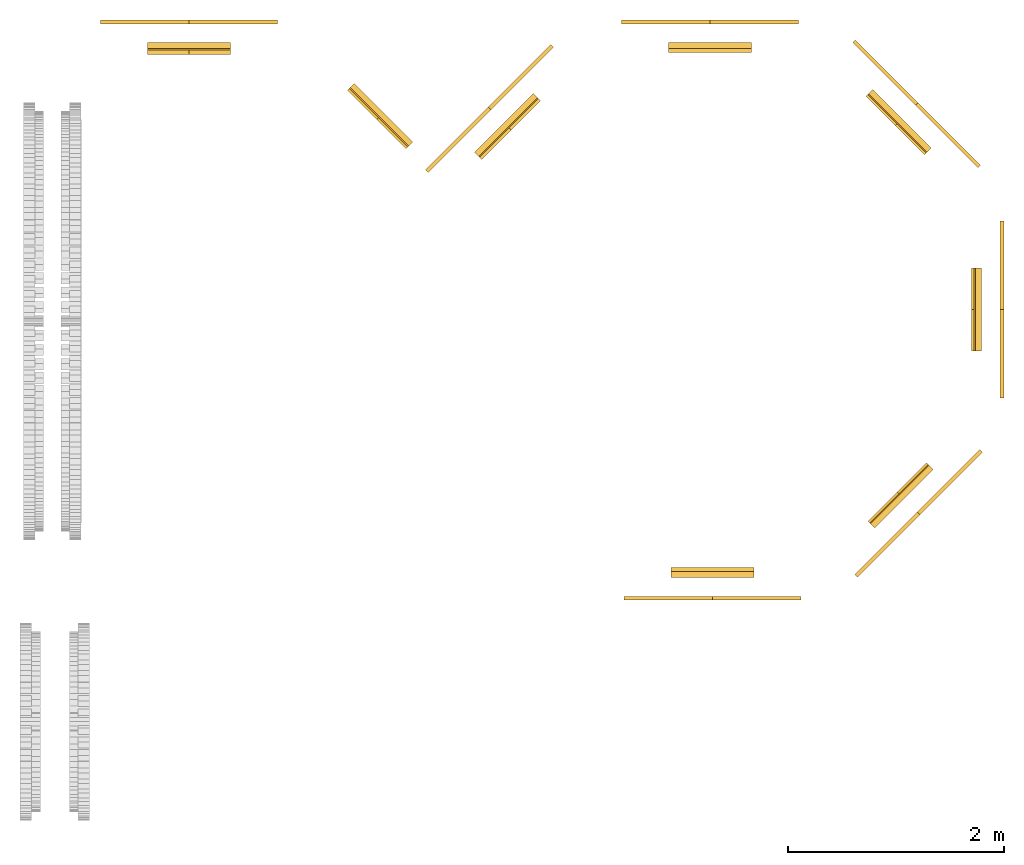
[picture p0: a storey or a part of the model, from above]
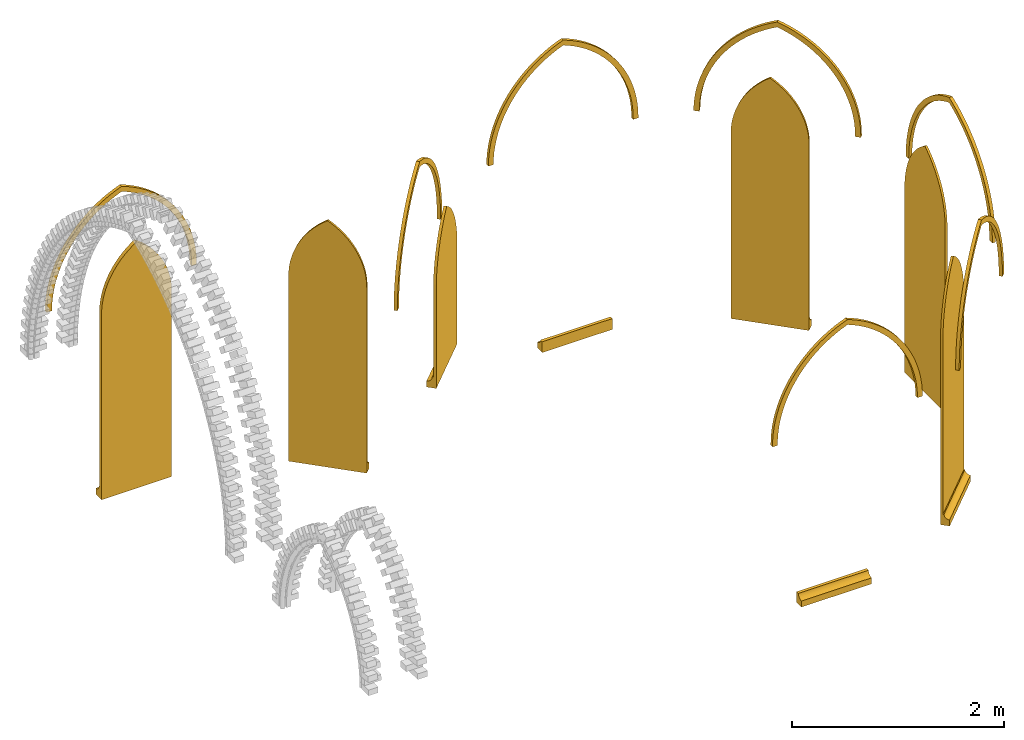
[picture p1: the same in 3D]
Properties of the parts of a building model (IFC2X3), part 5 of 7

# IfcSlabType, no part of this type: Geschossdecke:NS 50
ID-Daten - Bauelement: 50.A9; Beschreibung: STB_200; Typname: NS 50
Konstruktion - Funktion: Außen; Standarddicke: 0.05 m
Materialien und Oberflächen - Tragendes Material: Ortbeton - bewehrt
Sonstige - Kategorie: Geschossdecken; Familienname: Geschossdecke
Tragwerk - Filter Tragend / Nichttragend: yes
Pset_SlabCommon - IsExternal: yes; ThermalTransmittance: 20.92 kg/K/s3

# IfcSlabType, no part of this type: Geschossdecke:STB 125 Zink
PredefinedType: FLOOR; Material: Metall - Zink 0.002 m, Ortbeton - bewehrt 0.123 m
Analytische Eigenschaften - Rauigkeit: 1; Absorptionsgrad: 0.1; Thermischer Widerstand (R): 0.117609; Thermisch wirksame Masse: 191.283; Wärmedurchgangskoeffizient (U): 8.50279 kg/K/s3
Grafiken - Füllmuster für groben Maßstab: <Flächenfüllung>; Farbfüllung für groben Maßstab: 32768
ID-Daten - Beschreibung: STB_250; Typname: STB 125 Zink
Konstruktion - Funktion: Innen; Standarddicke: 0.125 m
Materialien und Oberflächen - Tragendes Material: Ortbeton - bewehrt
Sonstige - Kategorie: Geschossdecken; Familienname: Geschossdecke
Tragwerk - Filter Tragend / Nichttragend: yes
Pset_SlabCommon - IsExternal: no; ThermalTransmittance: 8.50279 kg/K/s3

# IfcSlabType, no part of this type: Geschossdecke:STB 150 Marble step
PredefinedType: FLOOR; Material: Fußboden - Granit black 300x600 0.15 m, Fußboden - Estrich 0.1 m
Analytische Eigenschaften - Rauigkeit: 1; Absorptionsgrad: 0.1
Grafiken - Füllmuster für groben Maßstab: <Flächenfüllung>; Farbfüllung für groben Maßstab: 32768
ID-Daten - Bauelement: 50.A9; Beschreibung: STB_200; Typname: STB 150 Marble step
Konstruktion - Funktion: Innen; Standarddicke: 0.25 m
Sonstige - Kategorie: Geschossdecken; Familienname: Geschossdecke
Tragwerk - Filter Tragend / Nichttragend: yes
Pset_SlabCommon - IsExternal: no

# IfcSlabType, no part of this type: Geschossdecke:STB 150 Marble step
PredefinedType: FLOOR; Material: Fußboden - Granit black 300x600 0.15 m, Fußboden - Estrich 0.1 m
Analytische Eigenschaften - Rauigkeit: 1; Absorptionsgrad: 0.1
Grafiken - Füllmuster für groben Maßstab: <Flächenfüllung>; Farbfüllung für groben Maßstab: 32768
ID-Daten - Bauelement: 50.A9; Beschreibung: STB_200; Typname: STB 150 Marble step
Konstruktion - Funktion: Innen; Standarddicke: 0.25 m
Sonstige - Kategorie: Geschossdecken; Familienname: Geschossdecke
Tragwerk - Filter Tragend / Nichttragend: yes
Pset_SlabCommon - IsExternal: no

# IfcSlabType, no part of this type: Geschossdecke:STB 150 Marble step
PredefinedType: FLOOR; Material: Fußboden - Granit black 300x600 0.15 m, Fußboden - Estrich 0.1 m
Analytische Eigenschaften - Rauigkeit: 1; Absorptionsgrad: 0.1
Grafiken - Füllmuster für groben Maßstab: <Flächenfüllung>; Farbfüllung für groben Maßstab: 32768
ID-Daten - Bauelement: 50.A9; Beschreibung: STB_200; Typname: STB 150 Marble step
Konstruktion - Funktion: Innen; Standarddicke: 0.25 m
Sonstige - Kategorie: Geschossdecken; Familienname: Geschossdecke
Tragwerk - Filter Tragend / Nichttragend: yes
Pset_SlabCommon - IsExternal: no

# IfcSlabType, no part of this type: Geschossdecke:STB 150 MarbleFill Office
PredefinedType: FLOOR; Material: Fußboden - Granit grau 500 x 500 0.02 m, Fußboden - Estrich 0.13 m
Analytische Eigenschaften - Rauigkeit: 1; Absorptionsgrad: 0.1
Grafiken - Füllmuster für groben Maßstab: <Flächenfüllung>; Farbfüllung für groben Maßstab: 32768
ID-Daten - Bauelement: 50.A9; Beschreibung: STB_200; Typname: STB 150 MarbleFill Office
Konstruktion - Funktion: Innen; Standarddicke: 0.15 m
Sonstige - Kategorie: Geschossdecken; Familienname: Geschossdecke
Tragwerk - Filter Tragend / Nichttragend: yes
Pset_SlabCommon - IsExternal: no

# IfcSlabType, no part of this type: Geschossdecke:STB 160 Stone
PredefinedType: FLOOR; Material: Fußboden - Stone 0.16 m
Analytische Eigenschaften - Rauigkeit: 1; Absorptionsgrad: 0.1
Grafiken - Füllmuster für groben Maßstab: <Flächenfüllung>; Farbfüllung für groben Maßstab: 32768
ID-Daten - Bauelement: 50.A9; Beschreibung: STB_200; Typname: STB 160 Stone
Konstruktion - Funktion: Innen; Standarddicke: 0.16 m
Sonstige - Kategorie: Geschossdecken; Familienname: Geschossdecke
Tragwerk - Filter Tragend / Nichttragend: yes
Pset_SlabCommon - IsExternal: no

# IfcSlabType, no part of this type: Geschossdecke:STB 160 Stone
PredefinedType: FLOOR; Material: Fußboden - Stone 0.16 m
Analytische Eigenschaften - Rauigkeit: 1; Absorptionsgrad: 0.1
Grafiken - Füllmuster für groben Maßstab: <Flächenfüllung>; Farbfüllung für groben Maßstab: 32768
ID-Daten - Bauelement: 50.A9; Beschreibung: STB_200; Typname: STB 160 Stone
Konstruktion - Funktion: Innen; Standarddicke: 0.16 m
Sonstige - Kategorie: Geschossdecken; Familienname: Geschossdecke
Tragwerk - Filter Tragend / Nichttragend: yes
Pset_SlabCommon - IsExternal: no

# IfcSlabType, no part of this type: Geschossdecke:STB 160 Stone
PredefinedType: FLOOR; Material: Fußboden - Stone 0.16 m
Analytische Eigenschaften - Rauigkeit: 1; Absorptionsgrad: 0.1
Grafiken - Füllmuster für groben Maßstab: <Flächenfüllung>; Farbfüllung für groben Maßstab: 32768
ID-Daten - Bauelement: 50.A9; Beschreibung: STB_200; Typname: STB 160 Stone
Konstruktion - Funktion: Innen; Standarddicke: 0.16 m
Sonstige - Kategorie: Geschossdecken; Familienname: Geschossdecke
Tragwerk - Filter Tragend / Nichttragend: yes
Pset_SlabCommon - IsExternal: no

# IfcSlabType, no part of this type: Geschossdecke:STB 160 Stone
PredefinedType: FLOOR; Material: Fußboden - Stone 0.16 m
Analytische Eigenschaften - Rauigkeit: 1; Absorptionsgrad: 0.1
Grafiken - Füllmuster für groben Maßstab: <Flächenfüllung>; Farbfüllung für groben Maßstab: 32768
ID-Daten - Bauelement: 50.A9; Beschreibung: STB_200; Typname: STB 160 Stone
Konstruktion - Funktion: Innen; Standarddicke: 0.16 m
Sonstige - Kategorie: Geschossdecken; Familienname: Geschossdecke
Tragwerk - Filter Tragend / Nichttragend: yes
Pset_SlabCommon - IsExternal: no

# IfcSlabType, no part of this type: Geschossdecke:STB 160 Stone
PredefinedType: FLOOR; Material: Fußboden - Stone 0.16 m
Analytische Eigenschaften - Rauigkeit: 1; Absorptionsgrad: 0.1
Grafiken - Füllmuster für groben Maßstab: <Flächenfüllung>; Farbfüllung für groben Maßstab: 32768
ID-Daten - Bauelement: 50.A9; Beschreibung: STB_200; Typname: STB 160 Stone
Konstruktion - Funktion: Innen; Standarddicke: 0.16 m
Sonstige - Kategorie: Geschossdecken; Familienname: Geschossdecke
Tragwerk - Filter Tragend / Nichttragend: yes
Pset_SlabCommon - IsExternal: no

# IfcSlabType, no part of this type: Geschossdecke:STB 160 tiled
PredefinedType: FLOOR; Material: Fußboden - Fliesen 2farbig 170x170 diagonal 0.16 m
Analytische Eigenschaften - Rauigkeit: 1; Absorptionsgrad: 0.1
Grafiken - Füllmuster für groben Maßstab: <Flächenfüllung>; Farbfüllung für groben Maßstab: 32768
ID-Daten - Bauelement: 50.A9; Beschreibung: STB_200; Typname: STB 160 tiled
Konstruktion - Funktion: Innen; Standarddicke: 0.16 m
Sonstige - Kategorie: Geschossdecken; Familienname: Geschossdecke
Tragwerk - Filter Tragend / Nichttragend: yes
Pset_SlabCommon - IsExternal: no

# IfcSlabType, no part of this type: Geschossdecke:STB 172 Stone
PredefinedType: FLOOR; Material: Fußboden - Stone 0.172 m
Analytische Eigenschaften - Rauigkeit: 1; Absorptionsgrad: 0.1
Grafiken - Füllmuster für groben Maßstab: <Flächenfüllung>; Farbfüllung für groben Maßstab: 32768
ID-Daten - Bauelement: 50.A9; Beschreibung: STB_200; Typname: STB 172 Stone
Konstruktion - Funktion: Innen; Standarddicke: 0.172 m
Sonstige - Kategorie: Geschossdecken; Familienname: Geschossdecke
Tragwerk - Filter Tragend / Nichttragend: yes
Pset_SlabCommon - IsExternal: no

# IfcSlabType, no part of this type: Geschossdecke:STB 172 Stone
PredefinedType: FLOOR; Material: Fußboden - Stone 0.172 m
Analytische Eigenschaften - Rauigkeit: 1; Absorptionsgrad: 0.1
Grafiken - Füllmuster für groben Maßstab: <Flächenfüllung>; Farbfüllung für groben Maßstab: 32768
ID-Daten - Bauelement: 50.A9; Beschreibung: STB_200; Typname: STB 172 Stone
Konstruktion - Funktion: Innen; Standarddicke: 0.172 m
Sonstige - Kategorie: Geschossdecken; Familienname: Geschossdecke
Tragwerk - Filter Tragend / Nichttragend: yes
Pset_SlabCommon - IsExternal: no

# IfcSlabType, no part of this type: Geschossdecke:STB 172 Stone
PredefinedType: FLOOR; Material: Fußboden - Stone 0.172 m
Analytische Eigenschaften - Rauigkeit: 1; Absorptionsgrad: 0.1
Grafiken - Füllmuster für groben Maßstab: <Flächenfüllung>; Farbfüllung für groben Maßstab: 32768
ID-Daten - Bauelement: 50.A9; Beschreibung: STB_200; Typname: STB 172 Stone
Konstruktion - Funktion: Innen; Standarddicke: 0.172 m
Sonstige - Kategorie: Geschossdecken; Familienname: Geschossdecke
Tragwerk - Filter Tragend / Nichttragend: yes
Pset_SlabCommon - IsExternal: no

# IfcSlabType, no part of this type: Geschossdecke:STB 172 Stone
PredefinedType: FLOOR; Material: Fußboden - Stone 0.172 m
Analytische Eigenschaften - Rauigkeit: 1; Absorptionsgrad: 0.1
Grafiken - Füllmuster für groben Maßstab: <Flächenfüllung>; Farbfüllung für groben Maßstab: 32768
ID-Daten - Bauelement: 50.A9; Beschreibung: STB_200; Typname: STB 172 Stone
Konstruktion - Funktion: Innen; Standarddicke: 0.172 m
Sonstige - Kategorie: Geschossdecken; Familienname: Geschossdecke
Tragwerk - Filter Tragend / Nichttragend: yes
Pset_SlabCommon - IsExternal: no

# IfcSlabType, no part of this type: Geschossdecke:STB 172 Stone
PredefinedType: FLOOR; Material: Fußboden - Stone 0.172 m
Analytische Eigenschaften - Rauigkeit: 1; Absorptionsgrad: 0.1
Grafiken - Füllmuster für groben Maßstab: <Flächenfüllung>; Farbfüllung für groben Maßstab: 32768
ID-Daten - Bauelement: 50.A9; Beschreibung: STB_200; Typname: STB 172 Stone
Konstruktion - Funktion: Innen; Standarddicke: 0.172 m
Sonstige - Kategorie: Geschossdecken; Familienname: Geschossdecke
Tragwerk - Filter Tragend / Nichttragend: yes
Pset_SlabCommon - IsExternal: no

# IfcSlabType, no part of this type: Geschossdecke:STB 172 Stone
PredefinedType: FLOOR; Material: Fußboden - Stone 0.172 m
Analytische Eigenschaften - Rauigkeit: 1; Absorptionsgrad: 0.1
Grafiken - Füllmuster für groben Maßstab: <Flächenfüllung>; Farbfüllung für groben Maßstab: 32768
ID-Daten - Bauelement: 50.A9; Beschreibung: STB_200; Typname: STB 172 Stone
Konstruktion - Funktion: Innen; Standarddicke: 0.172 m
Sonstige - Kategorie: Geschossdecken; Familienname: Geschossdecke
Tragwerk - Filter Tragend / Nichttragend: yes
Pset_SlabCommon - IsExternal: no

# IfcSlabType, no part of this type: Geschossdecke:STB 172 Stone
PredefinedType: FLOOR; Material: Fußboden - Stone 0.172 m
Analytische Eigenschaften - Rauigkeit: 1; Absorptionsgrad: 0.1
Grafiken - Füllmuster für groben Maßstab: <Flächenfüllung>; Farbfüllung für groben Maßstab: 32768
ID-Daten - Bauelement: 50.A9; Beschreibung: STB_200; Typname: STB 172 Stone
Konstruktion - Funktion: Innen; Standarddicke: 0.172 m
Sonstige - Kategorie: Geschossdecken; Familienname: Geschossdecke
Tragwerk - Filter Tragend / Nichttragend: yes
Pset_SlabCommon - IsExternal: no

# IfcSlabType, no part of this type: Geschossdecke:STB 172 Stone
PredefinedType: FLOOR; Material: Fußboden - Stone 0.172 m
Analytische Eigenschaften - Rauigkeit: 1; Absorptionsgrad: 0.1
Grafiken - Füllmuster für groben Maßstab: <Flächenfüllung>; Farbfüllung für groben Maßstab: 32768
ID-Daten - Bauelement: 50.A9; Beschreibung: STB_200; Typname: STB 172 Stone
Konstruktion - Funktion: Innen; Standarddicke: 0.172 m
Sonstige - Kategorie: Geschossdecken; Familienname: Geschossdecke
Tragwerk - Filter Tragend / Nichttragend: yes
Pset_SlabCommon - IsExternal: no

# IfcSlabType, no part of this type: Geschossdecke:STB 172 Stone
PredefinedType: FLOOR; Material: Fußboden - Stone 0.172 m
Analytische Eigenschaften - Rauigkeit: 1; Absorptionsgrad: 0.1
Grafiken - Füllmuster für groben Maßstab: <Flächenfüllung>; Farbfüllung für groben Maßstab: 32768
ID-Daten - Bauelement: 50.A9; Beschreibung: STB_200; Typname: STB 172 Stone
Konstruktion - Funktion: Innen; Standarddicke: 0.172 m
Sonstige - Kategorie: Geschossdecken; Familienname: Geschossdecke
Tragwerk - Filter Tragend / Nichttragend: yes
Pset_SlabCommon - IsExternal: no

# IfcSlabType, no part of this type: Geschossdecke:STB 172 Stone
PredefinedType: FLOOR; Material: Fußboden - Stone 0.172 m
Analytische Eigenschaften - Rauigkeit: 1; Absorptionsgrad: 0.1
Grafiken - Füllmuster für groben Maßstab: <Flächenfüllung>; Farbfüllung für groben Maßstab: 32768
ID-Daten - Bauelement: 50.A9; Beschreibung: STB_200; Typname: STB 172 Stone
Konstruktion - Funktion: Innen; Standarddicke: 0.172 m
Sonstige - Kategorie: Geschossdecken; Familienname: Geschossdecke
Tragwerk - Filter Tragend / Nichttragend: yes
Pset_SlabCommon - IsExternal: no

# IfcSlabType, no part of this type: Geschossdecke:STB 172 Stone
PredefinedType: FLOOR; Material: Fußboden - Stone 0.172 m
Analytische Eigenschaften - Rauigkeit: 1; Absorptionsgrad: 0.1
Grafiken - Füllmuster für groben Maßstab: <Flächenfüllung>; Farbfüllung für groben Maßstab: 32768
ID-Daten - Bauelement: 50.A9; Beschreibung: STB_200; Typname: STB 172 Stone
Konstruktion - Funktion: Innen; Standarddicke: 0.172 m
Sonstige - Kategorie: Geschossdecken; Familienname: Geschossdecke
Tragwerk - Filter Tragend / Nichttragend: yes
Pset_SlabCommon - IsExternal: no

# IfcSlabType, no part of this type: Geschossdecke:STB 172 Stone
PredefinedType: FLOOR; Material: Fußboden - Stone 0.172 m
Analytische Eigenschaften - Rauigkeit: 1; Absorptionsgrad: 0.1
Grafiken - Füllmuster für groben Maßstab: <Flächenfüllung>; Farbfüllung für groben Maßstab: 32768
ID-Daten - Bauelement: 50.A9; Beschreibung: STB_200; Typname: STB 172 Stone
Konstruktion - Funktion: Innen; Standarddicke: 0.172 m
Sonstige - Kategorie: Geschossdecken; Familienname: Geschossdecke
Tragwerk - Filter Tragend / Nichttragend: yes
Pset_SlabCommon - IsExternal: no

# IfcSlabType, no part of this type: Geschossdecke:STB 172 Stone
PredefinedType: FLOOR; Material: Fußboden - Stone 0.172 m
Analytische Eigenschaften - Rauigkeit: 1; Absorptionsgrad: 0.1
Grafiken - Füllmuster für groben Maßstab: <Flächenfüllung>; Farbfüllung für groben Maßstab: 32768
ID-Daten - Bauelement: 50.A9; Beschreibung: STB_200; Typname: STB 172 Stone
Konstruktion - Funktion: Innen; Standarddicke: 0.172 m
Sonstige - Kategorie: Geschossdecken; Familienname: Geschossdecke
Tragwerk - Filter Tragend / Nichttragend: yes
Pset_SlabCommon - IsExternal: no

# IfcSlabType, no part of this type: Geschossdecke:STB 172 Stone
PredefinedType: FLOOR; Material: Fußboden - Stone 0.172 m
Analytische Eigenschaften - Rauigkeit: 1; Absorptionsgrad: 0.1
Grafiken - Füllmuster für groben Maßstab: <Flächenfüllung>; Farbfüllung für groben Maßstab: 32768
ID-Daten - Bauelement: 50.A9; Beschreibung: STB_200; Typname: STB 172 Stone
Konstruktion - Funktion: Innen; Standarddicke: 0.172 m
Sonstige - Kategorie: Geschossdecken; Familienname: Geschossdecke
Tragwerk - Filter Tragend / Nichttragend: yes
Pset_SlabCommon - IsExternal: no

# IfcSlabType, no part of this type: Geschossdecke:STB 172 Stone
PredefinedType: FLOOR; Material: Fußboden - Stone 0.172 m
Analytische Eigenschaften - Rauigkeit: 1; Absorptionsgrad: 0.1
Grafiken - Füllmuster für groben Maßstab: <Flächenfüllung>; Farbfüllung für groben Maßstab: 32768
ID-Daten - Bauelement: 50.A9; Beschreibung: STB_200; Typname: STB 172 Stone
Konstruktion - Funktion: Innen; Standarddicke: 0.172 m
Sonstige - Kategorie: Geschossdecken; Familienname: Geschossdecke
Tragwerk - Filter Tragend / Nichttragend: yes
Pset_SlabCommon - IsExternal: no

# IfcSlabType, no part of this type: Geschossdecke:STB 172 Stone
PredefinedType: FLOOR; Material: Fußboden - Stone 0.172 m
Analytische Eigenschaften - Rauigkeit: 1; Absorptionsgrad: 0.1
Grafiken - Füllmuster für groben Maßstab: <Flächenfüllung>; Farbfüllung für groben Maßstab: 32768
ID-Daten - Bauelement: 50.A9; Beschreibung: STB_200; Typname: STB 172 Stone
Konstruktion - Funktion: Innen; Standarddicke: 0.172 m
Sonstige - Kategorie: Geschossdecken; Familienname: Geschossdecke
Tragwerk - Filter Tragend / Nichttragend: yes
Pset_SlabCommon - IsExternal: no

# IfcSlabType, no part of this type: Geschossdecke:STB 172 Stone
PredefinedType: FLOOR; Material: Fußboden - Stone 0.172 m
Analytische Eigenschaften - Rauigkeit: 1; Absorptionsgrad: 0.1
Grafiken - Füllmuster für groben Maßstab: <Flächenfüllung>; Farbfüllung für groben Maßstab: 32768
ID-Daten - Bauelement: 50.A9; Beschreibung: STB_200; Typname: STB 172 Stone
Konstruktion - Funktion: Innen; Standarddicke: 0.172 m
Sonstige - Kategorie: Geschossdecken; Familienname: Geschossdecke
Tragwerk - Filter Tragend / Nichttragend: yes
Pset_SlabCommon - IsExternal: no

# IfcSlabType, no part of this type: Geschossdecke:STB 172 Stone
PredefinedType: FLOOR; Material: Fußboden - Stone 0.172 m
Analytische Eigenschaften - Rauigkeit: 1; Absorptionsgrad: 0.1
Grafiken - Füllmuster für groben Maßstab: <Flächenfüllung>; Farbfüllung für groben Maßstab: 32768
ID-Daten - Bauelement: 50.A9; Beschreibung: STB_200; Typname: STB 172 Stone
Konstruktion - Funktion: Innen; Standarddicke: 0.172 m
Sonstige - Kategorie: Geschossdecken; Familienname: Geschossdecke
Tragwerk - Filter Tragend / Nichttragend: yes
Pset_SlabCommon - IsExternal: no

# IfcSlabType, no part of this type: Geschossdecke:STB 172 Stone
PredefinedType: FLOOR; Material: Fußboden - Stone 0.172 m
Analytische Eigenschaften - Rauigkeit: 1; Absorptionsgrad: 0.1
Grafiken - Füllmuster für groben Maßstab: <Flächenfüllung>; Farbfüllung für groben Maßstab: 32768
ID-Daten - Bauelement: 50.A9; Beschreibung: STB_200; Typname: STB 172 Stone
Konstruktion - Funktion: Innen; Standarddicke: 0.172 m
Sonstige - Kategorie: Geschossdecken; Familienname: Geschossdecke
Tragwerk - Filter Tragend / Nichttragend: yes
Pset_SlabCommon - IsExternal: no

# IfcSlabType, no part of this type: Geschossdecke:STB 172 Stone
PredefinedType: FLOOR; Material: Fußboden - Stone 0.172 m
Analytische Eigenschaften - Rauigkeit: 1; Absorptionsgrad: 0.1
Grafiken - Füllmuster für groben Maßstab: <Flächenfüllung>; Farbfüllung für groben Maßstab: 32768
ID-Daten - Bauelement: 50.A9; Beschreibung: STB_200; Typname: STB 172 Stone
Konstruktion - Funktion: Innen; Standarddicke: 0.172 m
Sonstige - Kategorie: Geschossdecken; Familienname: Geschossdecke
Tragwerk - Filter Tragend / Nichttragend: yes
Pset_SlabCommon - IsExternal: no

# IfcSlabType, no part of this type: Geschossdecke:STB 172 Stone
PredefinedType: FLOOR; Material: Fußboden - Stone 0.172 m
Analytische Eigenschaften - Rauigkeit: 1; Absorptionsgrad: 0.1
Grafiken - Füllmuster für groben Maßstab: <Flächenfüllung>; Farbfüllung für groben Maßstab: 32768
ID-Daten - Bauelement: 50.A9; Beschreibung: STB_200; Typname: STB 172 Stone
Konstruktion - Funktion: Innen; Standarddicke: 0.172 m
Sonstige - Kategorie: Geschossdecken; Familienname: Geschossdecke
Tragwerk - Filter Tragend / Nichttragend: yes
Pset_SlabCommon - IsExternal: no

# IfcSlabType, no part of this type: Geschossdecke:STB 172 Stone
PredefinedType: FLOOR; Material: Fußboden - Stone 0.172 m
Analytische Eigenschaften - Rauigkeit: 1; Absorptionsgrad: 0.1
Grafiken - Füllmuster für groben Maßstab: <Flächenfüllung>; Farbfüllung für groben Maßstab: 32768
ID-Daten - Bauelement: 50.A9; Beschreibung: STB_200; Typname: STB 172 Stone
Konstruktion - Funktion: Innen; Standarddicke: 0.172 m
Sonstige - Kategorie: Geschossdecken; Familienname: Geschossdecke
Tragwerk - Filter Tragend / Nichttragend: yes
Pset_SlabCommon - IsExternal: no

# IfcSlabType, no part of this type: Geschossdecke:STB 172 Stone
PredefinedType: FLOOR; Material: Fußboden - Stone 0.172 m
Analytische Eigenschaften - Rauigkeit: 1; Absorptionsgrad: 0.1
Grafiken - Füllmuster für groben Maßstab: <Flächenfüllung>; Farbfüllung für groben Maßstab: 32768
ID-Daten - Bauelement: 50.A9; Beschreibung: STB_200; Typname: STB 172 Stone
Konstruktion - Funktion: Innen; Standarddicke: 0.172 m
Sonstige - Kategorie: Geschossdecken; Familienname: Geschossdecke
Tragwerk - Filter Tragend / Nichttragend: yes
Pset_SlabCommon - IsExternal: no

# IfcSlabType, no part of this type: Geschossdecke:STB 172 Stone
PredefinedType: FLOOR; Material: Fußboden - Stone 0.172 m
Analytische Eigenschaften - Rauigkeit: 1; Absorptionsgrad: 0.1
Grafiken - Füllmuster für groben Maßstab: <Flächenfüllung>; Farbfüllung für groben Maßstab: 32768
ID-Daten - Bauelement: 50.A9; Beschreibung: STB_200; Typname: STB 172 Stone
Konstruktion - Funktion: Innen; Standarddicke: 0.172 m
Sonstige - Kategorie: Geschossdecken; Familienname: Geschossdecke
Tragwerk - Filter Tragend / Nichttragend: yes
Pset_SlabCommon - IsExternal: no

# IfcSlabType, no part of this type: Geschossdecke:STB 172 Stone
PredefinedType: FLOOR; Material: Fußboden - Stone 0.172 m
Analytische Eigenschaften - Rauigkeit: 1; Absorptionsgrad: 0.1
Grafiken - Füllmuster für groben Maßstab: <Flächenfüllung>; Farbfüllung für groben Maßstab: 32768
ID-Daten - Bauelement: 50.A9; Beschreibung: STB_200; Typname: STB 172 Stone
Konstruktion - Funktion: Innen; Standarddicke: 0.172 m
Sonstige - Kategorie: Geschossdecken; Familienname: Geschossdecke
Tragwerk - Filter Tragend / Nichttragend: yes
Pset_SlabCommon - IsExternal: no

# IfcSlabType, no part of this type: Geschossdecke:STB 172 Stone
PredefinedType: FLOOR; Material: Fußboden - Stone 0.172 m
Analytische Eigenschaften - Rauigkeit: 1; Absorptionsgrad: 0.1
Grafiken - Füllmuster für groben Maßstab: <Flächenfüllung>; Farbfüllung für groben Maßstab: 32768
ID-Daten - Bauelement: 50.A9; Beschreibung: STB_200; Typname: STB 172 Stone
Konstruktion - Funktion: Innen; Standarddicke: 0.172 m
Sonstige - Kategorie: Geschossdecken; Familienname: Geschossdecke
Tragwerk - Filter Tragend / Nichttragend: yes
Pset_SlabCommon - IsExternal: no

# IfcSlabType, no part of this type: Geschossdecke:STB 175 Stone
PredefinedType: FLOOR; Material: Fußboden - Stone 0.175 m
Analytische Eigenschaften - Rauigkeit: 1; Absorptionsgrad: 0.1
Grafiken - Füllmuster für groben Maßstab: <Flächenfüllung>; Farbfüllung für groben Maßstab: 32768
ID-Daten - Bauelement: 50.A9; Beschreibung: STB_200; Typname: STB 175 Stone
Konstruktion - Funktion: Innen; Standarddicke: 0.175 m
Sonstige - Kategorie: Geschossdecken; Familienname: Geschossdecke
Tragwerk - Filter Tragend / Nichttragend: yes
Pset_SlabCommon - IsExternal: no

# IfcSlabType, no part of this type: Geschossdecke:STB 175 Stone
PredefinedType: FLOOR; Material: Fußboden - Stone 0.175 m
Analytische Eigenschaften - Rauigkeit: 1; Absorptionsgrad: 0.1
Grafiken - Füllmuster für groben Maßstab: <Flächenfüllung>; Farbfüllung für groben Maßstab: 32768
ID-Daten - Bauelement: 50.A9; Beschreibung: STB_200; Typname: STB 175 Stone
Konstruktion - Funktion: Innen; Standarddicke: 0.175 m
Sonstige - Kategorie: Geschossdecken; Familienname: Geschossdecke
Tragwerk - Filter Tragend / Nichttragend: yes
Pset_SlabCommon - IsExternal: no

# IfcSlabType, no part of this type: Geschossdecke:STB 175 Stone
PredefinedType: FLOOR; Material: Fußboden - Stone 0.175 m
Analytische Eigenschaften - Rauigkeit: 1; Absorptionsgrad: 0.1
Grafiken - Füllmuster für groben Maßstab: <Flächenfüllung>; Farbfüllung für groben Maßstab: 32768
ID-Daten - Bauelement: 50.A9; Beschreibung: STB_200; Typname: STB 175 Stone
Konstruktion - Funktion: Innen; Standarddicke: 0.175 m
Sonstige - Kategorie: Geschossdecken; Familienname: Geschossdecke
Tragwerk - Filter Tragend / Nichttragend: yes
Pset_SlabCommon - IsExternal: no

# IfcSlabType, no part of this type: Geschossdecke:STB 175 Stone
PredefinedType: FLOOR; Material: Fußboden - Stone 0.175 m
Analytische Eigenschaften - Rauigkeit: 1; Absorptionsgrad: 0.1
Grafiken - Füllmuster für groben Maßstab: <Flächenfüllung>; Farbfüllung für groben Maßstab: 32768
ID-Daten - Bauelement: 50.A9; Beschreibung: STB_200; Typname: STB 175 Stone
Konstruktion - Funktion: Innen; Standarddicke: 0.175 m
Sonstige - Kategorie: Geschossdecken; Familienname: Geschossdecke
Tragwerk - Filter Tragend / Nichttragend: yes
Pset_SlabCommon - IsExternal: no

# IfcSlabType, no part of this type: Geschossdecke:STB 175 Stone
PredefinedType: FLOOR; Material: Fußboden - Stone 0.175 m
Analytische Eigenschaften - Rauigkeit: 1; Absorptionsgrad: 0.1
Grafiken - Füllmuster für groben Maßstab: <Flächenfüllung>; Farbfüllung für groben Maßstab: 32768
ID-Daten - Bauelement: 50.A9; Beschreibung: STB_200; Typname: STB 175 Stone
Konstruktion - Funktion: Innen; Standarddicke: 0.175 m
Sonstige - Kategorie: Geschossdecken; Familienname: Geschossdecke
Tragwerk - Filter Tragend / Nichttragend: yes
Pset_SlabCommon - IsExternal: no

# IfcSlabType, no part of this type: Geschossdecke:STB 175 Stone
PredefinedType: FLOOR; Material: Fußboden - Stone 0.175 m
Analytische Eigenschaften - Rauigkeit: 1; Absorptionsgrad: 0.1
Grafiken - Füllmuster für groben Maßstab: <Flächenfüllung>; Farbfüllung für groben Maßstab: 32768
ID-Daten - Bauelement: 50.A9; Beschreibung: STB_200; Typname: STB 175 Stone
Konstruktion - Funktion: Innen; Standarddicke: 0.175 m
Sonstige - Kategorie: Geschossdecken; Familienname: Geschossdecke
Tragwerk - Filter Tragend / Nichttragend: yes
Pset_SlabCommon - IsExternal: no

# IfcSlabType, no part of this type: Geschossdecke:STB 175 Stone
PredefinedType: FLOOR; Material: Fußboden - Stone 0.175 m
Analytische Eigenschaften - Rauigkeit: 1; Absorptionsgrad: 0.1
Grafiken - Füllmuster für groben Maßstab: <Flächenfüllung>; Farbfüllung für groben Maßstab: 32768
ID-Daten - Bauelement: 50.A9; Beschreibung: STB_200; Typname: STB 175 Stone
Konstruktion - Funktion: Innen; Standarddicke: 0.175 m
Sonstige - Kategorie: Geschossdecken; Familienname: Geschossdecke
Tragwerk - Filter Tragend / Nichttragend: yes
Pset_SlabCommon - IsExternal: no

# IfcSlabType, no part of this type: Geschossdecke:STB 175 Stone
PredefinedType: FLOOR; Material: Fußboden - Stone 0.175 m
Analytische Eigenschaften - Rauigkeit: 1; Absorptionsgrad: 0.1
Grafiken - Füllmuster für groben Maßstab: <Flächenfüllung>; Farbfüllung für groben Maßstab: 32768
ID-Daten - Bauelement: 50.A9; Beschreibung: STB_200; Typname: STB 175 Stone
Konstruktion - Funktion: Innen; Standarddicke: 0.175 m
Sonstige - Kategorie: Geschossdecken; Familienname: Geschossdecke
Tragwerk - Filter Tragend / Nichttragend: yes
Pset_SlabCommon - IsExternal: no

# IfcSlabType, no part of this type: Geschossdecke:STB 175 Stone
PredefinedType: FLOOR; Material: Fußboden - Stone 0.175 m
Analytische Eigenschaften - Rauigkeit: 1; Absorptionsgrad: 0.1
Grafiken - Füllmuster für groben Maßstab: <Flächenfüllung>; Farbfüllung für groben Maßstab: 32768
ID-Daten - Bauelement: 50.A9; Beschreibung: STB_200; Typname: STB 175 Stone
Konstruktion - Funktion: Innen; Standarddicke: 0.175 m
Sonstige - Kategorie: Geschossdecken; Familienname: Geschossdecke
Tragwerk - Filter Tragend / Nichttragend: yes
Pset_SlabCommon - IsExternal: no

# IfcSlabType, no part of this type: Geschossdecke:STB 175 Stone
PredefinedType: FLOOR; Material: Fußboden - Stone 0.175 m
Analytische Eigenschaften - Rauigkeit: 1; Absorptionsgrad: 0.1
Grafiken - Füllmuster für groben Maßstab: <Flächenfüllung>; Farbfüllung für groben Maßstab: 32768
ID-Daten - Bauelement: 50.A9; Beschreibung: STB_200; Typname: STB 175 Stone
Konstruktion - Funktion: Innen; Standarddicke: 0.175 m
Sonstige - Kategorie: Geschossdecken; Familienname: Geschossdecke
Tragwerk - Filter Tragend / Nichttragend: yes
Pset_SlabCommon - IsExternal: no

# IfcSlabType, no part of this type: Geschossdecke:STB 175 Stone
PredefinedType: FLOOR; Material: Fußboden - Stone 0.175 m
Analytische Eigenschaften - Rauigkeit: 1; Absorptionsgrad: 0.1
Grafiken - Füllmuster für groben Maßstab: <Flächenfüllung>; Farbfüllung für groben Maßstab: 32768
ID-Daten - Bauelement: 50.A9; Beschreibung: STB_200; Typname: STB 175 Stone
Konstruktion - Funktion: Innen; Standarddicke: 0.175 m
Sonstige - Kategorie: Geschossdecken; Familienname: Geschossdecke
Tragwerk - Filter Tragend / Nichttragend: yes
Pset_SlabCommon - IsExternal: no

# IfcSlabType, no part of this type: Geschossdecke:STB 175 Stone
PredefinedType: FLOOR; Material: Fußboden - Stone 0.175 m
Analytische Eigenschaften - Rauigkeit: 1; Absorptionsgrad: 0.1
Grafiken - Füllmuster für groben Maßstab: <Flächenfüllung>; Farbfüllung für groben Maßstab: 32768
ID-Daten - Bauelement: 50.A9; Beschreibung: STB_200; Typname: STB 175 Stone
Konstruktion - Funktion: Innen; Standarddicke: 0.175 m
Sonstige - Kategorie: Geschossdecken; Familienname: Geschossdecke
Tragwerk - Filter Tragend / Nichttragend: yes
Pset_SlabCommon - IsExternal: no

# IfcSlabType, no part of this type: Geschossdecke:STB 175 Stone
PredefinedType: FLOOR; Material: Fußboden - Stone 0.175 m
Analytische Eigenschaften - Rauigkeit: 1; Absorptionsgrad: 0.1
Grafiken - Füllmuster für groben Maßstab: <Flächenfüllung>; Farbfüllung für groben Maßstab: 32768
ID-Daten - Bauelement: 50.A9; Beschreibung: STB_200; Typname: STB 175 Stone
Konstruktion - Funktion: Innen; Standarddicke: 0.175 m
Sonstige - Kategorie: Geschossdecken; Familienname: Geschossdecke
Tragwerk - Filter Tragend / Nichttragend: yes
Pset_SlabCommon - IsExternal: no

# IfcSlabType, no part of this type: Geschossdecke:STB 175 Stone
PredefinedType: FLOOR; Material: Fußboden - Stone 0.175 m
Analytische Eigenschaften - Rauigkeit: 1; Absorptionsgrad: 0.1
Grafiken - Füllmuster für groben Maßstab: <Flächenfüllung>; Farbfüllung für groben Maßstab: 32768
ID-Daten - Bauelement: 50.A9; Beschreibung: STB_200; Typname: STB 175 Stone
Konstruktion - Funktion: Innen; Standarddicke: 0.175 m
Sonstige - Kategorie: Geschossdecken; Familienname: Geschossdecke
Tragwerk - Filter Tragend / Nichttragend: yes
Pset_SlabCommon - IsExternal: no

# IfcSlabType, no part of this type: Geschossdecke:STB 175 Stone
PredefinedType: FLOOR; Material: Fußboden - Stone 0.175 m
Analytische Eigenschaften - Rauigkeit: 1; Absorptionsgrad: 0.1
Grafiken - Füllmuster für groben Maßstab: <Flächenfüllung>; Farbfüllung für groben Maßstab: 32768
ID-Daten - Bauelement: 50.A9; Beschreibung: STB_200; Typname: STB 175 Stone
Konstruktion - Funktion: Innen; Standarddicke: 0.175 m
Sonstige - Kategorie: Geschossdecken; Familienname: Geschossdecke
Tragwerk - Filter Tragend / Nichttragend: yes
Pset_SlabCommon - IsExternal: no

# IfcSlabType, no part of this type: Geschossdecke:STB 175 Stone
PredefinedType: FLOOR; Material: Fußboden - Stone 0.175 m
Analytische Eigenschaften - Rauigkeit: 1; Absorptionsgrad: 0.1
Grafiken - Füllmuster für groben Maßstab: <Flächenfüllung>; Farbfüllung für groben Maßstab: 32768
ID-Daten - Bauelement: 50.A9; Beschreibung: STB_200; Typname: STB 175 Stone
Konstruktion - Funktion: Innen; Standarddicke: 0.175 m
Sonstige - Kategorie: Geschossdecken; Familienname: Geschossdecke
Tragwerk - Filter Tragend / Nichttragend: yes
Pset_SlabCommon - IsExternal: no

# IfcSlabType, no part of this type: Geschossdecke:STB 175 Stone
PredefinedType: FLOOR; Material: Fußboden - Stone 0.175 m
Analytische Eigenschaften - Rauigkeit: 1; Absorptionsgrad: 0.1
Grafiken - Füllmuster für groben Maßstab: <Flächenfüllung>; Farbfüllung für groben Maßstab: 32768
ID-Daten - Bauelement: 50.A9; Beschreibung: STB_200; Typname: STB 175 Stone
Konstruktion - Funktion: Innen; Standarddicke: 0.175 m
Sonstige - Kategorie: Geschossdecken; Familienname: Geschossdecke
Tragwerk - Filter Tragend / Nichttragend: yes
Pset_SlabCommon - IsExternal: no

# IfcSlabType, no part of this type: Geschossdecke:STB 175 Stone
PredefinedType: FLOOR; Material: Fußboden - Stone 0.175 m
Analytische Eigenschaften - Rauigkeit: 1; Absorptionsgrad: 0.1
Grafiken - Füllmuster für groben Maßstab: <Flächenfüllung>; Farbfüllung für groben Maßstab: 32768
ID-Daten - Bauelement: 50.A9; Beschreibung: STB_200; Typname: STB 175 Stone
Konstruktion - Funktion: Innen; Standarddicke: 0.175 m
Sonstige - Kategorie: Geschossdecken; Familienname: Geschossdecke
Tragwerk - Filter Tragend / Nichttragend: yes
Pset_SlabCommon - IsExternal: no

# IfcSlabType, no part of this type: Geschossdecke:STB 175 Stone
PredefinedType: FLOOR; Material: Fußboden - Stone 0.175 m
Analytische Eigenschaften - Rauigkeit: 1; Absorptionsgrad: 0.1
Grafiken - Füllmuster für groben Maßstab: <Flächenfüllung>; Farbfüllung für groben Maßstab: 32768
ID-Daten - Bauelement: 50.A9; Beschreibung: STB_200; Typname: STB 175 Stone
Konstruktion - Funktion: Innen; Standarddicke: 0.175 m
Sonstige - Kategorie: Geschossdecken; Familienname: Geschossdecke
Tragwerk - Filter Tragend / Nichttragend: yes
Pset_SlabCommon - IsExternal: no

# IfcSlabType, no part of this type: Geschossdecke:STB 175 Stone
PredefinedType: FLOOR; Material: Fußboden - Stone 0.175 m
Analytische Eigenschaften - Rauigkeit: 1; Absorptionsgrad: 0.1
Grafiken - Füllmuster für groben Maßstab: <Flächenfüllung>; Farbfüllung für groben Maßstab: 32768
ID-Daten - Bauelement: 50.A9; Beschreibung: STB_200; Typname: STB 175 Stone
Konstruktion - Funktion: Innen; Standarddicke: 0.175 m
Sonstige - Kategorie: Geschossdecken; Familienname: Geschossdecke
Tragwerk - Filter Tragend / Nichttragend: yes
Pset_SlabCommon - IsExternal: no

# IfcSlabType, no part of this type: Geschossdecke:STB 175 Stone
PredefinedType: FLOOR; Material: Fußboden - Stone 0.175 m
Analytische Eigenschaften - Rauigkeit: 1; Absorptionsgrad: 0.1
Grafiken - Füllmuster für groben Maßstab: <Flächenfüllung>; Farbfüllung für groben Maßstab: 32768
ID-Daten - Bauelement: 50.A9; Beschreibung: STB_200; Typname: STB 175 Stone
Konstruktion - Funktion: Innen; Standarddicke: 0.175 m
Sonstige - Kategorie: Geschossdecken; Familienname: Geschossdecke
Tragwerk - Filter Tragend / Nichttragend: yes
Pset_SlabCommon - IsExternal: no

# IfcSlabType, no part of this type: Geschossdecke:STB 175 Stone
PredefinedType: FLOOR; Material: Fußboden - Stone 0.175 m
Analytische Eigenschaften - Rauigkeit: 1; Absorptionsgrad: 0.1
Grafiken - Füllmuster für groben Maßstab: <Flächenfüllung>; Farbfüllung für groben Maßstab: 32768
ID-Daten - Bauelement: 50.A9; Beschreibung: STB_200; Typname: STB 175 Stone
Konstruktion - Funktion: Innen; Standarddicke: 0.175 m
Sonstige - Kategorie: Geschossdecken; Familienname: Geschossdecke
Tragwerk - Filter Tragend / Nichttragend: yes
Pset_SlabCommon - IsExternal: no

# IfcSlabType, no part of this type: Geschossdecke:STB 190
PredefinedType: FLOOR; Material: Ortbeton - bewehrt 0.19 m
Analytische Eigenschaften - Rauigkeit: 1; Absorptionsgrad: 0.1; Thermischer Widerstand (R): 0.181644; Thermisch wirksame Masse: 287.109; Wärmedurchgangskoeffizient (U): 5.50526 kg/K/s3
Grafiken - Füllmuster für groben Maßstab: <Flächenfüllung>; Farbfüllung für groben Maßstab: 32768
ID-Daten - Bauelement: 50.A9; Beschreibung: STB_200; Typname: STB 190
Konstruktion - Funktion: Innen; Standarddicke: 0.19 m
Sonstige - Kategorie: Geschossdecken; Familienname: Geschossdecke
Tragwerk - Filter Tragend / Nichttragend: yes
Pset_SlabCommon - IsExternal: no; ThermalTransmittance: 5.50526 kg/K/s3

# IfcSlabType, no part of this type: Geschossdecke:STB 190 concrete
PredefinedType: FLOOR; Material: Ortbeton - unbewehrt 0.19 m
Analytische Eigenschaften - Rauigkeit: 1; Absorptionsgrad: 0.1
Grafiken - Füllmuster für groben Maßstab: <Flächenfüllung>; Farbfüllung für groben Maßstab: 32768
ID-Daten - Bauelement: 50.A9; Beschreibung: STB_200; Typname: STB 190 concrete
Konstruktion - Funktion: Innen; Standarddicke: 0.19 m
Sonstige - Kategorie: Geschossdecken; Familienname: Geschossdecke
Tragwerk - Filter Tragend / Nichttragend: yes
Pset_SlabCommon - IsExternal: no

# IfcSlabType, no part of this type: Geschossdecke:STB 190 concrete
PredefinedType: FLOOR; Material: Ortbeton - unbewehrt 0.19 m
Analytische Eigenschaften - Rauigkeit: 1; Absorptionsgrad: 0.1
Grafiken - Füllmuster für groben Maßstab: <Flächenfüllung>; Farbfüllung für groben Maßstab: 32768
ID-Daten - Bauelement: 50.A9; Beschreibung: STB_200; Typname: STB 190 concrete
Konstruktion - Funktion: Innen; Standarddicke: 0.19 m
Sonstige - Kategorie: Geschossdecken; Familienname: Geschossdecke
Tragwerk - Filter Tragend / Nichttragend: yes
Pset_SlabCommon - IsExternal: no

# IfcSlabType, no part of this type: Geschossdecke:STB 200 Basement Kitchen Floor
PredefinedType: FLOOR; Material: Ortbeton - bewehrt 0.2 m, Fußboden - Schüttung 0.725 m
Analytische Eigenschaften - Rauigkeit: 1; Absorptionsgrad: 0.1; Thermischer Widerstand (R): 2.20509; Thermisch wirksame Masse: 1422.78; Wärmedurchgangskoeffizient (U): 0.453496 kg/K/s3
Grafiken - Füllmuster für groben Maßstab: <Flächenfüllung>; Farbfüllung für groben Maßstab: 32768
ID-Daten - Bauelement: 50.A9; Beschreibung: STB_200; Typname: STB 200 Basement Kitchen Floor
Konstruktion - Funktion: Innen; Standarddicke: 0.925 m
Materialien und Oberflächen - Tragendes Material: Ortbeton - bewehrt
Sonstige - Kategorie: Geschossdecken; Familienname: Geschossdecke
Tragwerk - Filter Tragend / Nichttragend: yes
Pset_SlabCommon - IsExternal: no; ThermalTransmittance: 0.453496 kg/K/s3

# IfcSlabType, no part of this type: Geschossdecke:STB 200 Nominal Ground
PredefinedType: FLOOR; Material: Ortbeton - bewehrt 0.2 m
Analytische Eigenschaften - Rauigkeit: 1; Absorptionsgrad: 0.1; Thermischer Widerstand (R): 0.191205; Thermisch wirksame Masse: 302.22; Wärmedurchgangskoeffizient (U): 5.23 kg/K/s3
Grafiken - Füllmuster für groben Maßstab: <Flächenfüllung>; Farbfüllung für groben Maßstab: 32768
ID-Daten - Bauelement: 50.A9; Beschreibung: STB_200; Typname: STB 200 Nominal Ground
Konstruktion - Funktion: Innen; Standarddicke: 0.2 m
Materialien und Oberflächen - Tragendes Material: Ortbeton - bewehrt
Sonstige - Kategorie: Geschossdecken; Familienname: Geschossdecke
Tragwerk - Filter Tragend / Nichttragend: yes
Pset_SlabCommon - IsExternal: no; ThermalTransmittance: 5.23 kg/K/s3

# IfcSlabType, no part of this type: Geschossdecke:STB 200 Nominal Ground
PredefinedType: FLOOR; Material: Ortbeton - bewehrt 0.2 m
Analytische Eigenschaften - Rauigkeit: 1; Absorptionsgrad: 0.1; Thermischer Widerstand (R): 0.191205; Thermisch wirksame Masse: 302.22; Wärmedurchgangskoeffizient (U): 5.23 kg/K/s3
Grafiken - Füllmuster für groben Maßstab: <Flächenfüllung>; Farbfüllung für groben Maßstab: 32768
ID-Daten - Bauelement: 50.A9; Beschreibung: STB_200; Typname: STB 200 Nominal Ground
Konstruktion - Funktion: Innen; Standarddicke: 0.2 m
Materialien und Oberflächen - Tragendes Material: Ortbeton - bewehrt
Sonstige - Kategorie: Geschossdecken; Familienname: Geschossdecke
Tragwerk - Filter Tragend / Nichttragend: yes
Pset_SlabCommon - IsExternal: no; ThermalTransmittance: 5.23 kg/K/s3

# IfcSlabType, no part of this type: Geschossdecke:STB 200 Stone Steps
PredefinedType: FLOOR; Material: Fußboden - Estrich 0.2 m
Analytische Eigenschaften - Rauigkeit: 1; Absorptionsgrad: 0.1
Grafiken - Füllmuster für groben Maßstab: <Flächenfüllung>; Farbfüllung für groben Maßstab: 32768
ID-Daten - Bauelement: 50.A9; Beschreibung: STB_200; Typname: STB 200 Stone Steps
Konstruktion - Funktion: Innen; Standarddicke: 0.2 m
Sonstige - Kategorie: Geschossdecken; Familienname: Geschossdecke
Tragwerk - Filter Tragend / Nichttragend: yes
Pset_SlabCommon - IsExternal: no

# IfcSlabType, no part of this type: Geschossdecke:STB 200 Stone Steps
PredefinedType: FLOOR; Material: Fußboden - Estrich 0.2 m
Analytische Eigenschaften - Rauigkeit: 1; Absorptionsgrad: 0.1
Grafiken - Füllmuster für groben Maßstab: <Flächenfüllung>; Farbfüllung für groben Maßstab: 32768
ID-Daten - Bauelement: 50.A9; Beschreibung: STB_200; Typname: STB 200 Stone Steps
Konstruktion - Funktion: Innen; Standarddicke: 0.2 m
Sonstige - Kategorie: Geschossdecken; Familienname: Geschossdecke
Tragwerk - Filter Tragend / Nichttragend: yes
Pset_SlabCommon - IsExternal: no

# IfcSlabType, no part of this type: Geschossdecke:STB 200 Stone Steps
PredefinedType: FLOOR; Material: Fußboden - Estrich 0.2 m
Analytische Eigenschaften - Rauigkeit: 1; Absorptionsgrad: 0.1
Grafiken - Füllmuster für groben Maßstab: <Flächenfüllung>; Farbfüllung für groben Maßstab: 32768
ID-Daten - Bauelement: 50.A9; Beschreibung: STB_200; Typname: STB 200 Stone Steps
Konstruktion - Funktion: Innen; Standarddicke: 0.2 m
Sonstige - Kategorie: Geschossdecken; Familienname: Geschossdecke
Tragwerk - Filter Tragend / Nichttragend: yes
Pset_SlabCommon - IsExternal: no

# IfcSlabType, no part of this type: Geschossdecke:STB 200 Stone Steps
PredefinedType: FLOOR; Material: Fußboden - Estrich 0.2 m
Analytische Eigenschaften - Rauigkeit: 1; Absorptionsgrad: 0.1
Grafiken - Füllmuster für groben Maßstab: <Flächenfüllung>; Farbfüllung für groben Maßstab: 32768
ID-Daten - Bauelement: 50.A9; Beschreibung: STB_200; Typname: STB 200 Stone Steps
Konstruktion - Funktion: Innen; Standarddicke: 0.2 m
Sonstige - Kategorie: Geschossdecken; Familienname: Geschossdecke
Tragwerk - Filter Tragend / Nichttragend: yes
Pset_SlabCommon - IsExternal: no

# IfcSlabType, no part of this type: Geschossdecke:STB 200 Stone Steps
PredefinedType: FLOOR; Material: Fußboden - Estrich 0.2 m
Analytische Eigenschaften - Rauigkeit: 1; Absorptionsgrad: 0.1
Grafiken - Füllmuster für groben Maßstab: <Flächenfüllung>; Farbfüllung für groben Maßstab: 32768
ID-Daten - Bauelement: 50.A9; Beschreibung: STB_200; Typname: STB 200 Stone Steps
Konstruktion - Funktion: Innen; Standarddicke: 0.2 m
Sonstige - Kategorie: Geschossdecken; Familienname: Geschossdecke
Tragwerk - Filter Tragend / Nichttragend: yes
Pset_SlabCommon - IsExternal: no

# IfcSlabType, no part of this type: Geschossdecke:STB 200 Stone Steps
PredefinedType: FLOOR; Material: Fußboden - Estrich 0.2 m
Analytische Eigenschaften - Rauigkeit: 1; Absorptionsgrad: 0.1
Grafiken - Füllmuster für groben Maßstab: <Flächenfüllung>; Farbfüllung für groben Maßstab: 32768
ID-Daten - Bauelement: 50.A9; Beschreibung: STB_200; Typname: STB 200 Stone Steps
Konstruktion - Funktion: Innen; Standarddicke: 0.2 m
Sonstige - Kategorie: Geschossdecken; Familienname: Geschossdecke
Tragwerk - Filter Tragend / Nichttragend: yes
Pset_SlabCommon - IsExternal: no

# IfcSlabType, no part of this type: Geschossdecke:STB 200 Stone Steps
PredefinedType: FLOOR; Material: Fußboden - Estrich 0.2 m
Analytische Eigenschaften - Rauigkeit: 1; Absorptionsgrad: 0.1
Grafiken - Füllmuster für groben Maßstab: <Flächenfüllung>; Farbfüllung für groben Maßstab: 32768
ID-Daten - Bauelement: 50.A9; Beschreibung: STB_200; Typname: STB 200 Stone Steps
Konstruktion - Funktion: Innen; Standarddicke: 0.2 m
Sonstige - Kategorie: Geschossdecken; Familienname: Geschossdecke
Tragwerk - Filter Tragend / Nichttragend: yes
Pset_SlabCommon - IsExternal: no

# IfcSlabType, no part of this type: Geschossdecke:STB 200 Stone Steps
PredefinedType: FLOOR; Material: Fußboden - Estrich 0.2 m
Analytische Eigenschaften - Rauigkeit: 1; Absorptionsgrad: 0.1
Grafiken - Füllmuster für groben Maßstab: <Flächenfüllung>; Farbfüllung für groben Maßstab: 32768
ID-Daten - Bauelement: 50.A9; Beschreibung: STB_200; Typname: STB 200 Stone Steps
Konstruktion - Funktion: Innen; Standarddicke: 0.2 m
Sonstige - Kategorie: Geschossdecken; Familienname: Geschossdecke
Tragwerk - Filter Tragend / Nichttragend: yes
Pset_SlabCommon - IsExternal: no

# IfcSlabType, no part of this type: Geschossdecke:STB 200 Stone Steps
PredefinedType: FLOOR; Material: Fußboden - Estrich 0.2 m
Analytische Eigenschaften - Rauigkeit: 1; Absorptionsgrad: 0.1
Grafiken - Füllmuster für groben Maßstab: <Flächenfüllung>; Farbfüllung für groben Maßstab: 32768
ID-Daten - Bauelement: 50.A9; Beschreibung: STB_200; Typname: STB 200 Stone Steps
Konstruktion - Funktion: Innen; Standarddicke: 0.2 m
Sonstige - Kategorie: Geschossdecken; Familienname: Geschossdecke
Tragwerk - Filter Tragend / Nichttragend: yes
Pset_SlabCommon - IsExternal: no

# IfcSlabType, no part of this type: Geschossdecke:STB 200 Stone Steps
PredefinedType: FLOOR; Material: Fußboden - Estrich 0.2 m
Analytische Eigenschaften - Rauigkeit: 1; Absorptionsgrad: 0.1
Grafiken - Füllmuster für groben Maßstab: <Flächenfüllung>; Farbfüllung für groben Maßstab: 32768
ID-Daten - Bauelement: 50.A9; Beschreibung: STB_200; Typname: STB 200 Stone Steps
Konstruktion - Funktion: Innen; Standarddicke: 0.2 m
Sonstige - Kategorie: Geschossdecken; Familienname: Geschossdecke
Tragwerk - Filter Tragend / Nichttragend: yes
Pset_SlabCommon - IsExternal: no

# IfcSlabType, no part of this type: Geschossdecke:STB 200 Stone Steps
PredefinedType: FLOOR; Material: Fußboden - Estrich 0.2 m
Analytische Eigenschaften - Rauigkeit: 1; Absorptionsgrad: 0.1
Grafiken - Füllmuster für groben Maßstab: <Flächenfüllung>; Farbfüllung für groben Maßstab: 32768
ID-Daten - Bauelement: 50.A9; Beschreibung: STB_200; Typname: STB 200 Stone Steps
Konstruktion - Funktion: Innen; Standarddicke: 0.2 m
Sonstige - Kategorie: Geschossdecken; Familienname: Geschossdecke
Tragwerk - Filter Tragend / Nichttragend: yes
Pset_SlabCommon - IsExternal: no

# IfcSlabType, no part of this type: Geschossdecke:STB 200 Stone Steps
PredefinedType: FLOOR; Material: Fußboden - Estrich 0.2 m
Analytische Eigenschaften - Rauigkeit: 1; Absorptionsgrad: 0.1
Grafiken - Füllmuster für groben Maßstab: <Flächenfüllung>; Farbfüllung für groben Maßstab: 32768
ID-Daten - Bauelement: 50.A9; Beschreibung: STB_200; Typname: STB 200 Stone Steps
Konstruktion - Funktion: Innen; Standarddicke: 0.2 m
Sonstige - Kategorie: Geschossdecken; Familienname: Geschossdecke
Tragwerk - Filter Tragend / Nichttragend: yes
Pset_SlabCommon - IsExternal: no

# IfcSlabType, no part of this type: Geschossdecke:STB 250
PredefinedType: FLOOR; Material: Ortbeton - bewehrt 0.25 m
Analytische Eigenschaften - Rauigkeit: 1; Absorptionsgrad: 0.1; Thermischer Widerstand (R): 0.239006; Thermisch wirksame Masse: 377.775; Wärmedurchgangskoeffizient (U): 4.184 kg/K/s3
Grafiken - Füllmuster für groben Maßstab: <Flächenfüllung>; Farbfüllung für groben Maßstab: 32768
ID-Daten - Beschreibung: STB_250; Typname: STB 250
Konstruktion - Funktion: Innen; Standarddicke: 0.25 m
Materialien und Oberflächen - Tragendes Material: Ortbeton - bewehrt
Sonstige - Kategorie: Geschossdecken; Familienname: Geschossdecke
Tragwerk - Filter Tragend / Nichttragend: yes
Pset_SlabCommon - IsExternal: no; ThermalTransmittance: 4.184 kg/K/s3

# IfcSlabType, no part of this type: Geschossdecke:STB 250 concrete
PredefinedType: FLOOR; Material: Ortbeton - unbewehrt 0.25 m
Analytische Eigenschaften - Rauigkeit: 1; Absorptionsgrad: 0.1
Grafiken - Füllmuster für groben Maßstab: <Flächenfüllung>; Farbfüllung für groben Maßstab: 32768
ID-Daten - Bauelement: 50.A9; Beschreibung: STB_200; Typname: STB 250 concrete
Konstruktion - Funktion: Innen; Standarddicke: 0.25 m
Sonstige - Kategorie: Geschossdecken; Familienname: Geschossdecke
Tragwerk - Filter Tragend / Nichttragend: yes
Pset_SlabCommon - IsExternal: no

# IfcSlabType, no part of this type: Geschossdecke:STB 40
PredefinedType: FLOOR; Material: Ortbeton - bewehrt 0.04 m
Analytische Eigenschaften - Rauigkeit: 1; Absorptionsgrad: 0.1; Thermischer Widerstand (R): 0.0382409; Thermisch wirksame Masse: 60.444; Wärmedurchgangskoeffizient (U): 26.15 kg/K/s3
Grafiken - Füllmuster für groben Maßstab: <Flächenfüllung>; Farbfüllung für groben Maßstab: 32768
ID-Daten - Bauelement: 50.A9; Beschreibung: STB_200; Typname: STB 40
Konstruktion - Funktion: Innen; Standarddicke: 0.04 m
Materialien und Oberflächen - Tragendes Material: Ortbeton - bewehrt
Sonstige - Kategorie: Geschossdecken; Familienname: Geschossdecke
Tragwerk - Filter Tragend / Nichttragend: yes
Pset_SlabCommon - IsExternal: no; ThermalTransmittance: 26.15 kg/K/s3

# IfcSlabType, no part of this type: Geschossdecke:STB 50
PredefinedType: FLOOR; Material: Ortbeton - bewehrt 0.05 m
Analytische Eigenschaften - Rauigkeit: 1; Absorptionsgrad: 0.1; Thermischer Widerstand (R): 0.0478011; Thermisch wirksame Masse: 75.555; Wärmedurchgangskoeffizient (U): 20.92 kg/K/s3
Grafiken - Füllmuster für groben Maßstab: <Flächenfüllung>; Farbfüllung für groben Maßstab: 32768
ID-Daten - Bauelement: 50.A9; Beschreibung: STB_200; Typname: STB 50
Konstruktion - Funktion: Innen; Standarddicke: 0.05 m
Materialien und Oberflächen - Tragendes Material: Ortbeton - bewehrt
Sonstige - Kategorie: Geschossdecken; Familienname: Geschossdecke
Tragwerk - Filter Tragend / Nichttragend: yes
Pset_SlabCommon - IsExternal: no; ThermalTransmittance: 20.92 kg/K/s3

# IfcSlabType, no part of this type: Geschossdecke:STB 50
PredefinedType: FLOOR; Material: Ortbeton - bewehrt 0.05 m
Analytische Eigenschaften - Rauigkeit: 1; Absorptionsgrad: 0.1; Thermischer Widerstand (R): 0.0478011; Thermisch wirksame Masse: 75.555; Wärmedurchgangskoeffizient (U): 20.92 kg/K/s3
Grafiken - Füllmuster für groben Maßstab: <Flächenfüllung>; Farbfüllung für groben Maßstab: 32768
ID-Daten - Bauelement: 50.A9; Beschreibung: STB_200; Typname: STB 50
Konstruktion - Funktion: Innen; Standarddicke: 0.05 m
Materialien und Oberflächen - Tragendes Material: Ortbeton - bewehrt
Sonstige - Kategorie: Geschossdecken; Familienname: Geschossdecke
Tragwerk - Filter Tragend / Nichttragend: yes
Pset_SlabCommon - IsExternal: no; ThermalTransmittance: 20.92 kg/K/s3

# IfcSlabType, no part of this type: Geschossdecke:STB 50
PredefinedType: FLOOR; Material: Ortbeton - bewehrt 0.05 m
Analytische Eigenschaften - Rauigkeit: 1; Absorptionsgrad: 0.1; Thermischer Widerstand (R): 0.0478011; Thermisch wirksame Masse: 75.555; Wärmedurchgangskoeffizient (U): 20.92 kg/K/s3
Grafiken - Füllmuster für groben Maßstab: <Flächenfüllung>; Farbfüllung für groben Maßstab: 32768
ID-Daten - Bauelement: 50.A9; Beschreibung: STB_200; Typname: STB 50
Konstruktion - Funktion: Innen; Standarddicke: 0.05 m
Materialien und Oberflächen - Tragendes Material: Ortbeton - bewehrt
Sonstige - Kategorie: Geschossdecken; Familienname: Geschossdecke
Tragwerk - Filter Tragend / Nichttragend: yes
Pset_SlabCommon - IsExternal: no; ThermalTransmittance: 20.92 kg/K/s3

# IfcSlabType, no part of this type: Geschossdecke:STB 855 200 Fill
PredefinedType: FLOOR; Material: Ortbeton - unbewehrt 0.2 m, Fußboden - Schüttung 0.9 m
Analytische Eigenschaften - Rauigkeit: 1; Absorptionsgrad: 0.1; Thermischer Widerstand (R): 2.5; Thermisch wirksame Masse: 1391.04; Wärmedurchgangskoeffizient (U): 0.4 kg/K/s3
Grafiken - Füllmuster für groben Maßstab: <Flächenfüllung>; Farbfüllung für groben Maßstab: 32768
ID-Daten - Bauelement: 50.A9; Beschreibung: STB_200; Typname: STB 855 200 Fill
Konstruktion - Funktion: Innen; Standarddicke: 1.1 m
Materialien und Oberflächen - Tragendes Material: Ortbeton - unbewehrt
Sonstige - Kategorie: Geschossdecken; Familienname: Geschossdecke
Tragwerk - Filter Tragend / Nichttragend: yes
Pset_SlabCommon - IsExternal: no; ThermalTransmittance: 0.4 kg/K/s3

# IfcSlabType, no part of this type: Geschossdecke:STB 885 200 Fill
PredefinedType: FLOOR; Material: Ortbeton - unbewehrt 0.2 m, Fußboden - Schüttung 0.685 m
Analytische Eigenschaften - Rauigkeit: 1; Absorptionsgrad: 0.1; Thermischer Widerstand (R): 1.90278; Thermisch wirksame Masse: 1058.74; Wärmedurchgangskoeffizient (U): 0.525547 kg/K/s3
Grafiken - Füllmuster für groben Maßstab: <Flächenfüllung>; Farbfüllung für groben Maßstab: 32768
ID-Daten - Bauelement: 50.A9; Beschreibung: STB_200; Typname: STB 885 200 Fill
Konstruktion - Funktion: Innen; Standarddicke: 0.885 m
Materialien und Oberflächen - Tragendes Material: Ortbeton - unbewehrt
Sonstige - Kategorie: Geschossdecken; Familienname: Geschossdecke
Tragwerk - Filter Tragend / Nichttragend: yes
Pset_SlabCommon - IsExternal: no; ThermalTransmittance: 0.525547 kg/K/s3

# IfcSlabType, no part of this type: Geschossdecke:SacristyFill
PredefinedType: FLOOR; Material: Fußboden - Schüttung 0.4 m
Analytische Eigenschaften - Rauigkeit: 1; Absorptionsgrad: 0.1; Thermischer Widerstand (R): 1.11111; Thermisch wirksame Masse: 618.24; Wärmedurchgangskoeffizient (U): 0.9 kg/K/s3
Grafiken - Füllmuster für groben Maßstab: <Flächenfüllung>; Farbfüllung für groben Maßstab: 32768
ID-Daten - Bauelement: 50.A9; Beschreibung: STB_200; Typname: SacristyFill
Konstruktion - Funktion: Innen; Standarddicke: 0.4 m
Sonstige - Kategorie: Geschossdecken; Familienname: Geschossdecke
Tragwerk - Filter Tragend / Nichttragend: yes
Pset_SlabCommon - IsExternal: no; ThermalTransmittance: 0.9 kg/K/s3

# IfcSlabType, no part of this type: Geschossdecke:SacristyFill 150
PredefinedType: FLOOR; Material: Fußboden - Schüttung 0.15 m
Analytische Eigenschaften - Rauigkeit: 1; Absorptionsgrad: 0.1; Thermischer Widerstand (R): 0.416667; Thermisch wirksame Masse: 231.84; Wärmedurchgangskoeffizient (U): 2.4 kg/K/s3
Grafiken - Füllmuster für groben Maßstab: <Flächenfüllung>; Farbfüllung für groben Maßstab: 32768
ID-Daten - Bauelement: 50.A9; Beschreibung: STB_200; Typname: SacristyFill 150
Konstruktion - Funktion: Innen; Standarddicke: 0.15 m
Sonstige - Kategorie: Geschossdecken; Familienname: Geschossdecke
Tragwerk - Filter Tragend / Nichttragend: yes
Pset_SlabCommon - IsExternal: no; ThermalTransmittance: 2.4 kg/K/s3

# IfcSlabType, no part of this type: Geschossdecke:Tiled 170x170 mosaik black
PredefinedType: FLOOR; Material: Fußboden - mosaik 170x170 0.03 m, Fußboden - Estrich 0.07 m
Analytische Eigenschaften - Rauigkeit: 1; Absorptionsgrad: 0.1
Grafiken - Füllmuster für groben Maßstab: <Flächenfüllung>; Farbfüllung für groben Maßstab: 32768
ID-Daten - Bauelement: 50.A9; Typname: Tiled 170x170 mosaik black
Konstruktion - Funktion: Innen; Standarddicke: 0.1 m
Sonstige - Kategorie: Geschossdecken; Familienname: Geschossdecke
Tragwerk - Filter Tragend / Nichttragend: yes
Pset_SlabCommon - IsExternal: no

# IfcSlabType, no part of this type: Geschossdecke:Tiled ceramic 150x150 BW Mosaik surround
PredefinedType: FLOOR; Material: Fußboden - Fliesen 2farbig 150x150 BW mosaik surround 0.012 m, Fußboden - Schüttung 0.3 m
Analytische Eigenschaften - Rauigkeit: 1; Absorptionsgrad: 0.1; Thermischer Widerstand (R): 0.833333; Thermisch wirksame Masse: 463.68; Wärmedurchgangskoeffizient (U): 1.2 kg/K/s3
Grafiken - Füllmuster für groben Maßstab: <Flächenfüllung>; Farbfüllung für groben Maßstab: 32768
ID-Daten - Bauelement: 50.A9; Typname: Tiled ceramic 150x150 BW Mosaik surround
Konstruktion - Funktion: Innen; Standarddicke: 0.312 m
Sonstige - Kategorie: Geschossdecken; Familienname: Geschossdecke
Tragwerk - Filter Tragend / Nichttragend: yes
Pset_SlabCommon - IsExternal: no; ThermalTransmittance: 1.2 kg/K/s3

# IfcSlabType, no part of this type: Geschossdecke:Tiled ceramic 170x170 BW Mosaik kreisformig Stage 2
PredefinedType: FLOOR
Analytische Eigenschaften - Rauigkeit: 1; Absorptionsgrad: 0.1; Thermischer Widerstand (R): 0.833333; Thermisch wirksame Masse: 463.68; Wärmedurchgangskoeffizient (U): 1.2 kg/K/s3
Grafiken - Füllmuster für groben Maßstab: <Flächenfüllung>; Farbfüllung für groben Maßstab: 32768
ID-Daten - Bauelement: 50.A9; Typname: Tiled ceramic 170x170 BW Mosaik kreisformig Stage 2
Konstruktion - Funktion: Innen; Standarddicke: 0.312 m
Sonstige - Kategorie: Geschossdecken; Familienname: Geschossdecke
Tragwerk - Filter Tragend / Nichttragend: yes
Pset_SlabCommon - IsExternal: no; ThermalTransmittance: 1.2 kg/K/s3

# IfcSlabType, no part of this type: Geschossdecke:Tiled ceramic 170x170 BW Mosaik kreisformig Stage 2
PredefinedType: FLOOR
Analytische Eigenschaften - Rauigkeit: 1; Absorptionsgrad: 0.1; Thermischer Widerstand (R): 0.833333; Thermisch wirksame Masse: 463.68; Wärmedurchgangskoeffizient (U): 1.2 kg/K/s3
Grafiken - Füllmuster für groben Maßstab: <Flächenfüllung>; Farbfüllung für groben Maßstab: 32768
ID-Daten - Bauelement: 50.A9; Typname: Tiled ceramic 170x170 BW Mosaik kreisformig Stage 2
Konstruktion - Funktion: Innen; Standarddicke: 0.312 m
Sonstige - Kategorie: Geschossdecken; Familienname: Geschossdecke
Tragwerk - Filter Tragend / Nichttragend: yes
Pset_SlabCommon - IsExternal: no; ThermalTransmittance: 1.2 kg/K/s3

# IfcSlabType, no part of this type: Geschossdecke:Tiled ceramic 170x170 BW Mosaik kreisformig Stage 2
PredefinedType: FLOOR; Material: Fußboden - Fliesen 2farbig 170x170 BW mosaik 0.012 m, Fußboden - Schüttung 0.3 m
Analytische Eigenschaften - Rauigkeit: 1; Absorptionsgrad: 0.1; Thermischer Widerstand (R): 0.833333; Thermisch wirksame Masse: 463.68; Wärmedurchgangskoeffizient (U): 1.2 kg/K/s3
Grafiken - Füllmuster für groben Maßstab: <Flächenfüllung>; Farbfüllung für groben Maßstab: 32768
ID-Daten - Bauelement: 50.A9; Typname: Tiled ceramic 170x170 BW Mosaik kreisformig Stage 2
Konstruktion - Funktion: Innen; Standarddicke: 0.312 m
Sonstige - Kategorie: Geschossdecken; Familienname: Geschossdecke
Tragwerk - Filter Tragend / Nichttragend: yes
Pset_SlabCommon - IsExternal: no; ThermalTransmittance: 1.2 kg/K/s3

# IfcSlabType, no part of this type: Geschossdecke:Tiled ceramic 170x170 BW Mosaik kreisformig Stage 2 border
PredefinedType: FLOOR; Material: Fußboden - Fliesen 2farbig 170x170 BW border 0.012 m, Fußboden - Schüttung 0.3 m
Analytische Eigenschaften - Rauigkeit: 1; Absorptionsgrad: 0.1; Thermischer Widerstand (R): 0.833333; Thermisch wirksame Masse: 463.68; Wärmedurchgangskoeffizient (U): 1.2 kg/K/s3
Grafiken - Füllmuster für groben Maßstab: <Flächenfüllung>; Farbfüllung für groben Maßstab: 32768
ID-Daten - Bauelement: 50.A9; Typname: Tiled ceramic 170x170 BW Mosaik kreisformig Stage 2 border
Konstruktion - Funktion: Innen; Standarddicke: 0.312 m
Sonstige - Kategorie: Geschossdecken; Familienname: Geschossdecke
Tragwerk - Filter Tragend / Nichttragend: yes
Pset_SlabCommon - IsExternal: no; ThermalTransmittance: 1.2 kg/K/s3

# IfcStairFlightType, no part of this type: Massivtreppenlauf:Naturstein - Auftritt 40 / Trittüberstand 30
PredefinedType: STRAIGHT
Auftritte - Auftritt: yes; Auftrittshöhe: 0.04 m; Trittüberstandprofil anwenden: Nur vorn; Trittüberstandslänge: 0 m
ID-Daten - Typenkommentare: Naturstein_Auftritt + Trittüberstand_40+30; Typname: Naturstein - Auftritt 40 / Trittüberstand 30
Konstruktion - Konstruktionstiefe: 0.18 m; Oberfläche von Unterseite: Glatt
Materialien und Oberflächen - Auftrittsmaterial: Ortbeton - bewehrt; Material Massivtreppe: Ortbeton - bewehrt Verputzt
Sonstige - Kategorie: Treppen: Läufe; Familienname: Massivtreppenlauf
Steigungen - Geneigt: no; Steigung: no; Steigungsdicke: 0 m; Verbindung Steigung zu Auftritt: Steigung hinter Auftritt erweitern

# IfcWallType, no part of this type: Basiswand:90 Holz
PredefinedType: STANDARD; Material: Holz - Painted 0.09 m
Analytische Eigenschaften - Rauigkeit: 1; Absorptionsgrad: 0.1; Thermischer Widerstand (R): 0.849057; Thermisch wirksame Masse: 70.5456; Wärmedurchgangskoeffizient (U): 1.17778 kg/K/s3
Grafiken - Füllmuster für groben Maßstab: <Flächenfüllung>; Farbfüllung für groben Maßstab: 255
ID-Daten - Beschreibung: Ziegel_120; Typname: 90 Holz
Konstruktion - Funktion: Außen; Abschluss an Öffnungen: Keine; Abschluss an Wänden: Außen; Breite: 0.09 m
Sonstige - Kategorie: Wände; Familienname: Basiswand
Tragwerk - Filter Tragend / Nichttragend: no
Pset_WallCommon - IsExternal: yes; ThermalTransmittance: 1.17778 kg/K/s3

# IfcWallType, no part of this type: Basiswand:Backstein 3300 Basement Foundation Wall 2
PredefinedType: STANDARD; Material: Mauerwerk - Sichtmauerwerk_72x265 english bond Stage2 0.33 m
Analytische Eigenschaften - Rauigkeit: 1; Absorptionsgrad: 0.1; Thermischer Widerstand (R): 0.611111; Thermisch wirksame Masse: 429.66; Wärmedurchgangskoeffizient (U): 1.63636 kg/K/s3
Grafiken - Füllmuster für groben Maßstab: _Diagonal 45° 1.0mm; Farbfüllung für groben Maßstab: 255
ID-Daten - Beschreibung: Ziegel_380; Typname: Backstein 3300 Basement Foundation Wall 2
Konstruktion - Abschluss an Wänden: Keine; Funktion: Außen; Abschluss an Öffnungen: Keine; Breite: 0.33 m
Sonstige - Kategorie: Wände; Familienname: Basiswand
Tragwerk - Filter Tragend / Nichttragend: yes
Pset_WallCommon - IsExternal: yes; ThermalTransmittance: 1.63636 kg/K/s3

# IfcWallType, no part of this type: Basiswand:Backstein 710 Office Pier Foundation Wall
PredefinedType: STANDARD; Material: Mauerwerk - Sichtmauerwerk_72x265 english bond Stage2 0.71 m
Analytische Eigenschaften - Rauigkeit: 1; Absorptionsgrad: 0.1; Thermischer Widerstand (R): 1.31481; Thermisch wirksame Masse: 924.42; Wärmedurchgangskoeffizient (U): 0.760563 kg/K/s3
Grafiken - Füllmuster für groben Maßstab: _Diagonal 45° 1.0mm; Farbfüllung für groben Maßstab: 255
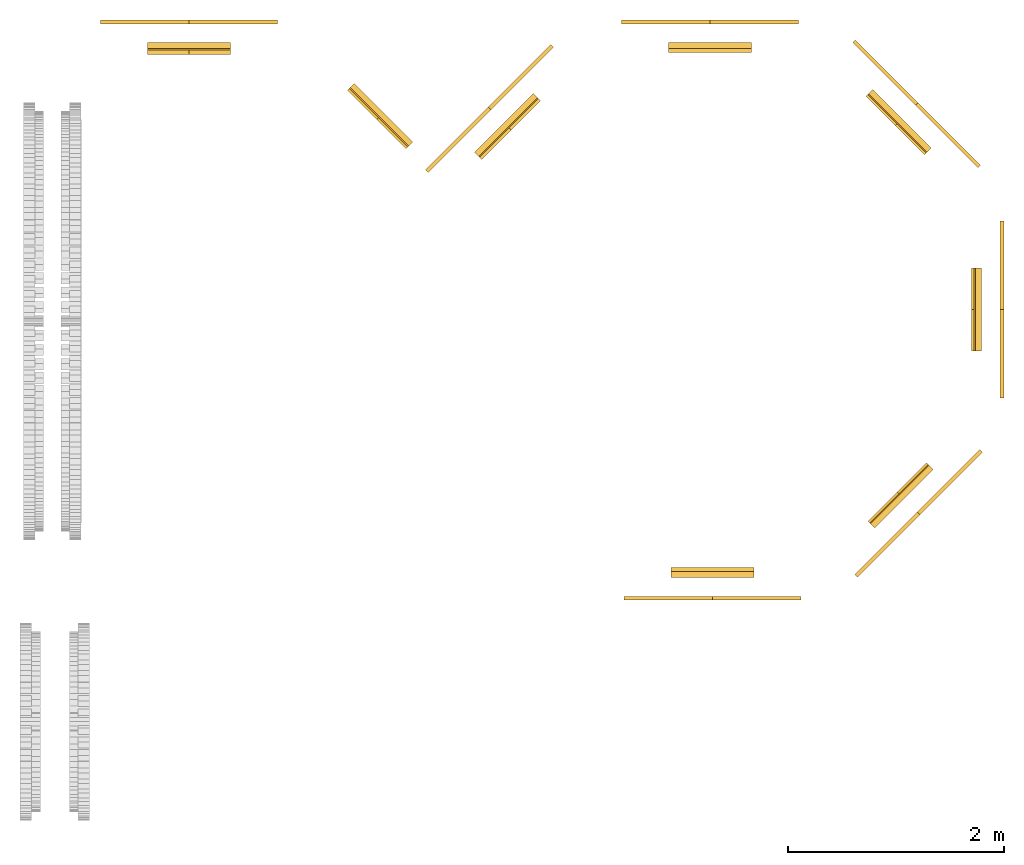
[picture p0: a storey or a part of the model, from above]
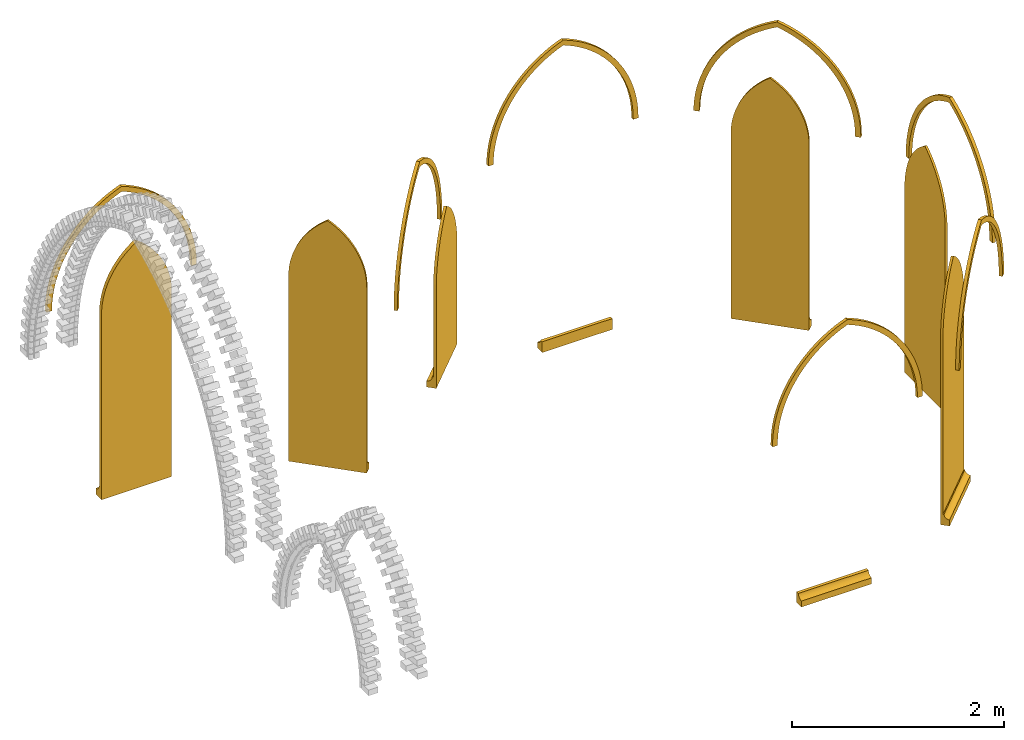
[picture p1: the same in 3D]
Properties of the parts of a building model (IFC2X3), part 6 of 7

# IfcWallType, no part of this type: Basiswand:Backstein 710 Office Pier Foundation Wall
ID-Daten - Beschreibung: Ziegel_380; Typname: Backstein 710 Office Pier Foundation Wall
Konstruktion - Abschluss an Wänden: Keine; Funktion: Außen; Abschluss an Öffnungen: Keine; Breite: 0.71 m
Sonstige - Kategorie: Wände; Familienname: Basiswand
Tragwerk - Filter Tragend / Nichttragend: yes
Pset_WallCommon - IsExternal: yes; ThermalTransmittance: 0.760563 kg/K/s3

# IfcWallType, no part of this type: Basiswand:Backstein 846 Foundation Wall
PredefinedType: STANDARD; Material: Mauerwerk - Sichtmauerwerk_72x265 english bond Stage2 0.846 m
Analytische Eigenschaften - Rauigkeit: 1; Absorptionsgrad: 0.1; Thermischer Widerstand (R): 1.56667; Thermisch wirksame Masse: 1101.49; Wärmedurchgangskoeffizient (U): 0.638298 kg/K/s3
Grafiken - Füllmuster für groben Maßstab: _Diagonal 45° 1.0mm; Farbfüllung für groben Maßstab: 255
ID-Daten - Beschreibung: Ziegel_380; Typname: Backstein 846 Foundation Wall
Konstruktion - Abschluss an Wänden: Keine; Funktion: Außen; Abschluss an Öffnungen: Keine; Breite: 0.846 m
Sonstige - Kategorie: Wände; Familienname: Basiswand
Tragwerk - Filter Tragend / Nichttragend: yes
Pset_WallCommon - IsExternal: yes; ThermalTransmittance: 0.638298 kg/K/s3

# IfcWallType, no part of this type: Basiswand:Farbe 1 stencil frieze
PredefinedType: STANDARD; Material: Mauerwerk - Decoration 1 Stencil FRIEZE Horizontal 0.001 m
Analytische Eigenschaften - Rauigkeit: 1; Absorptionsgrad: 0.1; Thermischer Widerstand (R): 0.00185185; Thermisch wirksame Masse: 1.302; Wärmedurchgangskoeffizient (U): 540 kg/K/s3
Grafiken - Füllmuster für groben Maßstab: <Flächenfüllung>; Farbfüllung für groben Maßstab: 255
ID-Daten - Beschreibung: Kalksandstein_115; Typname: Farbe 1 stencil frieze
Konstruktion - Abschluss an Wänden: Keine; Abschluss an Öffnungen: Keine; Funktion: Innen; Breite: 0.001 m
Sonstige - Kategorie: Wände; Familienname: Basiswand
Tragwerk - Filter Tragend / Nichttragend: no
Pset_WallCommon - IsExternal: no; ThermalTransmittance: 540 kg/K/s3

# IfcWallType, no part of this type: Basiswand:Farbe 1 stencil lower
PredefinedType: STANDARD; Material: Mauerwerk - Decoration 1 Stencil LOWER 0.001 m
Analytische Eigenschaften - Rauigkeit: 1; Absorptionsgrad: 0.1; Thermischer Widerstand (R): 0.00185185; Thermisch wirksame Masse: 1.302; Wärmedurchgangskoeffizient (U): 540 kg/K/s3
Grafiken - Füllmuster für groben Maßstab: <Flächenfüllung>; Farbfüllung für groben Maßstab: 255
ID-Daten - Beschreibung: Kalksandstein_115; Typname: Farbe 1 stencil lower
Konstruktion - Abschluss an Wänden: Keine; Abschluss an Öffnungen: Keine; Funktion: Innen; Breite: 0.001 m
Sonstige - Kategorie: Wände; Familienname: Basiswand
Tragwerk - Filter Tragend / Nichttragend: no
Pset_WallCommon - IsExternal: no; ThermalTransmittance: 540 kg/K/s3

# IfcWallType, no part of this type: Basiswand:Farbe 2 dado
PredefinedType: STANDARD; Material: Mauerwerk - Decoration 1 plain Painted 0.001 m
Analytische Eigenschaften - Rauigkeit: 1; Absorptionsgrad: 0.1; Thermischer Widerstand (R): 0.00185185; Thermisch wirksame Masse: 1.302; Wärmedurchgangskoeffizient (U): 540 kg/K/s3
Grafiken - Füllmuster für groben Maßstab: <Flächenfüllung>; Farbfüllung für groben Maßstab: 255
ID-Daten - Beschreibung: Kalksandstein_115; Typname: Farbe 2 dado
Konstruktion - Abschluss an Wänden: Keine; Abschluss an Öffnungen: Keine; Funktion: Innen; Breite: 0.001 m
Sonstige - Kategorie: Wände; Familienname: Basiswand
Tragwerk - Filter Tragend / Nichttragend: no
Pset_WallCommon - IsExternal: no; ThermalTransmittance: 540 kg/K/s3

# IfcWallType, no part of this type: Basiswand:GK 100
PredefinedType: STANDARD; Material: Trockenbau - Gipsplatte 0.0125 m, Dämmung - weich 0.075 m, Trockenbau - Gipsplatte 0.0125 m
Analytische Eigenschaften - Rauigkeit: 1; Absorptionsgrad: 0.1; Thermischer Widerstand (R): 2.24434; Thermisch wirksame Masse: 33.75; Wärmedurchgangskoeffizient (U): 0.445565 kg/K/s3
Grafiken - Füllmuster für groben Maßstab: <Flächenfüllung>; Farbfüllung für groben Maßstab: 11894858
ID-Daten - Beschreibung: GK_100; Typname: GK 100
Konstruktion - Abschluss an Öffnungen: Keine; Abschluss an Wänden: Außen; Funktion: Innen; Breite: 0.1 m
Materialien und Oberflächen - Tragendes Material: Dämmung - weich
Sonstige - Kategorie: Wände; Familienname: Basiswand
Tragwerk - Filter Tragend / Nichttragend: no
Pset_WallCommon - IsExternal: no; ThermalTransmittance: 0.445565 kg/K/s3

# IfcWallType, no part of this type: Basiswand:Glass15Stained-1864
PredefinedType: STANDARD; Material: Glas - Baustein 0.015 m
Analytische Eigenschaften - Rauigkeit: 1; Absorptionsgrad: 0.1; Thermischer Widerstand (R): 0.0666667; Thermisch wirksame Masse: 11.781; Wärmedurchgangskoeffizient (U): 15 kg/K/s3
Grafiken - Füllmuster für groben Maßstab: <Flächenfüllung>; Farbfüllung für groben Maßstab: 255
ID-Daten - Beschreibung: Kalksandstein_115; Typname: Glass15Stained-1864
Konstruktion - Abschluss an Wänden: Keine; Abschluss an Öffnungen: Keine; Funktion: Innen; Breite: 0.015 m
Sonstige - Kategorie: Wände; Familienname: Basiswand
Tragwerk - Filter Tragend / Nichttragend: no
Pset_WallCommon - IsExternal: no; ThermalTransmittance: 15 kg/K/s3

# IfcWallType, no part of this type: Basiswand:KS 280
PredefinedType: STANDARD; Material: Mauerwerk - Kalkputz-white 0.02 m, Mauerwerk - Kalksandstein 0.24 m, Mauerwerk - Kalkputz-white 0.02 m
Analytische Eigenschaften - Rauigkeit: 1; Absorptionsgrad: 0.1; Thermischer Widerstand (R): 0.0965517; Thermisch wirksame Masse: 646.8; Wärmedurchgangskoeffizient (U): 10.3571 kg/K/s3
Grafiken - Füllmuster für groben Maßstab: <Flächenfüllung>; Farbfüllung für groben Maßstab: 255
ID-Daten - Beschreibung: Kalksandstein_240; Typname: KS 280
Konstruktion - Abschluss an Wänden: Keine; Abschluss an Öffnungen: Keine; Funktion: Innen; Breite: 0.28 m
Materialien und Oberflächen - Tragendes Material: Mauerwerk - Kalksandstein
Sonstige - Kategorie: Wände; Familienname: Basiswand
Tragwerk - Filter Tragend / Nichttragend: no
Pset_WallCommon - IsExternal: no; ThermalTransmittance: 10.3571 kg/K/s3

# IfcWallType, no part of this type: Basiswand:KS 51
PredefinedType: STANDARD; Material: Mauerwerk - Kalksandstein 0.051 m
Analytische Eigenschaften - Rauigkeit: 1; Absorptionsgrad: 0.1; Thermischer Widerstand (R): 0.0175862; Thermisch wirksame Masse: 117.81; Wärmedurchgangskoeffizient (U): 56.8627 kg/K/s3
Grafiken - Füllmuster für groben Maßstab: <Flächenfüllung>; Farbfüllung für groben Maßstab: 255
ID-Daten - Beschreibung: Kalksandstein_115; Typname: KS 51
Konstruktion - Abschluss an Wänden: Keine; Abschluss an Öffnungen: Keine; Funktion: Innen; Breite: 0.051 m
Materialien und Oberflächen - Tragendes Material: Mauerwerk - Kalksandstein
Sonstige - Kategorie: Wände; Familienname: Basiswand
Tragwerk - Filter Tragend / Nichttragend: no
Pset_WallCommon - IsExternal: no; ThermalTransmittance: 56.8627 kg/K/s3

# IfcWallType, no part of this type: Basiswand:Naturstein 1020 Foundation Wall Stage 2
PredefinedType: STANDARD; Material: Mauerwerk - Kalkputz-white 0.02 m, Mauerwerk - Sandstein Rot 1 m, Mauerwerk - Kalkputz-white 0.02 m
Analytische Eigenschaften - Rauigkeit: 1; Absorptionsgrad: 0.1; Thermischer Widerstand (R): 0.358621; Thermisch wirksame Masse: 2402.4; Wärmedurchgangskoeffizient (U): 2.78846 kg/K/s3
Grafiken - Füllmuster für groben Maßstab: _Diagonal 45° 1.0mm; Farbfüllung für groben Maßstab: 255
ID-Daten - Beschreibung: Ziegel_380; Typname: Naturstein 1020 Foundation Wall Stage 2
Konstruktion - Abschluss an Öffnungen: Beide; Abschluss an Wänden: Keine; Funktion: Außen; Breite: 1.04 m
Sonstige - Kategorie: Wände; Familienname: Basiswand
Tragwerk - Filter Tragend / Nichttragend: yes
Pset_WallCommon - IsExternal: yes; ThermalTransmittance: 2.78846 kg/K/s3

# IfcWallType, no part of this type: Basiswand:Naturstein 1060 Foundation Wall 2
PredefinedType: STANDARD; Material: Mauerwerk - Sandstein Rot 1.06 m
Analytische Eigenschaften - Rauigkeit: 1; Absorptionsgrad: 0.1; Thermischer Widerstand (R): 0.365517; Thermisch wirksame Masse: 2448.6; Wärmedurchgangskoeffizient (U): 2.73585 kg/K/s3
Grafiken - Füllmuster für groben Maßstab: _Diagonal 45° 1.0mm; Farbfüllung für groben Maßstab: 255
ID-Daten - Beschreibung: Ziegel_380; Typname: Naturstein 1060 Foundation Wall 2
Konstruktion - Abschluss an Wänden: Keine; Funktion: Außen; Abschluss an Öffnungen: Keine; Breite: 1.06 m
Sonstige - Kategorie: Wände; Familienname: Basiswand
Tragwerk - Filter Tragend / Nichttragend: yes
Pset_WallCommon - IsExternal: yes; ThermalTransmittance: 2.73585 kg/K/s3

# IfcWallType, no part of this type: Basiswand:Naturstein 1090 Main Pier Foundation Wall
PredefinedType: STANDARD; Material: Mauerwerk - Sandstein Rot 1.09 m
Analytische Eigenschaften - Rauigkeit: 1; Absorptionsgrad: 0.1; Thermischer Widerstand (R): 0.375862; Thermisch wirksame Masse: 2517.9; Wärmedurchgangskoeffizient (U): 2.66055 kg/K/s3
Grafiken - Füllmuster für groben Maßstab: _Diagonal 45° 1.0mm; Farbfüllung für groben Maßstab: 255
ID-Daten - Beschreibung: Ziegel_380; Typname: Naturstein 1090 Main Pier Foundation Wall
Konstruktion - Abschluss an Wänden: Keine; Funktion: Außen; Abschluss an Öffnungen: Keine; Breite: 1.09 m
Sonstige - Kategorie: Wände; Familienname: Basiswand
Tragwerk - Filter Tragend / Nichttragend: yes
Pset_WallCommon - IsExternal: yes; ThermalTransmittance: 2.66055 kg/K/s3

# IfcWallType, no part of this type: Basiswand:Naturstein 1090 Main Pier Foundation Wall Copy
PredefinedType: STANDARD; Material: Mauerwerk - Sandstein Rot 1.09 m
Analytische Eigenschaften - Rauigkeit: 1; Absorptionsgrad: 0.1; Thermischer Widerstand (R): 0.375862; Thermisch wirksame Masse: 2517.9; Wärmedurchgangskoeffizient (U): 2.66055 kg/K/s3
Grafiken - Füllmuster für groben Maßstab: _Diagonal 45° 1.0mm; Farbfüllung für groben Maßstab: 255
ID-Daten - Beschreibung: Ziegel_380; Typname: Naturstein 1090 Main Pier Foundation Wall
Konstruktion - Abschluss an Wänden: Keine; Funktion: Außen; Abschluss an Öffnungen: Keine; Breite: 1.09 m
Sonstige - Kategorie: Wände; Familienname: Basiswand
Tragwerk - Filter Tragend / Nichttragend: yes
Pset_WallCommon - IsExternal: yes; ThermalTransmittance: 2.66055 kg/K/s3

# IfcWallType, no part of this type: Basiswand:Naturstein 240
PredefinedType: STANDARD; Material: Mauerwerk - Sandstein Rot 0.24 m
Analytische Eigenschaften - Rauigkeit: 1; Absorptionsgrad: 0.1; Thermischer Widerstand (R): 0.0827586; Thermisch wirksame Masse: 554.4; Wärmedurchgangskoeffizient (U): 12.0833 kg/K/s3
Grafiken - Füllmuster für groben Maßstab: <Flächenfüllung>; Farbfüllung für groben Maßstab: 255
ID-Daten - Beschreibung: Ziegel_240; Typname: Naturstein 240
Konstruktion - Abschluss an Wänden: Keine; Abschluss an Öffnungen: Keine; Funktion: Innen; Breite: 0.24 m
Materialien und Oberflächen - Tragendes Material: Mauerwerk - Sandstein Rot
Sonstige - Kategorie: Wände; Familienname: Basiswand
Tragwerk - Filter Tragend / Nichttragend: yes
Pset_WallCommon - IsExternal: no; ThermalTransmittance: 12.0833 kg/K/s3

# IfcWallType, no part of this type: Basiswand:Naturstein 425
PredefinedType: STANDARD; Material: Mauerwerk - Sandstein Rot 0.425 m
Analytische Eigenschaften - Rauigkeit: 1; Absorptionsgrad: 0.1; Thermischer Widerstand (R): 0.146552; Thermisch wirksame Masse: 981.75; Wärmedurchgangskoeffizient (U): 6.82353 kg/K/s3
Grafiken - Füllmuster für groben Maßstab: _Diagonal 45° 1.0mm; Farbfüllung für groben Maßstab: 255
ID-Daten - Beschreibung: Ziegel_380; Typname: Naturstein 425
Konstruktion - Abschluss an Wänden: Keine; Funktion: Außen; Abschluss an Öffnungen: Keine; Breite: 0.425 m
Sonstige - Kategorie: Wände; Familienname: Basiswand
Tragwerk - Filter Tragend / Nichttragend: yes
Pset_WallCommon - IsExternal: yes; ThermalTransmittance: 6.82353 kg/K/s3

# IfcWallType, no part of this type: Basiswand:Naturstein 425 Foundation Pier
PredefinedType: STANDARD; Material: Mauerwerk - Sandstein Rot 0.425 m
Analytische Eigenschaften - Rauigkeit: 1; Absorptionsgrad: 0.1; Thermischer Widerstand (R): 0.146552; Thermisch wirksame Masse: 981.75; Wärmedurchgangskoeffizient (U): 6.82353 kg/K/s3
Grafiken - Füllmuster für groben Maßstab: _Diagonal 45° 1.0mm; Farbfüllung für groben Maßstab: 255
ID-Daten - Beschreibung: Ziegel_380; Typname: Naturstein 425 Foundation Pier
Konstruktion - Abschluss an Wänden: Keine; Funktion: Außen; Abschluss an Öffnungen: Keine; Breite: 0.425 m
Sonstige - Kategorie: Wände; Familienname: Basiswand
Tragwerk - Filter Tragend / Nichttragend: yes
Pset_WallCommon - IsExternal: yes; ThermalTransmittance: 6.82353 kg/K/s3

# IfcWallType, no part of this type: Basiswand:Naturstein 505
PredefinedType: STANDARD; Material: Mauerwerk - Sandstein Rot 0.505 m
Analytische Eigenschaften - Rauigkeit: 1; Absorptionsgrad: 0.1; Thermischer Widerstand (R): 0.174138; Thermisch wirksame Masse: 1166.55; Wärmedurchgangskoeffizient (U): 5.74257 kg/K/s3
Grafiken - Farbfüllung für groben Maßstab: 255; Füllmuster für groben Maßstab: _Diagonal 45° 1.0mm
ID-Daten - Beschreibung: Ziegel_380; Typname: Naturstein 505
Konstruktion - Abschluss an Wänden: Keine; Funktion: Außen; Abschluss an Öffnungen: Keine; Breite: 0.505 m
Sonstige - Kategorie: Wände; Familienname: Basiswand
Tragwerk - Filter Tragend / Nichttragend: yes
Pset_WallCommon - IsExternal: yes; ThermalTransmittance: 5.74257 kg/K/s3

# IfcWallType, no part of this type: Basiswand:Naturstein 510 Foundation Wall
PredefinedType: STANDARD; Material: Mauerwerk - Sandstein Rot 0.51 m
Analytische Eigenschaften - Rauigkeit: 1; Absorptionsgrad: 0.1; Thermischer Widerstand (R): 0.175862; Thermisch wirksame Masse: 1178.1; Wärmedurchgangskoeffizient (U): 5.68627 kg/K/s3
Grafiken - Füllmuster für groben Maßstab: _Diagonal 45° 1.0mm; Farbfüllung für groben Maßstab: 255
ID-Daten - Beschreibung: Ziegel_380; Typname: Naturstein 510 Foundation Wall
Konstruktion - Abschluss an Wänden: Keine; Funktion: Außen; Abschluss an Öffnungen: Keine; Breite: 0.51 m
Sonstige - Kategorie: Wände; Familienname: Basiswand
Tragwerk - Filter Tragend / Nichttragend: yes
Pset_WallCommon - IsExternal: yes; ThermalTransmittance: 5.68627 kg/K/s3

# IfcWallType, no part of this type: Basiswand:Naturstein 800 Foundation Wall
PredefinedType: STANDARD; Material: Mauerwerk - Sandstein Rot 0.8 m
Analytische Eigenschaften - Rauigkeit: 1; Absorptionsgrad: 0.1; Thermischer Widerstand (R): 0.275862; Thermisch wirksame Masse: 1848; Wärmedurchgangskoeffizient (U): 3.625 kg/K/s3
Grafiken - Füllmuster für groben Maßstab: _Diagonal 45° 1.0mm; Farbfüllung für groben Maßstab: 255
ID-Daten - Beschreibung: Ziegel_380; Typname: Naturstein 800 Foundation Wall
Konstruktion - Abschluss an Wänden: Keine; Funktion: Außen; Abschluss an Öffnungen: Keine; Breite: 0.8 m
Sonstige - Kategorie: Wände; Familienname: Basiswand
Tragwerk - Filter Tragend / Nichttragend: yes
Pset_WallCommon - IsExternal: yes; ThermalTransmittance: 3.625 kg/K/s3

# IfcWallType, no part of this type: Basiswand:Naturstein 815 Foundation Pier
PredefinedType: STANDARD; Material: Mauerwerk - Sandstein Rot 0.815 m
Analytische Eigenschaften - Rauigkeit: 1; Absorptionsgrad: 0.1; Thermischer Widerstand (R): 0.281034; Thermisch wirksame Masse: 1882.65; Wärmedurchgangskoeffizient (U): 3.55828 kg/K/s3
Grafiken - Füllmuster für groben Maßstab: _Diagonal 45° 1.0mm; Farbfüllung für groben Maßstab: 255
ID-Daten - Beschreibung: Ziegel_380; Typname: Naturstein 815 Foundation Pier
Konstruktion - Abschluss an Wänden: Keine; Funktion: Außen; Abschluss an Öffnungen: Keine; Breite: 0.815 m
Sonstige - Kategorie: Wände; Familienname: Basiswand
Tragwerk - Filter Tragend / Nichttragend: yes
Pset_WallCommon - IsExternal: yes; ThermalTransmittance: 3.55828 kg/K/s3

# IfcWallType, no part of this type: Basiswand:Naturstein 820 Apse Pier Foundation Wall
PredefinedType: STANDARD; Material: Mauerwerk - Sandstein Rot 0.82 m
Analytische Eigenschaften - Rauigkeit: 1; Absorptionsgrad: 0.1; Thermischer Widerstand (R): 0.282759; Thermisch wirksame Masse: 1894.2; Wärmedurchgangskoeffizient (U): 3.53659 kg/K/s3
Grafiken - Füllmuster für groben Maßstab: _Diagonal 45° 1.0mm; Farbfüllung für groben Maßstab: 255
ID-Daten - Beschreibung: Ziegel_380; Typname: Naturstein 820 Apse Pier Foundation Wall
Konstruktion - Abschluss an Wänden: Keine; Funktion: Außen; Abschluss an Öffnungen: Keine; Breite: 0.82 m
Sonstige - Kategorie: Wände; Familienname: Basiswand
Tragwerk - Filter Tragend / Nichttragend: yes
Pset_WallCommon - IsExternal: yes; ThermalTransmittance: 3.53659 kg/K/s3

# IfcWallType, no part of this type: Basiswand:Naturstein 846 Foundation Wall
PredefinedType: STANDARD; Material: Mauerwerk - Sandstein Rot 0.846 m
Analytische Eigenschaften - Rauigkeit: 1; Absorptionsgrad: 0.1; Thermischer Widerstand (R): 0.291724; Thermisch wirksame Masse: 1954.26; Wärmedurchgangskoeffizient (U): 3.4279 kg/K/s3
Grafiken - Füllmuster für groben Maßstab: _Diagonal 45° 1.0mm; Farbfüllung für groben Maßstab: 255
ID-Daten - Beschreibung: Ziegel_380; Typname: Naturstein 846 Foundation Wall
Konstruktion - Abschluss an Wänden: Keine; Funktion: Außen; Abschluss an Öffnungen: Keine; Breite: 0.846 m
Sonstige - Kategorie: Wände; Familienname: Basiswand
Tragwerk - Filter Tragend / Nichttragend: yes
Pset_WallCommon - IsExternal: yes; ThermalTransmittance: 3.4279 kg/K/s3

# IfcWallType, no part of this type: Basiswand:Naturstein 90
PredefinedType: STANDARD; Material: Mauerwerk - Sandstein Rot 0.09 m
Analytische Eigenschaften - Rauigkeit: 1; Absorptionsgrad: 0.1; Thermischer Widerstand (R): 0.0310345; Thermisch wirksame Masse: 207.9; Wärmedurchgangskoeffizient (U): 32.2222 kg/K/s3
Grafiken - Füllmuster für groben Maßstab: _Diagonal 45° 1.0mm; Farbfüllung für groben Maßstab: 255
ID-Daten - Beschreibung: Ziegel_380; Typname: Naturstein 90
Konstruktion - Abschluss an Wänden: Keine; Funktion: Außen; Abschluss an Öffnungen: Keine; Breite: 0.09 m
Sonstige - Kategorie: Wände; Familienname: Basiswand
Tragwerk - Filter Tragend / Nichttragend: yes
Pset_WallCommon - IsExternal: yes; ThermalTransmittance: 32.2222 kg/K/s3

# IfcWallType, no part of this type: Basiswand:Naturstein 930 Small tower pier Foundation Wall 2
PredefinedType: STANDARD; Material: Mauerwerk - Sandstein Rot 0.93 m
Analytische Eigenschaften - Rauigkeit: 1; Absorptionsgrad: 0.1; Thermischer Widerstand (R): 0.32069; Thermisch wirksame Masse: 2148.3; Wärmedurchgangskoeffizient (U): 3.11828 kg/K/s3
Grafiken - Füllmuster für groben Maßstab: _Diagonal 45° 1.0mm; Farbfüllung für groben Maßstab: 255
ID-Daten - Beschreibung: Ziegel_380; Typname: Naturstein 930 Small tower pier Foundation Wall 2
Konstruktion - Abschluss an Wänden: Keine; Funktion: Außen; Abschluss an Öffnungen: Keine; Breite: 0.93 m
Sonstige - Kategorie: Wände; Familienname: Basiswand
Tragwerk - Filter Tragend / Nichttragend: yes
Pset_WallCommon - IsExternal: yes; ThermalTransmittance: 3.11828 kg/K/s3

# IfcWallType, no part of this type: Basiswand:Putz 20
PredefinedType: STANDARD; Material: Mauerwerk - Kalkputz-white 0.02 m
Analytische Eigenschaften - Rauigkeit: 1; Absorptionsgrad: 0.1; Thermischer Widerstand (R): 0.00689655; Thermisch wirksame Masse: 46.2; Wärmedurchgangskoeffizient (U): 145 kg/K/s3
Grafiken - Füllmuster für groben Maßstab: <Flächenfüllung>; Farbfüllung für groben Maßstab: 255
ID-Daten - Beschreibung: Kalksandstein_115; Typname: Putz 20
Konstruktion - Abschluss an Wänden: Keine; Abschluss an Öffnungen: Keine; Funktion: Innen; Breite: 0.02 m
Sonstige - Kategorie: Wände; Familienname: Basiswand
Tragwerk - Filter Tragend / Nichttragend: no
Pset_WallCommon - IsExternal: no; ThermalTransmittance: 145 kg/K/s3

# IfcWallType, no part of this type: Basiswand:Putz 30
PredefinedType: STANDARD; Material: Mauerwerk - Kalkputz-white 0.03 m
Analytische Eigenschaften - Rauigkeit: 1; Absorptionsgrad: 0.1; Thermischer Widerstand (R): 0.0103448; Thermisch wirksame Masse: 69.3; Wärmedurchgangskoeffizient (U): 96.6667 kg/K/s3
Grafiken - Füllmuster für groben Maßstab: <Flächenfüllung>; Farbfüllung für groben Maßstab: 255
ID-Daten - Beschreibung: Ziegel_100; Typname: Putz 30
Konstruktion - Abschluss an Wänden: Keine; Abschluss an Öffnungen: Keine; Funktion: Innen; Breite: 0.03 m
Materialien und Oberflächen - Tragendes Material: Mauerwerk - Kalkputz-white
Sonstige - Kategorie: Wände; Familienname: Basiswand
Tragwerk - Filter Tragend / Nichttragend: no
Pset_WallCommon - IsExternal: no; ThermalTransmittance: 96.6667 kg/K/s3

# IfcWallType, no part of this type: Basiswand:Putz30
PredefinedType: STANDARD; Material: Mauerwerk - Kalkputz-white 0.03 m
Analytische Eigenschaften - Rauigkeit: 1; Absorptionsgrad: 0.1; Thermischer Widerstand (R): 0.0103448; Thermisch wirksame Masse: 69.3; Wärmedurchgangskoeffizient (U): 96.6667 kg/K/s3
Grafiken - Füllmuster für groben Maßstab: <Flächenfüllung>; Farbfüllung für groben Maßstab: 255
ID-Daten - Beschreibung: Kalksandstein_115; Typname: Putz30
Konstruktion - Abschluss an Wänden: Keine; Abschluss an Öffnungen: Keine; Funktion: Innen; Breite: 0.03 m
Sonstige - Kategorie: Wände; Familienname: Basiswand
Tragwerk - Filter Tragend / Nichttragend: no
Pset_WallCommon - IsExternal: no; ThermalTransmittance: 96.6667 kg/K/s3

# IfcWallType, no part of this type: Basiswand:Putz40
PredefinedType: STANDARD; Material: Mauerwerk - Kalkputz-white 0.04 m
Analytische Eigenschaften - Rauigkeit: 1; Absorptionsgrad: 0.1; Thermischer Widerstand (R): 0.0137931; Thermisch wirksame Masse: 92.4; Wärmedurchgangskoeffizient (U): 72.5 kg/K/s3
Grafiken - Füllmuster für groben Maßstab: <Flächenfüllung>; Farbfüllung für groben Maßstab: 255
ID-Daten - Beschreibung: Kalksandstein_115; Typname: Putz40
Konstruktion - Abschluss an Wänden: Keine; Abschluss an Öffnungen: Keine; Funktion: Innen; Breite: 0.04 m
Sonstige - Kategorie: Wände; Familienname: Basiswand
Tragwerk - Filter Tragend / Nichttragend: no
Pset_WallCommon - IsExternal: no; ThermalTransmittance: 72.5 kg/K/s3

# IfcWallType, no part of this type: Basiswand:STB 200
PredefinedType: STANDARD; Material: Ortbeton - bewehrt 0.2 m
Analytische Eigenschaften - Rauigkeit: 1; Absorptionsgrad: 0.1; Thermischer Widerstand (R): 0.191205; Thermisch wirksame Masse: 302.22; Wärmedurchgangskoeffizient (U): 5.23 kg/K/s3
Grafiken - Füllmuster für groben Maßstab: <Flächenfüllung>; Farbfüllung für groben Maßstab: 32768
ID-Daten - Beschreibung: STB_200; Typname: STB 200
Konstruktion - Abschluss an Wänden: Keine; Funktion: Außen; Abschluss an Öffnungen: Keine; Breite: 0.2 m
Materialien und Oberflächen - Tragendes Material: Ortbeton - bewehrt
Sonstige - Kategorie: Wände; Familienname: Basiswand
Tragwerk - Filter Tragend / Nichttragend: yes
Pset_WallCommon - IsExternal: yes; ThermalTransmittance: 5.23 kg/K/s3

# IfcWallType, no part of this type: Basiswand:STB 260
PredefinedType: STANDARD; Material: Ortbeton - bewehrt Verputzt 0.26 m
Analytische Eigenschaften - Rauigkeit: 1; Absorptionsgrad: 0.1; Thermischer Widerstand (R): 0.248566; Thermisch wirksame Masse: 392.886; Wärmedurchgangskoeffizient (U): 4.02308 kg/K/s3
Grafiken - Füllmuster für groben Maßstab: <Flächenfüllung>; Farbfüllung für groben Maßstab: 32768
ID-Daten - Beschreibung: STB_200; Typname: STB 260
Konstruktion - Abschluss an Wänden: Keine; Funktion: Außen; Abschluss an Öffnungen: Keine; Breite: 0.26 m
Materialien und Oberflächen - Tragendes Material: Ortbeton - bewehrt Verputzt
Sonstige - Kategorie: Wände; Familienname: Basiswand
Tragwerk - Filter Tragend / Nichttragend: yes
Pset_WallCommon - IsExternal: yes; ThermalTransmittance: 4.02308 kg/K/s3

# IfcWallType, no part of this type: Basiswand:Ziegel 118 farbig 72x265 English bond Plinth Stage 2
PredefinedType: STANDARD; Material: Mauerwerk - Sichtmauerwerk_72x265 english bond Stage2 0.118 m
Analytische Eigenschaften - Rauigkeit: 1; Absorptionsgrad: 0.1; Thermischer Widerstand (R): 0.218519; Thermisch wirksame Masse: 153.636; Wärmedurchgangskoeffizient (U): 4.57627 kg/K/s3
Grafiken - Füllmuster für groben Maßstab: <Flächenfüllung>; Farbfüllung für groben Maßstab: 255
ID-Daten - Beschreibung: Ziegel_125; Typname: Ziegel 118 farbig 72x265 English bond Plinth Stage 2
Konstruktion - Funktion: Außen; Abschluss an Wänden: Außen; Abschluss an Öffnungen: Außen; Breite: 0.118 m
Materialien und Oberflächen - Tragendes Material: Mauerwerk - Sichtmauerwerk_72x265 english bond Stage2
Sonstige - Kategorie: Wände; Familienname: Basiswand
Tragwerk - Filter Tragend / Nichttragend: no
Pset_WallCommon - IsExternal: yes; ThermalTransmittance: 4.57627 kg/K/s3

# IfcWallType, no part of this type: Basiswand:Ziegel 120 farbig 72x265 English bond
PredefinedType: STANDARD; Material: Mauerwerk - Sichtmauerwerk_72x265 english bond 0.12 m
Analytische Eigenschaften - Rauigkeit: 1; Absorptionsgrad: 0.1; Thermischer Widerstand (R): 0.222222; Thermisch wirksame Masse: 156.24; Wärmedurchgangskoeffizient (U): 4.5 kg/K/s3
Grafiken - Füllmuster für groben Maßstab: <Flächenfüllung>; Farbfüllung für groben Maßstab: 255
ID-Daten - Beschreibung: Ziegel_120; Typname: Ziegel 120 farbig 72x265 English bond
Konstruktion - Abschluss an Öffnungen: Beide; Abschluss an Wänden: Keine; Funktion: Außen; Breite: 0.12 m
Materialien und Oberflächen - Tragendes Material: Mauerwerk - Sichtmauerwerk_72x265 english bond
Sonstige - Kategorie: Wände; Familienname: Basiswand
Tragwerk - Filter Tragend / Nichttragend: no
Pset_WallCommon - IsExternal: yes; ThermalTransmittance: 4.5 kg/K/s3

# IfcWallType, no part of this type: Basiswand:Ziegel 120 farbig new
PredefinedType: STANDARD; Material: Mauerwerk - Sichtmauerwerk 0.12 m
Analytische Eigenschaften - Rauigkeit: 1; Absorptionsgrad: 0.1; Thermischer Widerstand (R): 0.222222; Thermisch wirksame Masse: 156.24; Wärmedurchgangskoeffizient (U): 4.5 kg/K/s3
Grafiken - Füllmuster für groben Maßstab: <Flächenfüllung>; Farbfüllung für groben Maßstab: 255
ID-Daten - Beschreibung: Ziegel_120; Typname: Ziegel 120 farbig new
Konstruktion - Abschluss an Wänden: Keine; Funktion: Außen; Abschluss an Öffnungen: Keine; Breite: 0.12 m
Sonstige - Kategorie: Wände; Familienname: Basiswand
Tragwerk - Filter Tragend / Nichttragend: no
Pset_WallCommon - IsExternal: yes; ThermalTransmittance: 4.5 kg/K/s3

# IfcWallType, no part of this type: Basiswand:Ziegel 125 farbig 72x265 English bond Chimney Stage 2
PredefinedType: STANDARD; Material: Mauerwerk - Sichtmauerwerk_72x265 english bond Stage2 0.125 m
Analytische Eigenschaften - Rauigkeit: 1; Absorptionsgrad: 0.1; Thermischer Widerstand (R): 0.231481; Thermisch wirksame Masse: 162.75; Wärmedurchgangskoeffizient (U): 4.32 kg/K/s3
Grafiken - Füllmuster für groben Maßstab: <Flächenfüllung>; Farbfüllung für groben Maßstab: 255
ID-Daten - Beschreibung: Ziegel_125; Typname: Ziegel 125 farbig 72x265 English bond Chimney Stage 2
Konstruktion - Funktion: Außen; Abschluss an Wänden: Außen; Abschluss an Öffnungen: Außen; Breite: 0.125 m
Materialien und Oberflächen - Tragendes Material: Mauerwerk - Sichtmauerwerk_72x265 english bond Stage2
Sonstige - Kategorie: Wände; Familienname: Basiswand
Tragwerk - Filter Tragend / Nichttragend: no
Pset_WallCommon - IsExternal: yes; ThermalTransmittance: 4.32 kg/K/s3

# IfcWallType, no part of this type: Basiswand:Ziegel 125 farbig 72x265 English bond Plinth Stage 2
PredefinedType: STANDARD; Material: Mauerwerk - Sichtmauerwerk_72x265 english bond Stage2 0.125 m
Analytische Eigenschaften - Rauigkeit: 1; Absorptionsgrad: 0.1; Thermischer Widerstand (R): 0.231481; Thermisch wirksame Masse: 162.75; Wärmedurchgangskoeffizient (U): 4.32 kg/K/s3
Grafiken - Füllmuster für groben Maßstab: <Flächenfüllung>; Farbfüllung für groben Maßstab: 255
ID-Daten - Beschreibung: Ziegel_125; Typname: Ziegel 125 farbig 72x265 English bond Plinth Stage 2
Konstruktion - Funktion: Außen; Abschluss an Wänden: Außen; Abschluss an Öffnungen: Außen; Breite: 0.125 m
Materialien und Oberflächen - Tragendes Material: Mauerwerk - Sichtmauerwerk_72x265 english bond Stage2
Sonstige - Kategorie: Wände; Familienname: Basiswand
Tragwerk - Filter Tragend / Nichttragend: no
Pset_WallCommon - IsExternal: yes; ThermalTransmittance: 4.32 kg/K/s3

# IfcWallType, no part of this type: Basiswand:Ziegel 125 farbig 72x265 English bond corbel skin
PredefinedType: STANDARD; Material: Mauerwerk - Sichtmauerwerk_72x265 english bond 0.125 m
Analytische Eigenschaften - Rauigkeit: 1; Absorptionsgrad: 0.1; Thermischer Widerstand (R): 0.231481; Thermisch wirksame Masse: 162.75; Wärmedurchgangskoeffizient (U): 4.32 kg/K/s3
Grafiken - Füllmuster für groben Maßstab: <Flächenfüllung>; Farbfüllung für groben Maßstab: 255
ID-Daten - Beschreibung: Ziegel_125; Typname: Ziegel 125 farbig 72x265 English bond corbel skin
Konstruktion - Funktion: Außen; Abschluss an Wänden: Außen; Abschluss an Öffnungen: Außen; Breite: 0.125 m
Materialien und Oberflächen - Tragendes Material: Mauerwerk - Sichtmauerwerk_72x265 english bond
Sonstige - Kategorie: Wände; Familienname: Basiswand
Tragwerk - Filter Tragend / Nichttragend: no
Pset_WallCommon - IsExternal: yes; ThermalTransmittance: 4.32 kg/K/s3

# IfcWallType, no part of this type: Basiswand:Ziegel 125 farbig 72x265 English bond old
PredefinedType: STANDARD; Material: Mauerwerk - Sichtmauerwerk_72x265 english bond 0.125 m
Analytische Eigenschaften - Rauigkeit: 1; Absorptionsgrad: 0.1; Thermischer Widerstand (R): 0.231481; Thermisch wirksame Masse: 162.75; Wärmedurchgangskoeffizient (U): 4.32 kg/K/s3
Grafiken - Füllmuster für groben Maßstab: <Flächenfüllung>; Farbfüllung für groben Maßstab: 255
ID-Daten - Beschreibung: Ziegel_120; Typname: Ziegel 125 farbig 72x265 English bond old
Konstruktion - Funktion: Außen; Abschluss an Wänden: Außen; Abschluss an Öffnungen: Außen; Breite: 0.125 m
Materialien und Oberflächen - Tragendes Material: Mauerwerk - Sichtmauerwerk_72x265 english bond
Sonstige - Kategorie: Wände; Familienname: Basiswand
Tragwerk - Filter Tragend / Nichttragend: no
Pset_WallCommon - IsExternal: yes; ThermalTransmittance: 4.32 kg/K/s3

# IfcWallType, no part of this type: Basiswand:Ziegel 125 farbig 72x265 English bond plinth skin
PredefinedType: STANDARD; Material: Mauerwerk - Sichtmauerwerk_72x265 english bond 0.125 m
Analytische Eigenschaften - Rauigkeit: 1; Absorptionsgrad: 0.1; Thermischer Widerstand (R): 0.231481; Thermisch wirksame Masse: 162.75; Wärmedurchgangskoeffizient (U): 4.32 kg/K/s3
Grafiken - Füllmuster für groben Maßstab: <Flächenfüllung>; Farbfüllung für groben Maßstab: 255
ID-Daten - Beschreibung: Ziegel_125; Typname: Ziegel 125 farbig 72x265 English bond plinth skin
Konstruktion - Funktion: Außen; Abschluss an Wänden: Außen; Abschluss an Öffnungen: Außen; Breite: 0.125 m
Materialien und Oberflächen - Tragendes Material: Mauerwerk - Sichtmauerwerk_72x265 english bond
Sonstige - Kategorie: Wände; Familienname: Basiswand
Tragwerk - Filter Tragend / Nichttragend: no
Pset_WallCommon - IsExternal: yes; ThermalTransmittance: 4.32 kg/K/s3

# IfcWallType, no part of this type: Basiswand:Ziegel 130 farbig 72x265 English bond Tower Stage 2
PredefinedType: STANDARD; Material: Mauerwerk - Sichtmauerwerk_72x265 english bond Stage2 0.13 m
Analytische Eigenschaften - Rauigkeit: 1; Absorptionsgrad: 0.1; Thermischer Widerstand (R): 0.240741; Thermisch wirksame Masse: 169.26; Wärmedurchgangskoeffizient (U): 4.15385 kg/K/s3
Grafiken - Füllmuster für groben Maßstab: <Flächenfüllung>; Farbfüllung für groben Maßstab: 255
ID-Daten - Beschreibung: Ziegel_125; Typname: Ziegel 130 farbig 72x265 English bond Tower Stage 2
Konstruktion - Funktion: Außen; Abschluss an Wänden: Außen; Abschluss an Öffnungen: Außen; Breite: 0.13 m
Materialien und Oberflächen - Tragendes Material: Mauerwerk - Sichtmauerwerk_72x265 english bond Stage2
Sonstige - Kategorie: Wände; Familienname: Basiswand
Tragwerk - Filter Tragend / Nichttragend: no
Pset_WallCommon - IsExternal: yes; ThermalTransmittance: 4.15385 kg/K/s3

# IfcWallType, no part of this type: Basiswand:Ziegel 130 putz
PredefinedType: STANDARD; Material: Mauerwerk - Kalkputz-white 0.001 m, Mauerwerk - Ziegel 0.12 m, Mauerwerk - Kalkputz-white 0.001 m
Analytische Eigenschaften - Rauigkeit: 1; Absorptionsgrad: 0.1; Thermischer Widerstand (R): 0.222912; Thermisch wirksame Masse: 160.86; Wärmedurchgangskoeffizient (U): 4.48608 kg/K/s3
Grafiken - Füllmuster für groben Maßstab: <Flächenfüllung>; Farbfüllung für groben Maßstab: 255
ID-Daten - Beschreibung: Ziegel_120; Typname: Ziegel 130 putz
Konstruktion - Funktion: Außen; Abschluss an Öffnungen: Keine; Abschluss an Wänden: Außen; Breite: 0.122 m
Sonstige - Kategorie: Wände; Familienname: Basiswand
Tragwerk - Filter Tragend / Nichttragend: no
Pset_WallCommon - IsExternal: yes; ThermalTransmittance: 4.48608 kg/K/s3

# IfcWallType, no part of this type: Basiswand:Ziegel 150 farbig 72x265 English bond Octagon Stage 2
PredefinedType: STANDARD; Material: Mauerwerk - Sichtmauerwerk_72x265 english bond Stage2 0.175 m
Analytische Eigenschaften - Rauigkeit: 1; Absorptionsgrad: 0.1; Thermischer Widerstand (R): 0.324074; Thermisch wirksame Masse: 227.85; Wärmedurchgangskoeffizient (U): 3.08571 kg/K/s3
Grafiken - Füllmuster für groben Maßstab: <Flächenfüllung>; Farbfüllung für groben Maßstab: 255
ID-Daten - Beschreibung: Ziegel_125; Typname: Ziegel 150 farbig 72x265 English bond Octagon Stage 2
Konstruktion - Abschluss an Wänden: Keine; Abschluss an Öffnungen: Keine; Funktion: Innen; Breite: 0.175 m
Materialien und Oberflächen - Tragendes Material: Mauerwerk - Sichtmauerwerk_72x265 english bond Stage2
Sonstige - Kategorie: Wände; Familienname: Basiswand
Tragwerk - Filter Tragend / Nichttragend: no
Pset_WallCommon - IsExternal: no; ThermalTransmittance: 3.08571 kg/K/s3

# IfcWallType, no part of this type: Basiswand:Ziegel 150 putz 2s
PredefinedType: STANDARD; Material: <Unnamed> 0.01 m, Mauerwerk - Ziegel 0.13 m, <Unnamed> 0.01 m
Analytische Eigenschaften - Rauigkeit: 1; Absorptionsgrad: 0.1; Thermischer Widerstand (R): 0.240741; Thermisch wirksame Masse: 169.26; Wärmedurchgangskoeffizient (U): 4.15385 kg/K/s3
Grafiken - Füllmuster für groben Maßstab: <Flächenfüllung>; Farbfüllung für groben Maßstab: 255
ID-Daten - Beschreibung: Ziegel_240; Typname: Ziegel 150 putz 2s
Konstruktion - Abschluss an Wänden: Keine; Abschluss an Öffnungen: Keine; Funktion: Innen; Breite: 0.15 m
Sonstige - Kategorie: Wände; Familienname: Basiswand
Tragwerk - Filter Tragend / Nichttragend: yes
Pset_WallCommon - IsExternal: no; ThermalTransmittance: 4.15385 kg/K/s3

# IfcWallType, no part of this type: Basiswand:Ziegel 160 putz 2s
PredefinedType: STANDARD; Material: Mauerwerk - Kalkputz-white 0.02 m, Mauerwerk - Ziegel 0.12 m, Mauerwerk - Kalkputz-white 0.02 m
Analytische Eigenschaften - Rauigkeit: 1; Absorptionsgrad: 0.1; Thermischer Widerstand (R): 0.236015; Thermisch wirksame Masse: 248.64; Wärmedurchgangskoeffizient (U): 4.23701 kg/K/s3
Grafiken - Füllmuster für groben Maßstab: <Flächenfüllung>; Farbfüllung für groben Maßstab: 255
ID-Daten - Beschreibung: Ziegel_240; Typname: Ziegel 160 putz 2s
Konstruktion - Abschluss an Wänden: Keine; Abschluss an Öffnungen: Keine; Funktion: Innen; Breite: 0.16 m
Sonstige - Kategorie: Wände; Familienname: Basiswand
Tragwerk - Filter Tragend / Nichttragend: yes
Pset_WallCommon - IsExternal: no; ThermalTransmittance: 4.23701 kg/K/s3

# IfcWallType, no part of this type: Basiswand:Ziegel 220 farbig 72x265 English bond Octagon Phase 2
PredefinedType: STANDARD; Material: Mauerwerk - Sichtmauerwerk_72x265 english bond Stage2 0.22 m
Analytische Eigenschaften - Rauigkeit: 1; Absorptionsgrad: 0.1; Thermischer Widerstand (R): 0.407407; Thermisch wirksame Masse: 286.44; Wärmedurchgangskoeffizient (U): 2.45455 kg/K/s3
Grafiken - Füllmuster für groben Maßstab: <Flächenfüllung>; Farbfüllung für groben Maßstab: 255
ID-Daten - Beschreibung: Ziegel_125; Typname: Ziegel 220 farbig 72x265 English bond Octagon Phase 2
Konstruktion - Abschluss an Wänden: Keine; Abschluss an Öffnungen: Keine; Funktion: Innen; Breite: 0.22 m
Materialien und Oberflächen - Tragendes Material: Mauerwerk - Sichtmauerwerk_72x265 english bond Stage2
Sonstige - Kategorie: Wände; Familienname: Basiswand
Tragwerk - Filter Tragend / Nichttragend: no
Pset_WallCommon - IsExternal: no; ThermalTransmittance: 2.45455 kg/K/s3

# IfcWallType, no part of this type: Basiswand:Ziegel 240
PredefinedType: STANDARD; Material: Mauerwerk - Sandstein Rot 0.24 m
Analytische Eigenschaften - Rauigkeit: 1; Absorptionsgrad: 0.1; Thermischer Widerstand (R): 0.0827586; Thermisch wirksame Masse: 554.4; Wärmedurchgangskoeffizient (U): 12.0833 kg/K/s3
Grafiken - Füllmuster für groben Maßstab: <Flächenfüllung>; Farbfüllung für groben Maßstab: 255
ID-Daten - Beschreibung: Ziegel_240; Typname: Ziegel 240
Konstruktion - Abschluss an Wänden: Keine; Abschluss an Öffnungen: Keine; Funktion: Innen; Breite: 0.24 m
Materialien und Oberflächen - Tragendes Material: Mauerwerk - Sandstein Rot
Sonstige - Kategorie: Wände; Familienname: Basiswand
Tragwerk - Filter Tragend / Nichttragend: yes
Pset_WallCommon - IsExternal: no; ThermalTransmittance: 12.0833 kg/K/s3

# IfcWallType, no part of this type: Basiswand:Ziegel 240 Stage1
PredefinedType: STANDARD; Material: Mauerwerk - Sandstein Rot 0.24 m
Analytische Eigenschaften - Rauigkeit: 1; Absorptionsgrad: 0.1; Thermischer Widerstand (R): 0.0827586; Thermisch wirksame Masse: 554.4; Wärmedurchgangskoeffizient (U): 12.0833 kg/K/s3
Grafiken - Füllmuster für groben Maßstab: <Flächenfüllung>; Farbfüllung für groben Maßstab: 255
ID-Daten - Beschreibung: Ziegel_240; Typname: Ziegel 240 Stage1
Konstruktion - Abschluss an Wänden: Keine; Abschluss an Öffnungen: Keine; Funktion: Innen; Breite: 0.24 m
Materialien und Oberflächen - Tragendes Material: Mauerwerk - Sandstein Rot
Sonstige - Kategorie: Wände; Familienname: Basiswand
Tragwerk - Filter Tragend / Nichttragend: yes
Pset_WallCommon - IsExternal: no; ThermalTransmittance: 12.0833 kg/K/s3

# IfcWallType, no part of this type: Basiswand:Ziegel 250 Chimney
PredefinedType: STANDARD; Material: Chimney Brickwork 0.25 m
Analytische Eigenschaften - Rauigkeit: 1; Absorptionsgrad: 0.1
Grafiken - Füllmuster für groben Maßstab: <Flächenfüllung>; Farbfüllung für groben Maßstab: 255
ID-Daten - Beschreibung: Ziegel_250; Typname: Ziegel 250 Chimney
Konstruktion - Abschluss an Wänden: Keine; Abschluss an Öffnungen: Keine; Funktion: Innen; Breite: 0.25 m
Materialien und Oberflächen - Tragendes Material: Chimney Brickwork
Sonstige - Kategorie: Wände; Familienname: Basiswand
Tragwerk - Filter Tragend / Nichttragend: yes
Pset_WallCommon - IsExternal: no

# IfcWallType, no part of this type: Basiswand:Ziegel 250 farbig
PredefinedType: STANDARD; Material: Mauerwerk - Sichtmauerwerk_72x265 english bond Stage2 0.25 m
Analytische Eigenschaften - Rauigkeit: 1; Absorptionsgrad: 0.1; Thermischer Widerstand (R): 0.462963; Thermisch wirksame Masse: 325.5; Wärmedurchgangskoeffizient (U): 2.16 kg/K/s3
Grafiken - Füllmuster für groben Maßstab: <Flächenfüllung>; Farbfüllung für groben Maßstab: 255
ID-Daten - Beschreibung: Ziegel_250; Typname: Ziegel 250 farbig
Konstruktion - Abschluss an Wänden: Keine; Abschluss an Öffnungen: Keine; Funktion: Innen; Breite: 0.25 m
Sonstige - Kategorie: Wände; Familienname: Basiswand
Tragwerk - Filter Tragend / Nichttragend: yes
Pset_WallCommon - IsExternal: no; ThermalTransmittance: 2.16 kg/K/s3

# IfcWallType, no part of this type: Basiswand:Ziegel 250 farbig 72x265 English bond Octagon Phase 2
PredefinedType: STANDARD; Material: Mauerwerk - Sichtmauerwerk_72x265 english bond Stage2 0.25 m
Analytische Eigenschaften - Rauigkeit: 1; Absorptionsgrad: 0.1; Thermischer Widerstand (R): 0.462963; Thermisch wirksame Masse: 325.5; Wärmedurchgangskoeffizient (U): 2.16 kg/K/s3
Grafiken - Füllmuster für groben Maßstab: <Flächenfüllung>; Farbfüllung für groben Maßstab: 255
ID-Daten - Beschreibung: Ziegel_125; Typname: Ziegel 250 farbig 72x265 English bond Octagon Phase 2
Konstruktion - Abschluss an Wänden: Keine; Abschluss an Öffnungen: Keine; Funktion: Innen; Breite: 0.25 m
Materialien und Oberflächen - Tragendes Material: Mauerwerk - Sichtmauerwerk_72x265 english bond Stage2
Sonstige - Kategorie: Wände; Familienname: Basiswand
Tragwerk - Filter Tragend / Nichttragend: no
Pset_WallCommon - IsExternal: no; ThermalTransmittance: 2.16 kg/K/s3

# IfcWallType, no part of this type: Basiswand:Ziegel 265 farbig 72x265 boundary wall
PredefinedType: STANDARD; Material: Mauerwerk - Sichtmauerwerk_72x265 english bond Stage2 0.265 m
Analytische Eigenschaften - Rauigkeit: 1; Absorptionsgrad: 0.1; Thermischer Widerstand (R): 0.490741; Thermisch wirksame Masse: 345.03; Wärmedurchgangskoeffizient (U): 2.03774 kg/K/s3
Grafiken - Füllmuster für groben Maßstab: <Flächenfüllung>; Farbfüllung für groben Maßstab: 255
ID-Daten - Beschreibung: Ziegel_500; Typname: Ziegel 265 farbig 72x265 boundary wall
Konstruktion - Funktion: Außen; Abschluss an Öffnungen: Keine; Abschluss an Wänden: Außen; Breite: 0.265 m
Sonstige - Kategorie: Wände; Familienname: Basiswand
Tragwerk - Filter Tragend / Nichttragend: yes
Pset_WallCommon - IsExternal: yes; ThermalTransmittance: 2.03774 kg/K/s3

# IfcWallType, no part of this type: Basiswand:Ziegel 265 farbig putz 2s Tower lobby Stage 2
PredefinedType: STANDARD; Material: Mauerwerk - Kalkputz-white 0.02 m, Mauerwerk - Kalkputz-white 0.001 m, Mauerwerk - Sichtmauerwerk_72x265 english bond Stage 3 0.225 m, Mauerwerk - Kalkputz-white 0.02 m
Analytische Eigenschaften - Rauigkeit: 1; Absorptionsgrad: 0.1; Thermischer Widerstand (R): 0.430805; Thermisch wirksame Masse: 387.66; Wärmedurchgangskoeffizient (U): 2.32124 kg/K/s3
Grafiken - Füllmuster für groben Maßstab: <Flächenfüllung>; Farbfüllung für groben Maßstab: 255
ID-Daten - Beschreibung: Ziegel_250; Typname: Ziegel 265 farbig putz 2s Tower lobby Stage 2
Konstruktion - Abschluss an Wänden: Keine; Abschluss an Öffnungen: Keine; Funktion: Innen; Breite: 0.266 m
Sonstige - Kategorie: Wände; Familienname: Basiswand
Tragwerk - Filter Tragend / Nichttragend: yes
Pset_WallCommon - IsExternal: no; ThermalTransmittance: 2.32124 kg/K/s3

# IfcWallType, no part of this type: Basiswand:Ziegel 280white
PredefinedType: STANDARD; Material: <Unnamed> 0.015 m, Mauerwerk - Ziegel 0.25 m, <Unnamed> 0.015 m
Analytische Eigenschaften - Rauigkeit: 1; Absorptionsgrad: 0.1; Thermischer Widerstand (R): 0.462963; Thermisch wirksame Masse: 325.5; Wärmedurchgangskoeffizient (U): 2.16 kg/K/s3
Grafiken - Füllmuster für groben Maßstab: <Flächenfüllung>; Farbfüllung für groben Maßstab: 255
ID-Daten - Beschreibung: Ziegel_380; Typname: Ziegel 280white
Konstruktion - Abschluss an Wänden: Keine; Funktion: Außen; Abschluss an Öffnungen: Keine; Breite: 0.28 m
Sonstige - Kategorie: Wände; Familienname: Basiswand
Tragwerk - Filter Tragend / Nichttragend: yes
Pset_WallCommon - IsExternal: yes; ThermalTransmittance: 2.16 kg/K/s3

# IfcWallType, no part of this type: Basiswand:Ziegel 285 Portal
PredefinedType: STANDARD; Material: Mauerwerk - Kalkputz-white image background 0.04 m, Mauerwerk - Naturstein 0.245 m
Analytische Eigenschaften - Rauigkeit: 1; Absorptionsgrad: 0.1; Thermischer Widerstand (R): 0.0137931; Thermisch wirksame Masse: 92.4; Wärmedurchgangskoeffizient (U): 72.5 kg/K/s3
Grafiken - Füllmuster für groben Maßstab: <Flächenfüllung>; Farbfüllung für groben Maßstab: 255
ID-Daten - Beschreibung: Ziegel_200; Typname: Ziegel 285 Portal
Konstruktion - Abschluss an Wänden: Keine; Abschluss an Öffnungen: Außen; Funktion: Innen; Breite: 0.285 m
Sonstige - Kategorie: Wände; Familienname: Basiswand
Tragwerk - Filter Tragend / Nichttragend: yes
Pset_WallCommon - IsExternal: no; ThermalTransmittance: 72.5 kg/K/s3

# IfcWallType, no part of this type: Basiswand:Ziegel 285 farbig 72x265 English bond Junction Stage 2
PredefinedType: STANDARD; Material: Mauerwerk - Sichtmauerwerk_72x265 english bond Stage2 0.285 m
Analytische Eigenschaften - Rauigkeit: 1; Absorptionsgrad: 0.1; Thermischer Widerstand (R): 0.527778; Thermisch wirksame Masse: 371.07; Wärmedurchgangskoeffizient (U): 1.89474 kg/K/s3
Grafiken - Füllmuster für groben Maßstab: <Flächenfüllung>; Farbfüllung für groben Maßstab: 255
ID-Daten - Beschreibung: Ziegel_125; Typname: Ziegel 285 farbig 72x265 English bond Junction Stage 2
Konstruktion - Funktion: Außen; Abschluss an Wänden: Außen; Abschluss an Öffnungen: Außen; Breite: 0.285 m
Materialien und Oberflächen - Tragendes Material: Mauerwerk - Sichtmauerwerk_72x265 english bond Stage2
Sonstige - Kategorie: Wände; Familienname: Basiswand
Tragwerk - Filter Tragend / Nichttragend: no
Pset_WallCommon - IsExternal: yes; ThermalTransmittance: 1.89474 kg/K/s3

# IfcWallType, no part of this type: Basiswand:Ziegel 330 basement stair wall Stage 2
PredefinedType: STANDARD; Material: <Unnamed> 0.01 m, Mauerwerk - Kalkputz-white 0.02 m, Mauerwerk - Sichtmauerwerk_72x265 english bond Stage2 0.28 m, Mauerwerk - Kalkputz-white 0.02 m
Analytische Eigenschaften - Rauigkeit: 1; Absorptionsgrad: 0.1; Thermischer Widerstand (R): 0.532312; Thermisch wirksame Masse: 456.96; Wärmedurchgangskoeffizient (U): 1.8786 kg/K/s3
Grafiken - Füllmuster für groben Maßstab: <Flächenfüllung>; Farbfüllung für groben Maßstab: 255
ID-Daten - Beschreibung: Ziegel_120; Typname: Ziegel 330 basement stair wall Stage 2
Konstruktion - Abschluss an Öffnungen: Beide; Abschluss an Wänden: Keine; Funktion: Außen; Breite: 0.33 m
Sonstige - Kategorie: Wände; Familienname: Basiswand
Tragwerk - Filter Tragend / Nichttragend: no
Pset_WallCommon - IsExternal: yes; ThermalTransmittance: 1.8786 kg/K/s3

# IfcWallType, no part of this type: Basiswand:Ziegel 365 farbig 72x265 Stage 2 Office pier
PredefinedType: STANDARD; Material: Mauerwerk - Sichtmauerwerk_72x265 english bond Stage2 0.365 m
Analytische Eigenschaften - Rauigkeit: 1; Absorptionsgrad: 0.1; Thermischer Widerstand (R): 0.675926; Thermisch wirksame Masse: 475.23; Wärmedurchgangskoeffizient (U): 1.47945 kg/K/s3
Grafiken - Füllmuster für groben Maßstab: <Flächenfüllung>; Farbfüllung für groben Maßstab: 255
ID-Daten - Beschreibung: Ziegel_500; Typname: Ziegel 365 farbig 72x265 Stage 2 Office pier
Konstruktion - Funktion: Außen; Abschluss an Öffnungen: Keine; Abschluss an Wänden: Außen; Breite: 0.365 m
Sonstige - Kategorie: Wände; Familienname: Basiswand
Tragwerk - Filter Tragend / Nichttragend: yes
Pset_WallCommon - IsExternal: yes; ThermalTransmittance: 1.47945 kg/K/s3

# IfcWallType, no part of this type: Basiswand:Ziegel 425 verputzt 2s chancel arch
PredefinedType: STANDARD; Material: Mauerwerk - Kalkputz-white 0.03 m, Mauerwerk - Sichtmauerwerk 0.365 m, Mauerwerk - Kalkputz-white 0.03 m
Analytische Eigenschaften - Rauigkeit: 1; Absorptionsgrad: 0.1; Thermischer Widerstand (R): 0.696616; Thermisch wirksame Masse: 613.83; Wärmedurchgangskoeffizient (U): 1.43551 kg/K/s3
Grafiken - Füllmuster für groben Maßstab: <Flächenfüllung>; Farbfüllung für groben Maßstab: 255
ID-Daten - Beschreibung: Ziegel_430; Typname: Ziegel 425 verputzt 2s chancel arch
Konstruktion - Abschluss an Öffnungen: Beide; Abschluss an Wänden: Keine; Funktion: Außen; Breite: 0.425 m
Materialien und Oberflächen - Tragendes Material: Mauerwerk - Sichtmauerwerk
Sonstige - Kategorie: Wände; Familienname: Basiswand
Tragwerk - Filter Tragend / Nichttragend: yes
Pset_WallCommon - IsExternal: yes; ThermalTransmittance: 1.43551 kg/K/s3

# IfcWallType, no part of this type: Basiswand:Ziegel 440 verputzt 2s chancel
PredefinedType: STANDARD; Material: Mauerwerk - Kalkputz-white 0.03 m, Mauerwerk - Sichtmauerwerk 0.38 m, Mauerwerk - Kalkputz-white 0.03 m
Analytische Eigenschaften - Rauigkeit: 1; Absorptionsgrad: 0.1; Thermischer Widerstand (R): 0.724393; Thermisch wirksame Masse: 633.36; Wärmedurchgangskoeffizient (U): 1.38047 kg/K/s3
Grafiken - Füllmuster für groben Maßstab: <Flächenfüllung>; Farbfüllung für groben Maßstab: 255
ID-Daten - Beschreibung: Ziegel_430; Typname: Ziegel 440 verputzt 2s chancel
Konstruktion - Abschluss an Öffnungen: Beide; Abschluss an Wänden: Keine; Funktion: Außen; Breite: 0.44 m
Materialien und Oberflächen - Tragendes Material: Mauerwerk - Sichtmauerwerk
Sonstige - Kategorie: Wände; Familienname: Basiswand
Tragwerk - Filter Tragend / Nichttragend: yes
Pset_WallCommon - IsExternal: yes; ThermalTransmittance: 1.38047 kg/K/s3

# IfcWallType, no part of this type: Basiswand:Ziegel 440-plinth
PredefinedType: STANDARD; Material: Mauerwerk - Sichtmauerwerk_72x265 english bond Stage2 0.44 m
Analytische Eigenschaften - Rauigkeit: 1; Absorptionsgrad: 0.1; Thermischer Widerstand (R): 0.814815; Thermisch wirksame Masse: 572.88; Wärmedurchgangskoeffizient (U): 1.22727 kg/K/s3
Grafiken - Füllmuster für groben Maßstab: <Flächenfüllung>; Farbfüllung für groben Maßstab: 255
ID-Daten - Beschreibung: Ziegel_500; Typname: Ziegel 440-plinth
Konstruktion - Abschluss an Wänden: Keine; Funktion: Außen; Abschluss an Öffnungen: Keine; Breite: 0.44 m
Materialien und Oberflächen - Tragendes Material: Mauerwerk - Sichtmauerwerk_72x265 english bond Stage2
Sonstige - Kategorie: Wände; Familienname: Basiswand
Tragwerk - Filter Tragend / Nichttragend: yes
Pset_WallCommon - IsExternal: yes; ThermalTransmittance: 1.22727 kg/K/s3

# IfcWallType, no part of this type: Basiswand:Ziegel 468 verputz1s farbig 72
PredefinedType: STANDARD; Material: Mauerwerk - Sichtmauerwerk_72x265 english bond 0.438 m, 3D - Schnittmaterial 0.03 m
Analytische Eigenschaften - Rauigkeit: 1; Absorptionsgrad: 0.1; Thermischer Widerstand (R): 0.811111; Thermisch wirksame Masse: 570.276; Wärmedurchgangskoeffizient (U): 1.23288 kg/K/s3
Grafiken - Füllmuster für groben Maßstab: <Flächenfüllung>; Farbfüllung für groben Maßstab: 255
ID-Daten - Beschreibung: Ziegel_500; Typname: Ziegel 468 verputz1s farbig 72
Konstruktion - Funktion: Außen; Abschluss an Öffnungen: Keine; Abschluss an Wänden: Außen; Breite: 0.468 m
Sonstige - Kategorie: Wände; Familienname: Basiswand
Tragwerk - Filter Tragend / Nichttragend: yes
Pset_WallCommon - IsExternal: yes; ThermalTransmittance: 1.23288 kg/K/s3

# IfcWallType, no part of this type: Basiswand:Ziegel 493 Tower lobby Stage 2
PredefinedType: STANDARD; Material: Mauerwerk - Kalkputz-white 0.02 m, Quoin Brick 0.454 m, Mauerwerk - Kalkputz-white 0.02 m
Analytische Eigenschaften - Rauigkeit: 1; Absorptionsgrad: 0.1; Thermischer Widerstand (R): 0.0137931; Thermisch wirksame Masse: 92.4; Wärmedurchgangskoeffizient (U): 72.5 kg/K/s3
Grafiken - Füllmuster für groben Maßstab: <Flächenfüllung>; Farbfüllung für groben Maßstab: 255
ID-Daten - Beschreibung: Ziegel_120; Typname: Ziegel 493 Tower lobby Stage 2
Konstruktion - Abschluss an Wänden: Keine; Funktion: Außen; Abschluss an Öffnungen: Keine; Breite: 0.494 m
Sonstige - Kategorie: Wände; Familienname: Basiswand
Tragwerk - Filter Tragend / Nichttragend: no
Pset_WallCommon - IsExternal: yes; ThermalTransmittance: 72.5 kg/K/s3

# IfcWallType, no part of this type: Basiswand:Ziegel 498-farbig Office base Phase 2
PredefinedType: STANDARD; Material: Mauerwerk - Sichtmauerwerk_72x265 english bond Stage2 0.498 m
Analytische Eigenschaften - Rauigkeit: 1; Absorptionsgrad: 0.1; Thermischer Widerstand (R): 0.922222; Thermisch wirksame Masse: 648.396; Wärmedurchgangskoeffizient (U): 1.08434 kg/K/s3
Grafiken - Füllmuster für groben Maßstab: <Flächenfüllung>; Farbfüllung für groben Maßstab: 255
ID-Daten - Beschreibung: Ziegel_500; Typname: Ziegel 498-farbig Office base Phase 2
Konstruktion - Funktion: Außen; Abschluss an Öffnungen: Außen; Abschluss an Wänden: Innen; Breite: 0.498 m
Sonstige - Kategorie: Wände; Familienname: Basiswand
Tragwerk - Filter Tragend / Nichttragend: yes
Pset_WallCommon - IsExternal: yes; ThermalTransmittance: 1.08434 kg/K/s3

# IfcWallType, no part of this type: Basiswand:Ziegel 510 farbig 72x265 Stage 1 Apse pier
PredefinedType: STANDARD; Material: Mauerwerk - Sichtmauerwerk_72x265 english bond 0.51 m
Analytische Eigenschaften - Rauigkeit: 1; Absorptionsgrad: 0.1; Thermischer Widerstand (R): 0.944444; Thermisch wirksame Masse: 664.02; Wärmedurchgangskoeffizient (U): 1.05882 kg/K/s3
Grafiken - Füllmuster für groben Maßstab: <Flächenfüllung>; Farbfüllung für groben Maßstab: 255
ID-Daten - Beschreibung: Ziegel_500; Typname: Ziegel 510 farbig 72x265 Stage 1 Apse pier
Konstruktion - Funktion: Außen; Abschluss an Öffnungen: Keine; Abschluss an Wänden: Außen; Breite: 0.51 m
Sonstige - Kategorie: Wände; Familienname: Basiswand
Tragwerk - Filter Tragend / Nichttragend: yes
Pset_WallCommon - IsExternal: yes; ThermalTransmittance: 1.05882 kg/K/s3

# IfcWallType, no part of this type: Basiswand:Ziegel 510 plinth
PredefinedType: STANDARD; Material: Mauerwerk - Sichtmauerwerk_72x265 english bond Stage2 0.51 m
Analytische Eigenschaften - Rauigkeit: 1; Absorptionsgrad: 0.1; Thermischer Widerstand (R): 0.944444; Thermisch wirksame Masse: 664.02; Wärmedurchgangskoeffizient (U): 1.05882 kg/K/s3
Grafiken - Füllmuster für groben Maßstab: <Flächenfüllung>; Farbfüllung für groben Maßstab: 255
ID-Daten - Beschreibung: Ziegel_500; Typname: Ziegel 510 plinth
Konstruktion - Abschluss an Wänden: Keine; Funktion: Außen; Abschluss an Öffnungen: Keine; Breite: 0.51 m
Materialien und Oberflächen - Tragendes Material: Mauerwerk - Sichtmauerwerk_72x265 english bond Stage2
Sonstige - Kategorie: Wände; Familienname: Basiswand
Tragwerk - Filter Tragend / Nichttragend: yes
Pset_WallCommon - IsExternal: yes; ThermalTransmittance: 1.05882 kg/K/s3

# IfcWallType, no part of this type: Basiswand:Ziegel 515 farbig 72x265 Stage 2 Office pier
PredefinedType: STANDARD; Material: Mauerwerk - Sichtmauerwerk_72x265 english bond Stage2 0.515 m
Analytische Eigenschaften - Rauigkeit: 1; Absorptionsgrad: 0.1; Thermischer Widerstand (R): 0.953704; Thermisch wirksame Masse: 670.53; Wärmedurchgangskoeffizient (U): 1.04854 kg/K/s3
Grafiken - Füllmuster für groben Maßstab: <Flächenfüllung>; Farbfüllung für groben Maßstab: 255
ID-Daten - Beschreibung: Ziegel_500; Typname: Ziegel 515 farbig 72x265 Stage 2 Office pier
Konstruktion - Funktion: Außen; Abschluss an Öffnungen: Keine; Abschluss an Wänden: Außen; Breite: 0.515 m
Sonstige - Kategorie: Wände; Familienname: Basiswand
Tragwerk - Filter Tragend / Nichttragend: yes
Pset_WallCommon - IsExternal: yes; ThermalTransmittance: 1.04854 kg/K/s3

# IfcWallType, no part of this type: Basiswand:Ziegel 520 farbig verputzt 1s 72 English bond 2
PredefinedType: STANDARD; Material: Mauerwerk - Sichtmauerwerk_72x265 english bond 0.48 m, Mauerwerk - Kalkputz-white 0.04 m
Analytische Eigenschaften - Rauigkeit: 1; Absorptionsgrad: 0.1; Thermischer Widerstand (R): 0.902682; Thermisch wirksame Masse: 717.36; Wärmedurchgangskoeffizient (U): 1.10781 kg/K/s3
Grafiken - Füllmuster für groben Maßstab: <Flächenfüllung>; Farbfüllung für groben Maßstab: 4210816
ID-Daten - Beschreibung: Ziegel 620 farbig verputzt 1s 72 English bond; Typname: Ziegel 520 farbig verputzt 1s 72 English bond 2
Konstruktion - Abschluss an Wänden: Keine; Funktion: Außen; Abschluss an Öffnungen: Innen; Breite: 0.52 m
Sonstige - Kategorie: Wände; Familienname: Basiswand
Tragwerk - Filter Tragend / Nichttragend: yes
Pset_WallCommon - IsExternal: yes; ThermalTransmittance: 1.10781 kg/K/s3

# IfcWallType, no part of this type: Basiswand:Ziegel 520 farbig verputzt 2s 72 English bond
PredefinedType: STANDARD; Material: Mauerwerk - Kalkputz-white 0.04 m, Mauerwerk - Sichtmauerwerk_72x265 english bond 0.44 m, Mauerwerk - Kalkputz-white 0.04 m
Analytische Eigenschaften - Rauigkeit: 1; Absorptionsgrad: 0.1; Thermischer Widerstand (R): 0.842401; Thermisch wirksame Masse: 757.68; Wärmedurchgangskoeffizient (U): 1.18708 kg/K/s3
Grafiken - Füllmuster für groben Maßstab: <Flächenfüllung>; Farbfüllung für groben Maßstab: 4210816
ID-Daten - Beschreibung: Ziegel 620 farbig verputzt 1s 72 English bond; Typname: Ziegel 520 farbig verputzt 2s 72 English bond
Konstruktion - Abschluss an Öffnungen: Beide; Abschluss an Wänden: Innen; Funktion: Innen; Breite: 0.52 m
Sonstige - Kategorie: Wände; Familienname: Basiswand
Tragwerk - Filter Tragend / Nichttragend: yes
Pset_WallCommon - IsExternal: no; ThermalTransmittance: 1.18708 kg/K/s3

# IfcWallType, no part of this type: Basiswand:Ziegel 527 Apse plinth
PredefinedType: STANDARD; Material: Mauerwerk - Sichtmauerwerk_72x265 english bond Stage2 0.53 m
Analytische Eigenschaften - Rauigkeit: 1; Absorptionsgrad: 0.1; Thermischer Widerstand (R): 0.981481; Thermisch wirksame Masse: 690.06; Wärmedurchgangskoeffizient (U): 1.01887 kg/K/s3
Grafiken - Füllmuster für groben Maßstab: <Flächenfüllung>; Farbfüllung für groben Maßstab: 255
ID-Daten - Beschreibung: Ziegel_527; Typname: Ziegel 527 Apse plinth
Konstruktion - Abschluss an Wänden: Keine; Funktion: Außen; Abschluss an Öffnungen: Keine; Breite: 0.53 m
Materialien und Oberflächen - Tragendes Material: Mauerwerk - Sichtmauerwerk_72x265 english bond Stage2
Sonstige - Kategorie: Wände; Familienname: Basiswand
Tragwerk - Filter Tragend / Nichttragend: yes
Pset_WallCommon - IsExternal: yes; ThermalTransmittance: 1.01887 kg/K/s3

# IfcWallType, no part of this type: Basiswand:Ziegel 528-farbig Office base Stage 2
PredefinedType: STANDARD; Material: Mauerwerk - Sichtmauerwerk_72x265 english bond Stage2 0.528 m
Analytische Eigenschaften - Rauigkeit: 1; Absorptionsgrad: 0.1; Thermischer Widerstand (R): 0.977778; Thermisch wirksame Masse: 687.456; Wärmedurchgangskoeffizient (U): 1.02273 kg/K/s3
Grafiken - Füllmuster für groben Maßstab: <Flächenfüllung>; Farbfüllung für groben Maßstab: 255
ID-Daten - Beschreibung: Ziegel_500; Typname: Ziegel 528-farbig Office base Stage 2
Konstruktion - Funktion: Außen; Abschluss an Öffnungen: Außen; Abschluss an Wänden: Innen; Breite: 0.528 m
Sonstige - Kategorie: Wände; Familienname: Basiswand
Tragwerk - Filter Tragend / Nichttragend: yes
Pset_WallCommon - IsExternal: yes; ThermalTransmittance: 1.02273 kg/K/s3

# IfcWallType, no part of this type: Basiswand:Ziegel 528-farbig Putz Office Stage 2
PredefinedType: STANDARD; Material: Mauerwerk - Kalkputz-white 0.03 m, Mauerwerk - Sichtmauerwerk_72x265 english bond Stage2 0.498 m
Analytische Eigenschaften - Rauigkeit: 1; Absorptionsgrad: 0.1; Thermischer Widerstand (R): 0.932567; Thermisch wirksame Masse: 717.696; Wärmedurchgangskoeffizient (U): 1.07231 kg/K/s3
Grafiken - Füllmuster für groben Maßstab: <Flächenfüllung>; Farbfüllung für groben Maßstab: 255
ID-Daten - Beschreibung: Ziegel_500; Typname: Ziegel 528-farbig Putz Office Stage 2
Konstruktion - Funktion: Außen; Abschluss an Öffnungen: Außen; Abschluss an Wänden: Innen; Breite: 0.528 m
Sonstige - Kategorie: Wände; Familienname: Basiswand
Tragwerk - Filter Tragend / Nichttragend: yes
Pset_WallCommon - IsExternal: yes; ThermalTransmittance: 1.07231 kg/K/s3

# IfcWallType, no part of this type: Basiswand:Ziegel 564-farbig Putz Office Stage 2
PredefinedType: STANDARD; Material: Mauerwerk - Kalkputz-white 0.03 m, Mauerwerk - Sichtmauerwerk_72x265 english bond Stage2 0.534 m
Analytische Eigenschaften - Rauigkeit: 1; Absorptionsgrad: 0.1; Thermischer Widerstand (R): 0.999234; Thermisch wirksame Masse: 764.568; Wärmedurchgangskoeffizient (U): 1.00077 kg/K/s3
Grafiken - Füllmuster für groben Maßstab: <Flächenfüllung>; Farbfüllung für groben Maßstab: 255
ID-Daten - Beschreibung: Ziegel_500; Typname: Ziegel 564-farbig Putz Office Stage 2
Konstruktion - Funktion: Außen; Abschluss an Öffnungen: Außen; Abschluss an Wänden: Innen; Breite: 0.564 m
Sonstige - Kategorie: Wände; Familienname: Basiswand
Tragwerk - Filter Tragend / Nichttragend: yes
Pset_WallCommon - IsExternal: yes; ThermalTransmittance: 1.00077 kg/K/s3

# IfcWallType, no part of this type: Basiswand:Ziegel 565 farbig 72x265 Putz
PredefinedType: STANDARD; Material: Mauerwerk - Kalkputz-white 0.03 m, Mauerwerk - Sichtmauerwerk_72x265 english bond 0.535 m
Analytische Eigenschaften - Rauigkeit: 1; Absorptionsgrad: 0.1; Thermischer Widerstand (R): 1.00109; Thermisch wirksame Masse: 765.87; Wärmedurchgangskoeffizient (U): 0.998916 kg/K/s3
Grafiken - Füllmuster für groben Maßstab: <Flächenfüllung>; Farbfüllung für groben Maßstab: 255
ID-Daten - Beschreibung: Ziegel_380; Typname: Ziegel 565 farbig 72x265 Putz
Konstruktion - Abschluss an Wänden: Keine; Funktion: Außen; Abschluss an Öffnungen: Keine; Breite: 0.565 m
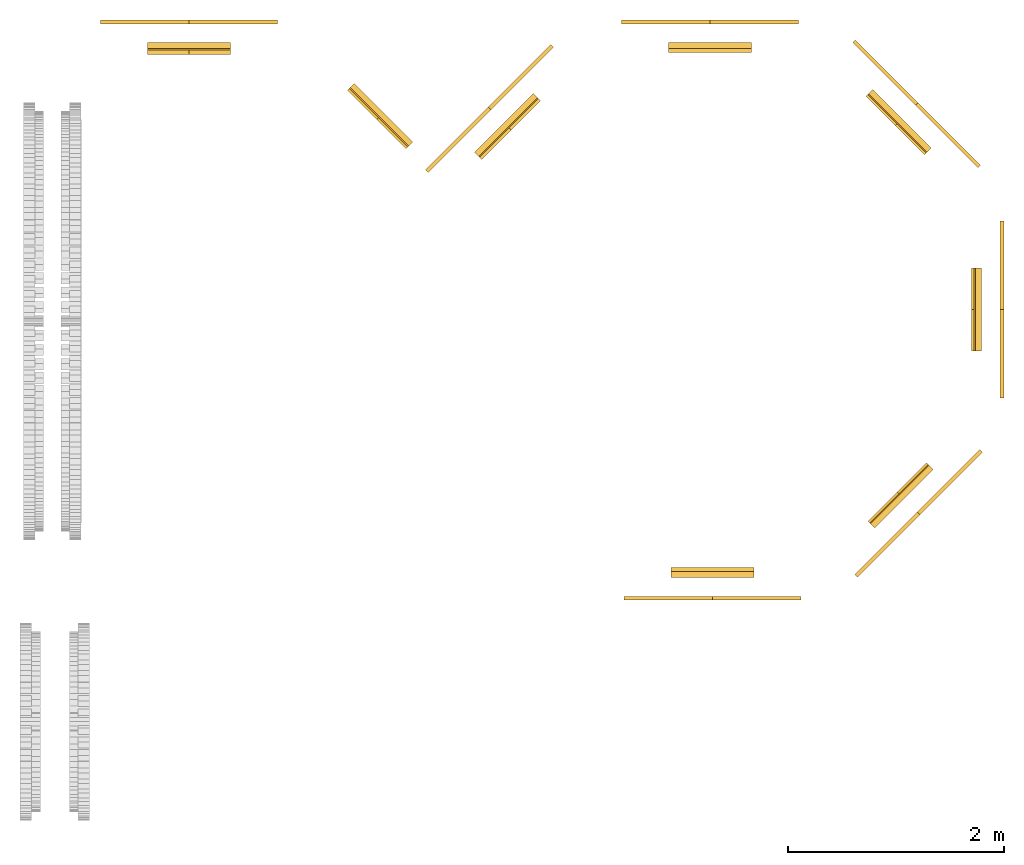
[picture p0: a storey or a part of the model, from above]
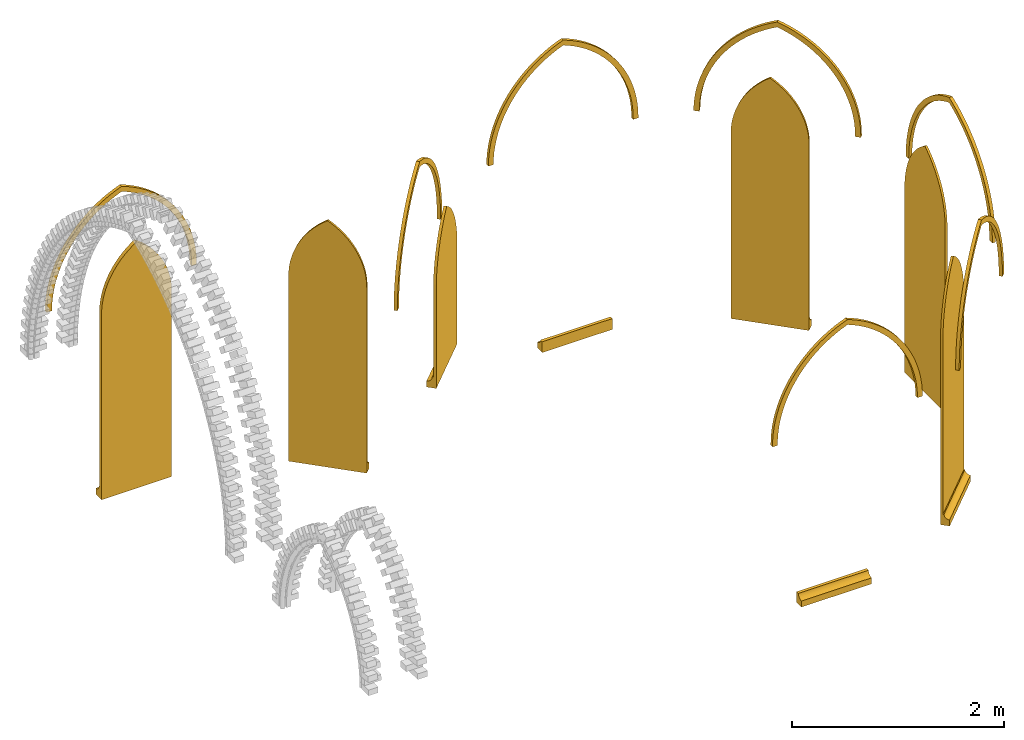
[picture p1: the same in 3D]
Properties of the parts of a building model (IFC2X3), part 7 of 7

# IfcWallType, no part of this type: Basiswand:Ziegel 565 farbig 72x265 Putz
Sonstige - Kategorie: Wände; Familienname: Basiswand
Tragwerk - Filter Tragend / Nichttragend: yes
Pset_WallCommon - IsExternal: yes; ThermalTransmittance: 0.998916 kg/K/s3

# IfcWallType, no part of this type: Basiswand:Ziegel 566-farbig Office base Stage 4
PredefinedType: STANDARD; Material: Mauerwerk - Sichtmauerwerk_72x265 english bond Stage2 0.566 m
Analytische Eigenschaften - Rauigkeit: 1; Absorptionsgrad: 0.1; Thermischer Widerstand (R): 1.04815; Thermisch wirksame Masse: 736.932; Wärmedurchgangskoeffizient (U): 0.954064 kg/K/s3
Grafiken - Füllmuster für groben Maßstab: <Flächenfüllung>; Farbfüllung für groben Maßstab: 255
ID-Daten - Beschreibung: Ziegel_500; Typname: Ziegel 566-farbig Office base Stage 4
Konstruktion - Funktion: Außen; Abschluss an Öffnungen: Außen; Abschluss an Wänden: Innen; Breite: 0.566 m
Sonstige - Kategorie: Wände; Familienname: Basiswand
Tragwerk - Filter Tragend / Nichttragend: yes
Pset_WallCommon - IsExternal: yes; ThermalTransmittance: 0.954064 kg/K/s3

# IfcWallType, no part of this type: Basiswand:Ziegel 569 farbig 72x265 Putz
PredefinedType: STANDARD; Material: Mauerwerk - Kalkputz-white 0.03 m, Mauerwerk - Sichtmauerwerk_72x265 english bond 0.54 m
Analytische Eigenschaften - Rauigkeit: 1; Absorptionsgrad: 0.1; Thermischer Widerstand (R): 1.01034; Thermisch wirksame Masse: 772.38; Wärmedurchgangskoeffizient (U): 0.989761 kg/K/s3
Grafiken - Füllmuster für groben Maßstab: <Flächenfüllung>; Farbfüllung für groben Maßstab: 255
ID-Daten - Beschreibung: Ziegel_380; Typname: Ziegel 569 farbig 72x265 Putz
Konstruktion - Abschluss an Wänden: Keine; Funktion: Außen; Abschluss an Öffnungen: Keine; Breite: 0.57 m
Sonstige - Kategorie: Wände; Familienname: Basiswand
Tragwerk - Filter Tragend / Nichttragend: yes
Pset_WallCommon - IsExternal: yes; ThermalTransmittance: 0.989761 kg/K/s3

# IfcWallType, no part of this type: Basiswand:Ziegel 605-farbig 2s putz Stage 1 Basis
PredefinedType: STANDARD; Material: Mauerwerk - Kalkputz-white 0.03 m, Mauerwerk - Sichtmauerwerk_72x265 english bond 0.55 m, Mauerwerk - Kalkputz-white 0.03 m
Analytische Eigenschaften - Rauigkeit: 1; Absorptionsgrad: 0.1; Thermischer Widerstand (R): 1.03921; Thermisch wirksame Masse: 854.7; Wärmedurchgangskoeffizient (U): 0.962271 kg/K/s3
Grafiken - Füllmuster für groben Maßstab: <Flächenfüllung>; Farbfüllung für groben Maßstab: 255
ID-Daten - Beschreibung: Ziegel_500; Typname: Ziegel 605-farbig 2s putz Stage 1 Basis
Konstruktion - Abschluss an Wänden: Keine; Funktion: Außen; Abschluss an Öffnungen: Außen; Breite: 0.61 m
Sonstige - Kategorie: Wände; Familienname: Basiswand
Tragwerk - Filter Tragend / Nichttragend: yes
Pset_WallCommon - IsExternal: yes; ThermalTransmittance: 0.962271 kg/K/s3

# IfcWallType, no part of this type: Basiswand:Ziegel 635 verputzt 2s pulpit arch Stage 1 Basis
PredefinedType: STANDARD; Material: Mauerwerk - Kalkputz-white 0.03 m, Mauerwerk - Sichtmauerwerk 0.575 m, Mauerwerk - Kalkputz-white 0.03 m
Analytische Eigenschaften - Rauigkeit: 1; Absorptionsgrad: 0.1; Thermischer Widerstand (R): 1.0855; Thermisch wirksame Masse: 887.25; Wärmedurchgangskoeffizient (U): 0.921231 kg/K/s3
Grafiken - Füllmuster für groben Maßstab: <Flächenfüllung>; Farbfüllung für groben Maßstab: 16777215
ID-Daten - Beschreibung: Ziegel_430; Typname: Ziegel 635 verputzt 2s pulpit arch Stage 1 Basis
Konstruktion - Abschluss an Öffnungen: Beide; Abschluss an Wänden: Keine; Funktion: Außen; Breite: 0.635 m
Materialien und Oberflächen - Tragendes Material: Mauerwerk - Sichtmauerwerk
Sonstige - Kategorie: Wände; Familienname: Basiswand
Tragwerk - Filter Tragend / Nichttragend: yes
Pset_WallCommon - IsExternal: yes; ThermalTransmittance: 0.921231 kg/K/s3

# IfcWallType, no part of this type: Basiswand:Ziegel 635-farbig 72x265 English bond Stage 2
PredefinedType: STANDARD; Material: Mauerwerk - Kalkputz-white 0.035 m, Mauerwerk - Sichtmauerwerk_72x265 english bond Stage2 0.6 m
Analytische Eigenschaften - Rauigkeit: 1; Absorptionsgrad: 0.1; Thermischer Widerstand (R): 1.11111; Thermisch wirksame Masse: 781.2; Wärmedurchgangskoeffizient (U): 0.9 kg/K/s3
Grafiken - Füllmuster für groben Maßstab: <Flächenfüllung>; Farbfüllung für groben Maßstab: 255
ID-Daten - Beschreibung: Ziegel_500; Typname: Ziegel 635-farbig 72x265 English bond Stage 2
Konstruktion - Abschluss an Wänden: Keine; Funktion: Außen; Abschluss an Öffnungen: Keine; Breite: 0.635 m
Sonstige - Kategorie: Wände; Familienname: Basiswand
Tragwerk - Filter Tragend / Nichttragend: yes
Pset_WallCommon - IsExternal: yes; ThermalTransmittance: 0.9 kg/K/s3

# IfcWallType, no part of this type: Basiswand:Ziegel 640-plinth
PredefinedType: STANDARD; Material: Mauerwerk - Sichtmauerwerk_72x265 english bond Stage2 0.64 m
Analytische Eigenschaften - Rauigkeit: 1; Absorptionsgrad: 0.1; Thermischer Widerstand (R): 1.18519; Thermisch wirksame Masse: 833.28; Wärmedurchgangskoeffizient (U): 0.84375 kg/K/s3
Grafiken - Füllmuster für groben Maßstab: <Flächenfüllung>; Farbfüllung für groben Maßstab: 255
ID-Daten - Beschreibung: Ziegel_500; Typname: Ziegel 640-plinth
Konstruktion - Abschluss an Wänden: Keine; Funktion: Außen; Abschluss an Öffnungen: Keine; Breite: 0.64 m
Materialien und Oberflächen - Tragendes Material: Mauerwerk - Sichtmauerwerk_72x265 english bond Stage2
Sonstige - Kategorie: Wände; Familienname: Basiswand
Tragwerk - Filter Tragend / Nichttragend: yes
Pset_WallCommon - IsExternal: yes; ThermalTransmittance: 0.84375 kg/K/s3

# IfcWallType, no part of this type: Basiswand:Ziegel 670 putz 2s Chancel East side
PredefinedType: STANDARD; Material: Mauerwerk - Kalkputz-white 0.02 m, Mauerwerk - Ziegel 0.63 m, Mauerwerk - Kalkputz-white 0.02 m
Analytische Eigenschaften - Rauigkeit: 1; Absorptionsgrad: 0.1; Thermischer Widerstand (R): 1.18046; Thermisch wirksame Masse: 912.66; Wärmedurchgangskoeffizient (U): 0.847128 kg/K/s3
Grafiken - Füllmuster für groben Maßstab: <Flächenfüllung>; Farbfüllung für groben Maßstab: 255
ID-Daten - Beschreibung: Ziegel_240; Typname: Ziegel 670 putz 2s Chancel East side
Konstruktion - Abschluss an Öffnungen: Beide; Abschluss an Wänden: Keine; Funktion: Innen; Breite: 0.67 m
Sonstige - Kategorie: Wände; Familienname: Basiswand
Tragwerk - Filter Tragend / Nichttragend: yes
Pset_WallCommon - IsExternal: no; ThermalTransmittance: 0.847128 kg/K/s3

# IfcWallType, no part of this type: Basiswand:Ziegel 68 farbig 72x265 English bond Plinth Stage 2
PredefinedType: STANDARD; Material: Mauerwerk - Sichtmauerwerk_72x265 english bond Stage2 0.068 m
Analytische Eigenschaften - Rauigkeit: 1; Absorptionsgrad: 0.1; Thermischer Widerstand (R): 0.125926; Thermisch wirksame Masse: 88.536; Wärmedurchgangskoeffizient (U): 7.94118 kg/K/s3
Grafiken - Füllmuster für groben Maßstab: <Flächenfüllung>; Farbfüllung für groben Maßstab: 255
ID-Daten - Beschreibung: Ziegel_125; Typname: Ziegel 68 farbig 72x265 English bond Plinth Stage 2
Konstruktion - Funktion: Außen; Abschluss an Wänden: Außen; Abschluss an Öffnungen: Außen; Breite: 0.068 m
Materialien und Oberflächen - Tragendes Material: Mauerwerk - Sichtmauerwerk_72x265 english bond Stage2
Sonstige - Kategorie: Wände; Familienname: Basiswand
Tragwerk - Filter Tragend / Nichttragend: no
Pset_WallCommon - IsExternal: yes; ThermalTransmittance: 7.94118 kg/K/s3

# IfcWallType, no part of this type: Basiswand:Ziegel 73 farbig 72x265 English bond Plinth Stage 2
PredefinedType: STANDARD; Material: Mauerwerk - Sichtmauerwerk_72x265 english bond Stage2 0.073 m
Analytische Eigenschaften - Rauigkeit: 1; Absorptionsgrad: 0.1; Thermischer Widerstand (R): 0.135185; Thermisch wirksame Masse: 95.046; Wärmedurchgangskoeffizient (U): 7.39726 kg/K/s3
Grafiken - Füllmuster für groben Maßstab: <Flächenfüllung>; Farbfüllung für groben Maßstab: 255
ID-Daten - Beschreibung: Ziegel_125; Typname: Ziegel 73 farbig 72x265 English bond Plinth Stage 2
Konstruktion - Funktion: Außen; Abschluss an Wänden: Außen; Abschluss an Öffnungen: Außen; Breite: 0.073 m
Materialien und Oberflächen - Tragendes Material: Mauerwerk - Sichtmauerwerk_72x265 english bond Stage2
Sonstige - Kategorie: Wände; Familienname: Basiswand
Tragwerk - Filter Tragend / Nichttragend: no
Pset_WallCommon - IsExternal: yes; ThermalTransmittance: 7.39726 kg/K/s3

# IfcWallType, no part of this type: Basiswand:Ziegel 775 72x265 English bond Stage 5
PredefinedType: STANDARD; Material: Mauerwerk - Sichtmauerwerk_72x265 english bond Stage2 0.775 m
Analytische Eigenschaften - Rauigkeit: 1; Absorptionsgrad: 0.1; Thermischer Widerstand (R): 1.43519; Thermisch wirksame Masse: 1009.05; Wärmedurchgangskoeffizient (U): 0.696774 kg/K/s3
Grafiken - Füllmuster für groben Maßstab: <Flächenfüllung>; Farbfüllung für groben Maßstab: 255
ID-Daten - Beschreibung: Ziegel_500; Typname: Ziegel 775 72x265 English bond Stage 5
Konstruktion - Funktion: Außen; Abschluss an Öffnungen: Keine; Abschluss an Wänden: Außen; Breite: 0.775 m
Sonstige - Kategorie: Wände; Familienname: Basiswand
Tragwerk - Filter Tragend / Nichttragend: yes
Pset_WallCommon - IsExternal: yes; ThermalTransmittance: 0.696774 kg/K/s3

# IfcWallType, no part of this type: Basiswand:Ziegel 780 72x265 English bond Stage 1 Main pier
PredefinedType: STANDARD; Material: Mauerwerk - Sichtmauerwerk_72x265 english bond 0.78 m
Analytische Eigenschaften - Rauigkeit: 1; Absorptionsgrad: 0.1; Thermischer Widerstand (R): 1.44444; Thermisch wirksame Masse: 1015.56; Wärmedurchgangskoeffizient (U): 0.692308 kg/K/s3
Grafiken - Füllmuster für groben Maßstab: <Flächenfüllung>; Farbfüllung für groben Maßstab: 255
ID-Daten - Beschreibung: Ziegel_500; Typname: Ziegel 780 72x265 English bond Stage 1 Main pier
Konstruktion - Funktion: Außen; Abschluss an Öffnungen: Keine; Abschluss an Wänden: Außen; Breite: 0.78 m
Sonstige - Kategorie: Wände; Familienname: Basiswand
Tragwerk - Filter Tragend / Nichttragend: yes
Pset_WallCommon - IsExternal: yes; ThermalTransmittance: 0.692308 kg/K/s3

# IfcWallType, no part of this type: Basiswand:Ziegel 780 72x265 English bond Stage 2 Tower pier
PredefinedType: STANDARD; Material: Mauerwerk - Sichtmauerwerk_72x265 english bond Stage2 0.78 m
Analytische Eigenschaften - Rauigkeit: 1; Absorptionsgrad: 0.1; Thermischer Widerstand (R): 1.44444; Thermisch wirksame Masse: 1015.56; Wärmedurchgangskoeffizient (U): 0.692308 kg/K/s3
Grafiken - Füllmuster für groben Maßstab: <Flächenfüllung>; Farbfüllung für groben Maßstab: 255
ID-Daten - Beschreibung: Ziegel_500; Typname: Ziegel 780 72x265 English bond Stage 2 Tower pier
Konstruktion - Funktion: Außen; Abschluss an Öffnungen: Keine; Abschluss an Wänden: Außen; Breite: 0.78 m
Sonstige - Kategorie: Wände; Familienname: Basiswand
Tragwerk - Filter Tragend / Nichttragend: yes
Pset_WallCommon - IsExternal: yes; ThermalTransmittance: 0.692308 kg/K/s3

# IfcWallType, no part of this type: Basiswand:Ziegel 90 Projecting facade Stage1 North
PredefinedType: STANDARD; Material: Mauerwerk - Sichtmauerwerk_72x265 english bond 0.09 m
Analytische Eigenschaften - Rauigkeit: 1; Absorptionsgrad: 0.1; Thermischer Widerstand (R): 0.166667; Thermisch wirksame Masse: 117.18; Wärmedurchgangskoeffizient (U): 6 kg/K/s3
Grafiken - Füllmuster für groben Maßstab: <Flächenfüllung>; Farbfüllung für groben Maßstab: 255
ID-Daten - Beschreibung: Ziegel_120; Typname: Ziegel 90 Projecting facade Stage1 North
Konstruktion - Funktion: Außen; Abschluss an Öffnungen: Keine; Abschluss an Wänden: Außen; Breite: 0.09 m
Sonstige - Kategorie: Wände; Familienname: Basiswand
Tragwerk - Filter Tragend / Nichttragend: no
Pset_WallCommon - IsExternal: yes; ThermalTransmittance: 6 kg/K/s3

# IfcWindowStyle, no part of this type: Arched_Window_Main_A:Arched_Window_
ParameterTakesPrecedence: no; Sizeable: no; Material: <Unnamed> (3), Mauerwerk - Sandstein Rot (3), Fußboden - Estrich
Analytische Eigenschaften - Thermische Eigenschaften definieren durch: Schemaplantypen; Analytische Konstruktion: <Keine Auswahl>
Bemaßungen - Breite: 2.59 m; BreiteInnen: 2 m; Cill: 0.04 m; CillDepth: 0.3 m; CillLevel: 0.58 m; CillOverhang: 0.04 m; ExteriorCill: 0.34 m; GlassThickness: 0.01 m; Höhe: 5.975 m; WidthTracery: 2 m
ID-Daten - Hersteller: Jeffrey P. Fazzone; Typenmarkierung: 283; Typname: Arched_Window_; URL: www.DPlusP.com
Konstruktion - Wandabschluss: Nach Basisbauteil
Materialien und Oberflächen - CillMaterial: Fußboden - Estrich; MullionMaterial: Mauerwerk - Sandstein Rot; PanelMaterial: Glass; RevealMaterial: Mauerwerk - Sandstein Rot
Sonstige - Kategorie: Fenster; Default Sill Height: 0 m; Familienname: Arched_Window_Main_A; HalfGlassThickness: 0.005 m
Pset_ManufacturerTypeInformation - Manufacturer: Jeffrey P. Fazzone
Pset_WindowCommon - IsExternal: no

# IfcWindowStyle, no part of this type: BellTowerOpening:BellTowerOpening
ParameterTakesPrecedence: no; Sizeable: no; Material: Mauerwerk - Sandstein Rot (2), Mauerwerk - Sichtmauerwerk_72x265 english bond Stage2, Holz - generisch 50-50-50 (62)
Analytische Eigenschaften - Thermische Eigenschaften definieren durch: Schemaplantypen; Analytische Konstruktion: <Keine Auswahl>
Bemaßungen - ArchHeight: 1.512 m; Breite: 2 m; Höhe: 4.176 m; MullionWidth: 0.0948571 m; OpeningWidth: 0.7395 m; OuterArchHeight: 2.5 m; PostWidth: 0.08 m; SetBack: 0.2 m; TraceryThickness: 0.25 m
ID-Daten - OmniClass-Nummer: 23.30.20.00; OmniClass-Titel: Windows; Typenmarkierung: 267; Typname: BellTowerOpening
Konstruktion - Wandabschluss: Nach Basisbauteil
Materialien und Oberflächen - LouvreMaterial: Holz - generisch 50-50-50; RevealMaterial: Mauerwerk - Sichtmauerwerk_72x265 english bond Stage2; TraceryMaterial: Mauerwerk - Sandstein Rot
Sonstige - Kategorie: Fenster; Familienname: BellTowerOpening; NoBlades: 30; Vorgabewert für Einbauhöhe: 0 m
Pset_WindowCommon - IsExternal: no

# IfcWindowStyle, no part of this type: BellTowerOpening:BellTowerOpening
ParameterTakesPrecedence: no; Sizeable: no; Material: Mauerwerk - Sandstein Rot (2), Mauerwerk - Sichtmauerwerk_72x265 english bond Stage2, Holz - generisch 50-50-50 (62)
Analytische Eigenschaften - Thermische Eigenschaften definieren durch: Schemaplantypen; Analytische Konstruktion: <Keine Auswahl>
Bemaßungen - ArchHeight: 1.512 m; Breite: 2 m; Höhe: 4.176 m; MullionWidth: 0.0948571 m; OpeningWidth: 0.7395 m; OuterArchHeight: 2.5 m; PostWidth: 0.08 m; SetBack: 0.2 m; TraceryThickness: 0.25 m
ID-Daten - OmniClass-Nummer: 23.30.20.00; OmniClass-Titel: Windows; Typenmarkierung: 267; Typname: BellTowerOpening
Konstruktion - Wandabschluss: Nach Basisbauteil
Materialien und Oberflächen - LouvreMaterial: Holz - generisch 50-50-50; RevealMaterial: Mauerwerk - Sichtmauerwerk_72x265 english bond Stage2; TraceryMaterial: Mauerwerk - Sandstein Rot
Sonstige - Kategorie: Fenster; Familienname: BellTowerOpening; NoBlades: 30; Vorgabewert für Einbauhöhe: 0 m
Pset_WindowCommon - IsExternal: no

# IfcWindowStyle, no part of this type: BellTowerOpening:BellTowerOpening
ParameterTakesPrecedence: no; Sizeable: no; Material: Mauerwerk - Sandstein Rot (2), Mauerwerk - Sichtmauerwerk_72x265 english bond Stage2, Holz - generisch 50-50-50 (62)
Analytische Eigenschaften - Thermische Eigenschaften definieren durch: Schemaplantypen; Analytische Konstruktion: <Keine Auswahl>
Bemaßungen - ArchHeight: 1.512 m; Breite: 2 m; Höhe: 4.176 m; MullionWidth: 0.0948571 m; OpeningWidth: 0.7395 m; OuterArchHeight: 2.5 m; PostWidth: 0.08 m; SetBack: 0.2 m; TraceryThickness: 0.25 m
ID-Daten - OmniClass-Nummer: 23.30.20.00; OmniClass-Titel: Windows; Typenmarkierung: 267; Typname: BellTowerOpening
Konstruktion - Wandabschluss: Nach Basisbauteil
Materialien und Oberflächen - LouvreMaterial: Holz - generisch 50-50-50; RevealMaterial: Mauerwerk - Sichtmauerwerk_72x265 english bond Stage2; TraceryMaterial: Mauerwerk - Sandstein Rot
Sonstige - Kategorie: Fenster; Familienname: BellTowerOpening; NoBlades: 30; Vorgabewert für Einbauhöhe: 0 m
Pset_WindowCommon - IsExternal: no

# IfcWindowStyle, no part of this type: QuoinArch:QuoinArch
ParameterTakesPrecedence: no; Sizeable: no; Material: Quoin Brick (240)
Analytische Eigenschaften - Thermische Eigenschaften definieren durch: Schemaplantypen; Analytische Konstruktion: <Keine Auswahl>
Bemaßungen - Breite: 4.2 m; GroupAngle: 1.61244 deg; Höhe: 3.485 m
ID-Daten - OmniClass-Nummer: 23.30.20.00; OmniClass-Titel: Windows; Typenmarkierung: 266; Typname: QuoinArch
Konstruktion - Wandabschluss: Nach Basisbauteil
Materialien und Oberflächen - QuoinMaterial: Quoin Brick
Sonstige - Kategorie: Fenster; Familienname: QuoinArch; Vorgabewert für Einbauhöhe: 0.85 m
Pset_WindowCommon - IsExternal: no
